VERSION 5.8 ;
BUSBITCHARS "[]" ;
DIVIDERCHAR "/" ;
UNITS
    DATABASE MICRONS 1000 ;
END UNITS

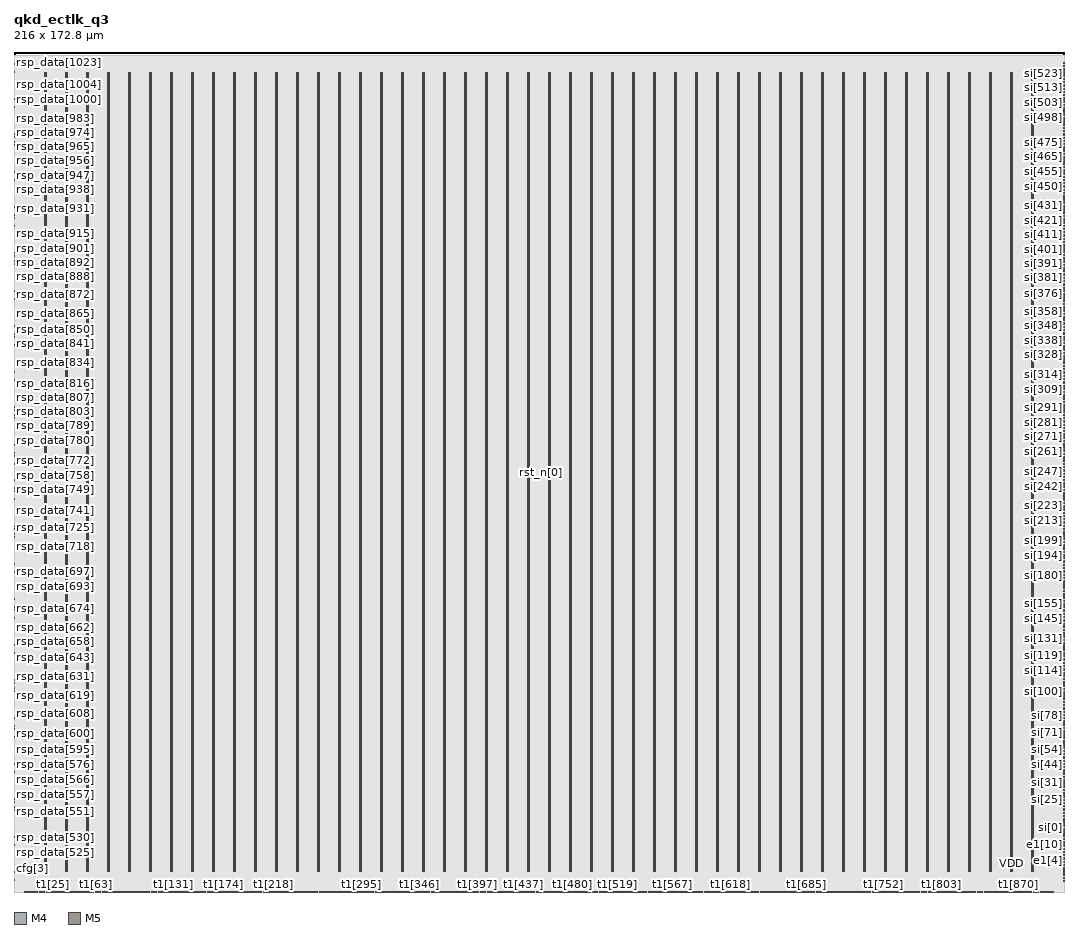
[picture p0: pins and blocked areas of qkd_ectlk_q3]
MACRO qkd_ectlk_q3
  FOREIGN qkd_ectlk_q3 0 0 ;
  CLASS BLOCK ;
  SIZE 216 BY 172.8 ;
  PIN cfg[0]
    DIRECTION INPUT ;
    USE SIGNAL ;
    PORT
      LAYER M4 ;
        RECT  0 2.172 0.192 2.196 ;
    END
  END cfg[0]
  PIN cfg[1]
    DIRECTION INPUT ;
    USE SIGNAL ;
    PORT
      LAYER M4 ;
        RECT  0 2.46 0.192 2.484 ;
    END
  END cfg[1]
  PIN cfg[2]
    DIRECTION INPUT ;
    USE SIGNAL ;
    PORT
      LAYER M4 ;
        RECT  0 2.796 0.192 2.82 ;
    END
  END cfg[2]
  PIN cfg[3]
    DIRECTION INPUT ;
    USE SIGNAL ;
    PORT
      LAYER M4 ;
        RECT  0 3.132 0.192 3.156 ;
    END
  END cfg[3]
  PIN cfg[4]
    DIRECTION INPUT ;
    USE SIGNAL ;
    PORT
      LAYER M4 ;
        RECT  0 3.468 0.192 3.492 ;
    END
  END cfg[4]
  PIN ck[0]
    DIRECTION INPUT ;
    USE SIGNAL ;
    PORT
      LAYER M5 ;
        RECT  108 86.16 108.048 86.64 ;
    END
  END ck[0]
  PIN e0[0]
    DIRECTION OUTPUT ;
    USE SIGNAL ;
    PORT
      LAYER M4 ;
        RECT  215.808 2.124 216 2.148 ;
    END
  END e0[0]
  PIN e0[10]
    DIRECTION OUTPUT ;
    USE SIGNAL ;
    PORT
      LAYER M4 ;
        RECT  215.808 5.1 216 5.124 ;
    END
  END e0[10]
  PIN e0[11]
    DIRECTION OUTPUT ;
    USE SIGNAL ;
    PORT
      LAYER M4 ;
        RECT  215.808 5.388 216 5.412 ;
    END
  END e0[11]
  PIN e0[12]
    DIRECTION OUTPUT ;
    USE SIGNAL ;
    PORT
      LAYER M4 ;
        RECT  215.808 5.676 216 5.7 ;
    END
  END e0[12]
  PIN e0[13]
    DIRECTION OUTPUT ;
    USE SIGNAL ;
    PORT
      LAYER M4 ;
        RECT  215.808 6.012 216 6.036 ;
    END
  END e0[13]
  PIN e0[14]
    DIRECTION OUTPUT ;
    USE SIGNAL ;
    PORT
      LAYER M4 ;
        RECT  215.808 6.3 216 6.324 ;
    END
  END e0[14]
  PIN e0[15]
    DIRECTION OUTPUT ;
    USE SIGNAL ;
    PORT
      LAYER M4 ;
        RECT  215.808 6.588 216 6.612 ;
    END
  END e0[15]
  PIN e0[1]
    DIRECTION OUTPUT ;
    USE SIGNAL ;
    PORT
      LAYER M4 ;
        RECT  215.808 2.412 216 2.436 ;
    END
  END e0[1]
  PIN e0[2]
    DIRECTION OUTPUT ;
    USE SIGNAL ;
    PORT
      LAYER M4 ;
        RECT  215.808 2.748 216 2.772 ;
    END
  END e0[2]
  PIN e0[3]
    DIRECTION OUTPUT ;
    USE SIGNAL ;
    PORT
      LAYER M4 ;
        RECT  215.808 3.036 216 3.06 ;
    END
  END e0[3]
  PIN e0[4]
    DIRECTION OUTPUT ;
    USE SIGNAL ;
    PORT
      LAYER M4 ;
        RECT  215.808 3.324 216 3.348 ;
    END
  END e0[4]
  PIN e0[5]
    DIRECTION OUTPUT ;
    USE SIGNAL ;
    PORT
      LAYER M4 ;
        RECT  215.808 3.612 216 3.636 ;
    END
  END e0[5]
  PIN e0[6]
    DIRECTION OUTPUT ;
    USE SIGNAL ;
    PORT
      LAYER M4 ;
        RECT  215.808 3.9 216 3.924 ;
    END
  END e0[6]
  PIN e0[7]
    DIRECTION OUTPUT ;
    USE SIGNAL ;
    PORT
      LAYER M4 ;
        RECT  215.808 4.236 216 4.26 ;
    END
  END e0[7]
  PIN e0[8]
    DIRECTION OUTPUT ;
    USE SIGNAL ;
    PORT
      LAYER M4 ;
        RECT  215.808 4.524 216 4.548 ;
    END
  END e0[8]
  PIN e0[9]
    DIRECTION OUTPUT ;
    USE SIGNAL ;
    PORT
      LAYER M4 ;
        RECT  215.808 4.812 216 4.836 ;
    END
  END e0[9]
  PIN e1[0]
    DIRECTION OUTPUT ;
    USE SIGNAL ;
    PORT
      LAYER M4 ;
        RECT  215.808 6.876 216 6.9 ;
    END
  END e1[0]
  PIN e1[10]
    DIRECTION OUTPUT ;
    USE SIGNAL ;
    PORT
      LAYER M4 ;
        RECT  215.808 9.852 216 9.876 ;
    END
  END e1[10]
  PIN e1[11]
    DIRECTION OUTPUT ;
    USE SIGNAL ;
    PORT
      LAYER M4 ;
        RECT  215.808 10.14 216 10.164 ;
    END
  END e1[11]
  PIN e1[12]
    DIRECTION OUTPUT ;
    USE SIGNAL ;
    PORT
      LAYER M4 ;
        RECT  215.808 10.428 216 10.452 ;
    END
  END e1[12]
  PIN e1[13]
    DIRECTION OUTPUT ;
    USE SIGNAL ;
    PORT
      LAYER M4 ;
        RECT  215.808 10.716 216 10.74 ;
    END
  END e1[13]
  PIN e1[14]
    DIRECTION OUTPUT ;
    USE SIGNAL ;
    PORT
      LAYER M4 ;
        RECT  215.808 11.052 216 11.076 ;
    END
  END e1[14]
  PIN e1[15]
    DIRECTION OUTPUT ;
    USE SIGNAL ;
    PORT
      LAYER M4 ;
        RECT  215.808 11.34 216 11.364 ;
    END
  END e1[15]
  PIN e1[1]
    DIRECTION OUTPUT ;
    USE SIGNAL ;
    PORT
      LAYER M4 ;
        RECT  215.808 7.164 216 7.188 ;
    END
  END e1[1]
  PIN e1[2]
    DIRECTION OUTPUT ;
    USE SIGNAL ;
    PORT
      LAYER M4 ;
        RECT  215.808 7.5 216 7.524 ;
    END
  END e1[2]
  PIN e1[3]
    DIRECTION OUTPUT ;
    USE SIGNAL ;
    PORT
      LAYER M4 ;
        RECT  215.808 7.788 216 7.812 ;
    END
  END e1[3]
  PIN e1[4]
    DIRECTION OUTPUT ;
    USE SIGNAL ;
    PORT
      LAYER M4 ;
        RECT  215.808 8.076 216 8.1 ;
    END
  END e1[4]
  PIN e1[5]
    DIRECTION OUTPUT ;
    USE SIGNAL ;
    PORT
      LAYER M4 ;
        RECT  215.808 8.364 216 8.388 ;
    END
  END e1[5]
  PIN e1[6]
    DIRECTION OUTPUT ;
    USE SIGNAL ;
    PORT
      LAYER M4 ;
        RECT  215.808 8.652 216 8.676 ;
    END
  END e1[6]
  PIN e1[7]
    DIRECTION OUTPUT ;
    USE SIGNAL ;
    PORT
      LAYER M4 ;
        RECT  215.808 8.94 216 8.964 ;
    END
  END e1[7]
  PIN e1[8]
    DIRECTION OUTPUT ;
    USE SIGNAL ;
    PORT
      LAYER M4 ;
        RECT  215.808 9.276 216 9.3 ;
    END
  END e1[8]
  PIN e1[9]
    DIRECTION OUTPUT ;
    USE SIGNAL ;
    PORT
      LAYER M4 ;
        RECT  215.808 9.564 216 9.588 ;
    END
  END e1[9]
  PIN rsp_data[1000]
    DIRECTION INPUT ;
    USE SIGNAL ;
    PORT
      LAYER M4 ;
        RECT  0 163.116 0.192 163.14 ;
    END
  END rsp_data[1000]
  PIN rsp_data[1001]
    DIRECTION INPUT ;
    USE SIGNAL ;
    PORT
      LAYER M4 ;
        RECT  0 163.452 0.192 163.476 ;
    END
  END rsp_data[1001]
  PIN rsp_data[1002]
    DIRECTION INPUT ;
    USE SIGNAL ;
    PORT
      LAYER M4 ;
        RECT  0 163.788 0.192 163.812 ;
    END
  END rsp_data[1002]
  PIN rsp_data[1003]
    DIRECTION INPUT ;
    USE SIGNAL ;
    PORT
      LAYER M4 ;
        RECT  0 164.076 0.192 164.1 ;
    END
  END rsp_data[1003]
  PIN rsp_data[1004]
    DIRECTION INPUT ;
    USE SIGNAL ;
    PORT
      LAYER M4 ;
        RECT  0 164.412 0.192 164.436 ;
    END
  END rsp_data[1004]
  PIN rsp_data[1005]
    DIRECTION INPUT ;
    USE SIGNAL ;
    PORT
      LAYER M4 ;
        RECT  0 164.748 0.192 164.772 ;
    END
  END rsp_data[1005]
  PIN rsp_data[1006]
    DIRECTION INPUT ;
    USE SIGNAL ;
    PORT
      LAYER M4 ;
        RECT  0 165.084 0.192 165.108 ;
    END
  END rsp_data[1006]
  PIN rsp_data[1007]
    DIRECTION INPUT ;
    USE SIGNAL ;
    PORT
      LAYER M4 ;
        RECT  0 165.42 0.192 165.444 ;
    END
  END rsp_data[1007]
  PIN rsp_data[1008]
    DIRECTION INPUT ;
    USE SIGNAL ;
    PORT
      LAYER M4 ;
        RECT  0 165.708 0.192 165.732 ;
    END
  END rsp_data[1008]
  PIN rsp_data[1009]
    DIRECTION INPUT ;
    USE SIGNAL ;
    PORT
      LAYER M4 ;
        RECT  0 166.044 0.192 166.068 ;
    END
  END rsp_data[1009]
  PIN rsp_data[1010]
    DIRECTION INPUT ;
    USE SIGNAL ;
    PORT
      LAYER M4 ;
        RECT  0 166.38 0.192 166.404 ;
    END
  END rsp_data[1010]
  PIN rsp_data[1011]
    DIRECTION INPUT ;
    USE SIGNAL ;
    PORT
      LAYER M4 ;
        RECT  0 166.716 0.192 166.74 ;
    END
  END rsp_data[1011]
  PIN rsp_data[1012]
    DIRECTION INPUT ;
    USE SIGNAL ;
    PORT
      LAYER M4 ;
        RECT  0 167.052 0.192 167.076 ;
    END
  END rsp_data[1012]
  PIN rsp_data[1013]
    DIRECTION INPUT ;
    USE SIGNAL ;
    PORT
      LAYER M4 ;
        RECT  0 167.34 0.192 167.364 ;
    END
  END rsp_data[1013]
  PIN rsp_data[1014]
    DIRECTION INPUT ;
    USE SIGNAL ;
    PORT
      LAYER M4 ;
        RECT  0 167.676 0.192 167.7 ;
    END
  END rsp_data[1014]
  PIN rsp_data[1015]
    DIRECTION INPUT ;
    USE SIGNAL ;
    PORT
      LAYER M4 ;
        RECT  0 168.012 0.192 168.036 ;
    END
  END rsp_data[1015]
  PIN rsp_data[1016]
    DIRECTION INPUT ;
    USE SIGNAL ;
    PORT
      LAYER M4 ;
        RECT  0 168.348 0.192 168.372 ;
    END
  END rsp_data[1016]
  PIN rsp_data[1017]
    DIRECTION INPUT ;
    USE SIGNAL ;
    PORT
      LAYER M4 ;
        RECT  0 168.684 0.192 168.708 ;
    END
  END rsp_data[1017]
  PIN rsp_data[1018]
    DIRECTION INPUT ;
    USE SIGNAL ;
    PORT
      LAYER M4 ;
        RECT  0 168.972 0.192 168.996 ;
    END
  END rsp_data[1018]
  PIN rsp_data[1019]
    DIRECTION INPUT ;
    USE SIGNAL ;
    PORT
      LAYER M4 ;
        RECT  0 169.308 0.192 169.332 ;
    END
  END rsp_data[1019]
  PIN rsp_data[1020]
    DIRECTION INPUT ;
    USE SIGNAL ;
    PORT
      LAYER M4 ;
        RECT  0 169.644 0.192 169.668 ;
    END
  END rsp_data[1020]
  PIN rsp_data[1021]
    DIRECTION INPUT ;
    USE SIGNAL ;
    PORT
      LAYER M4 ;
        RECT  0 169.98 0.192 170.004 ;
    END
  END rsp_data[1021]
  PIN rsp_data[1022]
    DIRECTION INPUT ;
    USE SIGNAL ;
    PORT
      LAYER M4 ;
        RECT  0 170.316 0.192 170.34 ;
    END
  END rsp_data[1022]
  PIN rsp_data[1023]
    DIRECTION INPUT ;
    USE SIGNAL ;
    PORT
      LAYER M4 ;
        RECT  0 170.604 0.192 170.628 ;
    END
  END rsp_data[1023]
  PIN rsp_data[512]
    DIRECTION INPUT ;
    USE SIGNAL ;
    PORT
      LAYER M4 ;
        RECT  0 3.804 0.192 3.828 ;
    END
  END rsp_data[512]
  PIN rsp_data[513]
    DIRECTION INPUT ;
    USE SIGNAL ;
    PORT
      LAYER M4 ;
        RECT  0 4.092 0.192 4.116 ;
    END
  END rsp_data[513]
  PIN rsp_data[514]
    DIRECTION INPUT ;
    USE SIGNAL ;
    PORT
      LAYER M4 ;
        RECT  0 4.428 0.192 4.452 ;
    END
  END rsp_data[514]
  PIN rsp_data[515]
    DIRECTION INPUT ;
    USE SIGNAL ;
    PORT
      LAYER M4 ;
        RECT  0 4.764 0.192 4.788 ;
    END
  END rsp_data[515]
  PIN rsp_data[516]
    DIRECTION INPUT ;
    USE SIGNAL ;
    PORT
      LAYER M4 ;
        RECT  0 5.1 0.192 5.124 ;
    END
  END rsp_data[516]
  PIN rsp_data[517]
    DIRECTION INPUT ;
    USE SIGNAL ;
    PORT
      LAYER M4 ;
        RECT  0 5.436 0.192 5.46 ;
    END
  END rsp_data[517]
  PIN rsp_data[518]
    DIRECTION INPUT ;
    USE SIGNAL ;
    PORT
      LAYER M4 ;
        RECT  0 5.724 0.192 5.748 ;
    END
  END rsp_data[518]
  PIN rsp_data[519]
    DIRECTION INPUT ;
    USE SIGNAL ;
    PORT
      LAYER M4 ;
        RECT  0 6.06 0.192 6.084 ;
    END
  END rsp_data[519]
  PIN rsp_data[520]
    DIRECTION INPUT ;
    USE SIGNAL ;
    PORT
      LAYER M4 ;
        RECT  0 6.396 0.192 6.42 ;
    END
  END rsp_data[520]
  PIN rsp_data[521]
    DIRECTION INPUT ;
    USE SIGNAL ;
    PORT
      LAYER M4 ;
        RECT  0 6.732 0.192 6.756 ;
    END
  END rsp_data[521]
  PIN rsp_data[522]
    DIRECTION INPUT ;
    USE SIGNAL ;
    PORT
      LAYER M4 ;
        RECT  0 7.068 0.192 7.092 ;
    END
  END rsp_data[522]
  PIN rsp_data[523]
    DIRECTION INPUT ;
    USE SIGNAL ;
    PORT
      LAYER M4 ;
        RECT  0 7.356 0.192 7.38 ;
    END
  END rsp_data[523]
  PIN rsp_data[524]
    DIRECTION INPUT ;
    USE SIGNAL ;
    PORT
      LAYER M4 ;
        RECT  0 7.692 0.192 7.716 ;
    END
  END rsp_data[524]
  PIN rsp_data[525]
    DIRECTION INPUT ;
    USE SIGNAL ;
    PORT
      LAYER M4 ;
        RECT  0 8.028 0.192 8.052 ;
    END
  END rsp_data[525]
  PIN rsp_data[526]
    DIRECTION INPUT ;
    USE SIGNAL ;
    PORT
      LAYER M4 ;
        RECT  0 8.364 0.192 8.388 ;
    END
  END rsp_data[526]
  PIN rsp_data[527]
    DIRECTION INPUT ;
    USE SIGNAL ;
    PORT
      LAYER M4 ;
        RECT  0 8.7 0.192 8.724 ;
    END
  END rsp_data[527]
  PIN rsp_data[528]
    DIRECTION INPUT ;
    USE SIGNAL ;
    PORT
      LAYER M4 ;
        RECT  0 8.988 0.192 9.012 ;
    END
  END rsp_data[528]
  PIN rsp_data[529]
    DIRECTION INPUT ;
    USE SIGNAL ;
    PORT
      LAYER M4 ;
        RECT  0 9.324 0.192 9.348 ;
    END
  END rsp_data[529]
  PIN rsp_data[530]
    DIRECTION INPUT ;
    USE SIGNAL ;
    PORT
      LAYER M4 ;
        RECT  0 9.66 0.192 9.684 ;
    END
  END rsp_data[530]
  PIN rsp_data[531]
    DIRECTION INPUT ;
    USE SIGNAL ;
    PORT
      LAYER M4 ;
        RECT  0 9.996 0.192 10.02 ;
    END
  END rsp_data[531]
  PIN rsp_data[532]
    DIRECTION INPUT ;
    USE SIGNAL ;
    PORT
      LAYER M4 ;
        RECT  0 10.332 0.192 10.356 ;
    END
  END rsp_data[532]
  PIN rsp_data[533]
    DIRECTION INPUT ;
    USE SIGNAL ;
    PORT
      LAYER M4 ;
        RECT  0 10.62 0.192 10.644 ;
    END
  END rsp_data[533]
  PIN rsp_data[534]
    DIRECTION INPUT ;
    USE SIGNAL ;
    PORT
      LAYER M4 ;
        RECT  0 10.956 0.192 10.98 ;
    END
  END rsp_data[534]
  PIN rsp_data[535]
    DIRECTION INPUT ;
    USE SIGNAL ;
    PORT
      LAYER M4 ;
        RECT  0 11.292 0.192 11.316 ;
    END
  END rsp_data[535]
  PIN rsp_data[536]
    DIRECTION INPUT ;
    USE SIGNAL ;
    PORT
      LAYER M4 ;
        RECT  0 11.628 0.192 11.652 ;
    END
  END rsp_data[536]
  PIN rsp_data[537]
    DIRECTION INPUT ;
    USE SIGNAL ;
    PORT
      LAYER M4 ;
        RECT  0 11.964 0.192 11.988 ;
    END
  END rsp_data[537]
  PIN rsp_data[538]
    DIRECTION INPUT ;
    USE SIGNAL ;
    PORT
      LAYER M4 ;
        RECT  0 12.252 0.192 12.276 ;
    END
  END rsp_data[538]
  PIN rsp_data[539]
    DIRECTION INPUT ;
    USE SIGNAL ;
    PORT
      LAYER M4 ;
        RECT  0 12.588 0.192 12.612 ;
    END
  END rsp_data[539]
  PIN rsp_data[540]
    DIRECTION INPUT ;
    USE SIGNAL ;
    PORT
      LAYER M4 ;
        RECT  0 12.924 0.192 12.948 ;
    END
  END rsp_data[540]
  PIN rsp_data[541]
    DIRECTION INPUT ;
    USE SIGNAL ;
    PORT
      LAYER M4 ;
        RECT  0 13.26 0.192 13.284 ;
    END
  END rsp_data[541]
  PIN rsp_data[542]
    DIRECTION INPUT ;
    USE SIGNAL ;
    PORT
      LAYER M4 ;
        RECT  0 13.596 0.192 13.62 ;
    END
  END rsp_data[542]
  PIN rsp_data[543]
    DIRECTION INPUT ;
    USE SIGNAL ;
    PORT
      LAYER M4 ;
        RECT  0 13.884 0.192 13.908 ;
    END
  END rsp_data[543]
  PIN rsp_data[544]
    DIRECTION INPUT ;
    USE SIGNAL ;
    PORT
      LAYER M4 ;
        RECT  0 14.22 0.192 14.244 ;
    END
  END rsp_data[544]
  PIN rsp_data[545]
    DIRECTION INPUT ;
    USE SIGNAL ;
    PORT
      LAYER M4 ;
        RECT  0 14.556 0.192 14.58 ;
    END
  END rsp_data[545]
  PIN rsp_data[546]
    DIRECTION INPUT ;
    USE SIGNAL ;
    PORT
      LAYER M4 ;
        RECT  0 14.892 0.192 14.916 ;
    END
  END rsp_data[546]
  PIN rsp_data[547]
    DIRECTION INPUT ;
    USE SIGNAL ;
    PORT
      LAYER M4 ;
        RECT  0 15.228 0.192 15.252 ;
    END
  END rsp_data[547]
  PIN rsp_data[548]
    DIRECTION INPUT ;
    USE SIGNAL ;
    PORT
      LAYER M4 ;
        RECT  0 15.516 0.192 15.54 ;
    END
  END rsp_data[548]
  PIN rsp_data[549]
    DIRECTION INPUT ;
    USE SIGNAL ;
    PORT
      LAYER M4 ;
        RECT  0 15.852 0.192 15.876 ;
    END
  END rsp_data[549]
  PIN rsp_data[550]
    DIRECTION INPUT ;
    USE SIGNAL ;
    PORT
      LAYER M4 ;
        RECT  0 16.188 0.192 16.212 ;
    END
  END rsp_data[550]
  PIN rsp_data[551]
    DIRECTION INPUT ;
    USE SIGNAL ;
    PORT
      LAYER M4 ;
        RECT  0 16.524 0.192 16.548 ;
    END
  END rsp_data[551]
  PIN rsp_data[552]
    DIRECTION INPUT ;
    USE SIGNAL ;
    PORT
      LAYER M4 ;
        RECT  0 16.86 0.192 16.884 ;
    END
  END rsp_data[552]
  PIN rsp_data[553]
    DIRECTION INPUT ;
    USE SIGNAL ;
    PORT
      LAYER M4 ;
        RECT  0 17.148 0.192 17.172 ;
    END
  END rsp_data[553]
  PIN rsp_data[554]
    DIRECTION INPUT ;
    USE SIGNAL ;
    PORT
      LAYER M4 ;
        RECT  0 17.484 0.192 17.508 ;
    END
  END rsp_data[554]
  PIN rsp_data[555]
    DIRECTION INPUT ;
    USE SIGNAL ;
    PORT
      LAYER M4 ;
        RECT  0 17.82 0.192 17.844 ;
    END
  END rsp_data[555]
  PIN rsp_data[556]
    DIRECTION INPUT ;
    USE SIGNAL ;
    PORT
      LAYER M4 ;
        RECT  0 18.156 0.192 18.18 ;
    END
  END rsp_data[556]
  PIN rsp_data[557]
    DIRECTION INPUT ;
    USE SIGNAL ;
    PORT
      LAYER M4 ;
        RECT  0 18.492 0.192 18.516 ;
    END
  END rsp_data[557]
  PIN rsp_data[558]
    DIRECTION INPUT ;
    USE SIGNAL ;
    PORT
      LAYER M4 ;
        RECT  0 18.78 0.192 18.804 ;
    END
  END rsp_data[558]
  PIN rsp_data[559]
    DIRECTION INPUT ;
    USE SIGNAL ;
    PORT
      LAYER M4 ;
        RECT  0 19.116 0.192 19.14 ;
    END
  END rsp_data[559]
  PIN rsp_data[560]
    DIRECTION INPUT ;
    USE SIGNAL ;
    PORT
      LAYER M4 ;
        RECT  0 19.452 0.192 19.476 ;
    END
  END rsp_data[560]
  PIN rsp_data[561]
    DIRECTION INPUT ;
    USE SIGNAL ;
    PORT
      LAYER M4 ;
        RECT  0 19.788 0.192 19.812 ;
    END
  END rsp_data[561]
  PIN rsp_data[562]
    DIRECTION INPUT ;
    USE SIGNAL ;
    PORT
      LAYER M4 ;
        RECT  0 20.124 0.192 20.148 ;
    END
  END rsp_data[562]
  PIN rsp_data[563]
    DIRECTION INPUT ;
    USE SIGNAL ;
    PORT
      LAYER M4 ;
        RECT  0 20.412 0.192 20.436 ;
    END
  END rsp_data[563]
  PIN rsp_data[564]
    DIRECTION INPUT ;
    USE SIGNAL ;
    PORT
      LAYER M4 ;
        RECT  0 20.748 0.192 20.772 ;
    END
  END rsp_data[564]
  PIN rsp_data[565]
    DIRECTION INPUT ;
    USE SIGNAL ;
    PORT
      LAYER M4 ;
        RECT  0 21.084 0.192 21.108 ;
    END
  END rsp_data[565]
  PIN rsp_data[566]
    DIRECTION INPUT ;
    USE SIGNAL ;
    PORT
      LAYER M4 ;
        RECT  0 21.42 0.192 21.444 ;
    END
  END rsp_data[566]
  PIN rsp_data[567]
    DIRECTION INPUT ;
    USE SIGNAL ;
    PORT
      LAYER M4 ;
        RECT  0 21.756 0.192 21.78 ;
    END
  END rsp_data[567]
  PIN rsp_data[568]
    DIRECTION INPUT ;
    USE SIGNAL ;
    PORT
      LAYER M4 ;
        RECT  0 22.044 0.192 22.068 ;
    END
  END rsp_data[568]
  PIN rsp_data[569]
    DIRECTION INPUT ;
    USE SIGNAL ;
    PORT
      LAYER M4 ;
        RECT  0 22.38 0.192 22.404 ;
    END
  END rsp_data[569]
  PIN rsp_data[570]
    DIRECTION INPUT ;
    USE SIGNAL ;
    PORT
      LAYER M4 ;
        RECT  0 22.716 0.192 22.74 ;
    END
  END rsp_data[570]
  PIN rsp_data[571]
    DIRECTION INPUT ;
    USE SIGNAL ;
    PORT
      LAYER M4 ;
        RECT  0 23.052 0.192 23.076 ;
    END
  END rsp_data[571]
  PIN rsp_data[572]
    DIRECTION INPUT ;
    USE SIGNAL ;
    PORT
      LAYER M4 ;
        RECT  0 23.388 0.192 23.412 ;
    END
  END rsp_data[572]
  PIN rsp_data[573]
    DIRECTION INPUT ;
    USE SIGNAL ;
    PORT
      LAYER M4 ;
        RECT  0 23.724 0.192 23.748 ;
    END
  END rsp_data[573]
  PIN rsp_data[574]
    DIRECTION INPUT ;
    USE SIGNAL ;
    PORT
      LAYER M4 ;
        RECT  0 24.012 0.192 24.036 ;
    END
  END rsp_data[574]
  PIN rsp_data[575]
    DIRECTION INPUT ;
    USE SIGNAL ;
    PORT
      LAYER M4 ;
        RECT  0 24.348 0.192 24.372 ;
    END
  END rsp_data[575]
  PIN rsp_data[576]
    DIRECTION INPUT ;
    USE SIGNAL ;
    PORT
      LAYER M4 ;
        RECT  0 24.684 0.192 24.708 ;
    END
  END rsp_data[576]
  PIN rsp_data[577]
    DIRECTION INPUT ;
    USE SIGNAL ;
    PORT
      LAYER M4 ;
        RECT  0 25.02 0.192 25.044 ;
    END
  END rsp_data[577]
  PIN rsp_data[578]
    DIRECTION INPUT ;
    USE SIGNAL ;
    PORT
      LAYER M4 ;
        RECT  0 25.356 0.192 25.38 ;
    END
  END rsp_data[578]
  PIN rsp_data[579]
    DIRECTION INPUT ;
    USE SIGNAL ;
    PORT
      LAYER M4 ;
        RECT  0 25.644 0.192 25.668 ;
    END
  END rsp_data[579]
  PIN rsp_data[580]
    DIRECTION INPUT ;
    USE SIGNAL ;
    PORT
      LAYER M4 ;
        RECT  0 25.98 0.192 26.004 ;
    END
  END rsp_data[580]
  PIN rsp_data[581]
    DIRECTION INPUT ;
    USE SIGNAL ;
    PORT
      LAYER M4 ;
        RECT  0 26.316 0.192 26.34 ;
    END
  END rsp_data[581]
  PIN rsp_data[582]
    DIRECTION INPUT ;
    USE SIGNAL ;
    PORT
      LAYER M4 ;
        RECT  0 26.652 0.192 26.676 ;
    END
  END rsp_data[582]
  PIN rsp_data[583]
    DIRECTION INPUT ;
    USE SIGNAL ;
    PORT
      LAYER M4 ;
        RECT  0 26.988 0.192 27.012 ;
    END
  END rsp_data[583]
  PIN rsp_data[584]
    DIRECTION INPUT ;
    USE SIGNAL ;
    PORT
      LAYER M4 ;
        RECT  0 27.276 0.192 27.3 ;
    END
  END rsp_data[584]
  PIN rsp_data[585]
    DIRECTION INPUT ;
    USE SIGNAL ;
    PORT
      LAYER M4 ;
        RECT  0 27.612 0.192 27.636 ;
    END
  END rsp_data[585]
  PIN rsp_data[586]
    DIRECTION INPUT ;
    USE SIGNAL ;
    PORT
      LAYER M4 ;
        RECT  0 27.948 0.192 27.972 ;
    END
  END rsp_data[586]
  PIN rsp_data[587]
    DIRECTION INPUT ;
    USE SIGNAL ;
    PORT
      LAYER M4 ;
        RECT  0 28.284 0.192 28.308 ;
    END
  END rsp_data[587]
  PIN rsp_data[588]
    DIRECTION INPUT ;
    USE SIGNAL ;
    PORT
      LAYER M4 ;
        RECT  0 28.62 0.192 28.644 ;
    END
  END rsp_data[588]
  PIN rsp_data[589]
    DIRECTION INPUT ;
    USE SIGNAL ;
    PORT
      LAYER M4 ;
        RECT  0 28.908 0.192 28.932 ;
    END
  END rsp_data[589]
  PIN rsp_data[590]
    DIRECTION INPUT ;
    USE SIGNAL ;
    PORT
      LAYER M4 ;
        RECT  0 29.244 0.192 29.268 ;
    END
  END rsp_data[590]
  PIN rsp_data[591]
    DIRECTION INPUT ;
    USE SIGNAL ;
    PORT
      LAYER M4 ;
        RECT  0 29.58 0.192 29.604 ;
    END
  END rsp_data[591]
  PIN rsp_data[592]
    DIRECTION INPUT ;
    USE SIGNAL ;
    PORT
      LAYER M4 ;
        RECT  0 29.916 0.192 29.94 ;
    END
  END rsp_data[592]
  PIN rsp_data[593]
    DIRECTION INPUT ;
    USE SIGNAL ;
    PORT
      LAYER M4 ;
        RECT  0 30.252 0.192 30.276 ;
    END
  END rsp_data[593]
  PIN rsp_data[594]
    DIRECTION INPUT ;
    USE SIGNAL ;
    PORT
      LAYER M4 ;
        RECT  0 30.54 0.192 30.564 ;
    END
  END rsp_data[594]
  PIN rsp_data[595]
    DIRECTION INPUT ;
    USE SIGNAL ;
    PORT
      LAYER M4 ;
        RECT  0 30.876 0.192 30.9 ;
    END
  END rsp_data[595]
  PIN rsp_data[596]
    DIRECTION INPUT ;
    USE SIGNAL ;
    PORT
      LAYER M4 ;
        RECT  0 31.212 0.192 31.236 ;
    END
  END rsp_data[596]
  PIN rsp_data[597]
    DIRECTION INPUT ;
    USE SIGNAL ;
    PORT
      LAYER M4 ;
        RECT  0 31.548 0.192 31.572 ;
    END
  END rsp_data[597]
  PIN rsp_data[598]
    DIRECTION INPUT ;
    USE SIGNAL ;
    PORT
      LAYER M4 ;
        RECT  0 31.884 0.192 31.908 ;
    END
  END rsp_data[598]
  PIN rsp_data[599]
    DIRECTION INPUT ;
    USE SIGNAL ;
    PORT
      LAYER M4 ;
        RECT  0 32.172 0.192 32.196 ;
    END
  END rsp_data[599]
  PIN rsp_data[600]
    DIRECTION INPUT ;
    USE SIGNAL ;
    PORT
      LAYER M4 ;
        RECT  0 32.508 0.192 32.532 ;
    END
  END rsp_data[600]
  PIN rsp_data[601]
    DIRECTION INPUT ;
    USE SIGNAL ;
    PORT
      LAYER M4 ;
        RECT  0 32.844 0.192 32.868 ;
    END
  END rsp_data[601]
  PIN rsp_data[602]
    DIRECTION INPUT ;
    USE SIGNAL ;
    PORT
      LAYER M4 ;
        RECT  0 33.18 0.192 33.204 ;
    END
  END rsp_data[602]
  PIN rsp_data[603]
    DIRECTION INPUT ;
    USE SIGNAL ;
    PORT
      LAYER M4 ;
        RECT  0 33.516 0.192 33.54 ;
    END
  END rsp_data[603]
  PIN rsp_data[604]
    DIRECTION INPUT ;
    USE SIGNAL ;
    PORT
      LAYER M4 ;
        RECT  0 33.804 0.192 33.828 ;
    END
  END rsp_data[604]
  PIN rsp_data[605]
    DIRECTION INPUT ;
    USE SIGNAL ;
    PORT
      LAYER M4 ;
        RECT  0 34.14 0.192 34.164 ;
    END
  END rsp_data[605]
  PIN rsp_data[606]
    DIRECTION INPUT ;
    USE SIGNAL ;
    PORT
      LAYER M4 ;
        RECT  0 34.476 0.192 34.5 ;
    END
  END rsp_data[606]
  PIN rsp_data[607]
    DIRECTION INPUT ;
    USE SIGNAL ;
    PORT
      LAYER M4 ;
        RECT  0 34.812 0.192 34.836 ;
    END
  END rsp_data[607]
  PIN rsp_data[608]
    DIRECTION INPUT ;
    USE SIGNAL ;
    PORT
      LAYER M4 ;
        RECT  0 35.148 0.192 35.172 ;
    END
  END rsp_data[608]
  PIN rsp_data[609]
    DIRECTION INPUT ;
    USE SIGNAL ;
    PORT
      LAYER M4 ;
        RECT  0 35.436 0.192 35.46 ;
    END
  END rsp_data[609]
  PIN rsp_data[610]
    DIRECTION INPUT ;
    USE SIGNAL ;
    PORT
      LAYER M4 ;
        RECT  0 35.772 0.192 35.796 ;
    END
  END rsp_data[610]
  PIN rsp_data[611]
    DIRECTION INPUT ;
    USE SIGNAL ;
    PORT
      LAYER M4 ;
        RECT  0 36.108 0.192 36.132 ;
    END
  END rsp_data[611]
  PIN rsp_data[612]
    DIRECTION INPUT ;
    USE SIGNAL ;
    PORT
      LAYER M4 ;
        RECT  0 36.444 0.192 36.468 ;
    END
  END rsp_data[612]
  PIN rsp_data[613]
    DIRECTION INPUT ;
    USE SIGNAL ;
    PORT
      LAYER M4 ;
        RECT  0 36.78 0.192 36.804 ;
    END
  END rsp_data[613]
  PIN rsp_data[614]
    DIRECTION INPUT ;
    USE SIGNAL ;
    PORT
      LAYER M4 ;
        RECT  0 37.068 0.192 37.092 ;
    END
  END rsp_data[614]
  PIN rsp_data[615]
    DIRECTION INPUT ;
    USE SIGNAL ;
    PORT
      LAYER M4 ;
        RECT  0 37.404 0.192 37.428 ;
    END
  END rsp_data[615]
  PIN rsp_data[616]
    DIRECTION INPUT ;
    USE SIGNAL ;
    PORT
      LAYER M4 ;
        RECT  0 37.74 0.192 37.764 ;
    END
  END rsp_data[616]
  PIN rsp_data[617]
    DIRECTION INPUT ;
    USE SIGNAL ;
    PORT
      LAYER M4 ;
        RECT  0 38.076 0.192 38.1 ;
    END
  END rsp_data[617]
  PIN rsp_data[618]
    DIRECTION INPUT ;
    USE SIGNAL ;
    PORT
      LAYER M4 ;
        RECT  0 38.412 0.192 38.436 ;
    END
  END rsp_data[618]
  PIN rsp_data[619]
    DIRECTION INPUT ;
    USE SIGNAL ;
    PORT
      LAYER M4 ;
        RECT  0 38.7 0.192 38.724 ;
    END
  END rsp_data[619]
  PIN rsp_data[620]
    DIRECTION INPUT ;
    USE SIGNAL ;
    PORT
      LAYER M4 ;
        RECT  0 39.036 0.192 39.06 ;
    END
  END rsp_data[620]
  PIN rsp_data[621]
    DIRECTION INPUT ;
    USE SIGNAL ;
    PORT
      LAYER M4 ;
        RECT  0 39.372 0.192 39.396 ;
    END
  END rsp_data[621]
  PIN rsp_data[622]
    DIRECTION INPUT ;
    USE SIGNAL ;
    PORT
      LAYER M4 ;
        RECT  0 39.708 0.192 39.732 ;
    END
  END rsp_data[622]
  PIN rsp_data[623]
    DIRECTION INPUT ;
    USE SIGNAL ;
    PORT
      LAYER M4 ;
        RECT  0 40.044 0.192 40.068 ;
    END
  END rsp_data[623]
  PIN rsp_data[624]
    DIRECTION INPUT ;
    USE SIGNAL ;
    PORT
      LAYER M4 ;
        RECT  0 40.332 0.192 40.356 ;
    END
  END rsp_data[624]
  PIN rsp_data[625]
    DIRECTION INPUT ;
    USE SIGNAL ;
    PORT
      LAYER M4 ;
        RECT  0 40.668 0.192 40.692 ;
    END
  END rsp_data[625]
  PIN rsp_data[626]
    DIRECTION INPUT ;
    USE SIGNAL ;
    PORT
      LAYER M4 ;
        RECT  0 41.004 0.192 41.028 ;
    END
  END rsp_data[626]
  PIN rsp_data[627]
    DIRECTION INPUT ;
    USE SIGNAL ;
    PORT
      LAYER M4 ;
        RECT  0 41.34 0.192 41.364 ;
    END
  END rsp_data[627]
  PIN rsp_data[628]
    DIRECTION INPUT ;
    USE SIGNAL ;
    PORT
      LAYER M4 ;
        RECT  0 41.676 0.192 41.7 ;
    END
  END rsp_data[628]
  PIN rsp_data[629]
    DIRECTION INPUT ;
    USE SIGNAL ;
    PORT
      LAYER M4 ;
        RECT  0 41.964 0.192 41.988 ;
    END
  END rsp_data[629]
  PIN rsp_data[630]
    DIRECTION INPUT ;
    USE SIGNAL ;
    PORT
      LAYER M4 ;
        RECT  0 42.3 0.192 42.324 ;
    END
  END rsp_data[630]
  PIN rsp_data[631]
    DIRECTION INPUT ;
    USE SIGNAL ;
    PORT
      LAYER M4 ;
        RECT  0 42.636 0.192 42.66 ;
    END
  END rsp_data[631]
  PIN rsp_data[632]
    DIRECTION INPUT ;
    USE SIGNAL ;
    PORT
      LAYER M4 ;
        RECT  0 42.972 0.192 42.996 ;
    END
  END rsp_data[632]
  PIN rsp_data[633]
    DIRECTION INPUT ;
    USE SIGNAL ;
    PORT
      LAYER M4 ;
        RECT  0 43.308 0.192 43.332 ;
    END
  END rsp_data[633]
  PIN rsp_data[634]
    DIRECTION INPUT ;
    USE SIGNAL ;
    PORT
      LAYER M4 ;
        RECT  0 43.596 0.192 43.62 ;
    END
  END rsp_data[634]
  PIN rsp_data[635]
    DIRECTION INPUT ;
    USE SIGNAL ;
    PORT
      LAYER M4 ;
        RECT  0 43.932 0.192 43.956 ;
    END
  END rsp_data[635]
  PIN rsp_data[636]
    DIRECTION INPUT ;
    USE SIGNAL ;
    PORT
      LAYER M4 ;
        RECT  0 44.268 0.192 44.292 ;
    END
  END rsp_data[636]
  PIN rsp_data[637]
    DIRECTION INPUT ;
    USE SIGNAL ;
    PORT
      LAYER M4 ;
        RECT  0 44.604 0.192 44.628 ;
    END
  END rsp_data[637]
  PIN rsp_data[638]
    DIRECTION INPUT ;
    USE SIGNAL ;
    PORT
      LAYER M4 ;
        RECT  0 44.94 0.192 44.964 ;
    END
  END rsp_data[638]
  PIN rsp_data[639]
    DIRECTION INPUT ;
    USE SIGNAL ;
    PORT
      LAYER M4 ;
        RECT  0 45.228 0.192 45.252 ;
    END
  END rsp_data[639]
  PIN rsp_data[640]
    DIRECTION INPUT ;
    USE SIGNAL ;
    PORT
      LAYER M4 ;
        RECT  0 45.564 0.192 45.588 ;
    END
  END rsp_data[640]
  PIN rsp_data[641]
    DIRECTION INPUT ;
    USE SIGNAL ;
    PORT
      LAYER M4 ;
        RECT  0 45.9 0.192 45.924 ;
    END
  END rsp_data[641]
  PIN rsp_data[642]
    DIRECTION INPUT ;
    USE SIGNAL ;
    PORT
      LAYER M4 ;
        RECT  0 46.236 0.192 46.26 ;
    END
  END rsp_data[642]
  PIN rsp_data[643]
    DIRECTION INPUT ;
    USE SIGNAL ;
    PORT
      LAYER M4 ;
        RECT  0 46.572 0.192 46.596 ;
    END
  END rsp_data[643]
  PIN rsp_data[644]
    DIRECTION INPUT ;
    USE SIGNAL ;
    PORT
      LAYER M4 ;
        RECT  0 46.86 0.192 46.884 ;
    END
  END rsp_data[644]
  PIN rsp_data[645]
    DIRECTION INPUT ;
    USE SIGNAL ;
    PORT
      LAYER M4 ;
        RECT  0 47.196 0.192 47.22 ;
    END
  END rsp_data[645]
  PIN rsp_data[646]
    DIRECTION INPUT ;
    USE SIGNAL ;
    PORT
      LAYER M4 ;
        RECT  0 47.532 0.192 47.556 ;
    END
  END rsp_data[646]
  PIN rsp_data[647]
    DIRECTION INPUT ;
    USE SIGNAL ;
    PORT
      LAYER M4 ;
        RECT  0 47.868 0.192 47.892 ;
    END
  END rsp_data[647]
  PIN rsp_data[648]
    DIRECTION INPUT ;
    USE SIGNAL ;
    PORT
      LAYER M4 ;
        RECT  0 48.204 0.192 48.228 ;
    END
  END rsp_data[648]
  PIN rsp_data[649]
    DIRECTION INPUT ;
    USE SIGNAL ;
    PORT
      LAYER M4 ;
        RECT  0 48.492 0.192 48.516 ;
    END
  END rsp_data[649]
  PIN rsp_data[650]
    DIRECTION INPUT ;
    USE SIGNAL ;
    PORT
      LAYER M4 ;
        RECT  0 48.828 0.192 48.852 ;
    END
  END rsp_data[650]
  PIN rsp_data[651]
    DIRECTION INPUT ;
    USE SIGNAL ;
    PORT
      LAYER M4 ;
        RECT  0 49.164 0.192 49.188 ;
    END
  END rsp_data[651]
  PIN rsp_data[652]
    DIRECTION INPUT ;
    USE SIGNAL ;
    PORT
      LAYER M4 ;
        RECT  0 49.5 0.192 49.524 ;
    END
  END rsp_data[652]
  PIN rsp_data[653]
    DIRECTION INPUT ;
    USE SIGNAL ;
    PORT
      LAYER M4 ;
        RECT  0 49.836 0.192 49.86 ;
    END
  END rsp_data[653]
  PIN rsp_data[654]
    DIRECTION INPUT ;
    USE SIGNAL ;
    PORT
      LAYER M4 ;
        RECT  0 50.124 0.192 50.148 ;
    END
  END rsp_data[654]
  PIN rsp_data[655]
    DIRECTION INPUT ;
    USE SIGNAL ;
    PORT
      LAYER M4 ;
        RECT  0 50.46 0.192 50.484 ;
    END
  END rsp_data[655]
  PIN rsp_data[656]
    DIRECTION INPUT ;
    USE SIGNAL ;
    PORT
      LAYER M4 ;
        RECT  0 50.796 0.192 50.82 ;
    END
  END rsp_data[656]
  PIN rsp_data[657]
    DIRECTION INPUT ;
    USE SIGNAL ;
    PORT
      LAYER M4 ;
        RECT  0 51.132 0.192 51.156 ;
    END
  END rsp_data[657]
  PIN rsp_data[658]
    DIRECTION INPUT ;
    USE SIGNAL ;
    PORT
      LAYER M4 ;
        RECT  0 51.468 0.192 51.492 ;
    END
  END rsp_data[658]
  PIN rsp_data[659]
    DIRECTION INPUT ;
    USE SIGNAL ;
    PORT
      LAYER M4 ;
        RECT  0 51.756 0.192 51.78 ;
    END
  END rsp_data[659]
  PIN rsp_data[660]
    DIRECTION INPUT ;
    USE SIGNAL ;
    PORT
      LAYER M4 ;
        RECT  0 52.092 0.192 52.116 ;
    END
  END rsp_data[660]
  PIN rsp_data[661]
    DIRECTION INPUT ;
    USE SIGNAL ;
    PORT
      LAYER M4 ;
        RECT  0 52.428 0.192 52.452 ;
    END
  END rsp_data[661]
  PIN rsp_data[662]
    DIRECTION INPUT ;
    USE SIGNAL ;
    PORT
      LAYER M4 ;
        RECT  0 52.764 0.192 52.788 ;
    END
  END rsp_data[662]
  PIN rsp_data[663]
    DIRECTION INPUT ;
    USE SIGNAL ;
    PORT
      LAYER M4 ;
        RECT  0 53.1 0.192 53.124 ;
    END
  END rsp_data[663]
  PIN rsp_data[664]
    DIRECTION INPUT ;
    USE SIGNAL ;
    PORT
      LAYER M4 ;
        RECT  0 53.388 0.192 53.412 ;
    END
  END rsp_data[664]
  PIN rsp_data[665]
    DIRECTION INPUT ;
    USE SIGNAL ;
    PORT
      LAYER M4 ;
        RECT  0 53.724 0.192 53.748 ;
    END
  END rsp_data[665]
  PIN rsp_data[666]
    DIRECTION INPUT ;
    USE SIGNAL ;
    PORT
      LAYER M4 ;
        RECT  0 54.06 0.192 54.084 ;
    END
  END rsp_data[666]
  PIN rsp_data[667]
    DIRECTION INPUT ;
    USE SIGNAL ;
    PORT
      LAYER M4 ;
        RECT  0 54.396 0.192 54.42 ;
    END
  END rsp_data[667]
  PIN rsp_data[668]
    DIRECTION INPUT ;
    USE SIGNAL ;
    PORT
      LAYER M4 ;
        RECT  0 54.732 0.192 54.756 ;
    END
  END rsp_data[668]
  PIN rsp_data[669]
    DIRECTION INPUT ;
    USE SIGNAL ;
    PORT
      LAYER M4 ;
        RECT  0 55.068 0.192 55.092 ;
    END
  END rsp_data[669]
  PIN rsp_data[670]
    DIRECTION INPUT ;
    USE SIGNAL ;
    PORT
      LAYER M4 ;
        RECT  0 55.356 0.192 55.38 ;
    END
  END rsp_data[670]
  PIN rsp_data[671]
    DIRECTION INPUT ;
    USE SIGNAL ;
    PORT
      LAYER M4 ;
        RECT  0 55.692 0.192 55.716 ;
    END
  END rsp_data[671]
  PIN rsp_data[672]
    DIRECTION INPUT ;
    USE SIGNAL ;
    PORT
      LAYER M4 ;
        RECT  0 56.028 0.192 56.052 ;
    END
  END rsp_data[672]
  PIN rsp_data[673]
    DIRECTION INPUT ;
    USE SIGNAL ;
    PORT
      LAYER M4 ;
        RECT  0 56.364 0.192 56.388 ;
    END
  END rsp_data[673]
  PIN rsp_data[674]
    DIRECTION INPUT ;
    USE SIGNAL ;
    PORT
      LAYER M4 ;
        RECT  0 56.7 0.192 56.724 ;
    END
  END rsp_data[674]
  PIN rsp_data[675]
    DIRECTION INPUT ;
    USE SIGNAL ;
    PORT
      LAYER M4 ;
        RECT  0 56.988 0.192 57.012 ;
    END
  END rsp_data[675]
  PIN rsp_data[676]
    DIRECTION INPUT ;
    USE SIGNAL ;
    PORT
      LAYER M4 ;
        RECT  0 57.324 0.192 57.348 ;
    END
  END rsp_data[676]
  PIN rsp_data[677]
    DIRECTION INPUT ;
    USE SIGNAL ;
    PORT
      LAYER M4 ;
        RECT  0 57.66 0.192 57.684 ;
    END
  END rsp_data[677]
  PIN rsp_data[678]
    DIRECTION INPUT ;
    USE SIGNAL ;
    PORT
      LAYER M4 ;
        RECT  0 57.996 0.192 58.02 ;
    END
  END rsp_data[678]
  PIN rsp_data[679]
    DIRECTION INPUT ;
    USE SIGNAL ;
    PORT
      LAYER M4 ;
        RECT  0 58.332 0.192 58.356 ;
    END
  END rsp_data[679]
  PIN rsp_data[680]
    DIRECTION INPUT ;
    USE SIGNAL ;
    PORT
      LAYER M4 ;
        RECT  0 58.62 0.192 58.644 ;
    END
  END rsp_data[680]
  PIN rsp_data[681]
    DIRECTION INPUT ;
    USE SIGNAL ;
    PORT
      LAYER M4 ;
        RECT  0 58.956 0.192 58.98 ;
    END
  END rsp_data[681]
  PIN rsp_data[682]
    DIRECTION INPUT ;
    USE SIGNAL ;
    PORT
      LAYER M4 ;
        RECT  0 59.292 0.192 59.316 ;
    END
  END rsp_data[682]
  PIN rsp_data[683]
    DIRECTION INPUT ;
    USE SIGNAL ;
    PORT
      LAYER M4 ;
        RECT  0 59.628 0.192 59.652 ;
    END
  END rsp_data[683]
  PIN rsp_data[684]
    DIRECTION INPUT ;
    USE SIGNAL ;
    PORT
      LAYER M4 ;
        RECT  0 59.964 0.192 59.988 ;
    END
  END rsp_data[684]
  PIN rsp_data[685]
    DIRECTION INPUT ;
    USE SIGNAL ;
    PORT
      LAYER M4 ;
        RECT  0 60.252 0.192 60.276 ;
    END
  END rsp_data[685]
  PIN rsp_data[686]
    DIRECTION INPUT ;
    USE SIGNAL ;
    PORT
      LAYER M4 ;
        RECT  0 60.588 0.192 60.612 ;
    END
  END rsp_data[686]
  PIN rsp_data[687]
    DIRECTION INPUT ;
    USE SIGNAL ;
    PORT
      LAYER M4 ;
        RECT  0 60.924 0.192 60.948 ;
    END
  END rsp_data[687]
  PIN rsp_data[688]
    DIRECTION INPUT ;
    USE SIGNAL ;
    PORT
      LAYER M4 ;
        RECT  0 61.26 0.192 61.284 ;
    END
  END rsp_data[688]
  PIN rsp_data[689]
    DIRECTION INPUT ;
    USE SIGNAL ;
    PORT
      LAYER M4 ;
        RECT  0 61.596 0.192 61.62 ;
    END
  END rsp_data[689]
  PIN rsp_data[690]
    DIRECTION INPUT ;
    USE SIGNAL ;
    PORT
      LAYER M4 ;
        RECT  0 61.884 0.192 61.908 ;
    END
  END rsp_data[690]
  PIN rsp_data[691]
    DIRECTION INPUT ;
    USE SIGNAL ;
    PORT
      LAYER M4 ;
        RECT  0 62.22 0.192 62.244 ;
    END
  END rsp_data[691]
  PIN rsp_data[692]
    DIRECTION INPUT ;
    USE SIGNAL ;
    PORT
      LAYER M4 ;
        RECT  0 62.556 0.192 62.58 ;
    END
  END rsp_data[692]
  PIN rsp_data[693]
    DIRECTION INPUT ;
    USE SIGNAL ;
    PORT
      LAYER M4 ;
        RECT  0 62.892 0.192 62.916 ;
    END
  END rsp_data[693]
  PIN rsp_data[694]
    DIRECTION INPUT ;
    USE SIGNAL ;
    PORT
      LAYER M4 ;
        RECT  0 63.228 0.192 63.252 ;
    END
  END rsp_data[694]
  PIN rsp_data[695]
    DIRECTION INPUT ;
    USE SIGNAL ;
    PORT
      LAYER M4 ;
        RECT  0 63.516 0.192 63.54 ;
    END
  END rsp_data[695]
  PIN rsp_data[696]
    DIRECTION INPUT ;
    USE SIGNAL ;
    PORT
      LAYER M4 ;
        RECT  0 63.852 0.192 63.876 ;
    END
  END rsp_data[696]
  PIN rsp_data[697]
    DIRECTION INPUT ;
    USE SIGNAL ;
    PORT
      LAYER M4 ;
        RECT  0 64.188 0.192 64.212 ;
    END
  END rsp_data[697]
  PIN rsp_data[698]
    DIRECTION INPUT ;
    USE SIGNAL ;
    PORT
      LAYER M4 ;
        RECT  0 64.524 0.192 64.548 ;
    END
  END rsp_data[698]
  PIN rsp_data[699]
    DIRECTION INPUT ;
    USE SIGNAL ;
    PORT
      LAYER M4 ;
        RECT  0 64.86 0.192 64.884 ;
    END
  END rsp_data[699]
  PIN rsp_data[700]
    DIRECTION INPUT ;
    USE SIGNAL ;
    PORT
      LAYER M4 ;
        RECT  0 65.148 0.192 65.172 ;
    END
  END rsp_data[700]
  PIN rsp_data[701]
    DIRECTION INPUT ;
    USE SIGNAL ;
    PORT
      LAYER M4 ;
        RECT  0 65.484 0.192 65.508 ;
    END
  END rsp_data[701]
  PIN rsp_data[702]
    DIRECTION INPUT ;
    USE SIGNAL ;
    PORT
      LAYER M4 ;
        RECT  0 65.82 0.192 65.844 ;
    END
  END rsp_data[702]
  PIN rsp_data[703]
    DIRECTION INPUT ;
    USE SIGNAL ;
    PORT
      LAYER M4 ;
        RECT  0 66.156 0.192 66.18 ;
    END
  END rsp_data[703]
  PIN rsp_data[704]
    DIRECTION INPUT ;
    USE SIGNAL ;
    PORT
      LAYER M4 ;
        RECT  0 66.492 0.192 66.516 ;
    END
  END rsp_data[704]
  PIN rsp_data[705]
    DIRECTION INPUT ;
    USE SIGNAL ;
    PORT
      LAYER M4 ;
        RECT  0 66.78 0.192 66.804 ;
    END
  END rsp_data[705]
  PIN rsp_data[706]
    DIRECTION INPUT ;
    USE SIGNAL ;
    PORT
      LAYER M4 ;
        RECT  0 67.116 0.192 67.14 ;
    END
  END rsp_data[706]
  PIN rsp_data[707]
    DIRECTION INPUT ;
    USE SIGNAL ;
    PORT
      LAYER M4 ;
        RECT  0 67.452 0.192 67.476 ;
    END
  END rsp_data[707]
  PIN rsp_data[708]
    DIRECTION INPUT ;
    USE SIGNAL ;
    PORT
      LAYER M4 ;
        RECT  0 67.788 0.192 67.812 ;
    END
  END rsp_data[708]
  PIN rsp_data[709]
    DIRECTION INPUT ;
    USE SIGNAL ;
    PORT
      LAYER M4 ;
        RECT  0 68.124 0.192 68.148 ;
    END
  END rsp_data[709]
  PIN rsp_data[710]
    DIRECTION INPUT ;
    USE SIGNAL ;
    PORT
      LAYER M4 ;
        RECT  0 68.412 0.192 68.436 ;
    END
  END rsp_data[710]
  PIN rsp_data[711]
    DIRECTION INPUT ;
    USE SIGNAL ;
    PORT
      LAYER M4 ;
        RECT  0 68.748 0.192 68.772 ;
    END
  END rsp_data[711]
  PIN rsp_data[712]
    DIRECTION INPUT ;
    USE SIGNAL ;
    PORT
      LAYER M4 ;
        RECT  0 69.084 0.192 69.108 ;
    END
  END rsp_data[712]
  PIN rsp_data[713]
    DIRECTION INPUT ;
    USE SIGNAL ;
    PORT
      LAYER M4 ;
        RECT  0 69.42 0.192 69.444 ;
    END
  END rsp_data[713]
  PIN rsp_data[714]
    DIRECTION INPUT ;
    USE SIGNAL ;
    PORT
      LAYER M4 ;
        RECT  0 69.756 0.192 69.78 ;
    END
  END rsp_data[714]
  PIN rsp_data[715]
    DIRECTION INPUT ;
    USE SIGNAL ;
    PORT
      LAYER M4 ;
        RECT  0 70.044 0.192 70.068 ;
    END
  END rsp_data[715]
  PIN rsp_data[716]
    DIRECTION INPUT ;
    USE SIGNAL ;
    PORT
      LAYER M4 ;
        RECT  0 70.38 0.192 70.404 ;
    END
  END rsp_data[716]
  PIN rsp_data[717]
    DIRECTION INPUT ;
    USE SIGNAL ;
    PORT
      LAYER M4 ;
        RECT  0 70.716 0.192 70.74 ;
    END
  END rsp_data[717]
  PIN rsp_data[718]
    DIRECTION INPUT ;
    USE SIGNAL ;
    PORT
      LAYER M4 ;
        RECT  0 71.052 0.192 71.076 ;
    END
  END rsp_data[718]
  PIN rsp_data[719]
    DIRECTION INPUT ;
    USE SIGNAL ;
    PORT
      LAYER M4 ;
        RECT  0 71.388 0.192 71.412 ;
    END
  END rsp_data[719]
  PIN rsp_data[720]
    DIRECTION INPUT ;
    USE SIGNAL ;
    PORT
      LAYER M4 ;
        RECT  0 71.676 0.192 71.7 ;
    END
  END rsp_data[720]
  PIN rsp_data[721]
    DIRECTION INPUT ;
    USE SIGNAL ;
    PORT
      LAYER M4 ;
        RECT  0 72.012 0.192 72.036 ;
    END
  END rsp_data[721]
  PIN rsp_data[722]
    DIRECTION INPUT ;
    USE SIGNAL ;
    PORT
      LAYER M4 ;
        RECT  0 72.348 0.192 72.372 ;
    END
  END rsp_data[722]
  PIN rsp_data[723]
    DIRECTION INPUT ;
    USE SIGNAL ;
    PORT
      LAYER M4 ;
        RECT  0 72.684 0.192 72.708 ;
    END
  END rsp_data[723]
  PIN rsp_data[724]
    DIRECTION INPUT ;
    USE SIGNAL ;
    PORT
      LAYER M4 ;
        RECT  0 73.02 0.192 73.044 ;
    END
  END rsp_data[724]
  PIN rsp_data[725]
    DIRECTION INPUT ;
    USE SIGNAL ;
    PORT
      LAYER M4 ;
        RECT  0 73.308 0.192 73.332 ;
    END
  END rsp_data[725]
  PIN rsp_data[726]
    DIRECTION INPUT ;
    USE SIGNAL ;
    PORT
      LAYER M4 ;
        RECT  0 73.644 0.192 73.668 ;
    END
  END rsp_data[726]
  PIN rsp_data[727]
    DIRECTION INPUT ;
    USE SIGNAL ;
    PORT
      LAYER M4 ;
        RECT  0 73.98 0.192 74.004 ;
    END
  END rsp_data[727]
  PIN rsp_data[728]
    DIRECTION INPUT ;
    USE SIGNAL ;
    PORT
      LAYER M4 ;
        RECT  0 74.316 0.192 74.34 ;
    END
  END rsp_data[728]
  PIN rsp_data[729]
    DIRECTION INPUT ;
    USE SIGNAL ;
    PORT
      LAYER M4 ;
        RECT  0 74.652 0.192 74.676 ;
    END
  END rsp_data[729]
  PIN rsp_data[730]
    DIRECTION INPUT ;
    USE SIGNAL ;
    PORT
      LAYER M4 ;
        RECT  0 74.94 0.192 74.964 ;
    END
  END rsp_data[730]
  PIN rsp_data[731]
    DIRECTION INPUT ;
    USE SIGNAL ;
    PORT
      LAYER M4 ;
        RECT  0 75.276 0.192 75.3 ;
    END
  END rsp_data[731]
  PIN rsp_data[732]
    DIRECTION INPUT ;
    USE SIGNAL ;
    PORT
      LAYER M4 ;
        RECT  0 75.612 0.192 75.636 ;
    END
  END rsp_data[732]
  PIN rsp_data[733]
    DIRECTION INPUT ;
    USE SIGNAL ;
    PORT
      LAYER M4 ;
        RECT  0 75.948 0.192 75.972 ;
    END
  END rsp_data[733]
  PIN rsp_data[734]
    DIRECTION INPUT ;
    USE SIGNAL ;
    PORT
      LAYER M4 ;
        RECT  0 76.284 0.192 76.308 ;
    END
  END rsp_data[734]
  PIN rsp_data[735]
    DIRECTION INPUT ;
    USE SIGNAL ;
    PORT
      LAYER M4 ;
        RECT  0 76.572 0.192 76.596 ;
    END
  END rsp_data[735]
  PIN rsp_data[736]
    DIRECTION INPUT ;
    USE SIGNAL ;
    PORT
      LAYER M4 ;
        RECT  0 76.908 0.192 76.932 ;
    END
  END rsp_data[736]
  PIN rsp_data[737]
    DIRECTION INPUT ;
    USE SIGNAL ;
    PORT
      LAYER M4 ;
        RECT  0 77.244 0.192 77.268 ;
    END
  END rsp_data[737]
  PIN rsp_data[738]
    DIRECTION INPUT ;
    USE SIGNAL ;
    PORT
      LAYER M4 ;
        RECT  0 77.58 0.192 77.604 ;
    END
  END rsp_data[738]
  PIN rsp_data[739]
    DIRECTION INPUT ;
    USE SIGNAL ;
    PORT
      LAYER M4 ;
        RECT  0 77.916 0.192 77.94 ;
    END
  END rsp_data[739]
  PIN rsp_data[740]
    DIRECTION INPUT ;
    USE SIGNAL ;
    PORT
      LAYER M4 ;
        RECT  0 78.204 0.192 78.228 ;
    END
  END rsp_data[740]
  PIN rsp_data[741]
    DIRECTION INPUT ;
    USE SIGNAL ;
    PORT
      LAYER M4 ;
        RECT  0 78.54 0.192 78.564 ;
    END
  END rsp_data[741]
  PIN rsp_data[742]
    DIRECTION INPUT ;
    USE SIGNAL ;
    PORT
      LAYER M4 ;
        RECT  0 78.876 0.192 78.9 ;
    END
  END rsp_data[742]
  PIN rsp_data[743]
    DIRECTION INPUT ;
    USE SIGNAL ;
    PORT
      LAYER M4 ;
        RECT  0 79.212 0.192 79.236 ;
    END
  END rsp_data[743]
  PIN rsp_data[744]
    DIRECTION INPUT ;
    USE SIGNAL ;
    PORT
      LAYER M4 ;
        RECT  0 79.548 0.192 79.572 ;
    END
  END rsp_data[744]
  PIN rsp_data[745]
    DIRECTION INPUT ;
    USE SIGNAL ;
    PORT
      LAYER M4 ;
        RECT  0 79.836 0.192 79.86 ;
    END
  END rsp_data[745]
  PIN rsp_data[746]
    DIRECTION INPUT ;
    USE SIGNAL ;
    PORT
      LAYER M4 ;
        RECT  0 80.172 0.192 80.196 ;
    END
  END rsp_data[746]
  PIN rsp_data[747]
    DIRECTION INPUT ;
    USE SIGNAL ;
    PORT
      LAYER M4 ;
        RECT  0 80.508 0.192 80.532 ;
    END
  END rsp_data[747]
  PIN rsp_data[748]
    DIRECTION INPUT ;
    USE SIGNAL ;
    PORT
      LAYER M4 ;
        RECT  0 80.844 0.192 80.868 ;
    END
  END rsp_data[748]
  PIN rsp_data[749]
    DIRECTION INPUT ;
    USE SIGNAL ;
    PORT
      LAYER M4 ;
        RECT  0 81.18 0.192 81.204 ;
    END
  END rsp_data[749]
  PIN rsp_data[750]
    DIRECTION INPUT ;
    USE SIGNAL ;
    PORT
      LAYER M4 ;
        RECT  0 81.468 0.192 81.492 ;
    END
  END rsp_data[750]
  PIN rsp_data[751]
    DIRECTION INPUT ;
    USE SIGNAL ;
    PORT
      LAYER M4 ;
        RECT  0 81.804 0.192 81.828 ;
    END
  END rsp_data[751]
  PIN rsp_data[752]
    DIRECTION INPUT ;
    USE SIGNAL ;
    PORT
      LAYER M4 ;
        RECT  0 82.14 0.192 82.164 ;
    END
  END rsp_data[752]
  PIN rsp_data[753]
    DIRECTION INPUT ;
    USE SIGNAL ;
    PORT
      LAYER M4 ;
        RECT  0 82.476 0.192 82.5 ;
    END
  END rsp_data[753]
  PIN rsp_data[754]
    DIRECTION INPUT ;
    USE SIGNAL ;
    PORT
      LAYER M4 ;
        RECT  0 82.812 0.192 82.836 ;
    END
  END rsp_data[754]
  PIN rsp_data[755]
    DIRECTION INPUT ;
    USE SIGNAL ;
    PORT
      LAYER M4 ;
        RECT  0 83.1 0.192 83.124 ;
    END
  END rsp_data[755]
  PIN rsp_data[756]
    DIRECTION INPUT ;
    USE SIGNAL ;
    PORT
      LAYER M4 ;
        RECT  0 83.436 0.192 83.46 ;
    END
  END rsp_data[756]
  PIN rsp_data[757]
    DIRECTION INPUT ;
    USE SIGNAL ;
    PORT
      LAYER M4 ;
        RECT  0 83.772 0.192 83.796 ;
    END
  END rsp_data[757]
  PIN rsp_data[758]
    DIRECTION INPUT ;
    USE SIGNAL ;
    PORT
      LAYER M4 ;
        RECT  0 84.108 0.192 84.132 ;
    END
  END rsp_data[758]
  PIN rsp_data[759]
    DIRECTION INPUT ;
    USE SIGNAL ;
    PORT
      LAYER M4 ;
        RECT  0 84.444 0.192 84.468 ;
    END
  END rsp_data[759]
  PIN rsp_data[760]
    DIRECTION INPUT ;
    USE SIGNAL ;
    PORT
      LAYER M4 ;
        RECT  0 84.732 0.192 84.756 ;
    END
  END rsp_data[760]
  PIN rsp_data[761]
    DIRECTION INPUT ;
    USE SIGNAL ;
    PORT
      LAYER M4 ;
        RECT  0 85.068 0.192 85.092 ;
    END
  END rsp_data[761]
  PIN rsp_data[762]
    DIRECTION INPUT ;
    USE SIGNAL ;
    PORT
      LAYER M4 ;
        RECT  0 85.404 0.192 85.428 ;
    END
  END rsp_data[762]
  PIN rsp_data[763]
    DIRECTION INPUT ;
    USE SIGNAL ;
    PORT
      LAYER M4 ;
        RECT  0 85.74 0.192 85.764 ;
    END
  END rsp_data[763]
  PIN rsp_data[764]
    DIRECTION INPUT ;
    USE SIGNAL ;
    PORT
      LAYER M4 ;
        RECT  0 86.076 0.192 86.1 ;
    END
  END rsp_data[764]
  PIN rsp_data[765]
    DIRECTION INPUT ;
    USE SIGNAL ;
    PORT
      LAYER M4 ;
        RECT  0 86.412 0.192 86.436 ;
    END
  END rsp_data[765]
  PIN rsp_data[766]
    DIRECTION INPUT ;
    USE SIGNAL ;
    PORT
      LAYER M4 ;
        RECT  0 86.7 0.192 86.724 ;
    END
  END rsp_data[766]
  PIN rsp_data[767]
    DIRECTION INPUT ;
    USE SIGNAL ;
    PORT
      LAYER M4 ;
        RECT  0 87.036 0.192 87.06 ;
    END
  END rsp_data[767]
  PIN rsp_data[768]
    DIRECTION INPUT ;
    USE SIGNAL ;
    PORT
      LAYER M4 ;
        RECT  0 87.372 0.192 87.396 ;
    END
  END rsp_data[768]
  PIN rsp_data[769]
    DIRECTION INPUT ;
    USE SIGNAL ;
    PORT
      LAYER M4 ;
        RECT  0 87.708 0.192 87.732 ;
    END
  END rsp_data[769]
  PIN rsp_data[770]
    DIRECTION INPUT ;
    USE SIGNAL ;
    PORT
      LAYER M4 ;
        RECT  0 88.044 0.192 88.068 ;
    END
  END rsp_data[770]
  PIN rsp_data[771]
    DIRECTION INPUT ;
    USE SIGNAL ;
    PORT
      LAYER M4 ;
        RECT  0 88.332 0.192 88.356 ;
    END
  END rsp_data[771]
  PIN rsp_data[772]
    DIRECTION INPUT ;
    USE SIGNAL ;
    PORT
      LAYER M4 ;
        RECT  0 88.668 0.192 88.692 ;
    END
  END rsp_data[772]
  PIN rsp_data[773]
    DIRECTION INPUT ;
    USE SIGNAL ;
    PORT
      LAYER M4 ;
        RECT  0 89.004 0.192 89.028 ;
    END
  END rsp_data[773]
  PIN rsp_data[774]
    DIRECTION INPUT ;
    USE SIGNAL ;
    PORT
      LAYER M4 ;
        RECT  0 89.34 0.192 89.364 ;
    END
  END rsp_data[774]
  PIN rsp_data[775]
    DIRECTION INPUT ;
    USE SIGNAL ;
    PORT
      LAYER M4 ;
        RECT  0 89.676 0.192 89.7 ;
    END
  END rsp_data[775]
  PIN rsp_data[776]
    DIRECTION INPUT ;
    USE SIGNAL ;
    PORT
      LAYER M4 ;
        RECT  0 89.964 0.192 89.988 ;
    END
  END rsp_data[776]
  PIN rsp_data[777]
    DIRECTION INPUT ;
    USE SIGNAL ;
    PORT
      LAYER M4 ;
        RECT  0 90.3 0.192 90.324 ;
    END
  END rsp_data[777]
  PIN rsp_data[778]
    DIRECTION INPUT ;
    USE SIGNAL ;
    PORT
      LAYER M4 ;
        RECT  0 90.636 0.192 90.66 ;
    END
  END rsp_data[778]
  PIN rsp_data[779]
    DIRECTION INPUT ;
    USE SIGNAL ;
    PORT
      LAYER M4 ;
        RECT  0 90.972 0.192 90.996 ;
    END
  END rsp_data[779]
  PIN rsp_data[780]
    DIRECTION INPUT ;
    USE SIGNAL ;
    PORT
      LAYER M4 ;
        RECT  0 91.308 0.192 91.332 ;
    END
  END rsp_data[780]
  PIN rsp_data[781]
    DIRECTION INPUT ;
    USE SIGNAL ;
    PORT
      LAYER M4 ;
        RECT  0 91.596 0.192 91.62 ;
    END
  END rsp_data[781]
  PIN rsp_data[782]
    DIRECTION INPUT ;
    USE SIGNAL ;
    PORT
      LAYER M4 ;
        RECT  0 91.932 0.192 91.956 ;
    END
  END rsp_data[782]
  PIN rsp_data[783]
    DIRECTION INPUT ;
    USE SIGNAL ;
    PORT
      LAYER M4 ;
        RECT  0 92.268 0.192 92.292 ;
    END
  END rsp_data[783]
  PIN rsp_data[784]
    DIRECTION INPUT ;
    USE SIGNAL ;
    PORT
      LAYER M4 ;
        RECT  0 92.604 0.192 92.628 ;
    END
  END rsp_data[784]
  PIN rsp_data[785]
    DIRECTION INPUT ;
    USE SIGNAL ;
    PORT
      LAYER M4 ;
        RECT  0 92.94 0.192 92.964 ;
    END
  END rsp_data[785]
  PIN rsp_data[786]
    DIRECTION INPUT ;
    USE SIGNAL ;
    PORT
      LAYER M4 ;
        RECT  0 93.228 0.192 93.252 ;
    END
  END rsp_data[786]
  PIN rsp_data[787]
    DIRECTION INPUT ;
    USE SIGNAL ;
    PORT
      LAYER M4 ;
        RECT  0 93.564 0.192 93.588 ;
    END
  END rsp_data[787]
  PIN rsp_data[788]
    DIRECTION INPUT ;
    USE SIGNAL ;
    PORT
      LAYER M4 ;
        RECT  0 93.9 0.192 93.924 ;
    END
  END rsp_data[788]
  PIN rsp_data[789]
    DIRECTION INPUT ;
    USE SIGNAL ;
    PORT
      LAYER M4 ;
        RECT  0 94.236 0.192 94.26 ;
    END
  END rsp_data[789]
  PIN rsp_data[790]
    DIRECTION INPUT ;
    USE SIGNAL ;
    PORT
      LAYER M4 ;
        RECT  0 94.572 0.192 94.596 ;
    END
  END rsp_data[790]
  PIN rsp_data[791]
    DIRECTION INPUT ;
    USE SIGNAL ;
    PORT
      LAYER M4 ;
        RECT  0 94.86 0.192 94.884 ;
    END
  END rsp_data[791]
  PIN rsp_data[792]
    DIRECTION INPUT ;
    USE SIGNAL ;
    PORT
      LAYER M4 ;
        RECT  0 95.196 0.192 95.22 ;
    END
  END rsp_data[792]
  PIN rsp_data[793]
    DIRECTION INPUT ;
    USE SIGNAL ;
    PORT
      LAYER M4 ;
        RECT  0 95.532 0.192 95.556 ;
    END
  END rsp_data[793]
  PIN rsp_data[794]
    DIRECTION INPUT ;
    USE SIGNAL ;
    PORT
      LAYER M4 ;
        RECT  0 95.868 0.192 95.892 ;
    END
  END rsp_data[794]
  PIN rsp_data[795]
    DIRECTION INPUT ;
    USE SIGNAL ;
    PORT
      LAYER M4 ;
        RECT  0 96.204 0.192 96.228 ;
    END
  END rsp_data[795]
  PIN rsp_data[796]
    DIRECTION INPUT ;
    USE SIGNAL ;
    PORT
      LAYER M4 ;
        RECT  0 96.492 0.192 96.516 ;
    END
  END rsp_data[796]
  PIN rsp_data[797]
    DIRECTION INPUT ;
    USE SIGNAL ;
    PORT
      LAYER M4 ;
        RECT  0 96.828 0.192 96.852 ;
    END
  END rsp_data[797]
  PIN rsp_data[798]
    DIRECTION INPUT ;
    USE SIGNAL ;
    PORT
      LAYER M4 ;
        RECT  0 97.164 0.192 97.188 ;
    END
  END rsp_data[798]
  PIN rsp_data[799]
    DIRECTION INPUT ;
    USE SIGNAL ;
    PORT
      LAYER M4 ;
        RECT  0 97.5 0.192 97.524 ;
    END
  END rsp_data[799]
  PIN rsp_data[800]
    DIRECTION INPUT ;
    USE SIGNAL ;
    PORT
      LAYER M4 ;
        RECT  0 97.836 0.192 97.86 ;
    END
  END rsp_data[800]
  PIN rsp_data[801]
    DIRECTION INPUT ;
    USE SIGNAL ;
    PORT
      LAYER M4 ;
        RECT  0 98.124 0.192 98.148 ;
    END
  END rsp_data[801]
  PIN rsp_data[802]
    DIRECTION INPUT ;
    USE SIGNAL ;
    PORT
      LAYER M4 ;
        RECT  0 98.46 0.192 98.484 ;
    END
  END rsp_data[802]
  PIN rsp_data[803]
    DIRECTION INPUT ;
    USE SIGNAL ;
    PORT
      LAYER M4 ;
        RECT  0 98.796 0.192 98.82 ;
    END
  END rsp_data[803]
  PIN rsp_data[804]
    DIRECTION INPUT ;
    USE SIGNAL ;
    PORT
      LAYER M4 ;
        RECT  0 99.132 0.192 99.156 ;
    END
  END rsp_data[804]
  PIN rsp_data[805]
    DIRECTION INPUT ;
    USE SIGNAL ;
    PORT
      LAYER M4 ;
        RECT  0 99.468 0.192 99.492 ;
    END
  END rsp_data[805]
  PIN rsp_data[806]
    DIRECTION INPUT ;
    USE SIGNAL ;
    PORT
      LAYER M4 ;
        RECT  0 99.756 0.192 99.78 ;
    END
  END rsp_data[806]
  PIN rsp_data[807]
    DIRECTION INPUT ;
    USE SIGNAL ;
    PORT
      LAYER M4 ;
        RECT  0 100.092 0.192 100.116 ;
    END
  END rsp_data[807]
  PIN rsp_data[808]
    DIRECTION INPUT ;
    USE SIGNAL ;
    PORT
      LAYER M4 ;
        RECT  0 100.428 0.192 100.452 ;
    END
  END rsp_data[808]
  PIN rsp_data[809]
    DIRECTION INPUT ;
    USE SIGNAL ;
    PORT
      LAYER M4 ;
        RECT  0 100.764 0.192 100.788 ;
    END
  END rsp_data[809]
  PIN rsp_data[810]
    DIRECTION INPUT ;
    USE SIGNAL ;
    PORT
      LAYER M4 ;
        RECT  0 101.1 0.192 101.124 ;
    END
  END rsp_data[810]
  PIN rsp_data[811]
    DIRECTION INPUT ;
    USE SIGNAL ;
    PORT
      LAYER M4 ;
        RECT  0 101.388 0.192 101.412 ;
    END
  END rsp_data[811]
  PIN rsp_data[812]
    DIRECTION INPUT ;
    USE SIGNAL ;
    PORT
      LAYER M4 ;
        RECT  0 101.724 0.192 101.748 ;
    END
  END rsp_data[812]
  PIN rsp_data[813]
    DIRECTION INPUT ;
    USE SIGNAL ;
    PORT
      LAYER M4 ;
        RECT  0 102.06 0.192 102.084 ;
    END
  END rsp_data[813]
  PIN rsp_data[814]
    DIRECTION INPUT ;
    USE SIGNAL ;
    PORT
      LAYER M4 ;
        RECT  0 102.396 0.192 102.42 ;
    END
  END rsp_data[814]
  PIN rsp_data[815]
    DIRECTION INPUT ;
    USE SIGNAL ;
    PORT
      LAYER M4 ;
        RECT  0 102.732 0.192 102.756 ;
    END
  END rsp_data[815]
  PIN rsp_data[816]
    DIRECTION INPUT ;
    USE SIGNAL ;
    PORT
      LAYER M4 ;
        RECT  0 103.02 0.192 103.044 ;
    END
  END rsp_data[816]
  PIN rsp_data[817]
    DIRECTION INPUT ;
    USE SIGNAL ;
    PORT
      LAYER M4 ;
        RECT  0 103.356 0.192 103.38 ;
    END
  END rsp_data[817]
  PIN rsp_data[818]
    DIRECTION INPUT ;
    USE SIGNAL ;
    PORT
      LAYER M4 ;
        RECT  0 103.692 0.192 103.716 ;
    END
  END rsp_data[818]
  PIN rsp_data[819]
    DIRECTION INPUT ;
    USE SIGNAL ;
    PORT
      LAYER M4 ;
        RECT  0 104.028 0.192 104.052 ;
    END
  END rsp_data[819]
  PIN rsp_data[820]
    DIRECTION INPUT ;
    USE SIGNAL ;
    PORT
      LAYER M4 ;
        RECT  0 104.364 0.192 104.388 ;
    END
  END rsp_data[820]
  PIN rsp_data[821]
    DIRECTION INPUT ;
    USE SIGNAL ;
    PORT
      LAYER M4 ;
        RECT  0 104.652 0.192 104.676 ;
    END
  END rsp_data[821]
  PIN rsp_data[822]
    DIRECTION INPUT ;
    USE SIGNAL ;
    PORT
      LAYER M4 ;
        RECT  0 104.988 0.192 105.012 ;
    END
  END rsp_data[822]
  PIN rsp_data[823]
    DIRECTION INPUT ;
    USE SIGNAL ;
    PORT
      LAYER M4 ;
        RECT  0 105.324 0.192 105.348 ;
    END
  END rsp_data[823]
  PIN rsp_data[824]
    DIRECTION INPUT ;
    USE SIGNAL ;
    PORT
      LAYER M4 ;
        RECT  0 105.66 0.192 105.684 ;
    END
  END rsp_data[824]
  PIN rsp_data[825]
    DIRECTION INPUT ;
    USE SIGNAL ;
    PORT
      LAYER M4 ;
        RECT  0 105.996 0.192 106.02 ;
    END
  END rsp_data[825]
  PIN rsp_data[826]
    DIRECTION INPUT ;
    USE SIGNAL ;
    PORT
      LAYER M4 ;
        RECT  0 106.284 0.192 106.308 ;
    END
  END rsp_data[826]
  PIN rsp_data[827]
    DIRECTION INPUT ;
    USE SIGNAL ;
    PORT
      LAYER M4 ;
        RECT  0 106.62 0.192 106.644 ;
    END
  END rsp_data[827]
  PIN rsp_data[828]
    DIRECTION INPUT ;
    USE SIGNAL ;
    PORT
      LAYER M4 ;
        RECT  0 106.956 0.192 106.98 ;
    END
  END rsp_data[828]
  PIN rsp_data[829]
    DIRECTION INPUT ;
    USE SIGNAL ;
    PORT
      LAYER M4 ;
        RECT  0 107.292 0.192 107.316 ;
    END
  END rsp_data[829]
  PIN rsp_data[830]
    DIRECTION INPUT ;
    USE SIGNAL ;
    PORT
      LAYER M4 ;
        RECT  0 107.628 0.192 107.652 ;
    END
  END rsp_data[830]
  PIN rsp_data[831]
    DIRECTION INPUT ;
    USE SIGNAL ;
    PORT
      LAYER M4 ;
        RECT  0 107.916 0.192 107.94 ;
    END
  END rsp_data[831]
  PIN rsp_data[832]
    DIRECTION INPUT ;
    USE SIGNAL ;
    PORT
      LAYER M4 ;
        RECT  0 108.252 0.192 108.276 ;
    END
  END rsp_data[832]
  PIN rsp_data[833]
    DIRECTION INPUT ;
    USE SIGNAL ;
    PORT
      LAYER M4 ;
        RECT  0 108.588 0.192 108.612 ;
    END
  END rsp_data[833]
  PIN rsp_data[834]
    DIRECTION INPUT ;
    USE SIGNAL ;
    PORT
      LAYER M4 ;
        RECT  0 108.924 0.192 108.948 ;
    END
  END rsp_data[834]
  PIN rsp_data[835]
    DIRECTION INPUT ;
    USE SIGNAL ;
    PORT
      LAYER M4 ;
        RECT  0 109.26 0.192 109.284 ;
    END
  END rsp_data[835]
  PIN rsp_data[836]
    DIRECTION INPUT ;
    USE SIGNAL ;
    PORT
      LAYER M4 ;
        RECT  0 109.548 0.192 109.572 ;
    END
  END rsp_data[836]
  PIN rsp_data[837]
    DIRECTION INPUT ;
    USE SIGNAL ;
    PORT
      LAYER M4 ;
        RECT  0 109.884 0.192 109.908 ;
    END
  END rsp_data[837]
  PIN rsp_data[838]
    DIRECTION INPUT ;
    USE SIGNAL ;
    PORT
      LAYER M4 ;
        RECT  0 110.22 0.192 110.244 ;
    END
  END rsp_data[838]
  PIN rsp_data[839]
    DIRECTION INPUT ;
    USE SIGNAL ;
    PORT
      LAYER M4 ;
        RECT  0 110.556 0.192 110.58 ;
    END
  END rsp_data[839]
  PIN rsp_data[840]
    DIRECTION INPUT ;
    USE SIGNAL ;
    PORT
      LAYER M4 ;
        RECT  0 110.892 0.192 110.916 ;
    END
  END rsp_data[840]
  PIN rsp_data[841]
    DIRECTION INPUT ;
    USE SIGNAL ;
    PORT
      LAYER M4 ;
        RECT  0 111.18 0.192 111.204 ;
    END
  END rsp_data[841]
  PIN rsp_data[842]
    DIRECTION INPUT ;
    USE SIGNAL ;
    PORT
      LAYER M4 ;
        RECT  0 111.516 0.192 111.54 ;
    END
  END rsp_data[842]
  PIN rsp_data[843]
    DIRECTION INPUT ;
    USE SIGNAL ;
    PORT
      LAYER M4 ;
        RECT  0 111.852 0.192 111.876 ;
    END
  END rsp_data[843]
  PIN rsp_data[844]
    DIRECTION INPUT ;
    USE SIGNAL ;
    PORT
      LAYER M4 ;
        RECT  0 112.188 0.192 112.212 ;
    END
  END rsp_data[844]
  PIN rsp_data[845]
    DIRECTION INPUT ;
    USE SIGNAL ;
    PORT
      LAYER M4 ;
        RECT  0 112.524 0.192 112.548 ;
    END
  END rsp_data[845]
  PIN rsp_data[846]
    DIRECTION INPUT ;
    USE SIGNAL ;
    PORT
      LAYER M4 ;
        RECT  0 112.812 0.192 112.836 ;
    END
  END rsp_data[846]
  PIN rsp_data[847]
    DIRECTION INPUT ;
    USE SIGNAL ;
    PORT
      LAYER M4 ;
        RECT  0 113.148 0.192 113.172 ;
    END
  END rsp_data[847]
  PIN rsp_data[848]
    DIRECTION INPUT ;
    USE SIGNAL ;
    PORT
      LAYER M4 ;
        RECT  0 113.484 0.192 113.508 ;
    END
  END rsp_data[848]
  PIN rsp_data[849]
    DIRECTION INPUT ;
    USE SIGNAL ;
    PORT
      LAYER M4 ;
        RECT  0 113.82 0.192 113.844 ;
    END
  END rsp_data[849]
  PIN rsp_data[850]
    DIRECTION INPUT ;
    USE SIGNAL ;
    PORT
      LAYER M4 ;
        RECT  0 114.156 0.192 114.18 ;
    END
  END rsp_data[850]
  PIN rsp_data[851]
    DIRECTION INPUT ;
    USE SIGNAL ;
    PORT
      LAYER M4 ;
        RECT  0 114.444 0.192 114.468 ;
    END
  END rsp_data[851]
  PIN rsp_data[852]
    DIRECTION INPUT ;
    USE SIGNAL ;
    PORT
      LAYER M4 ;
        RECT  0 114.78 0.192 114.804 ;
    END
  END rsp_data[852]
  PIN rsp_data[853]
    DIRECTION INPUT ;
    USE SIGNAL ;
    PORT
      LAYER M4 ;
        RECT  0 115.116 0.192 115.14 ;
    END
  END rsp_data[853]
  PIN rsp_data[854]
    DIRECTION INPUT ;
    USE SIGNAL ;
    PORT
      LAYER M4 ;
        RECT  0 115.452 0.192 115.476 ;
    END
  END rsp_data[854]
  PIN rsp_data[855]
    DIRECTION INPUT ;
    USE SIGNAL ;
    PORT
      LAYER M4 ;
        RECT  0 115.788 0.192 115.812 ;
    END
  END rsp_data[855]
  PIN rsp_data[856]
    DIRECTION INPUT ;
    USE SIGNAL ;
    PORT
      LAYER M4 ;
        RECT  0 116.076 0.192 116.1 ;
    END
  END rsp_data[856]
  PIN rsp_data[857]
    DIRECTION INPUT ;
    USE SIGNAL ;
    PORT
      LAYER M4 ;
        RECT  0 116.412 0.192 116.436 ;
    END
  END rsp_data[857]
  PIN rsp_data[858]
    DIRECTION INPUT ;
    USE SIGNAL ;
    PORT
      LAYER M4 ;
        RECT  0 116.748 0.192 116.772 ;
    END
  END rsp_data[858]
  PIN rsp_data[859]
    DIRECTION INPUT ;
    USE SIGNAL ;
    PORT
      LAYER M4 ;
        RECT  0 117.084 0.192 117.108 ;
    END
  END rsp_data[859]
  PIN rsp_data[860]
    DIRECTION INPUT ;
    USE SIGNAL ;
    PORT
      LAYER M4 ;
        RECT  0 117.42 0.192 117.444 ;
    END
  END rsp_data[860]
  PIN rsp_data[861]
    DIRECTION INPUT ;
    USE SIGNAL ;
    PORT
      LAYER M4 ;
        RECT  0 117.708 0.192 117.732 ;
    END
  END rsp_data[861]
  PIN rsp_data[862]
    DIRECTION INPUT ;
    USE SIGNAL ;
    PORT
      LAYER M4 ;
        RECT  0 118.044 0.192 118.068 ;
    END
  END rsp_data[862]
  PIN rsp_data[863]
    DIRECTION INPUT ;
    USE SIGNAL ;
    PORT
      LAYER M4 ;
        RECT  0 118.38 0.192 118.404 ;
    END
  END rsp_data[863]
  PIN rsp_data[864]
    DIRECTION INPUT ;
    USE SIGNAL ;
    PORT
      LAYER M4 ;
        RECT  0 118.716 0.192 118.74 ;
    END
  END rsp_data[864]
  PIN rsp_data[865]
    DIRECTION INPUT ;
    USE SIGNAL ;
    PORT
      LAYER M4 ;
        RECT  0 119.052 0.192 119.076 ;
    END
  END rsp_data[865]
  PIN rsp_data[866]
    DIRECTION INPUT ;
    USE SIGNAL ;
    PORT
      LAYER M4 ;
        RECT  0 119.388 0.192 119.412 ;
    END
  END rsp_data[866]
  PIN rsp_data[867]
    DIRECTION INPUT ;
    USE SIGNAL ;
    PORT
      LAYER M4 ;
        RECT  0 119.676 0.192 119.7 ;
    END
  END rsp_data[867]
  PIN rsp_data[868]
    DIRECTION INPUT ;
    USE SIGNAL ;
    PORT
      LAYER M4 ;
        RECT  0 120.012 0.192 120.036 ;
    END
  END rsp_data[868]
  PIN rsp_data[869]
    DIRECTION INPUT ;
    USE SIGNAL ;
    PORT
      LAYER M4 ;
        RECT  0 120.348 0.192 120.372 ;
    END
  END rsp_data[869]
  PIN rsp_data[870]
    DIRECTION INPUT ;
    USE SIGNAL ;
    PORT
      LAYER M4 ;
        RECT  0 120.684 0.192 120.708 ;
    END
  END rsp_data[870]
  PIN rsp_data[871]
    DIRECTION INPUT ;
    USE SIGNAL ;
    PORT
      LAYER M4 ;
        RECT  0 121.02 0.192 121.044 ;
    END
  END rsp_data[871]
  PIN rsp_data[872]
    DIRECTION INPUT ;
    USE SIGNAL ;
    PORT
      LAYER M4 ;
        RECT  0 121.308 0.192 121.332 ;
    END
  END rsp_data[872]
  PIN rsp_data[873]
    DIRECTION INPUT ;
    USE SIGNAL ;
    PORT
      LAYER M4 ;
        RECT  0 121.644 0.192 121.668 ;
    END
  END rsp_data[873]
  PIN rsp_data[874]
    DIRECTION INPUT ;
    USE SIGNAL ;
    PORT
      LAYER M4 ;
        RECT  0 121.98 0.192 122.004 ;
    END
  END rsp_data[874]
  PIN rsp_data[875]
    DIRECTION INPUT ;
    USE SIGNAL ;
    PORT
      LAYER M4 ;
        RECT  0 122.316 0.192 122.34 ;
    END
  END rsp_data[875]
  PIN rsp_data[876]
    DIRECTION INPUT ;
    USE SIGNAL ;
    PORT
      LAYER M4 ;
        RECT  0 122.652 0.192 122.676 ;
    END
  END rsp_data[876]
  PIN rsp_data[877]
    DIRECTION INPUT ;
    USE SIGNAL ;
    PORT
      LAYER M4 ;
        RECT  0 122.94 0.192 122.964 ;
    END
  END rsp_data[877]
  PIN rsp_data[878]
    DIRECTION INPUT ;
    USE SIGNAL ;
    PORT
      LAYER M4 ;
        RECT  0 123.276 0.192 123.3 ;
    END
  END rsp_data[878]
  PIN rsp_data[879]
    DIRECTION INPUT ;
    USE SIGNAL ;
    PORT
      LAYER M4 ;
        RECT  0 123.612 0.192 123.636 ;
    END
  END rsp_data[879]
  PIN rsp_data[880]
    DIRECTION INPUT ;
    USE SIGNAL ;
    PORT
      LAYER M4 ;
        RECT  0 123.948 0.192 123.972 ;
    END
  END rsp_data[880]
  PIN rsp_data[881]
    DIRECTION INPUT ;
    USE SIGNAL ;
    PORT
      LAYER M4 ;
        RECT  0 124.284 0.192 124.308 ;
    END
  END rsp_data[881]
  PIN rsp_data[882]
    DIRECTION INPUT ;
    USE SIGNAL ;
    PORT
      LAYER M4 ;
        RECT  0 124.572 0.192 124.596 ;
    END
  END rsp_data[882]
  PIN rsp_data[883]
    DIRECTION INPUT ;
    USE SIGNAL ;
    PORT
      LAYER M4 ;
        RECT  0 124.908 0.192 124.932 ;
    END
  END rsp_data[883]
  PIN rsp_data[884]
    DIRECTION INPUT ;
    USE SIGNAL ;
    PORT
      LAYER M4 ;
        RECT  0 125.244 0.192 125.268 ;
    END
  END rsp_data[884]
  PIN rsp_data[885]
    DIRECTION INPUT ;
    USE SIGNAL ;
    PORT
      LAYER M4 ;
        RECT  0 125.58 0.192 125.604 ;
    END
  END rsp_data[885]
  PIN rsp_data[886]
    DIRECTION INPUT ;
    USE SIGNAL ;
    PORT
      LAYER M4 ;
        RECT  0 125.916 0.192 125.94 ;
    END
  END rsp_data[886]
  PIN rsp_data[887]
    DIRECTION INPUT ;
    USE SIGNAL ;
    PORT
      LAYER M4 ;
        RECT  0 126.204 0.192 126.228 ;
    END
  END rsp_data[887]
  PIN rsp_data[888]
    DIRECTION INPUT ;
    USE SIGNAL ;
    PORT
      LAYER M4 ;
        RECT  0 126.54 0.192 126.564 ;
    END
  END rsp_data[888]
  PIN rsp_data[889]
    DIRECTION INPUT ;
    USE SIGNAL ;
    PORT
      LAYER M4 ;
        RECT  0 126.876 0.192 126.9 ;
    END
  END rsp_data[889]
  PIN rsp_data[890]
    DIRECTION INPUT ;
    USE SIGNAL ;
    PORT
      LAYER M4 ;
        RECT  0 127.212 0.192 127.236 ;
    END
  END rsp_data[890]
  PIN rsp_data[891]
    DIRECTION INPUT ;
    USE SIGNAL ;
    PORT
      LAYER M4 ;
        RECT  0 127.548 0.192 127.572 ;
    END
  END rsp_data[891]
  PIN rsp_data[892]
    DIRECTION INPUT ;
    USE SIGNAL ;
    PORT
      LAYER M4 ;
        RECT  0 127.836 0.192 127.86 ;
    END
  END rsp_data[892]
  PIN rsp_data[893]
    DIRECTION INPUT ;
    USE SIGNAL ;
    PORT
      LAYER M4 ;
        RECT  0 128.172 0.192 128.196 ;
    END
  END rsp_data[893]
  PIN rsp_data[894]
    DIRECTION INPUT ;
    USE SIGNAL ;
    PORT
      LAYER M4 ;
        RECT  0 128.508 0.192 128.532 ;
    END
  END rsp_data[894]
  PIN rsp_data[895]
    DIRECTION INPUT ;
    USE SIGNAL ;
    PORT
      LAYER M4 ;
        RECT  0 128.844 0.192 128.868 ;
    END
  END rsp_data[895]
  PIN rsp_data[896]
    DIRECTION INPUT ;
    USE SIGNAL ;
    PORT
      LAYER M4 ;
        RECT  0 129.18 0.192 129.204 ;
    END
  END rsp_data[896]
  PIN rsp_data[897]
    DIRECTION INPUT ;
    USE SIGNAL ;
    PORT
      LAYER M4 ;
        RECT  0 129.468 0.192 129.492 ;
    END
  END rsp_data[897]
  PIN rsp_data[898]
    DIRECTION INPUT ;
    USE SIGNAL ;
    PORT
      LAYER M4 ;
        RECT  0 129.804 0.192 129.828 ;
    END
  END rsp_data[898]
  PIN rsp_data[899]
    DIRECTION INPUT ;
    USE SIGNAL ;
    PORT
      LAYER M4 ;
        RECT  0 130.14 0.192 130.164 ;
    END
  END rsp_data[899]
  PIN rsp_data[900]
    DIRECTION INPUT ;
    USE SIGNAL ;
    PORT
      LAYER M4 ;
        RECT  0 130.476 0.192 130.5 ;
    END
  END rsp_data[900]
  PIN rsp_data[901]
    DIRECTION INPUT ;
    USE SIGNAL ;
    PORT
      LAYER M4 ;
        RECT  0 130.812 0.192 130.836 ;
    END
  END rsp_data[901]
  PIN rsp_data[902]
    DIRECTION INPUT ;
    USE SIGNAL ;
    PORT
      LAYER M4 ;
        RECT  0 131.1 0.192 131.124 ;
    END
  END rsp_data[902]
  PIN rsp_data[903]
    DIRECTION INPUT ;
    USE SIGNAL ;
    PORT
      LAYER M4 ;
        RECT  0 131.436 0.192 131.46 ;
    END
  END rsp_data[903]
  PIN rsp_data[904]
    DIRECTION INPUT ;
    USE SIGNAL ;
    PORT
      LAYER M4 ;
        RECT  0 131.772 0.192 131.796 ;
    END
  END rsp_data[904]
  PIN rsp_data[905]
    DIRECTION INPUT ;
    USE SIGNAL ;
    PORT
      LAYER M4 ;
        RECT  0 132.108 0.192 132.132 ;
    END
  END rsp_data[905]
  PIN rsp_data[906]
    DIRECTION INPUT ;
    USE SIGNAL ;
    PORT
      LAYER M4 ;
        RECT  0 132.444 0.192 132.468 ;
    END
  END rsp_data[906]
  PIN rsp_data[907]
    DIRECTION INPUT ;
    USE SIGNAL ;
    PORT
      LAYER M4 ;
        RECT  0 132.732 0.192 132.756 ;
    END
  END rsp_data[907]
  PIN rsp_data[908]
    DIRECTION INPUT ;
    USE SIGNAL ;
    PORT
      LAYER M4 ;
        RECT  0 133.068 0.192 133.092 ;
    END
  END rsp_data[908]
  PIN rsp_data[909]
    DIRECTION INPUT ;
    USE SIGNAL ;
    PORT
      LAYER M4 ;
        RECT  0 133.404 0.192 133.428 ;
    END
  END rsp_data[909]
  PIN rsp_data[910]
    DIRECTION INPUT ;
    USE SIGNAL ;
    PORT
      LAYER M4 ;
        RECT  0 133.74 0.192 133.764 ;
    END
  END rsp_data[910]
  PIN rsp_data[911]
    DIRECTION INPUT ;
    USE SIGNAL ;
    PORT
      LAYER M4 ;
        RECT  0 134.076 0.192 134.1 ;
    END
  END rsp_data[911]
  PIN rsp_data[912]
    DIRECTION INPUT ;
    USE SIGNAL ;
    PORT
      LAYER M4 ;
        RECT  0 134.364 0.192 134.388 ;
    END
  END rsp_data[912]
  PIN rsp_data[913]
    DIRECTION INPUT ;
    USE SIGNAL ;
    PORT
      LAYER M4 ;
        RECT  0 134.7 0.192 134.724 ;
    END
  END rsp_data[913]
  PIN rsp_data[914]
    DIRECTION INPUT ;
    USE SIGNAL ;
    PORT
      LAYER M4 ;
        RECT  0 135.036 0.192 135.06 ;
    END
  END rsp_data[914]
  PIN rsp_data[915]
    DIRECTION INPUT ;
    USE SIGNAL ;
    PORT
      LAYER M4 ;
        RECT  0 135.372 0.192 135.396 ;
    END
  END rsp_data[915]
  PIN rsp_data[916]
    DIRECTION INPUT ;
    USE SIGNAL ;
    PORT
      LAYER M4 ;
        RECT  0 135.708 0.192 135.732 ;
    END
  END rsp_data[916]
  PIN rsp_data[917]
    DIRECTION INPUT ;
    USE SIGNAL ;
    PORT
      LAYER M4 ;
        RECT  0 135.996 0.192 136.02 ;
    END
  END rsp_data[917]
  PIN rsp_data[918]
    DIRECTION INPUT ;
    USE SIGNAL ;
    PORT
      LAYER M4 ;
        RECT  0 136.332 0.192 136.356 ;
    END
  END rsp_data[918]
  PIN rsp_data[919]
    DIRECTION INPUT ;
    USE SIGNAL ;
    PORT
      LAYER M4 ;
        RECT  0 136.668 0.192 136.692 ;
    END
  END rsp_data[919]
  PIN rsp_data[920]
    DIRECTION INPUT ;
    USE SIGNAL ;
    PORT
      LAYER M4 ;
        RECT  0 137.004 0.192 137.028 ;
    END
  END rsp_data[920]
  PIN rsp_data[921]
    DIRECTION INPUT ;
    USE SIGNAL ;
    PORT
      LAYER M4 ;
        RECT  0 137.34 0.192 137.364 ;
    END
  END rsp_data[921]
  PIN rsp_data[922]
    DIRECTION INPUT ;
    USE SIGNAL ;
    PORT
      LAYER M4 ;
        RECT  0 137.628 0.192 137.652 ;
    END
  END rsp_data[922]
  PIN rsp_data[923]
    DIRECTION INPUT ;
    USE SIGNAL ;
    PORT
      LAYER M4 ;
        RECT  0 137.964 0.192 137.988 ;
    END
  END rsp_data[923]
  PIN rsp_data[924]
    DIRECTION INPUT ;
    USE SIGNAL ;
    PORT
      LAYER M4 ;
        RECT  0 138.3 0.192 138.324 ;
    END
  END rsp_data[924]
  PIN rsp_data[925]
    DIRECTION INPUT ;
    USE SIGNAL ;
    PORT
      LAYER M4 ;
        RECT  0 138.636 0.192 138.66 ;
    END
  END rsp_data[925]
  PIN rsp_data[926]
    DIRECTION INPUT ;
    USE SIGNAL ;
    PORT
      LAYER M4 ;
        RECT  0 138.972 0.192 138.996 ;
    END
  END rsp_data[926]
  PIN rsp_data[927]
    DIRECTION INPUT ;
    USE SIGNAL ;
    PORT
      LAYER M4 ;
        RECT  0 139.26 0.192 139.284 ;
    END
  END rsp_data[927]
  PIN rsp_data[928]
    DIRECTION INPUT ;
    USE SIGNAL ;
    PORT
      LAYER M4 ;
        RECT  0 139.596 0.192 139.62 ;
    END
  END rsp_data[928]
  PIN rsp_data[929]
    DIRECTION INPUT ;
    USE SIGNAL ;
    PORT
      LAYER M4 ;
        RECT  0 139.932 0.192 139.956 ;
    END
  END rsp_data[929]
  PIN rsp_data[930]
    DIRECTION INPUT ;
    USE SIGNAL ;
    PORT
      LAYER M4 ;
        RECT  0 140.268 0.192 140.292 ;
    END
  END rsp_data[930]
  PIN rsp_data[931]
    DIRECTION INPUT ;
    USE SIGNAL ;
    PORT
      LAYER M4 ;
        RECT  0 140.604 0.192 140.628 ;
    END
  END rsp_data[931]
  PIN rsp_data[932]
    DIRECTION INPUT ;
    USE SIGNAL ;
    PORT
      LAYER M4 ;
        RECT  0 140.892 0.192 140.916 ;
    END
  END rsp_data[932]
  PIN rsp_data[933]
    DIRECTION INPUT ;
    USE SIGNAL ;
    PORT
      LAYER M4 ;
        RECT  0 141.228 0.192 141.252 ;
    END
  END rsp_data[933]
  PIN rsp_data[934]
    DIRECTION INPUT ;
    USE SIGNAL ;
    PORT
      LAYER M4 ;
        RECT  0 141.564 0.192 141.588 ;
    END
  END rsp_data[934]
  PIN rsp_data[935]
    DIRECTION INPUT ;
    USE SIGNAL ;
    PORT
      LAYER M4 ;
        RECT  0 141.9 0.192 141.924 ;
    END
  END rsp_data[935]
  PIN rsp_data[936]
    DIRECTION INPUT ;
    USE SIGNAL ;
    PORT
      LAYER M4 ;
        RECT  0 142.236 0.192 142.26 ;
    END
  END rsp_data[936]
  PIN rsp_data[937]
    DIRECTION INPUT ;
    USE SIGNAL ;
    PORT
      LAYER M4 ;
        RECT  0 142.524 0.192 142.548 ;
    END
  END rsp_data[937]
  PIN rsp_data[938]
    DIRECTION INPUT ;
    USE SIGNAL ;
    PORT
      LAYER M4 ;
        RECT  0 142.86 0.192 142.884 ;
    END
  END rsp_data[938]
  PIN rsp_data[939]
    DIRECTION INPUT ;
    USE SIGNAL ;
    PORT
      LAYER M4 ;
        RECT  0 143.196 0.192 143.22 ;
    END
  END rsp_data[939]
  PIN rsp_data[940]
    DIRECTION INPUT ;
    USE SIGNAL ;
    PORT
      LAYER M4 ;
        RECT  0 143.532 0.192 143.556 ;
    END
  END rsp_data[940]
  PIN rsp_data[941]
    DIRECTION INPUT ;
    USE SIGNAL ;
    PORT
      LAYER M4 ;
        RECT  0 143.868 0.192 143.892 ;
    END
  END rsp_data[941]
  PIN rsp_data[942]
    DIRECTION INPUT ;
    USE SIGNAL ;
    PORT
      LAYER M4 ;
        RECT  0 144.156 0.192 144.18 ;
    END
  END rsp_data[942]
  PIN rsp_data[943]
    DIRECTION INPUT ;
    USE SIGNAL ;
    PORT
      LAYER M4 ;
        RECT  0 144.492 0.192 144.516 ;
    END
  END rsp_data[943]
  PIN rsp_data[944]
    DIRECTION INPUT ;
    USE SIGNAL ;
    PORT
      LAYER M4 ;
        RECT  0 144.828 0.192 144.852 ;
    END
  END rsp_data[944]
  PIN rsp_data[945]
    DIRECTION INPUT ;
    USE SIGNAL ;
    PORT
      LAYER M4 ;
        RECT  0 145.164 0.192 145.188 ;
    END
  END rsp_data[945]
  PIN rsp_data[946]
    DIRECTION INPUT ;
    USE SIGNAL ;
    PORT
      LAYER M4 ;
        RECT  0 145.5 0.192 145.524 ;
    END
  END rsp_data[946]
  PIN rsp_data[947]
    DIRECTION INPUT ;
    USE SIGNAL ;
    PORT
      LAYER M4 ;
        RECT  0 145.788 0.192 145.812 ;
    END
  END rsp_data[947]
  PIN rsp_data[948]
    DIRECTION INPUT ;
    USE SIGNAL ;
    PORT
      LAYER M4 ;
        RECT  0 146.124 0.192 146.148 ;
    END
  END rsp_data[948]
  PIN rsp_data[949]
    DIRECTION INPUT ;
    USE SIGNAL ;
    PORT
      LAYER M4 ;
        RECT  0 146.46 0.192 146.484 ;
    END
  END rsp_data[949]
  PIN rsp_data[950]
    DIRECTION INPUT ;
    USE SIGNAL ;
    PORT
      LAYER M4 ;
        RECT  0 146.796 0.192 146.82 ;
    END
  END rsp_data[950]
  PIN rsp_data[951]
    DIRECTION INPUT ;
    USE SIGNAL ;
    PORT
      LAYER M4 ;
        RECT  0 147.132 0.192 147.156 ;
    END
  END rsp_data[951]
  PIN rsp_data[952]
    DIRECTION INPUT ;
    USE SIGNAL ;
    PORT
      LAYER M4 ;
        RECT  0 147.42 0.192 147.444 ;
    END
  END rsp_data[952]
  PIN rsp_data[953]
    DIRECTION INPUT ;
    USE SIGNAL ;
    PORT
      LAYER M4 ;
        RECT  0 147.756 0.192 147.78 ;
    END
  END rsp_data[953]
  PIN rsp_data[954]
    DIRECTION INPUT ;
    USE SIGNAL ;
    PORT
      LAYER M4 ;
        RECT  0 148.092 0.192 148.116 ;
    END
  END rsp_data[954]
  PIN rsp_data[955]
    DIRECTION INPUT ;
    USE SIGNAL ;
    PORT
      LAYER M4 ;
        RECT  0 148.428 0.192 148.452 ;
    END
  END rsp_data[955]
  PIN rsp_data[956]
    DIRECTION INPUT ;
    USE SIGNAL ;
    PORT
      LAYER M4 ;
        RECT  0 148.764 0.192 148.788 ;
    END
  END rsp_data[956]
  PIN rsp_data[957]
    DIRECTION INPUT ;
    USE SIGNAL ;
    PORT
      LAYER M4 ;
        RECT  0 149.052 0.192 149.076 ;
    END
  END rsp_data[957]
  PIN rsp_data[958]
    DIRECTION INPUT ;
    USE SIGNAL ;
    PORT
      LAYER M4 ;
        RECT  0 149.388 0.192 149.412 ;
    END
  END rsp_data[958]
  PIN rsp_data[959]
    DIRECTION INPUT ;
    USE SIGNAL ;
    PORT
      LAYER M4 ;
        RECT  0 149.724 0.192 149.748 ;
    END
  END rsp_data[959]
  PIN rsp_data[960]
    DIRECTION INPUT ;
    USE SIGNAL ;
    PORT
      LAYER M4 ;
        RECT  0 150.06 0.192 150.084 ;
    END
  END rsp_data[960]
  PIN rsp_data[961]
    DIRECTION INPUT ;
    USE SIGNAL ;
    PORT
      LAYER M4 ;
        RECT  0 150.396 0.192 150.42 ;
    END
  END rsp_data[961]
  PIN rsp_data[962]
    DIRECTION INPUT ;
    USE SIGNAL ;
    PORT
      LAYER M4 ;
        RECT  0 150.732 0.192 150.756 ;
    END
  END rsp_data[962]
  PIN rsp_data[963]
    DIRECTION INPUT ;
    USE SIGNAL ;
    PORT
      LAYER M4 ;
        RECT  0 151.02 0.192 151.044 ;
    END
  END rsp_data[963]
  PIN rsp_data[964]
    DIRECTION INPUT ;
    USE SIGNAL ;
    PORT
      LAYER M4 ;
        RECT  0 151.356 0.192 151.38 ;
    END
  END rsp_data[964]
  PIN rsp_data[965]
    DIRECTION INPUT ;
    USE SIGNAL ;
    PORT
      LAYER M4 ;
        RECT  0 151.692 0.192 151.716 ;
    END
  END rsp_data[965]
  PIN rsp_data[966]
    DIRECTION INPUT ;
    USE SIGNAL ;
    PORT
      LAYER M4 ;
        RECT  0 152.028 0.192 152.052 ;
    END
  END rsp_data[966]
  PIN rsp_data[967]
    DIRECTION INPUT ;
    USE SIGNAL ;
    PORT
      LAYER M4 ;
        RECT  0 152.364 0.192 152.388 ;
    END
  END rsp_data[967]
  PIN rsp_data[968]
    DIRECTION INPUT ;
    USE SIGNAL ;
    PORT
      LAYER M4 ;
        RECT  0 152.652 0.192 152.676 ;
    END
  END rsp_data[968]
  PIN rsp_data[969]
    DIRECTION INPUT ;
    USE SIGNAL ;
    PORT
      LAYER M4 ;
        RECT  0 152.988 0.192 153.012 ;
    END
  END rsp_data[969]
  PIN rsp_data[970]
    DIRECTION INPUT ;
    USE SIGNAL ;
    PORT
      LAYER M4 ;
        RECT  0 153.324 0.192 153.348 ;
    END
  END rsp_data[970]
  PIN rsp_data[971]
    DIRECTION INPUT ;
    USE SIGNAL ;
    PORT
      LAYER M4 ;
        RECT  0 153.66 0.192 153.684 ;
    END
  END rsp_data[971]
  PIN rsp_data[972]
    DIRECTION INPUT ;
    USE SIGNAL ;
    PORT
      LAYER M4 ;
        RECT  0 153.996 0.192 154.02 ;
    END
  END rsp_data[972]
  PIN rsp_data[973]
    DIRECTION INPUT ;
    USE SIGNAL ;
    PORT
      LAYER M4 ;
        RECT  0 154.284 0.192 154.308 ;
    END
  END rsp_data[973]
  PIN rsp_data[974]
    DIRECTION INPUT ;
    USE SIGNAL ;
    PORT
      LAYER M4 ;
        RECT  0 154.62 0.192 154.644 ;
    END
  END rsp_data[974]
  PIN rsp_data[975]
    DIRECTION INPUT ;
    USE SIGNAL ;
    PORT
      LAYER M4 ;
        RECT  0 154.956 0.192 154.98 ;
    END
  END rsp_data[975]
  PIN rsp_data[976]
    DIRECTION INPUT ;
    USE SIGNAL ;
    PORT
      LAYER M4 ;
        RECT  0 155.292 0.192 155.316 ;
    END
  END rsp_data[976]
  PIN rsp_data[977]
    DIRECTION INPUT ;
    USE SIGNAL ;
    PORT
      LAYER M4 ;
        RECT  0 155.628 0.192 155.652 ;
    END
  END rsp_data[977]
  PIN rsp_data[978]
    DIRECTION INPUT ;
    USE SIGNAL ;
    PORT
      LAYER M4 ;
        RECT  0 155.916 0.192 155.94 ;
    END
  END rsp_data[978]
  PIN rsp_data[979]
    DIRECTION INPUT ;
    USE SIGNAL ;
    PORT
      LAYER M4 ;
        RECT  0 156.252 0.192 156.276 ;
    END
  END rsp_data[979]
  PIN rsp_data[980]
    DIRECTION INPUT ;
    USE SIGNAL ;
    PORT
      LAYER M4 ;
        RECT  0 156.588 0.192 156.612 ;
    END
  END rsp_data[980]
  PIN rsp_data[981]
    DIRECTION INPUT ;
    USE SIGNAL ;
    PORT
      LAYER M4 ;
        RECT  0 156.924 0.192 156.948 ;
    END
  END rsp_data[981]
  PIN rsp_data[982]
    DIRECTION INPUT ;
    USE SIGNAL ;
    PORT
      LAYER M4 ;
        RECT  0 157.26 0.192 157.284 ;
    END
  END rsp_data[982]
  PIN rsp_data[983]
    DIRECTION INPUT ;
    USE SIGNAL ;
    PORT
      LAYER M4 ;
        RECT  0 157.548 0.192 157.572 ;
    END
  END rsp_data[983]
  PIN rsp_data[984]
    DIRECTION INPUT ;
    USE SIGNAL ;
    PORT
      LAYER M4 ;
        RECT  0 157.884 0.192 157.908 ;
    END
  END rsp_data[984]
  PIN rsp_data[985]
    DIRECTION INPUT ;
    USE SIGNAL ;
    PORT
      LAYER M4 ;
        RECT  0 158.22 0.192 158.244 ;
    END
  END rsp_data[985]
  PIN rsp_data[986]
    DIRECTION INPUT ;
    USE SIGNAL ;
    PORT
      LAYER M4 ;
        RECT  0 158.556 0.192 158.58 ;
    END
  END rsp_data[986]
  PIN rsp_data[987]
    DIRECTION INPUT ;
    USE SIGNAL ;
    PORT
      LAYER M4 ;
        RECT  0 158.892 0.192 158.916 ;
    END
  END rsp_data[987]
  PIN rsp_data[988]
    DIRECTION INPUT ;
    USE SIGNAL ;
    PORT
      LAYER M4 ;
        RECT  0 159.18 0.192 159.204 ;
    END
  END rsp_data[988]
  PIN rsp_data[989]
    DIRECTION INPUT ;
    USE SIGNAL ;
    PORT
      LAYER M4 ;
        RECT  0 159.516 0.192 159.54 ;
    END
  END rsp_data[989]
  PIN rsp_data[990]
    DIRECTION INPUT ;
    USE SIGNAL ;
    PORT
      LAYER M4 ;
        RECT  0 159.852 0.192 159.876 ;
    END
  END rsp_data[990]
  PIN rsp_data[991]
    DIRECTION INPUT ;
    USE SIGNAL ;
    PORT
      LAYER M4 ;
        RECT  0 160.188 0.192 160.212 ;
    END
  END rsp_data[991]
  PIN rsp_data[992]
    DIRECTION INPUT ;
    USE SIGNAL ;
    PORT
      LAYER M4 ;
        RECT  0 160.524 0.192 160.548 ;
    END
  END rsp_data[992]
  PIN rsp_data[993]
    DIRECTION INPUT ;
    USE SIGNAL ;
    PORT
      LAYER M4 ;
        RECT  0 160.812 0.192 160.836 ;
    END
  END rsp_data[993]
  PIN rsp_data[994]
    DIRECTION INPUT ;
    USE SIGNAL ;
    PORT
      LAYER M4 ;
        RECT  0 161.148 0.192 161.172 ;
    END
  END rsp_data[994]
  PIN rsp_data[995]
    DIRECTION INPUT ;
    USE SIGNAL ;
    PORT
      LAYER M4 ;
        RECT  0 161.484 0.192 161.508 ;
    END
  END rsp_data[995]
  PIN rsp_data[996]
    DIRECTION INPUT ;
    USE SIGNAL ;
    PORT
      LAYER M4 ;
        RECT  0 161.82 0.192 161.844 ;
    END
  END rsp_data[996]
  PIN rsp_data[997]
    DIRECTION INPUT ;
    USE SIGNAL ;
    PORT
      LAYER M4 ;
        RECT  0 162.156 0.192 162.18 ;
    END
  END rsp_data[997]
  PIN rsp_data[998]
    DIRECTION INPUT ;
    USE SIGNAL ;
    PORT
      LAYER M4 ;
        RECT  0 162.444 0.192 162.468 ;
    END
  END rsp_data[998]
  PIN rsp_data[999]
    DIRECTION INPUT ;
    USE SIGNAL ;
    PORT
      LAYER M4 ;
        RECT  0 162.78 0.192 162.804 ;
    END
  END rsp_data[999]
  PIN rst_n[0]
    DIRECTION INPUT ;
    USE SIGNAL ;
    PORT
      LAYER M5 ;
        RECT  108.396 86.304 108.42 86.496 ;
    END
  END rst_n[0]
  PIN si[0]
    DIRECTION INPUT ;
    USE SIGNAL ;
    PORT
      LAYER M4 ;
        RECT  215.808 11.628 216 11.652 ;
    END
  END si[0]
  PIN si[100]
    DIRECTION INPUT ;
    USE SIGNAL ;
    PORT
      LAYER M4 ;
        RECT  215.808 41.292 216 41.316 ;
    END
  END si[100]
  PIN si[101]
    DIRECTION INPUT ;
    USE SIGNAL ;
    PORT
      LAYER M4 ;
        RECT  215.808 41.58 216 41.604 ;
    END
  END si[101]
  PIN si[102]
    DIRECTION INPUT ;
    USE SIGNAL ;
    PORT
      LAYER M4 ;
        RECT  215.808 41.868 216 41.892 ;
    END
  END si[102]
  PIN si[103]
    DIRECTION INPUT ;
    USE SIGNAL ;
    PORT
      LAYER M4 ;
        RECT  215.808 42.204 216 42.228 ;
    END
  END si[103]
  PIN si[104]
    DIRECTION INPUT ;
    USE SIGNAL ;
    PORT
      LAYER M4 ;
        RECT  215.808 42.492 216 42.516 ;
    END
  END si[104]
  PIN si[105]
    DIRECTION INPUT ;
    USE SIGNAL ;
    PORT
      LAYER M4 ;
        RECT  215.808 42.78 216 42.804 ;
    END
  END si[105]
  PIN si[106]
    DIRECTION INPUT ;
    USE SIGNAL ;
    PORT
      LAYER M4 ;
        RECT  215.808 43.068 216 43.092 ;
    END
  END si[106]
  PIN si[107]
    DIRECTION INPUT ;
    USE SIGNAL ;
    PORT
      LAYER M4 ;
        RECT  215.808 43.356 216 43.38 ;
    END
  END si[107]
  PIN si[108]
    DIRECTION INPUT ;
    USE SIGNAL ;
    PORT
      LAYER M4 ;
        RECT  215.808 43.692 216 43.716 ;
    END
  END si[108]
  PIN si[109]
    DIRECTION INPUT ;
    USE SIGNAL ;
    PORT
      LAYER M4 ;
        RECT  215.808 43.98 216 44.004 ;
    END
  END si[109]
  PIN si[10]
    DIRECTION INPUT ;
    USE SIGNAL ;
    PORT
      LAYER M4 ;
        RECT  215.808 14.604 216 14.628 ;
    END
  END si[10]
  PIN si[110]
    DIRECTION INPUT ;
    USE SIGNAL ;
    PORT
      LAYER M4 ;
        RECT  215.808 44.268 216 44.292 ;
    END
  END si[110]
  PIN si[111]
    DIRECTION INPUT ;
    USE SIGNAL ;
    PORT
      LAYER M4 ;
        RECT  215.808 44.556 216 44.58 ;
    END
  END si[111]
  PIN si[112]
    DIRECTION INPUT ;
    USE SIGNAL ;
    PORT
      LAYER M4 ;
        RECT  215.808 44.844 216 44.868 ;
    END
  END si[112]
  PIN si[113]
    DIRECTION INPUT ;
    USE SIGNAL ;
    PORT
      LAYER M4 ;
        RECT  215.808 45.132 216 45.156 ;
    END
  END si[113]
  PIN si[114]
    DIRECTION INPUT ;
    USE SIGNAL ;
    PORT
      LAYER M4 ;
        RECT  215.808 45.468 216 45.492 ;
    END
  END si[114]
  PIN si[115]
    DIRECTION INPUT ;
    USE SIGNAL ;
    PORT
      LAYER M4 ;
        RECT  215.808 45.756 216 45.78 ;
    END
  END si[115]
  PIN si[116]
    DIRECTION INPUT ;
    USE SIGNAL ;
    PORT
      LAYER M4 ;
        RECT  215.808 46.044 216 46.068 ;
    END
  END si[116]
  PIN si[117]
    DIRECTION INPUT ;
    USE SIGNAL ;
    PORT
      LAYER M4 ;
        RECT  215.808 46.332 216 46.356 ;
    END
  END si[117]
  PIN si[118]
    DIRECTION INPUT ;
    USE SIGNAL ;
    PORT
      LAYER M4 ;
        RECT  215.808 46.62 216 46.644 ;
    END
  END si[118]
  PIN si[119]
    DIRECTION INPUT ;
    USE SIGNAL ;
    PORT
      LAYER M4 ;
        RECT  215.808 46.956 216 46.98 ;
    END
  END si[119]
  PIN si[11]
    DIRECTION INPUT ;
    USE SIGNAL ;
    PORT
      LAYER M4 ;
        RECT  215.808 14.892 216 14.916 ;
    END
  END si[11]
  PIN si[120]
    DIRECTION INPUT ;
    USE SIGNAL ;
    PORT
      LAYER M4 ;
        RECT  215.808 47.244 216 47.268 ;
    END
  END si[120]
  PIN si[121]
    DIRECTION INPUT ;
    USE SIGNAL ;
    PORT
      LAYER M4 ;
        RECT  215.808 47.532 216 47.556 ;
    END
  END si[121]
  PIN si[122]
    DIRECTION INPUT ;
    USE SIGNAL ;
    PORT
      LAYER M4 ;
        RECT  215.808 47.82 216 47.844 ;
    END
  END si[122]
  PIN si[123]
    DIRECTION INPUT ;
    USE SIGNAL ;
    PORT
      LAYER M4 ;
        RECT  215.808 48.108 216 48.132 ;
    END
  END si[123]
  PIN si[124]
    DIRECTION INPUT ;
    USE SIGNAL ;
    PORT
      LAYER M4 ;
        RECT  215.808 48.396 216 48.42 ;
    END
  END si[124]
  PIN si[125]
    DIRECTION INPUT ;
    USE SIGNAL ;
    PORT
      LAYER M4 ;
        RECT  215.808 48.732 216 48.756 ;
    END
  END si[125]
  PIN si[126]
    DIRECTION INPUT ;
    USE SIGNAL ;
    PORT
      LAYER M4 ;
        RECT  215.808 49.02 216 49.044 ;
    END
  END si[126]
  PIN si[127]
    DIRECTION INPUT ;
    USE SIGNAL ;
    PORT
      LAYER M4 ;
        RECT  215.808 49.308 216 49.332 ;
    END
  END si[127]
  PIN si[128]
    DIRECTION INPUT ;
    USE SIGNAL ;
    PORT
      LAYER M4 ;
        RECT  215.808 49.596 216 49.62 ;
    END
  END si[128]
  PIN si[129]
    DIRECTION INPUT ;
    USE SIGNAL ;
    PORT
      LAYER M4 ;
        RECT  215.808 49.884 216 49.908 ;
    END
  END si[129]
  PIN si[12]
    DIRECTION INPUT ;
    USE SIGNAL ;
    PORT
      LAYER M4 ;
        RECT  215.808 15.18 216 15.204 ;
    END
  END si[12]
  PIN si[130]
    DIRECTION INPUT ;
    USE SIGNAL ;
    PORT
      LAYER M4 ;
        RECT  215.808 50.172 216 50.196 ;
    END
  END si[130]
  PIN si[131]
    DIRECTION INPUT ;
    USE SIGNAL ;
    PORT
      LAYER M4 ;
        RECT  215.808 50.508 216 50.532 ;
    END
  END si[131]
  PIN si[132]
    DIRECTION INPUT ;
    USE SIGNAL ;
    PORT
      LAYER M4 ;
        RECT  215.808 50.796 216 50.82 ;
    END
  END si[132]
  PIN si[133]
    DIRECTION INPUT ;
    USE SIGNAL ;
    PORT
      LAYER M4 ;
        RECT  215.808 51.084 216 51.108 ;
    END
  END si[133]
  PIN si[134]
    DIRECTION INPUT ;
    USE SIGNAL ;
    PORT
      LAYER M4 ;
        RECT  215.808 51.372 216 51.396 ;
    END
  END si[134]
  PIN si[135]
    DIRECTION INPUT ;
    USE SIGNAL ;
    PORT
      LAYER M4 ;
        RECT  215.808 51.66 216 51.684 ;
    END
  END si[135]
  PIN si[136]
    DIRECTION INPUT ;
    USE SIGNAL ;
    PORT
      LAYER M4 ;
        RECT  215.808 51.996 216 52.02 ;
    END
  END si[136]
  PIN si[137]
    DIRECTION INPUT ;
    USE SIGNAL ;
    PORT
      LAYER M4 ;
        RECT  215.808 52.284 216 52.308 ;
    END
  END si[137]
  PIN si[138]
    DIRECTION INPUT ;
    USE SIGNAL ;
    PORT
      LAYER M4 ;
        RECT  215.808 52.572 216 52.596 ;
    END
  END si[138]
  PIN si[139]
    DIRECTION INPUT ;
    USE SIGNAL ;
    PORT
      LAYER M4 ;
        RECT  215.808 52.86 216 52.884 ;
    END
  END si[139]
  PIN si[13]
    DIRECTION INPUT ;
    USE SIGNAL ;
    PORT
      LAYER M4 ;
        RECT  215.808 15.468 216 15.492 ;
    END
  END si[13]
  PIN si[140]
    DIRECTION INPUT ;
    USE SIGNAL ;
    PORT
      LAYER M4 ;
        RECT  215.808 53.148 216 53.172 ;
    END
  END si[140]
  PIN si[141]
    DIRECTION INPUT ;
    USE SIGNAL ;
    PORT
      LAYER M4 ;
        RECT  215.808 53.436 216 53.46 ;
    END
  END si[141]
  PIN si[142]
    DIRECTION INPUT ;
    USE SIGNAL ;
    PORT
      LAYER M4 ;
        RECT  215.808 53.772 216 53.796 ;
    END
  END si[142]
  PIN si[143]
    DIRECTION INPUT ;
    USE SIGNAL ;
    PORT
      LAYER M4 ;
        RECT  215.808 54.06 216 54.084 ;
    END
  END si[143]
  PIN si[144]
    DIRECTION INPUT ;
    USE SIGNAL ;
    PORT
      LAYER M4 ;
        RECT  215.808 54.348 216 54.372 ;
    END
  END si[144]
  PIN si[145]
    DIRECTION INPUT ;
    USE SIGNAL ;
    PORT
      LAYER M4 ;
        RECT  215.808 54.636 216 54.66 ;
    END
  END si[145]
  PIN si[146]
    DIRECTION INPUT ;
    USE SIGNAL ;
    PORT
      LAYER M4 ;
        RECT  215.808 54.924 216 54.948 ;
    END
  END si[146]
  PIN si[147]
    DIRECTION INPUT ;
    USE SIGNAL ;
    PORT
      LAYER M4 ;
        RECT  215.808 55.26 216 55.284 ;
    END
  END si[147]
  PIN si[148]
    DIRECTION INPUT ;
    USE SIGNAL ;
    PORT
      LAYER M4 ;
        RECT  215.808 55.548 216 55.572 ;
    END
  END si[148]
  PIN si[149]
    DIRECTION INPUT ;
    USE SIGNAL ;
    PORT
      LAYER M4 ;
        RECT  215.808 55.836 216 55.86 ;
    END
  END si[149]
  PIN si[14]
    DIRECTION INPUT ;
    USE SIGNAL ;
    PORT
      LAYER M4 ;
        RECT  215.808 15.804 216 15.828 ;
    END
  END si[14]
  PIN si[150]
    DIRECTION INPUT ;
    USE SIGNAL ;
    PORT
      LAYER M4 ;
        RECT  215.808 56.124 216 56.148 ;
    END
  END si[150]
  PIN si[151]
    DIRECTION INPUT ;
    USE SIGNAL ;
    PORT
      LAYER M4 ;
        RECT  215.808 56.412 216 56.436 ;
    END
  END si[151]
  PIN si[152]
    DIRECTION INPUT ;
    USE SIGNAL ;
    PORT
      LAYER M4 ;
        RECT  215.808 56.7 216 56.724 ;
    END
  END si[152]
  PIN si[153]
    DIRECTION INPUT ;
    USE SIGNAL ;
    PORT
      LAYER M4 ;
        RECT  215.808 57.036 216 57.06 ;
    END
  END si[153]
  PIN si[154]
    DIRECTION INPUT ;
    USE SIGNAL ;
    PORT
      LAYER M4 ;
        RECT  215.808 57.324 216 57.348 ;
    END
  END si[154]
  PIN si[155]
    DIRECTION INPUT ;
    USE SIGNAL ;
    PORT
      LAYER M4 ;
        RECT  215.808 57.612 216 57.636 ;
    END
  END si[155]
  PIN si[156]
    DIRECTION INPUT ;
    USE SIGNAL ;
    PORT
      LAYER M4 ;
        RECT  215.808 57.9 216 57.924 ;
    END
  END si[156]
  PIN si[157]
    DIRECTION INPUT ;
    USE SIGNAL ;
    PORT
      LAYER M4 ;
        RECT  215.808 58.188 216 58.212 ;
    END
  END si[157]
  PIN si[158]
    DIRECTION INPUT ;
    USE SIGNAL ;
    PORT
      LAYER M4 ;
        RECT  215.808 58.524 216 58.548 ;
    END
  END si[158]
  PIN si[159]
    DIRECTION INPUT ;
    USE SIGNAL ;
    PORT
      LAYER M4 ;
        RECT  215.808 58.812 216 58.836 ;
    END
  END si[159]
  PIN si[15]
    DIRECTION INPUT ;
    USE SIGNAL ;
    PORT
      LAYER M4 ;
        RECT  215.808 16.092 216 16.116 ;
    END
  END si[15]
  PIN si[160]
    DIRECTION INPUT ;
    USE SIGNAL ;
    PORT
      LAYER M4 ;
        RECT  215.808 59.1 216 59.124 ;
    END
  END si[160]
  PIN si[161]
    DIRECTION INPUT ;
    USE SIGNAL ;
    PORT
      LAYER M4 ;
        RECT  215.808 59.388 216 59.412 ;
    END
  END si[161]
  PIN si[162]
    DIRECTION INPUT ;
    USE SIGNAL ;
    PORT
      LAYER M4 ;
        RECT  215.808 59.676 216 59.7 ;
    END
  END si[162]
  PIN si[163]
    DIRECTION INPUT ;
    USE SIGNAL ;
    PORT
      LAYER M4 ;
        RECT  215.808 59.964 216 59.988 ;
    END
  END si[163]
  PIN si[164]
    DIRECTION INPUT ;
    USE SIGNAL ;
    PORT
      LAYER M4 ;
        RECT  215.808 60.3 216 60.324 ;
    END
  END si[164]
  PIN si[165]
    DIRECTION INPUT ;
    USE SIGNAL ;
    PORT
      LAYER M4 ;
        RECT  215.808 60.588 216 60.612 ;
    END
  END si[165]
  PIN si[166]
    DIRECTION INPUT ;
    USE SIGNAL ;
    PORT
      LAYER M4 ;
        RECT  215.808 60.876 216 60.9 ;
    END
  END si[166]
  PIN si[167]
    DIRECTION INPUT ;
    USE SIGNAL ;
    PORT
      LAYER M4 ;
        RECT  215.808 61.164 216 61.188 ;
    END
  END si[167]
  PIN si[168]
    DIRECTION INPUT ;
    USE SIGNAL ;
    PORT
      LAYER M4 ;
        RECT  215.808 61.452 216 61.476 ;
    END
  END si[168]
  PIN si[169]
    DIRECTION INPUT ;
    USE SIGNAL ;
    PORT
      LAYER M4 ;
        RECT  215.808 61.788 216 61.812 ;
    END
  END si[169]
  PIN si[16]
    DIRECTION INPUT ;
    USE SIGNAL ;
    PORT
      LAYER M4 ;
        RECT  215.808 16.38 216 16.404 ;
    END
  END si[16]
  PIN si[170]
    DIRECTION INPUT ;
    USE SIGNAL ;
    PORT
      LAYER M4 ;
        RECT  215.808 62.076 216 62.1 ;
    END
  END si[170]
  PIN si[171]
    DIRECTION INPUT ;
    USE SIGNAL ;
    PORT
      LAYER M4 ;
        RECT  215.808 62.364 216 62.388 ;
    END
  END si[171]
  PIN si[172]
    DIRECTION INPUT ;
    USE SIGNAL ;
    PORT
      LAYER M4 ;
        RECT  215.808 62.652 216 62.676 ;
    END
  END si[172]
  PIN si[173]
    DIRECTION INPUT ;
    USE SIGNAL ;
    PORT
      LAYER M4 ;
        RECT  215.808 62.94 216 62.964 ;
    END
  END si[173]
  PIN si[174]
    DIRECTION INPUT ;
    USE SIGNAL ;
    PORT
      LAYER M4 ;
        RECT  215.808 63.228 216 63.252 ;
    END
  END si[174]
  PIN si[175]
    DIRECTION INPUT ;
    USE SIGNAL ;
    PORT
      LAYER M4 ;
        RECT  215.808 63.564 216 63.588 ;
    END
  END si[175]
  PIN si[176]
    DIRECTION INPUT ;
    USE SIGNAL ;
    PORT
      LAYER M4 ;
        RECT  215.808 63.852 216 63.876 ;
    END
  END si[176]
  PIN si[177]
    DIRECTION INPUT ;
    USE SIGNAL ;
    PORT
      LAYER M4 ;
        RECT  215.808 64.14 216 64.164 ;
    END
  END si[177]
  PIN si[178]
    DIRECTION INPUT ;
    USE SIGNAL ;
    PORT
      LAYER M4 ;
        RECT  215.808 64.428 216 64.452 ;
    END
  END si[178]
  PIN si[179]
    DIRECTION INPUT ;
    USE SIGNAL ;
    PORT
      LAYER M4 ;
        RECT  215.808 64.716 216 64.74 ;
    END
  END si[179]
  PIN si[17]
    DIRECTION INPUT ;
    USE SIGNAL ;
    PORT
      LAYER M4 ;
        RECT  215.808 16.668 216 16.692 ;
    END
  END si[17]
  PIN si[180]
    DIRECTION INPUT ;
    USE SIGNAL ;
    PORT
      LAYER M4 ;
        RECT  215.808 65.052 216 65.076 ;
    END
  END si[180]
  PIN si[181]
    DIRECTION INPUT ;
    USE SIGNAL ;
    PORT
      LAYER M4 ;
        RECT  215.808 65.34 216 65.364 ;
    END
  END si[181]
  PIN si[182]
    DIRECTION INPUT ;
    USE SIGNAL ;
    PORT
      LAYER M4 ;
        RECT  215.808 65.628 216 65.652 ;
    END
  END si[182]
  PIN si[183]
    DIRECTION INPUT ;
    USE SIGNAL ;
    PORT
      LAYER M4 ;
        RECT  215.808 65.916 216 65.94 ;
    END
  END si[183]
  PIN si[184]
    DIRECTION INPUT ;
    USE SIGNAL ;
    PORT
      LAYER M4 ;
        RECT  215.808 66.204 216 66.228 ;
    END
  END si[184]
  PIN si[185]
    DIRECTION INPUT ;
    USE SIGNAL ;
    PORT
      LAYER M4 ;
        RECT  215.808 66.492 216 66.516 ;
    END
  END si[185]
  PIN si[186]
    DIRECTION INPUT ;
    USE SIGNAL ;
    PORT
      LAYER M4 ;
        RECT  215.808 66.828 216 66.852 ;
    END
  END si[186]
  PIN si[187]
    DIRECTION INPUT ;
    USE SIGNAL ;
    PORT
      LAYER M4 ;
        RECT  215.808 67.116 216 67.14 ;
    END
  END si[187]
  PIN si[188]
    DIRECTION INPUT ;
    USE SIGNAL ;
    PORT
      LAYER M4 ;
        RECT  215.808 67.404 216 67.428 ;
    END
  END si[188]
  PIN si[189]
    DIRECTION INPUT ;
    USE SIGNAL ;
    PORT
      LAYER M4 ;
        RECT  215.808 67.692 216 67.716 ;
    END
  END si[189]
  PIN si[18]
    DIRECTION INPUT ;
    USE SIGNAL ;
    PORT
      LAYER M4 ;
        RECT  215.808 16.956 216 16.98 ;
    END
  END si[18]
  PIN si[190]
    DIRECTION INPUT ;
    USE SIGNAL ;
    PORT
      LAYER M4 ;
        RECT  215.808 67.98 216 68.004 ;
    END
  END si[190]
  PIN si[191]
    DIRECTION INPUT ;
    USE SIGNAL ;
    PORT
      LAYER M4 ;
        RECT  215.808 68.268 216 68.292 ;
    END
  END si[191]
  PIN si[192]
    DIRECTION INPUT ;
    USE SIGNAL ;
    PORT
      LAYER M4 ;
        RECT  215.808 68.604 216 68.628 ;
    END
  END si[192]
  PIN si[193]
    DIRECTION INPUT ;
    USE SIGNAL ;
    PORT
      LAYER M4 ;
        RECT  215.808 68.892 216 68.916 ;
    END
  END si[193]
  PIN si[194]
    DIRECTION INPUT ;
    USE SIGNAL ;
    PORT
      LAYER M4 ;
        RECT  215.808 69.18 216 69.204 ;
    END
  END si[194]
  PIN si[195]
    DIRECTION INPUT ;
    USE SIGNAL ;
    PORT
      LAYER M4 ;
        RECT  215.808 69.468 216 69.492 ;
    END
  END si[195]
  PIN si[196]
    DIRECTION INPUT ;
    USE SIGNAL ;
    PORT
      LAYER M4 ;
        RECT  215.808 69.756 216 69.78 ;
    END
  END si[196]
  PIN si[197]
    DIRECTION INPUT ;
    USE SIGNAL ;
    PORT
      LAYER M4 ;
        RECT  215.808 70.092 216 70.116 ;
    END
  END si[197]
  PIN si[198]
    DIRECTION INPUT ;
    USE SIGNAL ;
    PORT
      LAYER M4 ;
        RECT  215.808 70.38 216 70.404 ;
    END
  END si[198]
  PIN si[199]
    DIRECTION INPUT ;
    USE SIGNAL ;
    PORT
      LAYER M4 ;
        RECT  215.808 70.668 216 70.692 ;
    END
  END si[199]
  PIN si[19]
    DIRECTION INPUT ;
    USE SIGNAL ;
    PORT
      LAYER M4 ;
        RECT  215.808 17.244 216 17.268 ;
    END
  END si[19]
  PIN si[1]
    DIRECTION INPUT ;
    USE SIGNAL ;
    PORT
      LAYER M4 ;
        RECT  215.808 11.916 216 11.94 ;
    END
  END si[1]
  PIN si[200]
    DIRECTION INPUT ;
    USE SIGNAL ;
    PORT
      LAYER M4 ;
        RECT  215.808 70.956 216 70.98 ;
    END
  END si[200]
  PIN si[201]
    DIRECTION INPUT ;
    USE SIGNAL ;
    PORT
      LAYER M4 ;
        RECT  215.808 71.244 216 71.268 ;
    END
  END si[201]
  PIN si[202]
    DIRECTION INPUT ;
    USE SIGNAL ;
    PORT
      LAYER M4 ;
        RECT  215.808 71.532 216 71.556 ;
    END
  END si[202]
  PIN si[203]
    DIRECTION INPUT ;
    USE SIGNAL ;
    PORT
      LAYER M4 ;
        RECT  215.808 71.868 216 71.892 ;
    END
  END si[203]
  PIN si[204]
    DIRECTION INPUT ;
    USE SIGNAL ;
    PORT
      LAYER M4 ;
        RECT  215.808 72.156 216 72.18 ;
    END
  END si[204]
  PIN si[205]
    DIRECTION INPUT ;
    USE SIGNAL ;
    PORT
      LAYER M4 ;
        RECT  215.808 72.444 216 72.468 ;
    END
  END si[205]
  PIN si[206]
    DIRECTION INPUT ;
    USE SIGNAL ;
    PORT
      LAYER M4 ;
        RECT  215.808 72.732 216 72.756 ;
    END
  END si[206]
  PIN si[207]
    DIRECTION INPUT ;
    USE SIGNAL ;
    PORT
      LAYER M4 ;
        RECT  215.808 73.02 216 73.044 ;
    END
  END si[207]
  PIN si[208]
    DIRECTION INPUT ;
    USE SIGNAL ;
    PORT
      LAYER M4 ;
        RECT  215.808 73.356 216 73.38 ;
    END
  END si[208]
  PIN si[209]
    DIRECTION INPUT ;
    USE SIGNAL ;
    PORT
      LAYER M4 ;
        RECT  215.808 73.644 216 73.668 ;
    END
  END si[209]
  PIN si[20]
    DIRECTION INPUT ;
    USE SIGNAL ;
    PORT
      LAYER M4 ;
        RECT  215.808 17.58 216 17.604 ;
    END
  END si[20]
  PIN si[210]
    DIRECTION INPUT ;
    USE SIGNAL ;
    PORT
      LAYER M4 ;
        RECT  215.808 73.932 216 73.956 ;
    END
  END si[210]
  PIN si[211]
    DIRECTION INPUT ;
    USE SIGNAL ;
    PORT
      LAYER M4 ;
        RECT  215.808 74.22 216 74.244 ;
    END
  END si[211]
  PIN si[212]
    DIRECTION INPUT ;
    USE SIGNAL ;
    PORT
      LAYER M4 ;
        RECT  215.808 74.508 216 74.532 ;
    END
  END si[212]
  PIN si[213]
    DIRECTION INPUT ;
    USE SIGNAL ;
    PORT
      LAYER M4 ;
        RECT  215.808 74.796 216 74.82 ;
    END
  END si[213]
  PIN si[214]
    DIRECTION INPUT ;
    USE SIGNAL ;
    PORT
      LAYER M4 ;
        RECT  215.808 75.132 216 75.156 ;
    END
  END si[214]
  PIN si[215]
    DIRECTION INPUT ;
    USE SIGNAL ;
    PORT
      LAYER M4 ;
        RECT  215.808 75.42 216 75.444 ;
    END
  END si[215]
  PIN si[216]
    DIRECTION INPUT ;
    USE SIGNAL ;
    PORT
      LAYER M4 ;
        RECT  215.808 75.708 216 75.732 ;
    END
  END si[216]
  PIN si[217]
    DIRECTION INPUT ;
    USE SIGNAL ;
    PORT
      LAYER M4 ;
        RECT  215.808 75.996 216 76.02 ;
    END
  END si[217]
  PIN si[218]
    DIRECTION INPUT ;
    USE SIGNAL ;
    PORT
      LAYER M4 ;
        RECT  215.808 76.284 216 76.308 ;
    END
  END si[218]
  PIN si[219]
    DIRECTION INPUT ;
    USE SIGNAL ;
    PORT
      LAYER M4 ;
        RECT  215.808 76.62 216 76.644 ;
    END
  END si[219]
  PIN si[21]
    DIRECTION INPUT ;
    USE SIGNAL ;
    PORT
      LAYER M4 ;
        RECT  215.808 17.868 216 17.892 ;
    END
  END si[21]
  PIN si[220]
    DIRECTION INPUT ;
    USE SIGNAL ;
    PORT
      LAYER M4 ;
        RECT  215.808 76.908 216 76.932 ;
    END
  END si[220]
  PIN si[221]
    DIRECTION INPUT ;
    USE SIGNAL ;
    PORT
      LAYER M4 ;
        RECT  215.808 77.196 216 77.22 ;
    END
  END si[221]
  PIN si[222]
    DIRECTION INPUT ;
    USE SIGNAL ;
    PORT
      LAYER M4 ;
        RECT  215.808 77.484 216 77.508 ;
    END
  END si[222]
  PIN si[223]
    DIRECTION INPUT ;
    USE SIGNAL ;
    PORT
      LAYER M4 ;
        RECT  215.808 77.772 216 77.796 ;
    END
  END si[223]
  PIN si[224]
    DIRECTION INPUT ;
    USE SIGNAL ;
    PORT
      LAYER M4 ;
        RECT  215.808 78.06 216 78.084 ;
    END
  END si[224]
  PIN si[225]
    DIRECTION INPUT ;
    USE SIGNAL ;
    PORT
      LAYER M4 ;
        RECT  215.808 78.396 216 78.42 ;
    END
  END si[225]
  PIN si[226]
    DIRECTION INPUT ;
    USE SIGNAL ;
    PORT
      LAYER M4 ;
        RECT  215.808 78.684 216 78.708 ;
    END
  END si[226]
  PIN si[227]
    DIRECTION INPUT ;
    USE SIGNAL ;
    PORT
      LAYER M4 ;
        RECT  215.808 78.972 216 78.996 ;
    END
  END si[227]
  PIN si[228]
    DIRECTION INPUT ;
    USE SIGNAL ;
    PORT
      LAYER M4 ;
        RECT  215.808 79.26 216 79.284 ;
    END
  END si[228]
  PIN si[229]
    DIRECTION INPUT ;
    USE SIGNAL ;
    PORT
      LAYER M4 ;
        RECT  215.808 79.548 216 79.572 ;
    END
  END si[229]
  PIN si[22]
    DIRECTION INPUT ;
    USE SIGNAL ;
    PORT
      LAYER M4 ;
        RECT  215.808 18.156 216 18.18 ;
    END
  END si[22]
  PIN si[230]
    DIRECTION INPUT ;
    USE SIGNAL ;
    PORT
      LAYER M4 ;
        RECT  215.808 79.884 216 79.908 ;
    END
  END si[230]
  PIN si[231]
    DIRECTION INPUT ;
    USE SIGNAL ;
    PORT
      LAYER M4 ;
        RECT  215.808 80.172 216 80.196 ;
    END
  END si[231]
  PIN si[232]
    DIRECTION INPUT ;
    USE SIGNAL ;
    PORT
      LAYER M4 ;
        RECT  215.808 80.46 216 80.484 ;
    END
  END si[232]
  PIN si[233]
    DIRECTION INPUT ;
    USE SIGNAL ;
    PORT
      LAYER M4 ;
        RECT  215.808 80.748 216 80.772 ;
    END
  END si[233]
  PIN si[234]
    DIRECTION INPUT ;
    USE SIGNAL ;
    PORT
      LAYER M4 ;
        RECT  215.808 81.036 216 81.06 ;
    END
  END si[234]
  PIN si[235]
    DIRECTION INPUT ;
    USE SIGNAL ;
    PORT
      LAYER M4 ;
        RECT  215.808 81.324 216 81.348 ;
    END
  END si[235]
  PIN si[236]
    DIRECTION INPUT ;
    USE SIGNAL ;
    PORT
      LAYER M4 ;
        RECT  215.808 81.66 216 81.684 ;
    END
  END si[236]
  PIN si[237]
    DIRECTION INPUT ;
    USE SIGNAL ;
    PORT
      LAYER M4 ;
        RECT  215.808 81.948 216 81.972 ;
    END
  END si[237]
  PIN si[238]
    DIRECTION INPUT ;
    USE SIGNAL ;
    PORT
      LAYER M4 ;
        RECT  215.808 82.236 216 82.26 ;
    END
  END si[238]
  PIN si[239]
    DIRECTION INPUT ;
    USE SIGNAL ;
    PORT
      LAYER M4 ;
        RECT  215.808 82.524 216 82.548 ;
    END
  END si[239]
  PIN si[23]
    DIRECTION INPUT ;
    USE SIGNAL ;
    PORT
      LAYER M4 ;
        RECT  215.808 18.444 216 18.468 ;
    END
  END si[23]
  PIN si[240]
    DIRECTION INPUT ;
    USE SIGNAL ;
    PORT
      LAYER M4 ;
        RECT  215.808 82.812 216 82.836 ;
    END
  END si[240]
  PIN si[241]
    DIRECTION INPUT ;
    USE SIGNAL ;
    PORT
      LAYER M4 ;
        RECT  215.808 83.148 216 83.172 ;
    END
  END si[241]
  PIN si[242]
    DIRECTION INPUT ;
    USE SIGNAL ;
    PORT
      LAYER M4 ;
        RECT  215.808 83.436 216 83.46 ;
    END
  END si[242]
  PIN si[243]
    DIRECTION INPUT ;
    USE SIGNAL ;
    PORT
      LAYER M4 ;
        RECT  215.808 83.724 216 83.748 ;
    END
  END si[243]
  PIN si[244]
    DIRECTION INPUT ;
    USE SIGNAL ;
    PORT
      LAYER M4 ;
        RECT  215.808 84.012 216 84.036 ;
    END
  END si[244]
  PIN si[245]
    DIRECTION INPUT ;
    USE SIGNAL ;
    PORT
      LAYER M4 ;
        RECT  215.808 84.3 216 84.324 ;
    END
  END si[245]
  PIN si[246]
    DIRECTION INPUT ;
    USE SIGNAL ;
    PORT
      LAYER M4 ;
        RECT  215.808 84.588 216 84.612 ;
    END
  END si[246]
  PIN si[247]
    DIRECTION INPUT ;
    USE SIGNAL ;
    PORT
      LAYER M4 ;
        RECT  215.808 84.924 216 84.948 ;
    END
  END si[247]
  PIN si[248]
    DIRECTION INPUT ;
    USE SIGNAL ;
    PORT
      LAYER M4 ;
        RECT  215.808 85.212 216 85.236 ;
    END
  END si[248]
  PIN si[249]
    DIRECTION INPUT ;
    USE SIGNAL ;
    PORT
      LAYER M4 ;
        RECT  215.808 85.5 216 85.524 ;
    END
  END si[249]
  PIN si[24]
    DIRECTION INPUT ;
    USE SIGNAL ;
    PORT
      LAYER M4 ;
        RECT  215.808 18.732 216 18.756 ;
    END
  END si[24]
  PIN si[250]
    DIRECTION INPUT ;
    USE SIGNAL ;
    PORT
      LAYER M4 ;
        RECT  215.808 85.788 216 85.812 ;
    END
  END si[250]
  PIN si[251]
    DIRECTION INPUT ;
    USE SIGNAL ;
    PORT
      LAYER M4 ;
        RECT  215.808 86.076 216 86.1 ;
    END
  END si[251]
  PIN si[252]
    DIRECTION INPUT ;
    USE SIGNAL ;
    PORT
      LAYER M4 ;
        RECT  215.808 86.412 216 86.436 ;
    END
  END si[252]
  PIN si[253]
    DIRECTION INPUT ;
    USE SIGNAL ;
    PORT
      LAYER M4 ;
        RECT  215.808 86.7 216 86.724 ;
    END
  END si[253]
  PIN si[254]
    DIRECTION INPUT ;
    USE SIGNAL ;
    PORT
      LAYER M4 ;
        RECT  215.808 86.988 216 87.012 ;
    END
  END si[254]
  PIN si[255]
    DIRECTION INPUT ;
    USE SIGNAL ;
    PORT
      LAYER M4 ;
        RECT  215.808 87.276 216 87.3 ;
    END
  END si[255]
  PIN si[256]
    DIRECTION INPUT ;
    USE SIGNAL ;
    PORT
      LAYER M4 ;
        RECT  215.808 87.564 216 87.588 ;
    END
  END si[256]
  PIN si[257]
    DIRECTION INPUT ;
    USE SIGNAL ;
    PORT
      LAYER M4 ;
        RECT  215.808 87.852 216 87.876 ;
    END
  END si[257]
  PIN si[258]
    DIRECTION INPUT ;
    USE SIGNAL ;
    PORT
      LAYER M4 ;
        RECT  215.808 88.188 216 88.212 ;
    END
  END si[258]
  PIN si[259]
    DIRECTION INPUT ;
    USE SIGNAL ;
    PORT
      LAYER M4 ;
        RECT  215.808 88.476 216 88.5 ;
    END
  END si[259]
  PIN si[25]
    DIRECTION INPUT ;
    USE SIGNAL ;
    PORT
      LAYER M4 ;
        RECT  215.808 19.068 216 19.092 ;
    END
  END si[25]
  PIN si[260]
    DIRECTION INPUT ;
    USE SIGNAL ;
    PORT
      LAYER M4 ;
        RECT  215.808 88.764 216 88.788 ;
    END
  END si[260]
  PIN si[261]
    DIRECTION INPUT ;
    USE SIGNAL ;
    PORT
      LAYER M4 ;
        RECT  215.808 89.052 216 89.076 ;
    END
  END si[261]
  PIN si[262]
    DIRECTION INPUT ;
    USE SIGNAL ;
    PORT
      LAYER M4 ;
        RECT  215.808 89.34 216 89.364 ;
    END
  END si[262]
  PIN si[263]
    DIRECTION INPUT ;
    USE SIGNAL ;
    PORT
      LAYER M4 ;
        RECT  215.808 89.628 216 89.652 ;
    END
  END si[263]
  PIN si[264]
    DIRECTION INPUT ;
    USE SIGNAL ;
    PORT
      LAYER M4 ;
        RECT  215.808 89.964 216 89.988 ;
    END
  END si[264]
  PIN si[265]
    DIRECTION INPUT ;
    USE SIGNAL ;
    PORT
      LAYER M4 ;
        RECT  215.808 90.252 216 90.276 ;
    END
  END si[265]
  PIN si[266]
    DIRECTION INPUT ;
    USE SIGNAL ;
    PORT
      LAYER M4 ;
        RECT  215.808 90.54 216 90.564 ;
    END
  END si[266]
  PIN si[267]
    DIRECTION INPUT ;
    USE SIGNAL ;
    PORT
      LAYER M4 ;
        RECT  215.808 90.828 216 90.852 ;
    END
  END si[267]
  PIN si[268]
    DIRECTION INPUT ;
    USE SIGNAL ;
    PORT
      LAYER M4 ;
        RECT  215.808 91.116 216 91.14 ;
    END
  END si[268]
  PIN si[269]
    DIRECTION INPUT ;
    USE SIGNAL ;
    PORT
      LAYER M4 ;
        RECT  215.808 91.452 216 91.476 ;
    END
  END si[269]
  PIN si[26]
    DIRECTION INPUT ;
    USE SIGNAL ;
    PORT
      LAYER M4 ;
        RECT  215.808 19.356 216 19.38 ;
    END
  END si[26]
  PIN si[270]
    DIRECTION INPUT ;
    USE SIGNAL ;
    PORT
      LAYER M4 ;
        RECT  215.808 91.74 216 91.764 ;
    END
  END si[270]
  PIN si[271]
    DIRECTION INPUT ;
    USE SIGNAL ;
    PORT
      LAYER M4 ;
        RECT  215.808 92.028 216 92.052 ;
    END
  END si[271]
  PIN si[272]
    DIRECTION INPUT ;
    USE SIGNAL ;
    PORT
      LAYER M4 ;
        RECT  215.808 92.316 216 92.34 ;
    END
  END si[272]
  PIN si[273]
    DIRECTION INPUT ;
    USE SIGNAL ;
    PORT
      LAYER M4 ;
        RECT  215.808 92.604 216 92.628 ;
    END
  END si[273]
  PIN si[274]
    DIRECTION INPUT ;
    USE SIGNAL ;
    PORT
      LAYER M4 ;
        RECT  215.808 92.892 216 92.916 ;
    END
  END si[274]
  PIN si[275]
    DIRECTION INPUT ;
    USE SIGNAL ;
    PORT
      LAYER M4 ;
        RECT  215.808 93.228 216 93.252 ;
    END
  END si[275]
  PIN si[276]
    DIRECTION INPUT ;
    USE SIGNAL ;
    PORT
      LAYER M4 ;
        RECT  215.808 93.516 216 93.54 ;
    END
  END si[276]
  PIN si[277]
    DIRECTION INPUT ;
    USE SIGNAL ;
    PORT
      LAYER M4 ;
        RECT  215.808 93.804 216 93.828 ;
    END
  END si[277]
  PIN si[278]
    DIRECTION INPUT ;
    USE SIGNAL ;
    PORT
      LAYER M4 ;
        RECT  215.808 94.092 216 94.116 ;
    END
  END si[278]
  PIN si[279]
    DIRECTION INPUT ;
    USE SIGNAL ;
    PORT
      LAYER M4 ;
        RECT  215.808 94.38 216 94.404 ;
    END
  END si[279]
  PIN si[27]
    DIRECTION INPUT ;
    USE SIGNAL ;
    PORT
      LAYER M4 ;
        RECT  215.808 19.644 216 19.668 ;
    END
  END si[27]
  PIN si[280]
    DIRECTION INPUT ;
    USE SIGNAL ;
    PORT
      LAYER M4 ;
        RECT  215.808 94.716 216 94.74 ;
    END
  END si[280]
  PIN si[281]
    DIRECTION INPUT ;
    USE SIGNAL ;
    PORT
      LAYER M4 ;
        RECT  215.808 95.004 216 95.028 ;
    END
  END si[281]
  PIN si[282]
    DIRECTION INPUT ;
    USE SIGNAL ;
    PORT
      LAYER M4 ;
        RECT  215.808 95.292 216 95.316 ;
    END
  END si[282]
  PIN si[283]
    DIRECTION INPUT ;
    USE SIGNAL ;
    PORT
      LAYER M4 ;
        RECT  215.808 95.58 216 95.604 ;
    END
  END si[283]
  PIN si[284]
    DIRECTION INPUT ;
    USE SIGNAL ;
    PORT
      LAYER M4 ;
        RECT  215.808 95.868 216 95.892 ;
    END
  END si[284]
  PIN si[285]
    DIRECTION INPUT ;
    USE SIGNAL ;
    PORT
      LAYER M4 ;
        RECT  215.808 96.156 216 96.18 ;
    END
  END si[285]
  PIN si[286]
    DIRECTION INPUT ;
    USE SIGNAL ;
    PORT
      LAYER M4 ;
        RECT  215.808 96.492 216 96.516 ;
    END
  END si[286]
  PIN si[287]
    DIRECTION INPUT ;
    USE SIGNAL ;
    PORT
      LAYER M4 ;
        RECT  215.808 96.78 216 96.804 ;
    END
  END si[287]
  PIN si[288]
    DIRECTION INPUT ;
    USE SIGNAL ;
    PORT
      LAYER M4 ;
        RECT  215.808 97.068 216 97.092 ;
    END
  END si[288]
  PIN si[289]
    DIRECTION INPUT ;
    USE SIGNAL ;
    PORT
      LAYER M4 ;
        RECT  215.808 97.356 216 97.38 ;
    END
  END si[289]
  PIN si[28]
    DIRECTION INPUT ;
    USE SIGNAL ;
    PORT
      LAYER M4 ;
        RECT  215.808 19.932 216 19.956 ;
    END
  END si[28]
  PIN si[290]
    DIRECTION INPUT ;
    USE SIGNAL ;
    PORT
      LAYER M4 ;
        RECT  215.808 97.644 216 97.668 ;
    END
  END si[290]
  PIN si[291]
    DIRECTION INPUT ;
    USE SIGNAL ;
    PORT
      LAYER M4 ;
        RECT  215.808 97.98 216 98.004 ;
    END
  END si[291]
  PIN si[292]
    DIRECTION INPUT ;
    USE SIGNAL ;
    PORT
      LAYER M4 ;
        RECT  215.808 98.268 216 98.292 ;
    END
  END si[292]
  PIN si[293]
    DIRECTION INPUT ;
    USE SIGNAL ;
    PORT
      LAYER M4 ;
        RECT  215.808 98.556 216 98.58 ;
    END
  END si[293]
  PIN si[294]
    DIRECTION INPUT ;
    USE SIGNAL ;
    PORT
      LAYER M4 ;
        RECT  215.808 98.844 216 98.868 ;
    END
  END si[294]
  PIN si[295]
    DIRECTION INPUT ;
    USE SIGNAL ;
    PORT
      LAYER M4 ;
        RECT  215.808 99.132 216 99.156 ;
    END
  END si[295]
  PIN si[296]
    DIRECTION INPUT ;
    USE SIGNAL ;
    PORT
      LAYER M4 ;
        RECT  215.808 99.42 216 99.444 ;
    END
  END si[296]
  PIN si[297]
    DIRECTION INPUT ;
    USE SIGNAL ;
    PORT
      LAYER M4 ;
        RECT  215.808 99.756 216 99.78 ;
    END
  END si[297]
  PIN si[298]
    DIRECTION INPUT ;
    USE SIGNAL ;
    PORT
      LAYER M4 ;
        RECT  215.808 100.044 216 100.068 ;
    END
  END si[298]
  PIN si[299]
    DIRECTION INPUT ;
    USE SIGNAL ;
    PORT
      LAYER M4 ;
        RECT  215.808 100.332 216 100.356 ;
    END
  END si[299]
  PIN si[29]
    DIRECTION INPUT ;
    USE SIGNAL ;
    PORT
      LAYER M4 ;
        RECT  215.808 20.22 216 20.244 ;
    END
  END si[29]
  PIN si[2]
    DIRECTION INPUT ;
    USE SIGNAL ;
    PORT
      LAYER M4 ;
        RECT  215.808 12.204 216 12.228 ;
    END
  END si[2]
  PIN si[300]
    DIRECTION INPUT ;
    USE SIGNAL ;
    PORT
      LAYER M4 ;
        RECT  215.808 100.62 216 100.644 ;
    END
  END si[300]
  PIN si[301]
    DIRECTION INPUT ;
    USE SIGNAL ;
    PORT
      LAYER M4 ;
        RECT  215.808 100.908 216 100.932 ;
    END
  END si[301]
  PIN si[302]
    DIRECTION INPUT ;
    USE SIGNAL ;
    PORT
      LAYER M4 ;
        RECT  215.808 101.244 216 101.268 ;
    END
  END si[302]
  PIN si[303]
    DIRECTION INPUT ;
    USE SIGNAL ;
    PORT
      LAYER M4 ;
        RECT  215.808 101.532 216 101.556 ;
    END
  END si[303]
  PIN si[304]
    DIRECTION INPUT ;
    USE SIGNAL ;
    PORT
      LAYER M4 ;
        RECT  215.808 101.82 216 101.844 ;
    END
  END si[304]
  PIN si[305]
    DIRECTION INPUT ;
    USE SIGNAL ;
    PORT
      LAYER M4 ;
        RECT  215.808 102.108 216 102.132 ;
    END
  END si[305]
  PIN si[306]
    DIRECTION INPUT ;
    USE SIGNAL ;
    PORT
      LAYER M4 ;
        RECT  215.808 102.396 216 102.42 ;
    END
  END si[306]
  PIN si[307]
    DIRECTION INPUT ;
    USE SIGNAL ;
    PORT
      LAYER M4 ;
        RECT  215.808 102.684 216 102.708 ;
    END
  END si[307]
  PIN si[308]
    DIRECTION INPUT ;
    USE SIGNAL ;
    PORT
      LAYER M4 ;
        RECT  215.808 103.02 216 103.044 ;
    END
  END si[308]
  PIN si[309]
    DIRECTION INPUT ;
    USE SIGNAL ;
    PORT
      LAYER M4 ;
        RECT  215.808 103.308 216 103.332 ;
    END
  END si[309]
  PIN si[30]
    DIRECTION INPUT ;
    USE SIGNAL ;
    PORT
      LAYER M4 ;
        RECT  215.808 20.508 216 20.532 ;
    END
  END si[30]
  PIN si[310]
    DIRECTION INPUT ;
    USE SIGNAL ;
    PORT
      LAYER M4 ;
        RECT  215.808 103.596 216 103.62 ;
    END
  END si[310]
  PIN si[311]
    DIRECTION INPUT ;
    USE SIGNAL ;
    PORT
      LAYER M4 ;
        RECT  215.808 103.884 216 103.908 ;
    END
  END si[311]
  PIN si[312]
    DIRECTION INPUT ;
    USE SIGNAL ;
    PORT
      LAYER M4 ;
        RECT  215.808 104.172 216 104.196 ;
    END
  END si[312]
  PIN si[313]
    DIRECTION INPUT ;
    USE SIGNAL ;
    PORT
      LAYER M4 ;
        RECT  215.808 104.508 216 104.532 ;
    END
  END si[313]
  PIN si[314]
    DIRECTION INPUT ;
    USE SIGNAL ;
    PORT
      LAYER M4 ;
        RECT  215.808 104.796 216 104.82 ;
    END
  END si[314]
  PIN si[315]
    DIRECTION INPUT ;
    USE SIGNAL ;
    PORT
      LAYER M4 ;
        RECT  215.808 105.084 216 105.108 ;
    END
  END si[315]
  PIN si[316]
    DIRECTION INPUT ;
    USE SIGNAL ;
    PORT
      LAYER M4 ;
        RECT  215.808 105.372 216 105.396 ;
    END
  END si[316]
  PIN si[317]
    DIRECTION INPUT ;
    USE SIGNAL ;
    PORT
      LAYER M4 ;
        RECT  215.808 105.66 216 105.684 ;
    END
  END si[317]
  PIN si[318]
    DIRECTION INPUT ;
    USE SIGNAL ;
    PORT
      LAYER M4 ;
        RECT  215.808 105.948 216 105.972 ;
    END
  END si[318]
  PIN si[319]
    DIRECTION INPUT ;
    USE SIGNAL ;
    PORT
      LAYER M4 ;
        RECT  215.808 106.284 216 106.308 ;
    END
  END si[319]
  PIN si[31]
    DIRECTION INPUT ;
    USE SIGNAL ;
    PORT
      LAYER M4 ;
        RECT  215.808 20.844 216 20.868 ;
    END
  END si[31]
  PIN si[320]
    DIRECTION INPUT ;
    USE SIGNAL ;
    PORT
      LAYER M4 ;
        RECT  215.808 106.572 216 106.596 ;
    END
  END si[320]
  PIN si[321]
    DIRECTION INPUT ;
    USE SIGNAL ;
    PORT
      LAYER M4 ;
        RECT  215.808 106.86 216 106.884 ;
    END
  END si[321]
  PIN si[322]
    DIRECTION INPUT ;
    USE SIGNAL ;
    PORT
      LAYER M4 ;
        RECT  215.808 107.148 216 107.172 ;
    END
  END si[322]
  PIN si[323]
    DIRECTION INPUT ;
    USE SIGNAL ;
    PORT
      LAYER M4 ;
        RECT  215.808 107.436 216 107.46 ;
    END
  END si[323]
  PIN si[324]
    DIRECTION INPUT ;
    USE SIGNAL ;
    PORT
      LAYER M4 ;
        RECT  215.808 107.724 216 107.748 ;
    END
  END si[324]
  PIN si[325]
    DIRECTION INPUT ;
    USE SIGNAL ;
    PORT
      LAYER M4 ;
        RECT  215.808 108.06 216 108.084 ;
    END
  END si[325]
  PIN si[326]
    DIRECTION INPUT ;
    USE SIGNAL ;
    PORT
      LAYER M4 ;
        RECT  215.808 108.348 216 108.372 ;
    END
  END si[326]
  PIN si[327]
    DIRECTION INPUT ;
    USE SIGNAL ;
    PORT
      LAYER M4 ;
        RECT  215.808 108.636 216 108.66 ;
    END
  END si[327]
  PIN si[328]
    DIRECTION INPUT ;
    USE SIGNAL ;
    PORT
      LAYER M4 ;
        RECT  215.808 108.924 216 108.948 ;
    END
  END si[328]
  PIN si[329]
    DIRECTION INPUT ;
    USE SIGNAL ;
    PORT
      LAYER M4 ;
        RECT  215.808 109.212 216 109.236 ;
    END
  END si[329]
  PIN si[32]
    DIRECTION INPUT ;
    USE SIGNAL ;
    PORT
      LAYER M4 ;
        RECT  215.808 21.132 216 21.156 ;
    END
  END si[32]
  PIN si[330]
    DIRECTION INPUT ;
    USE SIGNAL ;
    PORT
      LAYER M4 ;
        RECT  215.808 109.548 216 109.572 ;
    END
  END si[330]
  PIN si[331]
    DIRECTION INPUT ;
    USE SIGNAL ;
    PORT
      LAYER M4 ;
        RECT  215.808 109.836 216 109.86 ;
    END
  END si[331]
  PIN si[332]
    DIRECTION INPUT ;
    USE SIGNAL ;
    PORT
      LAYER M4 ;
        RECT  215.808 110.124 216 110.148 ;
    END
  END si[332]
  PIN si[333]
    DIRECTION INPUT ;
    USE SIGNAL ;
    PORT
      LAYER M4 ;
        RECT  215.808 110.412 216 110.436 ;
    END
  END si[333]
  PIN si[334]
    DIRECTION INPUT ;
    USE SIGNAL ;
    PORT
      LAYER M4 ;
        RECT  215.808 110.7 216 110.724 ;
    END
  END si[334]
  PIN si[335]
    DIRECTION INPUT ;
    USE SIGNAL ;
    PORT
      LAYER M4 ;
        RECT  215.808 110.988 216 111.012 ;
    END
  END si[335]
  PIN si[336]
    DIRECTION INPUT ;
    USE SIGNAL ;
    PORT
      LAYER M4 ;
        RECT  215.808 111.324 216 111.348 ;
    END
  END si[336]
  PIN si[337]
    DIRECTION INPUT ;
    USE SIGNAL ;
    PORT
      LAYER M4 ;
        RECT  215.808 111.612 216 111.636 ;
    END
  END si[337]
  PIN si[338]
    DIRECTION INPUT ;
    USE SIGNAL ;
    PORT
      LAYER M4 ;
        RECT  215.808 111.9 216 111.924 ;
    END
  END si[338]
  PIN si[339]
    DIRECTION INPUT ;
    USE SIGNAL ;
    PORT
      LAYER M4 ;
        RECT  215.808 112.188 216 112.212 ;
    END
  END si[339]
  PIN si[33]
    DIRECTION INPUT ;
    USE SIGNAL ;
    PORT
      LAYER M4 ;
        RECT  215.808 21.42 216 21.444 ;
    END
  END si[33]
  PIN si[340]
    DIRECTION INPUT ;
    USE SIGNAL ;
    PORT
      LAYER M4 ;
        RECT  215.808 112.476 216 112.5 ;
    END
  END si[340]
  PIN si[341]
    DIRECTION INPUT ;
    USE SIGNAL ;
    PORT
      LAYER M4 ;
        RECT  215.808 112.812 216 112.836 ;
    END
  END si[341]
  PIN si[342]
    DIRECTION INPUT ;
    USE SIGNAL ;
    PORT
      LAYER M4 ;
        RECT  215.808 113.1 216 113.124 ;
    END
  END si[342]
  PIN si[343]
    DIRECTION INPUT ;
    USE SIGNAL ;
    PORT
      LAYER M4 ;
        RECT  215.808 113.388 216 113.412 ;
    END
  END si[343]
  PIN si[344]
    DIRECTION INPUT ;
    USE SIGNAL ;
    PORT
      LAYER M4 ;
        RECT  215.808 113.676 216 113.7 ;
    END
  END si[344]
  PIN si[345]
    DIRECTION INPUT ;
    USE SIGNAL ;
    PORT
      LAYER M4 ;
        RECT  215.808 113.964 216 113.988 ;
    END
  END si[345]
  PIN si[346]
    DIRECTION INPUT ;
    USE SIGNAL ;
    PORT
      LAYER M4 ;
        RECT  215.808 114.252 216 114.276 ;
    END
  END si[346]
  PIN si[347]
    DIRECTION INPUT ;
    USE SIGNAL ;
    PORT
      LAYER M4 ;
        RECT  215.808 114.588 216 114.612 ;
    END
  END si[347]
  PIN si[348]
    DIRECTION INPUT ;
    USE SIGNAL ;
    PORT
      LAYER M4 ;
        RECT  215.808 114.876 216 114.9 ;
    END
  END si[348]
  PIN si[349]
    DIRECTION INPUT ;
    USE SIGNAL ;
    PORT
      LAYER M4 ;
        RECT  215.808 115.164 216 115.188 ;
    END
  END si[349]
  PIN si[34]
    DIRECTION INPUT ;
    USE SIGNAL ;
    PORT
      LAYER M4 ;
        RECT  215.808 21.708 216 21.732 ;
    END
  END si[34]
  PIN si[350]
    DIRECTION INPUT ;
    USE SIGNAL ;
    PORT
      LAYER M4 ;
        RECT  215.808 115.452 216 115.476 ;
    END
  END si[350]
  PIN si[351]
    DIRECTION INPUT ;
    USE SIGNAL ;
    PORT
      LAYER M4 ;
        RECT  215.808 115.74 216 115.764 ;
    END
  END si[351]
  PIN si[352]
    DIRECTION INPUT ;
    USE SIGNAL ;
    PORT
      LAYER M4 ;
        RECT  215.808 116.076 216 116.1 ;
    END
  END si[352]
  PIN si[353]
    DIRECTION INPUT ;
    USE SIGNAL ;
    PORT
      LAYER M4 ;
        RECT  215.808 116.364 216 116.388 ;
    END
  END si[353]
  PIN si[354]
    DIRECTION INPUT ;
    USE SIGNAL ;
    PORT
      LAYER M4 ;
        RECT  215.808 116.652 216 116.676 ;
    END
  END si[354]
  PIN si[355]
    DIRECTION INPUT ;
    USE SIGNAL ;
    PORT
      LAYER M4 ;
        RECT  215.808 116.94 216 116.964 ;
    END
  END si[355]
  PIN si[356]
    DIRECTION INPUT ;
    USE SIGNAL ;
    PORT
      LAYER M4 ;
        RECT  215.808 117.228 216 117.252 ;
    END
  END si[356]
  PIN si[357]
    DIRECTION INPUT ;
    USE SIGNAL ;
    PORT
      LAYER M4 ;
        RECT  215.808 117.516 216 117.54 ;
    END
  END si[357]
  PIN si[358]
    DIRECTION INPUT ;
    USE SIGNAL ;
    PORT
      LAYER M4 ;
        RECT  215.808 117.852 216 117.876 ;
    END
  END si[358]
  PIN si[359]
    DIRECTION INPUT ;
    USE SIGNAL ;
    PORT
      LAYER M4 ;
        RECT  215.808 118.14 216 118.164 ;
    END
  END si[359]
  PIN si[35]
    DIRECTION INPUT ;
    USE SIGNAL ;
    PORT
      LAYER M4 ;
        RECT  215.808 21.996 216 22.02 ;
    END
  END si[35]
  PIN si[360]
    DIRECTION INPUT ;
    USE SIGNAL ;
    PORT
      LAYER M4 ;
        RECT  215.808 118.428 216 118.452 ;
    END
  END si[360]
  PIN si[361]
    DIRECTION INPUT ;
    USE SIGNAL ;
    PORT
      LAYER M4 ;
        RECT  215.808 118.716 216 118.74 ;
    END
  END si[361]
  PIN si[362]
    DIRECTION INPUT ;
    USE SIGNAL ;
    PORT
      LAYER M4 ;
        RECT  215.808 119.004 216 119.028 ;
    END
  END si[362]
  PIN si[363]
    DIRECTION INPUT ;
    USE SIGNAL ;
    PORT
      LAYER M4 ;
        RECT  215.808 119.34 216 119.364 ;
    END
  END si[363]
  PIN si[364]
    DIRECTION INPUT ;
    USE SIGNAL ;
    PORT
      LAYER M4 ;
        RECT  215.808 119.628 216 119.652 ;
    END
  END si[364]
  PIN si[365]
    DIRECTION INPUT ;
    USE SIGNAL ;
    PORT
      LAYER M4 ;
        RECT  215.808 119.916 216 119.94 ;
    END
  END si[365]
  PIN si[366]
    DIRECTION INPUT ;
    USE SIGNAL ;
    PORT
      LAYER M4 ;
        RECT  215.808 120.204 216 120.228 ;
    END
  END si[366]
  PIN si[367]
    DIRECTION INPUT ;
    USE SIGNAL ;
    PORT
      LAYER M4 ;
        RECT  215.808 120.492 216 120.516 ;
    END
  END si[367]
  PIN si[368]
    DIRECTION INPUT ;
    USE SIGNAL ;
    PORT
      LAYER M4 ;
        RECT  215.808 120.78 216 120.804 ;
    END
  END si[368]
  PIN si[369]
    DIRECTION INPUT ;
    USE SIGNAL ;
    PORT
      LAYER M4 ;
        RECT  215.808 121.116 216 121.14 ;
    END
  END si[369]
  PIN si[36]
    DIRECTION INPUT ;
    USE SIGNAL ;
    PORT
      LAYER M4 ;
        RECT  215.808 22.332 216 22.356 ;
    END
  END si[36]
  PIN si[370]
    DIRECTION INPUT ;
    USE SIGNAL ;
    PORT
      LAYER M4 ;
        RECT  215.808 121.404 216 121.428 ;
    END
  END si[370]
  PIN si[371]
    DIRECTION INPUT ;
    USE SIGNAL ;
    PORT
      LAYER M4 ;
        RECT  215.808 121.692 216 121.716 ;
    END
  END si[371]
  PIN si[372]
    DIRECTION INPUT ;
    USE SIGNAL ;
    PORT
      LAYER M4 ;
        RECT  215.808 121.98 216 122.004 ;
    END
  END si[372]
  PIN si[373]
    DIRECTION INPUT ;
    USE SIGNAL ;
    PORT
      LAYER M4 ;
        RECT  215.808 122.268 216 122.292 ;
    END
  END si[373]
  PIN si[374]
    DIRECTION INPUT ;
    USE SIGNAL ;
    PORT
      LAYER M4 ;
        RECT  215.808 122.604 216 122.628 ;
    END
  END si[374]
  PIN si[375]
    DIRECTION INPUT ;
    USE SIGNAL ;
    PORT
      LAYER M4 ;
        RECT  215.808 122.892 216 122.916 ;
    END
  END si[375]
  PIN si[376]
    DIRECTION INPUT ;
    USE SIGNAL ;
    PORT
      LAYER M4 ;
        RECT  215.808 123.18 216 123.204 ;
    END
  END si[376]
  PIN si[377]
    DIRECTION INPUT ;
    USE SIGNAL ;
    PORT
      LAYER M4 ;
        RECT  215.808 123.468 216 123.492 ;
    END
  END si[377]
  PIN si[378]
    DIRECTION INPUT ;
    USE SIGNAL ;
    PORT
      LAYER M4 ;
        RECT  215.808 123.756 216 123.78 ;
    END
  END si[378]
  PIN si[379]
    DIRECTION INPUT ;
    USE SIGNAL ;
    PORT
      LAYER M4 ;
        RECT  215.808 124.044 216 124.068 ;
    END
  END si[379]
  PIN si[37]
    DIRECTION INPUT ;
    USE SIGNAL ;
    PORT
      LAYER M4 ;
        RECT  215.808 22.62 216 22.644 ;
    END
  END si[37]
  PIN si[380]
    DIRECTION INPUT ;
    USE SIGNAL ;
    PORT
      LAYER M4 ;
        RECT  215.808 124.38 216 124.404 ;
    END
  END si[380]
  PIN si[381]
    DIRECTION INPUT ;
    USE SIGNAL ;
    PORT
      LAYER M4 ;
        RECT  215.808 124.668 216 124.692 ;
    END
  END si[381]
  PIN si[382]
    DIRECTION INPUT ;
    USE SIGNAL ;
    PORT
      LAYER M4 ;
        RECT  215.808 124.956 216 124.98 ;
    END
  END si[382]
  PIN si[383]
    DIRECTION INPUT ;
    USE SIGNAL ;
    PORT
      LAYER M4 ;
        RECT  215.808 125.244 216 125.268 ;
    END
  END si[383]
  PIN si[384]
    DIRECTION INPUT ;
    USE SIGNAL ;
    PORT
      LAYER M4 ;
        RECT  215.808 125.532 216 125.556 ;
    END
  END si[384]
  PIN si[385]
    DIRECTION INPUT ;
    USE SIGNAL ;
    PORT
      LAYER M4 ;
        RECT  215.808 125.82 216 125.844 ;
    END
  END si[385]
  PIN si[386]
    DIRECTION INPUT ;
    USE SIGNAL ;
    PORT
      LAYER M4 ;
        RECT  215.808 126.156 216 126.18 ;
    END
  END si[386]
  PIN si[387]
    DIRECTION INPUT ;
    USE SIGNAL ;
    PORT
      LAYER M4 ;
        RECT  215.808 126.444 216 126.468 ;
    END
  END si[387]
  PIN si[388]
    DIRECTION INPUT ;
    USE SIGNAL ;
    PORT
      LAYER M4 ;
        RECT  215.808 126.732 216 126.756 ;
    END
  END si[388]
  PIN si[389]
    DIRECTION INPUT ;
    USE SIGNAL ;
    PORT
      LAYER M4 ;
        RECT  215.808 127.02 216 127.044 ;
    END
  END si[389]
  PIN si[38]
    DIRECTION INPUT ;
    USE SIGNAL ;
    PORT
      LAYER M4 ;
        RECT  215.808 22.908 216 22.932 ;
    END
  END si[38]
  PIN si[390]
    DIRECTION INPUT ;
    USE SIGNAL ;
    PORT
      LAYER M4 ;
        RECT  215.808 127.308 216 127.332 ;
    END
  END si[390]
  PIN si[391]
    DIRECTION INPUT ;
    USE SIGNAL ;
    PORT
      LAYER M4 ;
        RECT  215.808 127.644 216 127.668 ;
    END
  END si[391]
  PIN si[392]
    DIRECTION INPUT ;
    USE SIGNAL ;
    PORT
      LAYER M4 ;
        RECT  215.808 127.932 216 127.956 ;
    END
  END si[392]
  PIN si[393]
    DIRECTION INPUT ;
    USE SIGNAL ;
    PORT
      LAYER M4 ;
        RECT  215.808 128.22 216 128.244 ;
    END
  END si[393]
  PIN si[394]
    DIRECTION INPUT ;
    USE SIGNAL ;
    PORT
      LAYER M4 ;
        RECT  215.808 128.508 216 128.532 ;
    END
  END si[394]
  PIN si[395]
    DIRECTION INPUT ;
    USE SIGNAL ;
    PORT
      LAYER M4 ;
        RECT  215.808 128.796 216 128.82 ;
    END
  END si[395]
  PIN si[396]
    DIRECTION INPUT ;
    USE SIGNAL ;
    PORT
      LAYER M4 ;
        RECT  215.808 129.084 216 129.108 ;
    END
  END si[396]
  PIN si[397]
    DIRECTION INPUT ;
    USE SIGNAL ;
    PORT
      LAYER M4 ;
        RECT  215.808 129.42 216 129.444 ;
    END
  END si[397]
  PIN si[398]
    DIRECTION INPUT ;
    USE SIGNAL ;
    PORT
      LAYER M4 ;
        RECT  215.808 129.708 216 129.732 ;
    END
  END si[398]
  PIN si[399]
    DIRECTION INPUT ;
    USE SIGNAL ;
    PORT
      LAYER M4 ;
        RECT  215.808 129.996 216 130.02 ;
    END
  END si[399]
  PIN si[39]
    DIRECTION INPUT ;
    USE SIGNAL ;
    PORT
      LAYER M4 ;
        RECT  215.808 23.196 216 23.22 ;
    END
  END si[39]
  PIN si[3]
    DIRECTION INPUT ;
    USE SIGNAL ;
    PORT
      LAYER M4 ;
        RECT  215.808 12.54 216 12.564 ;
    END
  END si[3]
  PIN si[400]
    DIRECTION INPUT ;
    USE SIGNAL ;
    PORT
      LAYER M4 ;
        RECT  215.808 130.284 216 130.308 ;
    END
  END si[400]
  PIN si[401]
    DIRECTION INPUT ;
    USE SIGNAL ;
    PORT
      LAYER M4 ;
        RECT  215.808 130.572 216 130.596 ;
    END
  END si[401]
  PIN si[402]
    DIRECTION INPUT ;
    USE SIGNAL ;
    PORT
      LAYER M4 ;
        RECT  215.808 130.908 216 130.932 ;
    END
  END si[402]
  PIN si[403]
    DIRECTION INPUT ;
    USE SIGNAL ;
    PORT
      LAYER M4 ;
        RECT  215.808 131.196 216 131.22 ;
    END
  END si[403]
  PIN si[404]
    DIRECTION INPUT ;
    USE SIGNAL ;
    PORT
      LAYER M4 ;
        RECT  215.808 131.484 216 131.508 ;
    END
  END si[404]
  PIN si[405]
    DIRECTION INPUT ;
    USE SIGNAL ;
    PORT
      LAYER M4 ;
        RECT  215.808 131.772 216 131.796 ;
    END
  END si[405]
  PIN si[406]
    DIRECTION INPUT ;
    USE SIGNAL ;
    PORT
      LAYER M4 ;
        RECT  215.808 132.06 216 132.084 ;
    END
  END si[406]
  PIN si[407]
    DIRECTION INPUT ;
    USE SIGNAL ;
    PORT
      LAYER M4 ;
        RECT  215.808 132.348 216 132.372 ;
    END
  END si[407]
  PIN si[408]
    DIRECTION INPUT ;
    USE SIGNAL ;
    PORT
      LAYER M4 ;
        RECT  215.808 132.684 216 132.708 ;
    END
  END si[408]
  PIN si[409]
    DIRECTION INPUT ;
    USE SIGNAL ;
    PORT
      LAYER M4 ;
        RECT  215.808 132.972 216 132.996 ;
    END
  END si[409]
  PIN si[40]
    DIRECTION INPUT ;
    USE SIGNAL ;
    PORT
      LAYER M4 ;
        RECT  215.808 23.484 216 23.508 ;
    END
  END si[40]
  PIN si[410]
    DIRECTION INPUT ;
    USE SIGNAL ;
    PORT
      LAYER M4 ;
        RECT  215.808 133.26 216 133.284 ;
    END
  END si[410]
  PIN si[411]
    DIRECTION INPUT ;
    USE SIGNAL ;
    PORT
      LAYER M4 ;
        RECT  215.808 133.548 216 133.572 ;
    END
  END si[411]
  PIN si[412]
    DIRECTION INPUT ;
    USE SIGNAL ;
    PORT
      LAYER M4 ;
        RECT  215.808 133.836 216 133.86 ;
    END
  END si[412]
  PIN si[413]
    DIRECTION INPUT ;
    USE SIGNAL ;
    PORT
      LAYER M4 ;
        RECT  215.808 134.172 216 134.196 ;
    END
  END si[413]
  PIN si[414]
    DIRECTION INPUT ;
    USE SIGNAL ;
    PORT
      LAYER M4 ;
        RECT  215.808 134.46 216 134.484 ;
    END
  END si[414]
  PIN si[415]
    DIRECTION INPUT ;
    USE SIGNAL ;
    PORT
      LAYER M4 ;
        RECT  215.808 134.748 216 134.772 ;
    END
  END si[415]
  PIN si[416]
    DIRECTION INPUT ;
    USE SIGNAL ;
    PORT
      LAYER M4 ;
        RECT  215.808 135.036 216 135.06 ;
    END
  END si[416]
  PIN si[417]
    DIRECTION INPUT ;
    USE SIGNAL ;
    PORT
      LAYER M4 ;
        RECT  215.808 135.324 216 135.348 ;
    END
  END si[417]
  PIN si[418]
    DIRECTION INPUT ;
    USE SIGNAL ;
    PORT
      LAYER M4 ;
        RECT  215.808 135.612 216 135.636 ;
    END
  END si[418]
  PIN si[419]
    DIRECTION INPUT ;
    USE SIGNAL ;
    PORT
      LAYER M4 ;
        RECT  215.808 135.948 216 135.972 ;
    END
  END si[419]
  PIN si[41]
    DIRECTION INPUT ;
    USE SIGNAL ;
    PORT
      LAYER M4 ;
        RECT  215.808 23.772 216 23.796 ;
    END
  END si[41]
  PIN si[420]
    DIRECTION INPUT ;
    USE SIGNAL ;
    PORT
      LAYER M4 ;
        RECT  215.808 136.236 216 136.26 ;
    END
  END si[420]
  PIN si[421]
    DIRECTION INPUT ;
    USE SIGNAL ;
    PORT
      LAYER M4 ;
        RECT  215.808 136.524 216 136.548 ;
    END
  END si[421]
  PIN si[422]
    DIRECTION INPUT ;
    USE SIGNAL ;
    PORT
      LAYER M4 ;
        RECT  215.808 136.812 216 136.836 ;
    END
  END si[422]
  PIN si[423]
    DIRECTION INPUT ;
    USE SIGNAL ;
    PORT
      LAYER M4 ;
        RECT  215.808 137.1 216 137.124 ;
    END
  END si[423]
  PIN si[424]
    DIRECTION INPUT ;
    USE SIGNAL ;
    PORT
      LAYER M4 ;
        RECT  215.808 137.436 216 137.46 ;
    END
  END si[424]
  PIN si[425]
    DIRECTION INPUT ;
    USE SIGNAL ;
    PORT
      LAYER M4 ;
        RECT  215.808 137.724 216 137.748 ;
    END
  END si[425]
  PIN si[426]
    DIRECTION INPUT ;
    USE SIGNAL ;
    PORT
      LAYER M4 ;
        RECT  215.808 138.012 216 138.036 ;
    END
  END si[426]
  PIN si[427]
    DIRECTION INPUT ;
    USE SIGNAL ;
    PORT
      LAYER M4 ;
        RECT  215.808 138.3 216 138.324 ;
    END
  END si[427]
  PIN si[428]
    DIRECTION INPUT ;
    USE SIGNAL ;
    PORT
      LAYER M4 ;
        RECT  215.808 138.588 216 138.612 ;
    END
  END si[428]
  PIN si[429]
    DIRECTION INPUT ;
    USE SIGNAL ;
    PORT
      LAYER M4 ;
        RECT  215.808 138.876 216 138.9 ;
    END
  END si[429]
  PIN si[42]
    DIRECTION INPUT ;
    USE SIGNAL ;
    PORT
      LAYER M4 ;
        RECT  215.808 24.108 216 24.132 ;
    END
  END si[42]
  PIN si[430]
    DIRECTION INPUT ;
    USE SIGNAL ;
    PORT
      LAYER M4 ;
        RECT  215.808 139.212 216 139.236 ;
    END
  END si[430]
  PIN si[431]
    DIRECTION INPUT ;
    USE SIGNAL ;
    PORT
      LAYER M4 ;
        RECT  215.808 139.5 216 139.524 ;
    END
  END si[431]
  PIN si[432]
    DIRECTION INPUT ;
    USE SIGNAL ;
    PORT
      LAYER M4 ;
        RECT  215.808 139.788 216 139.812 ;
    END
  END si[432]
  PIN si[433]
    DIRECTION INPUT ;
    USE SIGNAL ;
    PORT
      LAYER M4 ;
        RECT  215.808 140.076 216 140.1 ;
    END
  END si[433]
  PIN si[434]
    DIRECTION INPUT ;
    USE SIGNAL ;
    PORT
      LAYER M4 ;
        RECT  215.808 140.364 216 140.388 ;
    END
  END si[434]
  PIN si[435]
    DIRECTION INPUT ;
    USE SIGNAL ;
    PORT
      LAYER M4 ;
        RECT  215.808 140.7 216 140.724 ;
    END
  END si[435]
  PIN si[436]
    DIRECTION INPUT ;
    USE SIGNAL ;
    PORT
      LAYER M4 ;
        RECT  215.808 140.988 216 141.012 ;
    END
  END si[436]
  PIN si[437]
    DIRECTION INPUT ;
    USE SIGNAL ;
    PORT
      LAYER M4 ;
        RECT  215.808 141.276 216 141.3 ;
    END
  END si[437]
  PIN si[438]
    DIRECTION INPUT ;
    USE SIGNAL ;
    PORT
      LAYER M4 ;
        RECT  215.808 141.564 216 141.588 ;
    END
  END si[438]
  PIN si[439]
    DIRECTION INPUT ;
    USE SIGNAL ;
    PORT
      LAYER M4 ;
        RECT  215.808 141.852 216 141.876 ;
    END
  END si[439]
  PIN si[43]
    DIRECTION INPUT ;
    USE SIGNAL ;
    PORT
      LAYER M4 ;
        RECT  215.808 24.396 216 24.42 ;
    END
  END si[43]
  PIN si[440]
    DIRECTION INPUT ;
    USE SIGNAL ;
    PORT
      LAYER M4 ;
        RECT  215.808 142.14 216 142.164 ;
    END
  END si[440]
  PIN si[441]
    DIRECTION INPUT ;
    USE SIGNAL ;
    PORT
      LAYER M4 ;
        RECT  215.808 142.476 216 142.5 ;
    END
  END si[441]
  PIN si[442]
    DIRECTION INPUT ;
    USE SIGNAL ;
    PORT
      LAYER M4 ;
        RECT  215.808 142.764 216 142.788 ;
    END
  END si[442]
  PIN si[443]
    DIRECTION INPUT ;
    USE SIGNAL ;
    PORT
      LAYER M4 ;
        RECT  215.808 143.052 216 143.076 ;
    END
  END si[443]
  PIN si[444]
    DIRECTION INPUT ;
    USE SIGNAL ;
    PORT
      LAYER M4 ;
        RECT  215.808 143.34 216 143.364 ;
    END
  END si[444]
  PIN si[445]
    DIRECTION INPUT ;
    USE SIGNAL ;
    PORT
      LAYER M4 ;
        RECT  215.808 143.628 216 143.652 ;
    END
  END si[445]
  PIN si[446]
    DIRECTION INPUT ;
    USE SIGNAL ;
    PORT
      LAYER M4 ;
        RECT  215.808 143.964 216 143.988 ;
    END
  END si[446]
  PIN si[447]
    DIRECTION INPUT ;
    USE SIGNAL ;
    PORT
      LAYER M4 ;
        RECT  215.808 144.252 216 144.276 ;
    END
  END si[447]
  PIN si[448]
    DIRECTION INPUT ;
    USE SIGNAL ;
    PORT
      LAYER M4 ;
        RECT  215.808 144.54 216 144.564 ;
    END
  END si[448]
  PIN si[449]
    DIRECTION INPUT ;
    USE SIGNAL ;
    PORT
      LAYER M4 ;
        RECT  215.808 144.828 216 144.852 ;
    END
  END si[449]
  PIN si[44]
    DIRECTION INPUT ;
    USE SIGNAL ;
    PORT
      LAYER M4 ;
        RECT  215.808 24.684 216 24.708 ;
    END
  END si[44]
  PIN si[450]
    DIRECTION INPUT ;
    USE SIGNAL ;
    PORT
      LAYER M4 ;
        RECT  215.808 145.116 216 145.14 ;
    END
  END si[450]
  PIN si[451]
    DIRECTION INPUT ;
    USE SIGNAL ;
    PORT
      LAYER M4 ;
        RECT  215.808 145.404 216 145.428 ;
    END
  END si[451]
  PIN si[452]
    DIRECTION INPUT ;
    USE SIGNAL ;
    PORT
      LAYER M4 ;
        RECT  215.808 145.74 216 145.764 ;
    END
  END si[452]
  PIN si[453]
    DIRECTION INPUT ;
    USE SIGNAL ;
    PORT
      LAYER M4 ;
        RECT  215.808 146.028 216 146.052 ;
    END
  END si[453]
  PIN si[454]
    DIRECTION INPUT ;
    USE SIGNAL ;
    PORT
      LAYER M4 ;
        RECT  215.808 146.316 216 146.34 ;
    END
  END si[454]
  PIN si[455]
    DIRECTION INPUT ;
    USE SIGNAL ;
    PORT
      LAYER M4 ;
        RECT  215.808 146.604 216 146.628 ;
    END
  END si[455]
  PIN si[456]
    DIRECTION INPUT ;
    USE SIGNAL ;
    PORT
      LAYER M4 ;
        RECT  215.808 146.892 216 146.916 ;
    END
  END si[456]
  PIN si[457]
    DIRECTION INPUT ;
    USE SIGNAL ;
    PORT
      LAYER M4 ;
        RECT  215.808 147.18 216 147.204 ;
    END
  END si[457]
  PIN si[458]
    DIRECTION INPUT ;
    USE SIGNAL ;
    PORT
      LAYER M4 ;
        RECT  215.808 147.516 216 147.54 ;
    END
  END si[458]
  PIN si[459]
    DIRECTION INPUT ;
    USE SIGNAL ;
    PORT
      LAYER M4 ;
        RECT  215.808 147.804 216 147.828 ;
    END
  END si[459]
  PIN si[45]
    DIRECTION INPUT ;
    USE SIGNAL ;
    PORT
      LAYER M4 ;
        RECT  215.808 24.972 216 24.996 ;
    END
  END si[45]
  PIN si[460]
    DIRECTION INPUT ;
    USE SIGNAL ;
    PORT
      LAYER M4 ;
        RECT  215.808 148.092 216 148.116 ;
    END
  END si[460]
  PIN si[461]
    DIRECTION INPUT ;
    USE SIGNAL ;
    PORT
      LAYER M4 ;
        RECT  215.808 148.38 216 148.404 ;
    END
  END si[461]
  PIN si[462]
    DIRECTION INPUT ;
    USE SIGNAL ;
    PORT
      LAYER M4 ;
        RECT  215.808 148.668 216 148.692 ;
    END
  END si[462]
  PIN si[463]
    DIRECTION INPUT ;
    USE SIGNAL ;
    PORT
      LAYER M4 ;
        RECT  215.808 149.004 216 149.028 ;
    END
  END si[463]
  PIN si[464]
    DIRECTION INPUT ;
    USE SIGNAL ;
    PORT
      LAYER M4 ;
        RECT  215.808 149.292 216 149.316 ;
    END
  END si[464]
  PIN si[465]
    DIRECTION INPUT ;
    USE SIGNAL ;
    PORT
      LAYER M4 ;
        RECT  215.808 149.58 216 149.604 ;
    END
  END si[465]
  PIN si[466]
    DIRECTION INPUT ;
    USE SIGNAL ;
    PORT
      LAYER M4 ;
        RECT  215.808 149.868 216 149.892 ;
    END
  END si[466]
  PIN si[467]
    DIRECTION INPUT ;
    USE SIGNAL ;
    PORT
      LAYER M4 ;
        RECT  215.808 150.156 216 150.18 ;
    END
  END si[467]
  PIN si[468]
    DIRECTION INPUT ;
    USE SIGNAL ;
    PORT
      LAYER M4 ;
        RECT  215.808 150.444 216 150.468 ;
    END
  END si[468]
  PIN si[469]
    DIRECTION INPUT ;
    USE SIGNAL ;
    PORT
      LAYER M4 ;
        RECT  215.808 150.78 216 150.804 ;
    END
  END si[469]
  PIN si[46]
    DIRECTION INPUT ;
    USE SIGNAL ;
    PORT
      LAYER M4 ;
        RECT  215.808 25.26 216 25.284 ;
    END
  END si[46]
  PIN si[470]
    DIRECTION INPUT ;
    USE SIGNAL ;
    PORT
      LAYER M4 ;
        RECT  215.808 151.068 216 151.092 ;
    END
  END si[470]
  PIN si[471]
    DIRECTION INPUT ;
    USE SIGNAL ;
    PORT
      LAYER M4 ;
        RECT  215.808 151.356 216 151.38 ;
    END
  END si[471]
  PIN si[472]
    DIRECTION INPUT ;
    USE SIGNAL ;
    PORT
      LAYER M4 ;
        RECT  215.808 151.644 216 151.668 ;
    END
  END si[472]
  PIN si[473]
    DIRECTION INPUT ;
    USE SIGNAL ;
    PORT
      LAYER M4 ;
        RECT  215.808 151.932 216 151.956 ;
    END
  END si[473]
  PIN si[474]
    DIRECTION INPUT ;
    USE SIGNAL ;
    PORT
      LAYER M4 ;
        RECT  215.808 152.268 216 152.292 ;
    END
  END si[474]
  PIN si[475]
    DIRECTION INPUT ;
    USE SIGNAL ;
    PORT
      LAYER M4 ;
        RECT  215.808 152.556 216 152.58 ;
    END
  END si[475]
  PIN si[476]
    DIRECTION INPUT ;
    USE SIGNAL ;
    PORT
      LAYER M4 ;
        RECT  215.808 152.844 216 152.868 ;
    END
  END si[476]
  PIN si[477]
    DIRECTION INPUT ;
    USE SIGNAL ;
    PORT
      LAYER M4 ;
        RECT  215.808 153.132 216 153.156 ;
    END
  END si[477]
  PIN si[478]
    DIRECTION INPUT ;
    USE SIGNAL ;
    PORT
      LAYER M4 ;
        RECT  215.808 153.42 216 153.444 ;
    END
  END si[478]
  PIN si[479]
    DIRECTION INPUT ;
    USE SIGNAL ;
    PORT
      LAYER M4 ;
        RECT  215.808 153.708 216 153.732 ;
    END
  END si[479]
  PIN si[47]
    DIRECTION INPUT ;
    USE SIGNAL ;
    PORT
      LAYER M4 ;
        RECT  215.808 25.596 216 25.62 ;
    END
  END si[47]
  PIN si[480]
    DIRECTION INPUT ;
    USE SIGNAL ;
    PORT
      LAYER M4 ;
        RECT  215.808 154.044 216 154.068 ;
    END
  END si[480]
  PIN si[481]
    DIRECTION INPUT ;
    USE SIGNAL ;
    PORT
      LAYER M4 ;
        RECT  215.808 154.332 216 154.356 ;
    END
  END si[481]
  PIN si[482]
    DIRECTION INPUT ;
    USE SIGNAL ;
    PORT
      LAYER M4 ;
        RECT  215.808 154.62 216 154.644 ;
    END
  END si[482]
  PIN si[483]
    DIRECTION INPUT ;
    USE SIGNAL ;
    PORT
      LAYER M4 ;
        RECT  215.808 154.908 216 154.932 ;
    END
  END si[483]
  PIN si[484]
    DIRECTION INPUT ;
    USE SIGNAL ;
    PORT
      LAYER M4 ;
        RECT  215.808 155.196 216 155.22 ;
    END
  END si[484]
  PIN si[485]
    DIRECTION INPUT ;
    USE SIGNAL ;
    PORT
      LAYER M4 ;
        RECT  215.808 155.532 216 155.556 ;
    END
  END si[485]
  PIN si[486]
    DIRECTION INPUT ;
    USE SIGNAL ;
    PORT
      LAYER M4 ;
        RECT  215.808 155.82 216 155.844 ;
    END
  END si[486]
  PIN si[487]
    DIRECTION INPUT ;
    USE SIGNAL ;
    PORT
      LAYER M4 ;
        RECT  215.808 156.108 216 156.132 ;
    END
  END si[487]
  PIN si[488]
    DIRECTION INPUT ;
    USE SIGNAL ;
    PORT
      LAYER M4 ;
        RECT  215.808 156.396 216 156.42 ;
    END
  END si[488]
  PIN si[489]
    DIRECTION INPUT ;
    USE SIGNAL ;
    PORT
      LAYER M4 ;
        RECT  215.808 156.684 216 156.708 ;
    END
  END si[489]
  PIN si[48]
    DIRECTION INPUT ;
    USE SIGNAL ;
    PORT
      LAYER M4 ;
        RECT  215.808 25.884 216 25.908 ;
    END
  END si[48]
  PIN si[490]
    DIRECTION INPUT ;
    USE SIGNAL ;
    PORT
      LAYER M4 ;
        RECT  215.808 156.972 216 156.996 ;
    END
  END si[490]
  PIN si[491]
    DIRECTION INPUT ;
    USE SIGNAL ;
    PORT
      LAYER M4 ;
        RECT  215.808 157.308 216 157.332 ;
    END
  END si[491]
  PIN si[492]
    DIRECTION INPUT ;
    USE SIGNAL ;
    PORT
      LAYER M4 ;
        RECT  215.808 157.596 216 157.62 ;
    END
  END si[492]
  PIN si[493]
    DIRECTION INPUT ;
    USE SIGNAL ;
    PORT
      LAYER M4 ;
        RECT  215.808 157.884 216 157.908 ;
    END
  END si[493]
  PIN si[494]
    DIRECTION INPUT ;
    USE SIGNAL ;
    PORT
      LAYER M4 ;
        RECT  215.808 158.172 216 158.196 ;
    END
  END si[494]
  PIN si[495]
    DIRECTION INPUT ;
    USE SIGNAL ;
    PORT
      LAYER M4 ;
        RECT  215.808 158.46 216 158.484 ;
    END
  END si[495]
  PIN si[496]
    DIRECTION INPUT ;
    USE SIGNAL ;
    PORT
      LAYER M4 ;
        RECT  215.808 158.796 216 158.82 ;
    END
  END si[496]
  PIN si[497]
    DIRECTION INPUT ;
    USE SIGNAL ;
    PORT
      LAYER M4 ;
        RECT  215.808 159.084 216 159.108 ;
    END
  END si[497]
  PIN si[498]
    DIRECTION INPUT ;
    USE SIGNAL ;
    PORT
      LAYER M4 ;
        RECT  215.808 159.372 216 159.396 ;
    END
  END si[498]
  PIN si[499]
    DIRECTION INPUT ;
    USE SIGNAL ;
    PORT
      LAYER M4 ;
        RECT  215.808 159.66 216 159.684 ;
    END
  END si[499]
  PIN si[49]
    DIRECTION INPUT ;
    USE SIGNAL ;
    PORT
      LAYER M4 ;
        RECT  215.808 26.172 216 26.196 ;
    END
  END si[49]
  PIN si[4]
    DIRECTION INPUT ;
    USE SIGNAL ;
    PORT
      LAYER M4 ;
        RECT  215.808 12.828 216 12.852 ;
    END
  END si[4]
  PIN si[500]
    DIRECTION INPUT ;
    USE SIGNAL ;
    PORT
      LAYER M4 ;
        RECT  215.808 159.948 216 159.972 ;
    END
  END si[500]
  PIN si[501]
    DIRECTION INPUT ;
    USE SIGNAL ;
    PORT
      LAYER M4 ;
        RECT  215.808 160.236 216 160.26 ;
    END
  END si[501]
  PIN si[502]
    DIRECTION INPUT ;
    USE SIGNAL ;
    PORT
      LAYER M4 ;
        RECT  215.808 160.572 216 160.596 ;
    END
  END si[502]
  PIN si[503]
    DIRECTION INPUT ;
    USE SIGNAL ;
    PORT
      LAYER M4 ;
        RECT  215.808 160.86 216 160.884 ;
    END
  END si[503]
  PIN si[504]
    DIRECTION INPUT ;
    USE SIGNAL ;
    PORT
      LAYER M4 ;
        RECT  215.808 161.148 216 161.172 ;
    END
  END si[504]
  PIN si[505]
    DIRECTION INPUT ;
    USE SIGNAL ;
    PORT
      LAYER M4 ;
        RECT  215.808 161.436 216 161.46 ;
    END
  END si[505]
  PIN si[506]
    DIRECTION INPUT ;
    USE SIGNAL ;
    PORT
      LAYER M4 ;
        RECT  215.808 161.724 216 161.748 ;
    END
  END si[506]
  PIN si[507]
    DIRECTION INPUT ;
    USE SIGNAL ;
    PORT
      LAYER M4 ;
        RECT  215.808 162.06 216 162.084 ;
    END
  END si[507]
  PIN si[508]
    DIRECTION INPUT ;
    USE SIGNAL ;
    PORT
      LAYER M4 ;
        RECT  215.808 162.348 216 162.372 ;
    END
  END si[508]
  PIN si[509]
    DIRECTION INPUT ;
    USE SIGNAL ;
    PORT
      LAYER M4 ;
        RECT  215.808 162.636 216 162.66 ;
    END
  END si[509]
  PIN si[50]
    DIRECTION INPUT ;
    USE SIGNAL ;
    PORT
      LAYER M4 ;
        RECT  215.808 26.46 216 26.484 ;
    END
  END si[50]
  PIN si[510]
    DIRECTION INPUT ;
    USE SIGNAL ;
    PORT
      LAYER M4 ;
        RECT  215.808 162.924 216 162.948 ;
    END
  END si[510]
  PIN si[511]
    DIRECTION INPUT ;
    USE SIGNAL ;
    PORT
      LAYER M4 ;
        RECT  215.808 163.212 216 163.236 ;
    END
  END si[511]
  PIN si[512]
    DIRECTION INPUT ;
    USE SIGNAL ;
    PORT
      LAYER M4 ;
        RECT  215.808 163.5 216 163.524 ;
    END
  END si[512]
  PIN si[513]
    DIRECTION INPUT ;
    USE SIGNAL ;
    PORT
      LAYER M4 ;
        RECT  215.808 163.836 216 163.86 ;
    END
  END si[513]
  PIN si[514]
    DIRECTION INPUT ;
    USE SIGNAL ;
    PORT
      LAYER M4 ;
        RECT  215.808 164.124 216 164.148 ;
    END
  END si[514]
  PIN si[515]
    DIRECTION INPUT ;
    USE SIGNAL ;
    PORT
      LAYER M4 ;
        RECT  215.808 164.412 216 164.436 ;
    END
  END si[515]
  PIN si[516]
    DIRECTION INPUT ;
    USE SIGNAL ;
    PORT
      LAYER M4 ;
        RECT  215.808 164.7 216 164.724 ;
    END
  END si[516]
  PIN si[517]
    DIRECTION INPUT ;
    USE SIGNAL ;
    PORT
      LAYER M4 ;
        RECT  215.808 164.988 216 165.012 ;
    END
  END si[517]
  PIN si[518]
    DIRECTION INPUT ;
    USE SIGNAL ;
    PORT
      LAYER M4 ;
        RECT  215.808 165.276 216 165.3 ;
    END
  END si[518]
  PIN si[519]
    DIRECTION INPUT ;
    USE SIGNAL ;
    PORT
      LAYER M4 ;
        RECT  215.808 165.612 216 165.636 ;
    END
  END si[519]
  PIN si[51]
    DIRECTION INPUT ;
    USE SIGNAL ;
    PORT
      LAYER M4 ;
        RECT  215.808 26.748 216 26.772 ;
    END
  END si[51]
  PIN si[520]
    DIRECTION INPUT ;
    USE SIGNAL ;
    PORT
      LAYER M4 ;
        RECT  215.808 165.9 216 165.924 ;
    END
  END si[520]
  PIN si[521]
    DIRECTION INPUT ;
    USE SIGNAL ;
    PORT
      LAYER M4 ;
        RECT  215.808 166.188 216 166.212 ;
    END
  END si[521]
  PIN si[522]
    DIRECTION INPUT ;
    USE SIGNAL ;
    PORT
      LAYER M4 ;
        RECT  215.808 166.476 216 166.5 ;
    END
  END si[522]
  PIN si[523]
    DIRECTION INPUT ;
    USE SIGNAL ;
    PORT
      LAYER M4 ;
        RECT  215.808 166.764 216 166.788 ;
    END
  END si[523]
  PIN si[524]
    DIRECTION INPUT ;
    USE SIGNAL ;
    PORT
      LAYER M4 ;
        RECT  215.808 167.1 216 167.124 ;
    END
  END si[524]
  PIN si[525]
    DIRECTION INPUT ;
    USE SIGNAL ;
    PORT
      LAYER M4 ;
        RECT  215.808 167.388 216 167.412 ;
    END
  END si[525]
  PIN si[526]
    DIRECTION INPUT ;
    USE SIGNAL ;
    PORT
      LAYER M4 ;
        RECT  215.808 167.676 216 167.7 ;
    END
  END si[526]
  PIN si[527]
    DIRECTION INPUT ;
    USE SIGNAL ;
    PORT
      LAYER M4 ;
        RECT  215.808 167.964 216 167.988 ;
    END
  END si[527]
  PIN si[528]
    DIRECTION INPUT ;
    USE SIGNAL ;
    PORT
      LAYER M4 ;
        RECT  215.808 168.252 216 168.276 ;
    END
  END si[528]
  PIN si[529]
    DIRECTION INPUT ;
    USE SIGNAL ;
    PORT
      LAYER M4 ;
        RECT  215.808 168.54 216 168.564 ;
    END
  END si[529]
  PIN si[52]
    DIRECTION INPUT ;
    USE SIGNAL ;
    PORT
      LAYER M4 ;
        RECT  215.808 27.036 216 27.06 ;
    END
  END si[52]
  PIN si[530]
    DIRECTION INPUT ;
    USE SIGNAL ;
    PORT
      LAYER M4 ;
        RECT  215.808 168.876 216 168.9 ;
    END
  END si[530]
  PIN si[531]
    DIRECTION INPUT ;
    USE SIGNAL ;
    PORT
      LAYER M4 ;
        RECT  215.808 169.164 216 169.188 ;
    END
  END si[531]
  PIN si[532]
    DIRECTION INPUT ;
    USE SIGNAL ;
    PORT
      LAYER M4 ;
        RECT  215.808 169.452 216 169.476 ;
    END
  END si[532]
  PIN si[533]
    DIRECTION INPUT ;
    USE SIGNAL ;
    PORT
      LAYER M4 ;
        RECT  215.808 169.74 216 169.764 ;
    END
  END si[533]
  PIN si[534]
    DIRECTION INPUT ;
    USE SIGNAL ;
    PORT
      LAYER M4 ;
        RECT  215.808 170.028 216 170.052 ;
    END
  END si[534]
  PIN si[535]
    DIRECTION INPUT ;
    USE SIGNAL ;
    PORT
      LAYER M4 ;
        RECT  215.808 170.364 216 170.388 ;
    END
  END si[535]
  PIN si[536]
    DIRECTION INPUT ;
    USE SIGNAL ;
    PORT
      LAYER M4 ;
        RECT  215.808 170.652 216 170.676 ;
    END
  END si[536]
  PIN si[53]
    DIRECTION INPUT ;
    USE SIGNAL ;
    PORT
      LAYER M4 ;
        RECT  215.808 27.372 216 27.396 ;
    END
  END si[53]
  PIN si[54]
    DIRECTION INPUT ;
    USE SIGNAL ;
    PORT
      LAYER M4 ;
        RECT  215.808 27.66 216 27.684 ;
    END
  END si[54]
  PIN si[55]
    DIRECTION INPUT ;
    USE SIGNAL ;
    PORT
      LAYER M4 ;
        RECT  215.808 27.948 216 27.972 ;
    END
  END si[55]
  PIN si[56]
    DIRECTION INPUT ;
    USE SIGNAL ;
    PORT
      LAYER M4 ;
        RECT  215.808 28.236 216 28.26 ;
    END
  END si[56]
  PIN si[57]
    DIRECTION INPUT ;
    USE SIGNAL ;
    PORT
      LAYER M4 ;
        RECT  215.808 28.524 216 28.548 ;
    END
  END si[57]
  PIN si[58]
    DIRECTION INPUT ;
    USE SIGNAL ;
    PORT
      LAYER M4 ;
        RECT  215.808 28.812 216 28.836 ;
    END
  END si[58]
  PIN si[59]
    DIRECTION INPUT ;
    USE SIGNAL ;
    PORT
      LAYER M4 ;
        RECT  215.808 29.148 216 29.172 ;
    END
  END si[59]
  PIN si[5]
    DIRECTION INPUT ;
    USE SIGNAL ;
    PORT
      LAYER M4 ;
        RECT  215.808 13.116 216 13.14 ;
    END
  END si[5]
  PIN si[60]
    DIRECTION INPUT ;
    USE SIGNAL ;
    PORT
      LAYER M4 ;
        RECT  215.808 29.436 216 29.46 ;
    END
  END si[60]
  PIN si[61]
    DIRECTION INPUT ;
    USE SIGNAL ;
    PORT
      LAYER M4 ;
        RECT  215.808 29.724 216 29.748 ;
    END
  END si[61]
  PIN si[62]
    DIRECTION INPUT ;
    USE SIGNAL ;
    PORT
      LAYER M4 ;
        RECT  215.808 30.012 216 30.036 ;
    END
  END si[62]
  PIN si[63]
    DIRECTION INPUT ;
    USE SIGNAL ;
    PORT
      LAYER M4 ;
        RECT  215.808 30.3 216 30.324 ;
    END
  END si[63]
  PIN si[64]
    DIRECTION INPUT ;
    USE SIGNAL ;
    PORT
      LAYER M4 ;
        RECT  215.808 30.636 216 30.66 ;
    END
  END si[64]
  PIN si[65]
    DIRECTION INPUT ;
    USE SIGNAL ;
    PORT
      LAYER M4 ;
        RECT  215.808 30.924 216 30.948 ;
    END
  END si[65]
  PIN si[66]
    DIRECTION INPUT ;
    USE SIGNAL ;
    PORT
      LAYER M4 ;
        RECT  215.808 31.212 216 31.236 ;
    END
  END si[66]
  PIN si[67]
    DIRECTION INPUT ;
    USE SIGNAL ;
    PORT
      LAYER M4 ;
        RECT  215.808 31.5 216 31.524 ;
    END
  END si[67]
  PIN si[68]
    DIRECTION INPUT ;
    USE SIGNAL ;
    PORT
      LAYER M4 ;
        RECT  215.808 31.788 216 31.812 ;
    END
  END si[68]
  PIN si[69]
    DIRECTION INPUT ;
    USE SIGNAL ;
    PORT
      LAYER M4 ;
        RECT  215.808 32.076 216 32.1 ;
    END
  END si[69]
  PIN si[6]
    DIRECTION INPUT ;
    USE SIGNAL ;
    PORT
      LAYER M4 ;
        RECT  215.808 13.404 216 13.428 ;
    END
  END si[6]
  PIN si[70]
    DIRECTION INPUT ;
    USE SIGNAL ;
    PORT
      LAYER M4 ;
        RECT  215.808 32.412 216 32.436 ;
    END
  END si[70]
  PIN si[71]
    DIRECTION INPUT ;
    USE SIGNAL ;
    PORT
      LAYER M4 ;
        RECT  215.808 32.7 216 32.724 ;
    END
  END si[71]
  PIN si[72]
    DIRECTION INPUT ;
    USE SIGNAL ;
    PORT
      LAYER M4 ;
        RECT  215.808 32.988 216 33.012 ;
    END
  END si[72]
  PIN si[73]
    DIRECTION INPUT ;
    USE SIGNAL ;
    PORT
      LAYER M4 ;
        RECT  215.808 33.276 216 33.3 ;
    END
  END si[73]
  PIN si[74]
    DIRECTION INPUT ;
    USE SIGNAL ;
    PORT
      LAYER M4 ;
        RECT  215.808 33.564 216 33.588 ;
    END
  END si[74]
  PIN si[75]
    DIRECTION INPUT ;
    USE SIGNAL ;
    PORT
      LAYER M4 ;
        RECT  215.808 33.9 216 33.924 ;
    END
  END si[75]
  PIN si[76]
    DIRECTION INPUT ;
    USE SIGNAL ;
    PORT
      LAYER M4 ;
        RECT  215.808 34.188 216 34.212 ;
    END
  END si[76]
  PIN si[77]
    DIRECTION INPUT ;
    USE SIGNAL ;
    PORT
      LAYER M4 ;
        RECT  215.808 34.476 216 34.5 ;
    END
  END si[77]
  PIN si[78]
    DIRECTION INPUT ;
    USE SIGNAL ;
    PORT
      LAYER M4 ;
        RECT  215.808 34.764 216 34.788 ;
    END
  END si[78]
  PIN si[79]
    DIRECTION INPUT ;
    USE SIGNAL ;
    PORT
      LAYER M4 ;
        RECT  215.808 35.052 216 35.076 ;
    END
  END si[79]
  PIN si[7]
    DIRECTION INPUT ;
    USE SIGNAL ;
    PORT
      LAYER M4 ;
        RECT  215.808 13.692 216 13.716 ;
    END
  END si[7]
  PIN si[80]
    DIRECTION INPUT ;
    USE SIGNAL ;
    PORT
      LAYER M4 ;
        RECT  215.808 35.34 216 35.364 ;
    END
  END si[80]
  PIN si[81]
    DIRECTION INPUT ;
    USE SIGNAL ;
    PORT
      LAYER M4 ;
        RECT  215.808 35.676 216 35.7 ;
    END
  END si[81]
  PIN si[82]
    DIRECTION INPUT ;
    USE SIGNAL ;
    PORT
      LAYER M4 ;
        RECT  215.808 35.964 216 35.988 ;
    END
  END si[82]
  PIN si[83]
    DIRECTION INPUT ;
    USE SIGNAL ;
    PORT
      LAYER M4 ;
        RECT  215.808 36.252 216 36.276 ;
    END
  END si[83]
  PIN si[84]
    DIRECTION INPUT ;
    USE SIGNAL ;
    PORT
      LAYER M4 ;
        RECT  215.808 36.54 216 36.564 ;
    END
  END si[84]
  PIN si[85]
    DIRECTION INPUT ;
    USE SIGNAL ;
    PORT
      LAYER M4 ;
        RECT  215.808 36.828 216 36.852 ;
    END
  END si[85]
  PIN si[86]
    DIRECTION INPUT ;
    USE SIGNAL ;
    PORT
      LAYER M4 ;
        RECT  215.808 37.164 216 37.188 ;
    END
  END si[86]
  PIN si[87]
    DIRECTION INPUT ;
    USE SIGNAL ;
    PORT
      LAYER M4 ;
        RECT  215.808 37.452 216 37.476 ;
    END
  END si[87]
  PIN si[88]
    DIRECTION INPUT ;
    USE SIGNAL ;
    PORT
      LAYER M4 ;
        RECT  215.808 37.74 216 37.764 ;
    END
  END si[88]
  PIN si[89]
    DIRECTION INPUT ;
    USE SIGNAL ;
    PORT
      LAYER M4 ;
        RECT  215.808 38.028 216 38.052 ;
    END
  END si[89]
  PIN si[8]
    DIRECTION INPUT ;
    USE SIGNAL ;
    PORT
      LAYER M4 ;
        RECT  215.808 13.98 216 14.004 ;
    END
  END si[8]
  PIN si[90]
    DIRECTION INPUT ;
    USE SIGNAL ;
    PORT
      LAYER M4 ;
        RECT  215.808 38.316 216 38.34 ;
    END
  END si[90]
  PIN si[91]
    DIRECTION INPUT ;
    USE SIGNAL ;
    PORT
      LAYER M4 ;
        RECT  215.808 38.604 216 38.628 ;
    END
  END si[91]
  PIN si[92]
    DIRECTION INPUT ;
    USE SIGNAL ;
    PORT
      LAYER M4 ;
        RECT  215.808 38.94 216 38.964 ;
    END
  END si[92]
  PIN si[93]
    DIRECTION INPUT ;
    USE SIGNAL ;
    PORT
      LAYER M4 ;
        RECT  215.808 39.228 216 39.252 ;
    END
  END si[93]
  PIN si[94]
    DIRECTION INPUT ;
    USE SIGNAL ;
    PORT
      LAYER M4 ;
        RECT  215.808 39.516 216 39.54 ;
    END
  END si[94]
  PIN si[95]
    DIRECTION INPUT ;
    USE SIGNAL ;
    PORT
      LAYER M4 ;
        RECT  215.808 39.804 216 39.828 ;
    END
  END si[95]
  PIN si[96]
    DIRECTION INPUT ;
    USE SIGNAL ;
    PORT
      LAYER M4 ;
        RECT  215.808 40.092 216 40.116 ;
    END
  END si[96]
  PIN si[97]
    DIRECTION INPUT ;
    USE SIGNAL ;
    PORT
      LAYER M4 ;
        RECT  215.808 40.428 216 40.452 ;
    END
  END si[97]
  PIN si[98]
    DIRECTION INPUT ;
    USE SIGNAL ;
    PORT
      LAYER M4 ;
        RECT  215.808 40.716 216 40.74 ;
    END
  END si[98]
  PIN si[99]
    DIRECTION INPUT ;
    USE SIGNAL ;
    PORT
      LAYER M4 ;
        RECT  215.808 41.004 216 41.028 ;
    END
  END si[99]
  PIN si[9]
    DIRECTION INPUT ;
    USE SIGNAL ;
    PORT
      LAYER M4 ;
        RECT  215.808 14.316 216 14.34 ;
    END
  END si[9]
  PIN t1[0]
    DIRECTION OUTPUT ;
    USE SIGNAL ;
    PORT
      LAYER M5 ;
        RECT  2.124 0 2.148 0.192 ;
    END
  END t1[0]
  PIN t1[100]
    DIRECTION OUTPUT ;
    USE SIGNAL ;
    PORT
      LAYER M5 ;
        RECT  25.596 0 25.62 0.192 ;
    END
  END t1[100]
  PIN t1[101]
    DIRECTION OUTPUT ;
    USE SIGNAL ;
    PORT
      LAYER M5 ;
        RECT  25.836 0 25.86 0.192 ;
    END
  END t1[101]
  PIN t1[102]
    DIRECTION OUTPUT ;
    USE SIGNAL ;
    PORT
      LAYER M5 ;
        RECT  26.076 0 26.1 0.192 ;
    END
  END t1[102]
  PIN t1[103]
    DIRECTION OUTPUT ;
    USE SIGNAL ;
    PORT
      LAYER M5 ;
        RECT  26.316 0 26.34 0.192 ;
    END
  END t1[103]
  PIN t1[104]
    DIRECTION OUTPUT ;
    USE SIGNAL ;
    PORT
      LAYER M5 ;
        RECT  26.556 0 26.58 0.192 ;
    END
  END t1[104]
  PIN t1[105]
    DIRECTION OUTPUT ;
    USE SIGNAL ;
    PORT
      LAYER M5 ;
        RECT  26.796 0 26.82 0.192 ;
    END
  END t1[105]
  PIN t1[106]
    DIRECTION OUTPUT ;
    USE SIGNAL ;
    PORT
      LAYER M5 ;
        RECT  27.036 0 27.06 0.192 ;
    END
  END t1[106]
  PIN t1[107]
    DIRECTION OUTPUT ;
    USE SIGNAL ;
    PORT
      LAYER M5 ;
        RECT  27.276 0 27.3 0.192 ;
    END
  END t1[107]
  PIN t1[108]
    DIRECTION OUTPUT ;
    USE SIGNAL ;
    PORT
      LAYER M5 ;
        RECT  27.468 0 27.492 0.192 ;
    END
  END t1[108]
  PIN t1[109]
    DIRECTION OUTPUT ;
    USE SIGNAL ;
    PORT
      LAYER M5 ;
        RECT  27.708 0 27.732 0.192 ;
    END
  END t1[109]
  PIN t1[10]
    DIRECTION OUTPUT ;
    USE SIGNAL ;
    PORT
      LAYER M5 ;
        RECT  4.476 0 4.5 0.192 ;
    END
  END t1[10]
  PIN t1[110]
    DIRECTION OUTPUT ;
    USE SIGNAL ;
    PORT
      LAYER M5 ;
        RECT  27.948 0 27.972 0.192 ;
    END
  END t1[110]
  PIN t1[111]
    DIRECTION OUTPUT ;
    USE SIGNAL ;
    PORT
      LAYER M5 ;
        RECT  28.188 0 28.212 0.192 ;
    END
  END t1[111]
  PIN t1[112]
    DIRECTION OUTPUT ;
    USE SIGNAL ;
    PORT
      LAYER M5 ;
        RECT  28.428 0 28.452 0.192 ;
    END
  END t1[112]
  PIN t1[113]
    DIRECTION OUTPUT ;
    USE SIGNAL ;
    PORT
      LAYER M5 ;
        RECT  28.668 0 28.692 0.192 ;
    END
  END t1[113]
  PIN t1[114]
    DIRECTION OUTPUT ;
    USE SIGNAL ;
    PORT
      LAYER M5 ;
        RECT  28.908 0 28.932 0.192 ;
    END
  END t1[114]
  PIN t1[115]
    DIRECTION OUTPUT ;
    USE SIGNAL ;
    PORT
      LAYER M5 ;
        RECT  29.148 0 29.172 0.192 ;
    END
  END t1[115]
  PIN t1[116]
    DIRECTION OUTPUT ;
    USE SIGNAL ;
    PORT
      LAYER M5 ;
        RECT  29.388 0 29.412 0.192 ;
    END
  END t1[116]
  PIN t1[117]
    DIRECTION OUTPUT ;
    USE SIGNAL ;
    PORT
      LAYER M5 ;
        RECT  29.628 0 29.652 0.192 ;
    END
  END t1[117]
  PIN t1[118]
    DIRECTION OUTPUT ;
    USE SIGNAL ;
    PORT
      LAYER M5 ;
        RECT  29.82 0 29.844 0.192 ;
    END
  END t1[118]
  PIN t1[119]
    DIRECTION OUTPUT ;
    USE SIGNAL ;
    PORT
      LAYER M5 ;
        RECT  30.06 0 30.084 0.192 ;
    END
  END t1[119]
  PIN t1[11]
    DIRECTION OUTPUT ;
    USE SIGNAL ;
    PORT
      LAYER M5 ;
        RECT  4.668 0 4.692 0.192 ;
    END
  END t1[11]
  PIN t1[120]
    DIRECTION OUTPUT ;
    USE SIGNAL ;
    PORT
      LAYER M5 ;
        RECT  30.3 0 30.324 0.192 ;
    END
  END t1[120]
  PIN t1[121]
    DIRECTION OUTPUT ;
    USE SIGNAL ;
    PORT
      LAYER M5 ;
        RECT  30.54 0 30.564 0.192 ;
    END
  END t1[121]
  PIN t1[122]
    DIRECTION OUTPUT ;
    USE SIGNAL ;
    PORT
      LAYER M5 ;
        RECT  30.78 0 30.804 0.192 ;
    END
  END t1[122]
  PIN t1[123]
    DIRECTION OUTPUT ;
    USE SIGNAL ;
    PORT
      LAYER M5 ;
        RECT  31.02 0 31.044 0.192 ;
    END
  END t1[123]
  PIN t1[124]
    DIRECTION OUTPUT ;
    USE SIGNAL ;
    PORT
      LAYER M5 ;
        RECT  31.26 0 31.284 0.192 ;
    END
  END t1[124]
  PIN t1[125]
    DIRECTION OUTPUT ;
    USE SIGNAL ;
    PORT
      LAYER M5 ;
        RECT  31.5 0 31.524 0.192 ;
    END
  END t1[125]
  PIN t1[126]
    DIRECTION OUTPUT ;
    USE SIGNAL ;
    PORT
      LAYER M5 ;
        RECT  31.74 0 31.764 0.192 ;
    END
  END t1[126]
  PIN t1[127]
    DIRECTION OUTPUT ;
    USE SIGNAL ;
    PORT
      LAYER M5 ;
        RECT  31.932 0 31.956 0.192 ;
    END
  END t1[127]
  PIN t1[128]
    DIRECTION OUTPUT ;
    USE SIGNAL ;
    PORT
      LAYER M5 ;
        RECT  32.172 0 32.196 0.192 ;
    END
  END t1[128]
  PIN t1[129]
    DIRECTION OUTPUT ;
    USE SIGNAL ;
    PORT
      LAYER M5 ;
        RECT  32.412 0 32.436 0.192 ;
    END
  END t1[129]
  PIN t1[12]
    DIRECTION OUTPUT ;
    USE SIGNAL ;
    PORT
      LAYER M5 ;
        RECT  4.908 0 4.932 0.192 ;
    END
  END t1[12]
  PIN t1[130]
    DIRECTION OUTPUT ;
    USE SIGNAL ;
    PORT
      LAYER M5 ;
        RECT  32.652 0 32.676 0.192 ;
    END
  END t1[130]
  PIN t1[131]
    DIRECTION OUTPUT ;
    USE SIGNAL ;
    PORT
      LAYER M5 ;
        RECT  32.892 0 32.916 0.192 ;
    END
  END t1[131]
  PIN t1[132]
    DIRECTION OUTPUT ;
    USE SIGNAL ;
    PORT
      LAYER M5 ;
        RECT  33.132 0 33.156 0.192 ;
    END
  END t1[132]
  PIN t1[133]
    DIRECTION OUTPUT ;
    USE SIGNAL ;
    PORT
      LAYER M5 ;
        RECT  33.372 0 33.396 0.192 ;
    END
  END t1[133]
  PIN t1[134]
    DIRECTION OUTPUT ;
    USE SIGNAL ;
    PORT
      LAYER M5 ;
        RECT  33.612 0 33.636 0.192 ;
    END
  END t1[134]
  PIN t1[135]
    DIRECTION OUTPUT ;
    USE SIGNAL ;
    PORT
      LAYER M5 ;
        RECT  33.852 0 33.876 0.192 ;
    END
  END t1[135]
  PIN t1[136]
    DIRECTION OUTPUT ;
    USE SIGNAL ;
    PORT
      LAYER M5 ;
        RECT  34.092 0 34.116 0.192 ;
    END
  END t1[136]
  PIN t1[137]
    DIRECTION OUTPUT ;
    USE SIGNAL ;
    PORT
      LAYER M5 ;
        RECT  34.284 0 34.308 0.192 ;
    END
  END t1[137]
  PIN t1[138]
    DIRECTION OUTPUT ;
    USE SIGNAL ;
    PORT
      LAYER M5 ;
        RECT  34.524 0 34.548 0.192 ;
    END
  END t1[138]
  PIN t1[139]
    DIRECTION OUTPUT ;
    USE SIGNAL ;
    PORT
      LAYER M5 ;
        RECT  34.764 0 34.788 0.192 ;
    END
  END t1[139]
  PIN t1[13]
    DIRECTION OUTPUT ;
    USE SIGNAL ;
    PORT
      LAYER M5 ;
        RECT  5.148 0 5.172 0.192 ;
    END
  END t1[13]
  PIN t1[140]
    DIRECTION OUTPUT ;
    USE SIGNAL ;
    PORT
      LAYER M5 ;
        RECT  35.004 0 35.028 0.192 ;
    END
  END t1[140]
  PIN t1[141]
    DIRECTION OUTPUT ;
    USE SIGNAL ;
    PORT
      LAYER M5 ;
        RECT  35.244 0 35.268 0.192 ;
    END
  END t1[141]
  PIN t1[142]
    DIRECTION OUTPUT ;
    USE SIGNAL ;
    PORT
      LAYER M5 ;
        RECT  35.484 0 35.508 0.192 ;
    END
  END t1[142]
  PIN t1[143]
    DIRECTION OUTPUT ;
    USE SIGNAL ;
    PORT
      LAYER M5 ;
        RECT  35.724 0 35.748 0.192 ;
    END
  END t1[143]
  PIN t1[144]
    DIRECTION OUTPUT ;
    USE SIGNAL ;
    PORT
      LAYER M5 ;
        RECT  35.964 0 35.988 0.192 ;
    END
  END t1[144]
  PIN t1[145]
    DIRECTION OUTPUT ;
    USE SIGNAL ;
    PORT
      LAYER M5 ;
        RECT  36.204 0 36.228 0.192 ;
    END
  END t1[145]
  PIN t1[146]
    DIRECTION OUTPUT ;
    USE SIGNAL ;
    PORT
      LAYER M5 ;
        RECT  36.444 0 36.468 0.192 ;
    END
  END t1[146]
  PIN t1[147]
    DIRECTION OUTPUT ;
    USE SIGNAL ;
    PORT
      LAYER M5 ;
        RECT  36.636 0 36.66 0.192 ;
    END
  END t1[147]
  PIN t1[148]
    DIRECTION OUTPUT ;
    USE SIGNAL ;
    PORT
      LAYER M5 ;
        RECT  36.876 0 36.9 0.192 ;
    END
  END t1[148]
  PIN t1[149]
    DIRECTION OUTPUT ;
    USE SIGNAL ;
    PORT
      LAYER M5 ;
        RECT  37.116 0 37.14 0.192 ;
    END
  END t1[149]
  PIN t1[14]
    DIRECTION OUTPUT ;
    USE SIGNAL ;
    PORT
      LAYER M5 ;
        RECT  5.388 0 5.412 0.192 ;
    END
  END t1[14]
  PIN t1[150]
    DIRECTION OUTPUT ;
    USE SIGNAL ;
    PORT
      LAYER M5 ;
        RECT  37.356 0 37.38 0.192 ;
    END
  END t1[150]
  PIN t1[151]
    DIRECTION OUTPUT ;
    USE SIGNAL ;
    PORT
      LAYER M5 ;
        RECT  37.596 0 37.62 0.192 ;
    END
  END t1[151]
  PIN t1[152]
    DIRECTION OUTPUT ;
    USE SIGNAL ;
    PORT
      LAYER M5 ;
        RECT  37.836 0 37.86 0.192 ;
    END
  END t1[152]
  PIN t1[153]
    DIRECTION OUTPUT ;
    USE SIGNAL ;
    PORT
      LAYER M5 ;
        RECT  38.076 0 38.1 0.192 ;
    END
  END t1[153]
  PIN t1[154]
    DIRECTION OUTPUT ;
    USE SIGNAL ;
    PORT
      LAYER M5 ;
        RECT  38.316 0 38.34 0.192 ;
    END
  END t1[154]
  PIN t1[155]
    DIRECTION OUTPUT ;
    USE SIGNAL ;
    PORT
      LAYER M5 ;
        RECT  38.556 0 38.58 0.192 ;
    END
  END t1[155]
  PIN t1[156]
    DIRECTION OUTPUT ;
    USE SIGNAL ;
    PORT
      LAYER M5 ;
        RECT  38.748 0 38.772 0.192 ;
    END
  END t1[156]
  PIN t1[157]
    DIRECTION OUTPUT ;
    USE SIGNAL ;
    PORT
      LAYER M5 ;
        RECT  38.988 0 39.012 0.192 ;
    END
  END t1[157]
  PIN t1[158]
    DIRECTION OUTPUT ;
    USE SIGNAL ;
    PORT
      LAYER M5 ;
        RECT  39.228 0 39.252 0.192 ;
    END
  END t1[158]
  PIN t1[159]
    DIRECTION OUTPUT ;
    USE SIGNAL ;
    PORT
      LAYER M5 ;
        RECT  39.468 0 39.492 0.192 ;
    END
  END t1[159]
  PIN t1[15]
    DIRECTION OUTPUT ;
    USE SIGNAL ;
    PORT
      LAYER M5 ;
        RECT  5.628 0 5.652 0.192 ;
    END
  END t1[15]
  PIN t1[160]
    DIRECTION OUTPUT ;
    USE SIGNAL ;
    PORT
      LAYER M5 ;
        RECT  39.708 0 39.732 0.192 ;
    END
  END t1[160]
  PIN t1[161]
    DIRECTION OUTPUT ;
    USE SIGNAL ;
    PORT
      LAYER M5 ;
        RECT  39.948 0 39.972 0.192 ;
    END
  END t1[161]
  PIN t1[162]
    DIRECTION OUTPUT ;
    USE SIGNAL ;
    PORT
      LAYER M5 ;
        RECT  40.188 0 40.212 0.192 ;
    END
  END t1[162]
  PIN t1[163]
    DIRECTION OUTPUT ;
    USE SIGNAL ;
    PORT
      LAYER M5 ;
        RECT  40.428 0 40.452 0.192 ;
    END
  END t1[163]
  PIN t1[164]
    DIRECTION OUTPUT ;
    USE SIGNAL ;
    PORT
      LAYER M5 ;
        RECT  40.668 0 40.692 0.192 ;
    END
  END t1[164]
  PIN t1[165]
    DIRECTION OUTPUT ;
    USE SIGNAL ;
    PORT
      LAYER M5 ;
        RECT  40.908 0 40.932 0.192 ;
    END
  END t1[165]
  PIN t1[166]
    DIRECTION OUTPUT ;
    USE SIGNAL ;
    PORT
      LAYER M5 ;
        RECT  41.1 0 41.124 0.192 ;
    END
  END t1[166]
  PIN t1[167]
    DIRECTION OUTPUT ;
    USE SIGNAL ;
    PORT
      LAYER M5 ;
        RECT  41.34 0 41.364 0.192 ;
    END
  END t1[167]
  PIN t1[168]
    DIRECTION OUTPUT ;
    USE SIGNAL ;
    PORT
      LAYER M5 ;
        RECT  41.58 0 41.604 0.192 ;
    END
  END t1[168]
  PIN t1[169]
    DIRECTION OUTPUT ;
    USE SIGNAL ;
    PORT
      LAYER M5 ;
        RECT  41.82 0 41.844 0.192 ;
    END
  END t1[169]
  PIN t1[16]
    DIRECTION OUTPUT ;
    USE SIGNAL ;
    PORT
      LAYER M5 ;
        RECT  5.868 0 5.892 0.192 ;
    END
  END t1[16]
  PIN t1[170]
    DIRECTION OUTPUT ;
    USE SIGNAL ;
    PORT
      LAYER M5 ;
        RECT  42.06 0 42.084 0.192 ;
    END
  END t1[170]
  PIN t1[171]
    DIRECTION OUTPUT ;
    USE SIGNAL ;
    PORT
      LAYER M5 ;
        RECT  42.3 0 42.324 0.192 ;
    END
  END t1[171]
  PIN t1[172]
    DIRECTION OUTPUT ;
    USE SIGNAL ;
    PORT
      LAYER M5 ;
        RECT  42.54 0 42.564 0.192 ;
    END
  END t1[172]
  PIN t1[173]
    DIRECTION OUTPUT ;
    USE SIGNAL ;
    PORT
      LAYER M5 ;
        RECT  42.78 0 42.804 0.192 ;
    END
  END t1[173]
  PIN t1[174]
    DIRECTION OUTPUT ;
    USE SIGNAL ;
    PORT
      LAYER M5 ;
        RECT  43.02 0 43.044 0.192 ;
    END
  END t1[174]
  PIN t1[175]
    DIRECTION OUTPUT ;
    USE SIGNAL ;
    PORT
      LAYER M5 ;
        RECT  43.26 0 43.284 0.192 ;
    END
  END t1[175]
  PIN t1[176]
    DIRECTION OUTPUT ;
    USE SIGNAL ;
    PORT
      LAYER M5 ;
        RECT  43.452 0 43.476 0.192 ;
    END
  END t1[176]
  PIN t1[177]
    DIRECTION OUTPUT ;
    USE SIGNAL ;
    PORT
      LAYER M5 ;
        RECT  43.692 0 43.716 0.192 ;
    END
  END t1[177]
  PIN t1[178]
    DIRECTION OUTPUT ;
    USE SIGNAL ;
    PORT
      LAYER M5 ;
        RECT  43.932 0 43.956 0.192 ;
    END
  END t1[178]
  PIN t1[179]
    DIRECTION OUTPUT ;
    USE SIGNAL ;
    PORT
      LAYER M5 ;
        RECT  44.172 0 44.196 0.192 ;
    END
  END t1[179]
  PIN t1[17]
    DIRECTION OUTPUT ;
    USE SIGNAL ;
    PORT
      LAYER M5 ;
        RECT  6.108 0 6.132 0.192 ;
    END
  END t1[17]
  PIN t1[180]
    DIRECTION OUTPUT ;
    USE SIGNAL ;
    PORT
      LAYER M5 ;
        RECT  44.412 0 44.436 0.192 ;
    END
  END t1[180]
  PIN t1[181]
    DIRECTION OUTPUT ;
    USE SIGNAL ;
    PORT
      LAYER M5 ;
        RECT  44.652 0 44.676 0.192 ;
    END
  END t1[181]
  PIN t1[182]
    DIRECTION OUTPUT ;
    USE SIGNAL ;
    PORT
      LAYER M5 ;
        RECT  44.892 0 44.916 0.192 ;
    END
  END t1[182]
  PIN t1[183]
    DIRECTION OUTPUT ;
    USE SIGNAL ;
    PORT
      LAYER M5 ;
        RECT  45.132 0 45.156 0.192 ;
    END
  END t1[183]
  PIN t1[184]
    DIRECTION OUTPUT ;
    USE SIGNAL ;
    PORT
      LAYER M5 ;
        RECT  45.372 0 45.396 0.192 ;
    END
  END t1[184]
  PIN t1[185]
    DIRECTION OUTPUT ;
    USE SIGNAL ;
    PORT
      LAYER M5 ;
        RECT  45.564 0 45.588 0.192 ;
    END
  END t1[185]
  PIN t1[186]
    DIRECTION OUTPUT ;
    USE SIGNAL ;
    PORT
      LAYER M5 ;
        RECT  45.804 0 45.828 0.192 ;
    END
  END t1[186]
  PIN t1[187]
    DIRECTION OUTPUT ;
    USE SIGNAL ;
    PORT
      LAYER M5 ;
        RECT  46.044 0 46.068 0.192 ;
    END
  END t1[187]
  PIN t1[188]
    DIRECTION OUTPUT ;
    USE SIGNAL ;
    PORT
      LAYER M5 ;
        RECT  46.284 0 46.308 0.192 ;
    END
  END t1[188]
  PIN t1[189]
    DIRECTION OUTPUT ;
    USE SIGNAL ;
    PORT
      LAYER M5 ;
        RECT  46.524 0 46.548 0.192 ;
    END
  END t1[189]
  PIN t1[18]
    DIRECTION OUTPUT ;
    USE SIGNAL ;
    PORT
      LAYER M5 ;
        RECT  6.348 0 6.372 0.192 ;
    END
  END t1[18]
  PIN t1[190]
    DIRECTION OUTPUT ;
    USE SIGNAL ;
    PORT
      LAYER M5 ;
        RECT  46.764 0 46.788 0.192 ;
    END
  END t1[190]
  PIN t1[191]
    DIRECTION OUTPUT ;
    USE SIGNAL ;
    PORT
      LAYER M5 ;
        RECT  47.004 0 47.028 0.192 ;
    END
  END t1[191]
  PIN t1[192]
    DIRECTION OUTPUT ;
    USE SIGNAL ;
    PORT
      LAYER M5 ;
        RECT  47.244 0 47.268 0.192 ;
    END
  END t1[192]
  PIN t1[193]
    DIRECTION OUTPUT ;
    USE SIGNAL ;
    PORT
      LAYER M5 ;
        RECT  47.484 0 47.508 0.192 ;
    END
  END t1[193]
  PIN t1[194]
    DIRECTION OUTPUT ;
    USE SIGNAL ;
    PORT
      LAYER M5 ;
        RECT  47.724 0 47.748 0.192 ;
    END
  END t1[194]
  PIN t1[195]
    DIRECTION OUTPUT ;
    USE SIGNAL ;
    PORT
      LAYER M5 ;
        RECT  47.916 0 47.94 0.192 ;
    END
  END t1[195]
  PIN t1[196]
    DIRECTION OUTPUT ;
    USE SIGNAL ;
    PORT
      LAYER M5 ;
        RECT  48.156 0 48.18 0.192 ;
    END
  END t1[196]
  PIN t1[197]
    DIRECTION OUTPUT ;
    USE SIGNAL ;
    PORT
      LAYER M5 ;
        RECT  48.396 0 48.42 0.192 ;
    END
  END t1[197]
  PIN t1[198]
    DIRECTION OUTPUT ;
    USE SIGNAL ;
    PORT
      LAYER M5 ;
        RECT  48.636 0 48.66 0.192 ;
    END
  END t1[198]
  PIN t1[199]
    DIRECTION OUTPUT ;
    USE SIGNAL ;
    PORT
      LAYER M5 ;
        RECT  48.876 0 48.9 0.192 ;
    END
  END t1[199]
  PIN t1[19]
    DIRECTION OUTPUT ;
    USE SIGNAL ;
    PORT
      LAYER M5 ;
        RECT  6.588 0 6.612 0.192 ;
    END
  END t1[19]
  PIN t1[1]
    DIRECTION OUTPUT ;
    USE SIGNAL ;
    PORT
      LAYER M5 ;
        RECT  2.364 0 2.388 0.192 ;
    END
  END t1[1]
  PIN t1[200]
    DIRECTION OUTPUT ;
    USE SIGNAL ;
    PORT
      LAYER M5 ;
        RECT  49.116 0 49.14 0.192 ;
    END
  END t1[200]
  PIN t1[201]
    DIRECTION OUTPUT ;
    USE SIGNAL ;
    PORT
      LAYER M5 ;
        RECT  49.356 0 49.38 0.192 ;
    END
  END t1[201]
  PIN t1[202]
    DIRECTION OUTPUT ;
    USE SIGNAL ;
    PORT
      LAYER M5 ;
        RECT  49.596 0 49.62 0.192 ;
    END
  END t1[202]
  PIN t1[203]
    DIRECTION OUTPUT ;
    USE SIGNAL ;
    PORT
      LAYER M5 ;
        RECT  49.836 0 49.86 0.192 ;
    END
  END t1[203]
  PIN t1[204]
    DIRECTION OUTPUT ;
    USE SIGNAL ;
    PORT
      LAYER M5 ;
        RECT  50.076 0 50.1 0.192 ;
    END
  END t1[204]
  PIN t1[205]
    DIRECTION OUTPUT ;
    USE SIGNAL ;
    PORT
      LAYER M5 ;
        RECT  50.268 0 50.292 0.192 ;
    END
  END t1[205]
  PIN t1[206]
    DIRECTION OUTPUT ;
    USE SIGNAL ;
    PORT
      LAYER M5 ;
        RECT  50.508 0 50.532 0.192 ;
    END
  END t1[206]
  PIN t1[207]
    DIRECTION OUTPUT ;
    USE SIGNAL ;
    PORT
      LAYER M5 ;
        RECT  50.748 0 50.772 0.192 ;
    END
  END t1[207]
  PIN t1[208]
    DIRECTION OUTPUT ;
    USE SIGNAL ;
    PORT
      LAYER M5 ;
        RECT  50.988 0 51.012 0.192 ;
    END
  END t1[208]
  PIN t1[209]
    DIRECTION OUTPUT ;
    USE SIGNAL ;
    PORT
      LAYER M5 ;
        RECT  51.228 0 51.252 0.192 ;
    END
  END t1[209]
  PIN t1[20]
    DIRECTION OUTPUT ;
    USE SIGNAL ;
    PORT
      LAYER M5 ;
        RECT  6.828 0 6.852 0.192 ;
    END
  END t1[20]
  PIN t1[210]
    DIRECTION OUTPUT ;
    USE SIGNAL ;
    PORT
      LAYER M5 ;
        RECT  51.468 0 51.492 0.192 ;
    END
  END t1[210]
  PIN t1[211]
    DIRECTION OUTPUT ;
    USE SIGNAL ;
    PORT
      LAYER M5 ;
        RECT  51.708 0 51.732 0.192 ;
    END
  END t1[211]
  PIN t1[212]
    DIRECTION OUTPUT ;
    USE SIGNAL ;
    PORT
      LAYER M5 ;
        RECT  51.948 0 51.972 0.192 ;
    END
  END t1[212]
  PIN t1[213]
    DIRECTION OUTPUT ;
    USE SIGNAL ;
    PORT
      LAYER M5 ;
        RECT  52.188 0 52.212 0.192 ;
    END
  END t1[213]
  PIN t1[214]
    DIRECTION OUTPUT ;
    USE SIGNAL ;
    PORT
      LAYER M5 ;
        RECT  52.38 0 52.404 0.192 ;
    END
  END t1[214]
  PIN t1[215]
    DIRECTION OUTPUT ;
    USE SIGNAL ;
    PORT
      LAYER M5 ;
        RECT  52.62 0 52.644 0.192 ;
    END
  END t1[215]
  PIN t1[216]
    DIRECTION OUTPUT ;
    USE SIGNAL ;
    PORT
      LAYER M5 ;
        RECT  52.86 0 52.884 0.192 ;
    END
  END t1[216]
  PIN t1[217]
    DIRECTION OUTPUT ;
    USE SIGNAL ;
    PORT
      LAYER M5 ;
        RECT  53.1 0 53.124 0.192 ;
    END
  END t1[217]
  PIN t1[218]
    DIRECTION OUTPUT ;
    USE SIGNAL ;
    PORT
      LAYER M5 ;
        RECT  53.34 0 53.364 0.192 ;
    END
  END t1[218]
  PIN t1[219]
    DIRECTION OUTPUT ;
    USE SIGNAL ;
    PORT
      LAYER M5 ;
        RECT  53.58 0 53.604 0.192 ;
    END
  END t1[219]
  PIN t1[21]
    DIRECTION OUTPUT ;
    USE SIGNAL ;
    PORT
      LAYER M5 ;
        RECT  7.02 0 7.044 0.192 ;
    END
  END t1[21]
  PIN t1[220]
    DIRECTION OUTPUT ;
    USE SIGNAL ;
    PORT
      LAYER M5 ;
        RECT  53.82 0 53.844 0.192 ;
    END
  END t1[220]
  PIN t1[221]
    DIRECTION OUTPUT ;
    USE SIGNAL ;
    PORT
      LAYER M5 ;
        RECT  54.06 0 54.084 0.192 ;
    END
  END t1[221]
  PIN t1[222]
    DIRECTION OUTPUT ;
    USE SIGNAL ;
    PORT
      LAYER M5 ;
        RECT  54.3 0 54.324 0.192 ;
    END
  END t1[222]
  PIN t1[223]
    DIRECTION OUTPUT ;
    USE SIGNAL ;
    PORT
      LAYER M5 ;
        RECT  54.54 0 54.564 0.192 ;
    END
  END t1[223]
  PIN t1[224]
    DIRECTION OUTPUT ;
    USE SIGNAL ;
    PORT
      LAYER M5 ;
        RECT  54.732 0 54.756 0.192 ;
    END
  END t1[224]
  PIN t1[225]
    DIRECTION OUTPUT ;
    USE SIGNAL ;
    PORT
      LAYER M5 ;
        RECT  54.972 0 54.996 0.192 ;
    END
  END t1[225]
  PIN t1[226]
    DIRECTION OUTPUT ;
    USE SIGNAL ;
    PORT
      LAYER M5 ;
        RECT  55.212 0 55.236 0.192 ;
    END
  END t1[226]
  PIN t1[227]
    DIRECTION OUTPUT ;
    USE SIGNAL ;
    PORT
      LAYER M5 ;
        RECT  55.452 0 55.476 0.192 ;
    END
  END t1[227]
  PIN t1[228]
    DIRECTION OUTPUT ;
    USE SIGNAL ;
    PORT
      LAYER M5 ;
        RECT  55.692 0 55.716 0.192 ;
    END
  END t1[228]
  PIN t1[229]
    DIRECTION OUTPUT ;
    USE SIGNAL ;
    PORT
      LAYER M5 ;
        RECT  55.932 0 55.956 0.192 ;
    END
  END t1[229]
  PIN t1[22]
    DIRECTION OUTPUT ;
    USE SIGNAL ;
    PORT
      LAYER M5 ;
        RECT  7.26 0 7.284 0.192 ;
    END
  END t1[22]
  PIN t1[230]
    DIRECTION OUTPUT ;
    USE SIGNAL ;
    PORT
      LAYER M5 ;
        RECT  56.172 0 56.196 0.192 ;
    END
  END t1[230]
  PIN t1[231]
    DIRECTION OUTPUT ;
    USE SIGNAL ;
    PORT
      LAYER M5 ;
        RECT  56.412 0 56.436 0.192 ;
    END
  END t1[231]
  PIN t1[232]
    DIRECTION OUTPUT ;
    USE SIGNAL ;
    PORT
      LAYER M5 ;
        RECT  56.652 0 56.676 0.192 ;
    END
  END t1[232]
  PIN t1[233]
    DIRECTION OUTPUT ;
    USE SIGNAL ;
    PORT
      LAYER M5 ;
        RECT  56.892 0 56.916 0.192 ;
    END
  END t1[233]
  PIN t1[234]
    DIRECTION OUTPUT ;
    USE SIGNAL ;
    PORT
      LAYER M5 ;
        RECT  57.084 0 57.108 0.192 ;
    END
  END t1[234]
  PIN t1[235]
    DIRECTION OUTPUT ;
    USE SIGNAL ;
    PORT
      LAYER M5 ;
        RECT  57.324 0 57.348 0.192 ;
    END
  END t1[235]
  PIN t1[236]
    DIRECTION OUTPUT ;
    USE SIGNAL ;
    PORT
      LAYER M5 ;
        RECT  57.564 0 57.588 0.192 ;
    END
  END t1[236]
  PIN t1[237]
    DIRECTION OUTPUT ;
    USE SIGNAL ;
    PORT
      LAYER M5 ;
        RECT  57.804 0 57.828 0.192 ;
    END
  END t1[237]
  PIN t1[238]
    DIRECTION OUTPUT ;
    USE SIGNAL ;
    PORT
      LAYER M5 ;
        RECT  58.044 0 58.068 0.192 ;
    END
  END t1[238]
  PIN t1[239]
    DIRECTION OUTPUT ;
    USE SIGNAL ;
    PORT
      LAYER M5 ;
        RECT  58.284 0 58.308 0.192 ;
    END
  END t1[239]
  PIN t1[23]
    DIRECTION OUTPUT ;
    USE SIGNAL ;
    PORT
      LAYER M5 ;
        RECT  7.5 0 7.524 0.192 ;
    END
  END t1[23]
  PIN t1[240]
    DIRECTION OUTPUT ;
    USE SIGNAL ;
    PORT
      LAYER M5 ;
        RECT  58.524 0 58.548 0.192 ;
    END
  END t1[240]
  PIN t1[241]
    DIRECTION OUTPUT ;
    USE SIGNAL ;
    PORT
      LAYER M5 ;
        RECT  58.764 0 58.788 0.192 ;
    END
  END t1[241]
  PIN t1[242]
    DIRECTION OUTPUT ;
    USE SIGNAL ;
    PORT
      LAYER M5 ;
        RECT  59.004 0 59.028 0.192 ;
    END
  END t1[242]
  PIN t1[243]
    DIRECTION OUTPUT ;
    USE SIGNAL ;
    PORT
      LAYER M5 ;
        RECT  59.196 0 59.22 0.192 ;
    END
  END t1[243]
  PIN t1[244]
    DIRECTION OUTPUT ;
    USE SIGNAL ;
    PORT
      LAYER M5 ;
        RECT  59.436 0 59.46 0.192 ;
    END
  END t1[244]
  PIN t1[245]
    DIRECTION OUTPUT ;
    USE SIGNAL ;
    PORT
      LAYER M5 ;
        RECT  59.676 0 59.7 0.192 ;
    END
  END t1[245]
  PIN t1[246]
    DIRECTION OUTPUT ;
    USE SIGNAL ;
    PORT
      LAYER M5 ;
        RECT  59.916 0 59.94 0.192 ;
    END
  END t1[246]
  PIN t1[247]
    DIRECTION OUTPUT ;
    USE SIGNAL ;
    PORT
      LAYER M5 ;
        RECT  60.156 0 60.18 0.192 ;
    END
  END t1[247]
  PIN t1[248]
    DIRECTION OUTPUT ;
    USE SIGNAL ;
    PORT
      LAYER M5 ;
        RECT  60.396 0 60.42 0.192 ;
    END
  END t1[248]
  PIN t1[249]
    DIRECTION OUTPUT ;
    USE SIGNAL ;
    PORT
      LAYER M5 ;
        RECT  60.636 0 60.66 0.192 ;
    END
  END t1[249]
  PIN t1[24]
    DIRECTION OUTPUT ;
    USE SIGNAL ;
    PORT
      LAYER M5 ;
        RECT  7.74 0 7.764 0.192 ;
    END
  END t1[24]
  PIN t1[250]
    DIRECTION OUTPUT ;
    USE SIGNAL ;
    PORT
      LAYER M5 ;
        RECT  60.876 0 60.9 0.192 ;
    END
  END t1[250]
  PIN t1[251]
    DIRECTION OUTPUT ;
    USE SIGNAL ;
    PORT
      LAYER M5 ;
        RECT  61.116 0 61.14 0.192 ;
    END
  END t1[251]
  PIN t1[252]
    DIRECTION OUTPUT ;
    USE SIGNAL ;
    PORT
      LAYER M5 ;
        RECT  61.356 0 61.38 0.192 ;
    END
  END t1[252]
  PIN t1[253]
    DIRECTION OUTPUT ;
    USE SIGNAL ;
    PORT
      LAYER M5 ;
        RECT  61.548 0 61.572 0.192 ;
    END
  END t1[253]
  PIN t1[254]
    DIRECTION OUTPUT ;
    USE SIGNAL ;
    PORT
      LAYER M5 ;
        RECT  61.788 0 61.812 0.192 ;
    END
  END t1[254]
  PIN t1[255]
    DIRECTION OUTPUT ;
    USE SIGNAL ;
    PORT
      LAYER M5 ;
        RECT  62.028 0 62.052 0.192 ;
    END
  END t1[255]
  PIN t1[256]
    DIRECTION OUTPUT ;
    USE SIGNAL ;
    PORT
      LAYER M5 ;
        RECT  62.268 0 62.292 0.192 ;
    END
  END t1[256]
  PIN t1[257]
    DIRECTION OUTPUT ;
    USE SIGNAL ;
    PORT
      LAYER M5 ;
        RECT  62.508 0 62.532 0.192 ;
    END
  END t1[257]
  PIN t1[258]
    DIRECTION OUTPUT ;
    USE SIGNAL ;
    PORT
      LAYER M5 ;
        RECT  62.748 0 62.772 0.192 ;
    END
  END t1[258]
  PIN t1[259]
    DIRECTION OUTPUT ;
    USE SIGNAL ;
    PORT
      LAYER M5 ;
        RECT  62.988 0 63.012 0.192 ;
    END
  END t1[259]
  PIN t1[25]
    DIRECTION OUTPUT ;
    USE SIGNAL ;
    PORT
      LAYER M5 ;
        RECT  7.98 0 8.004 0.192 ;
    END
  END t1[25]
  PIN t1[260]
    DIRECTION OUTPUT ;
    USE SIGNAL ;
    PORT
      LAYER M5 ;
        RECT  63.228 0 63.252 0.192 ;
    END
  END t1[260]
  PIN t1[261]
    DIRECTION OUTPUT ;
    USE SIGNAL ;
    PORT
      LAYER M5 ;
        RECT  63.468 0 63.492 0.192 ;
    END
  END t1[261]
  PIN t1[262]
    DIRECTION OUTPUT ;
    USE SIGNAL ;
    PORT
      LAYER M5 ;
        RECT  63.708 0 63.732 0.192 ;
    END
  END t1[262]
  PIN t1[263]
    DIRECTION OUTPUT ;
    USE SIGNAL ;
    PORT
      LAYER M5 ;
        RECT  63.9 0 63.924 0.192 ;
    END
  END t1[263]
  PIN t1[264]
    DIRECTION OUTPUT ;
    USE SIGNAL ;
    PORT
      LAYER M5 ;
        RECT  64.14 0 64.164 0.192 ;
    END
  END t1[264]
  PIN t1[265]
    DIRECTION OUTPUT ;
    USE SIGNAL ;
    PORT
      LAYER M5 ;
        RECT  64.38 0 64.404 0.192 ;
    END
  END t1[265]
  PIN t1[266]
    DIRECTION OUTPUT ;
    USE SIGNAL ;
    PORT
      LAYER M5 ;
        RECT  64.62 0 64.644 0.192 ;
    END
  END t1[266]
  PIN t1[267]
    DIRECTION OUTPUT ;
    USE SIGNAL ;
    PORT
      LAYER M5 ;
        RECT  64.86 0 64.884 0.192 ;
    END
  END t1[267]
  PIN t1[268]
    DIRECTION OUTPUT ;
    USE SIGNAL ;
    PORT
      LAYER M5 ;
        RECT  65.1 0 65.124 0.192 ;
    END
  END t1[268]
  PIN t1[269]
    DIRECTION OUTPUT ;
    USE SIGNAL ;
    PORT
      LAYER M5 ;
        RECT  65.34 0 65.364 0.192 ;
    END
  END t1[269]
  PIN t1[26]
    DIRECTION OUTPUT ;
    USE SIGNAL ;
    PORT
      LAYER M5 ;
        RECT  8.22 0 8.244 0.192 ;
    END
  END t1[26]
  PIN t1[270]
    DIRECTION OUTPUT ;
    USE SIGNAL ;
    PORT
      LAYER M5 ;
        RECT  65.58 0 65.604 0.192 ;
    END
  END t1[270]
  PIN t1[271]
    DIRECTION OUTPUT ;
    USE SIGNAL ;
    PORT
      LAYER M5 ;
        RECT  65.82 0 65.844 0.192 ;
    END
  END t1[271]
  PIN t1[272]
    DIRECTION OUTPUT ;
    USE SIGNAL ;
    PORT
      LAYER M5 ;
        RECT  66.012 0 66.036 0.192 ;
    END
  END t1[272]
  PIN t1[273]
    DIRECTION OUTPUT ;
    USE SIGNAL ;
    PORT
      LAYER M5 ;
        RECT  66.252 0 66.276 0.192 ;
    END
  END t1[273]
  PIN t1[274]
    DIRECTION OUTPUT ;
    USE SIGNAL ;
    PORT
      LAYER M5 ;
        RECT  66.492 0 66.516 0.192 ;
    END
  END t1[274]
  PIN t1[275]
    DIRECTION OUTPUT ;
    USE SIGNAL ;
    PORT
      LAYER M5 ;
        RECT  66.732 0 66.756 0.192 ;
    END
  END t1[275]
  PIN t1[276]
    DIRECTION OUTPUT ;
    USE SIGNAL ;
    PORT
      LAYER M5 ;
        RECT  66.972 0 66.996 0.192 ;
    END
  END t1[276]
  PIN t1[277]
    DIRECTION OUTPUT ;
    USE SIGNAL ;
    PORT
      LAYER M5 ;
        RECT  67.212 0 67.236 0.192 ;
    END
  END t1[277]
  PIN t1[278]
    DIRECTION OUTPUT ;
    USE SIGNAL ;
    PORT
      LAYER M5 ;
        RECT  67.452 0 67.476 0.192 ;
    END
  END t1[278]
  PIN t1[279]
    DIRECTION OUTPUT ;
    USE SIGNAL ;
    PORT
      LAYER M5 ;
        RECT  67.692 0 67.716 0.192 ;
    END
  END t1[279]
  PIN t1[27]
    DIRECTION OUTPUT ;
    USE SIGNAL ;
    PORT
      LAYER M5 ;
        RECT  8.46 0 8.484 0.192 ;
    END
  END t1[27]
  PIN t1[280]
    DIRECTION OUTPUT ;
    USE SIGNAL ;
    PORT
      LAYER M5 ;
        RECT  67.932 0 67.956 0.192 ;
    END
  END t1[280]
  PIN t1[281]
    DIRECTION OUTPUT ;
    USE SIGNAL ;
    PORT
      LAYER M5 ;
        RECT  68.172 0 68.196 0.192 ;
    END
  END t1[281]
  PIN t1[282]
    DIRECTION OUTPUT ;
    USE SIGNAL ;
    PORT
      LAYER M5 ;
        RECT  68.364 0 68.388 0.192 ;
    END
  END t1[282]
  PIN t1[283]
    DIRECTION OUTPUT ;
    USE SIGNAL ;
    PORT
      LAYER M5 ;
        RECT  68.604 0 68.628 0.192 ;
    END
  END t1[283]
  PIN t1[284]
    DIRECTION OUTPUT ;
    USE SIGNAL ;
    PORT
      LAYER M5 ;
        RECT  68.844 0 68.868 0.192 ;
    END
  END t1[284]
  PIN t1[285]
    DIRECTION OUTPUT ;
    USE SIGNAL ;
    PORT
      LAYER M5 ;
        RECT  69.084 0 69.108 0.192 ;
    END
  END t1[285]
  PIN t1[286]
    DIRECTION OUTPUT ;
    USE SIGNAL ;
    PORT
      LAYER M5 ;
        RECT  69.324 0 69.348 0.192 ;
    END
  END t1[286]
  PIN t1[287]
    DIRECTION OUTPUT ;
    USE SIGNAL ;
    PORT
      LAYER M5 ;
        RECT  69.564 0 69.588 0.192 ;
    END
  END t1[287]
  PIN t1[288]
    DIRECTION OUTPUT ;
    USE SIGNAL ;
    PORT
      LAYER M5 ;
        RECT  69.804 0 69.828 0.192 ;
    END
  END t1[288]
  PIN t1[289]
    DIRECTION OUTPUT ;
    USE SIGNAL ;
    PORT
      LAYER M5 ;
        RECT  70.044 0 70.068 0.192 ;
    END
  END t1[289]
  PIN t1[28]
    DIRECTION OUTPUT ;
    USE SIGNAL ;
    PORT
      LAYER M5 ;
        RECT  8.7 0 8.724 0.192 ;
    END
  END t1[28]
  PIN t1[290]
    DIRECTION OUTPUT ;
    USE SIGNAL ;
    PORT
      LAYER M5 ;
        RECT  70.284 0 70.308 0.192 ;
    END
  END t1[290]
  PIN t1[291]
    DIRECTION OUTPUT ;
    USE SIGNAL ;
    PORT
      LAYER M5 ;
        RECT  70.524 0 70.548 0.192 ;
    END
  END t1[291]
  PIN t1[292]
    DIRECTION OUTPUT ;
    USE SIGNAL ;
    PORT
      LAYER M5 ;
        RECT  70.716 0 70.74 0.192 ;
    END
  END t1[292]
  PIN t1[293]
    DIRECTION OUTPUT ;
    USE SIGNAL ;
    PORT
      LAYER M5 ;
        RECT  70.956 0 70.98 0.192 ;
    END
  END t1[293]
  PIN t1[294]
    DIRECTION OUTPUT ;
    USE SIGNAL ;
    PORT
      LAYER M5 ;
        RECT  71.196 0 71.22 0.192 ;
    END
  END t1[294]
  PIN t1[295]
    DIRECTION OUTPUT ;
    USE SIGNAL ;
    PORT
      LAYER M5 ;
        RECT  71.436 0 71.46 0.192 ;
    END
  END t1[295]
  PIN t1[296]
    DIRECTION OUTPUT ;
    USE SIGNAL ;
    PORT
      LAYER M5 ;
        RECT  71.676 0 71.7 0.192 ;
    END
  END t1[296]
  PIN t1[297]
    DIRECTION OUTPUT ;
    USE SIGNAL ;
    PORT
      LAYER M5 ;
        RECT  71.916 0 71.94 0.192 ;
    END
  END t1[297]
  PIN t1[298]
    DIRECTION OUTPUT ;
    USE SIGNAL ;
    PORT
      LAYER M5 ;
        RECT  72.156 0 72.18 0.192 ;
    END
  END t1[298]
  PIN t1[299]
    DIRECTION OUTPUT ;
    USE SIGNAL ;
    PORT
      LAYER M5 ;
        RECT  72.396 0 72.42 0.192 ;
    END
  END t1[299]
  PIN t1[29]
    DIRECTION OUTPUT ;
    USE SIGNAL ;
    PORT
      LAYER M5 ;
        RECT  8.94 0 8.964 0.192 ;
    END
  END t1[29]
  PIN t1[2]
    DIRECTION OUTPUT ;
    USE SIGNAL ;
    PORT
      LAYER M5 ;
        RECT  2.556 0 2.58 0.192 ;
    END
  END t1[2]
  PIN t1[300]
    DIRECTION OUTPUT ;
    USE SIGNAL ;
    PORT
      LAYER M5 ;
        RECT  72.636 0 72.66 0.192 ;
    END
  END t1[300]
  PIN t1[301]
    DIRECTION OUTPUT ;
    USE SIGNAL ;
    PORT
      LAYER M5 ;
        RECT  72.828 0 72.852 0.192 ;
    END
  END t1[301]
  PIN t1[302]
    DIRECTION OUTPUT ;
    USE SIGNAL ;
    PORT
      LAYER M5 ;
        RECT  73.068 0 73.092 0.192 ;
    END
  END t1[302]
  PIN t1[303]
    DIRECTION OUTPUT ;
    USE SIGNAL ;
    PORT
      LAYER M5 ;
        RECT  73.308 0 73.332 0.192 ;
    END
  END t1[303]
  PIN t1[304]
    DIRECTION OUTPUT ;
    USE SIGNAL ;
    PORT
      LAYER M5 ;
        RECT  73.548 0 73.572 0.192 ;
    END
  END t1[304]
  PIN t1[305]
    DIRECTION OUTPUT ;
    USE SIGNAL ;
    PORT
      LAYER M5 ;
        RECT  73.788 0 73.812 0.192 ;
    END
  END t1[305]
  PIN t1[306]
    DIRECTION OUTPUT ;
    USE SIGNAL ;
    PORT
      LAYER M5 ;
        RECT  74.028 0 74.052 0.192 ;
    END
  END t1[306]
  PIN t1[307]
    DIRECTION OUTPUT ;
    USE SIGNAL ;
    PORT
      LAYER M5 ;
        RECT  74.268 0 74.292 0.192 ;
    END
  END t1[307]
  PIN t1[308]
    DIRECTION OUTPUT ;
    USE SIGNAL ;
    PORT
      LAYER M5 ;
        RECT  74.508 0 74.532 0.192 ;
    END
  END t1[308]
  PIN t1[309]
    DIRECTION OUTPUT ;
    USE SIGNAL ;
    PORT
      LAYER M5 ;
        RECT  74.748 0 74.772 0.192 ;
    END
  END t1[309]
  PIN t1[30]
    DIRECTION OUTPUT ;
    USE SIGNAL ;
    PORT
      LAYER M5 ;
        RECT  9.18 0 9.204 0.192 ;
    END
  END t1[30]
  PIN t1[310]
    DIRECTION OUTPUT ;
    USE SIGNAL ;
    PORT
      LAYER M5 ;
        RECT  74.988 0 75.012 0.192 ;
    END
  END t1[310]
  PIN t1[311]
    DIRECTION OUTPUT ;
    USE SIGNAL ;
    PORT
      LAYER M5 ;
        RECT  75.18 0 75.204 0.192 ;
    END
  END t1[311]
  PIN t1[312]
    DIRECTION OUTPUT ;
    USE SIGNAL ;
    PORT
      LAYER M5 ;
        RECT  75.42 0 75.444 0.192 ;
    END
  END t1[312]
  PIN t1[313]
    DIRECTION OUTPUT ;
    USE SIGNAL ;
    PORT
      LAYER M5 ;
        RECT  75.66 0 75.684 0.192 ;
    END
  END t1[313]
  PIN t1[314]
    DIRECTION OUTPUT ;
    USE SIGNAL ;
    PORT
      LAYER M5 ;
        RECT  75.9 0 75.924 0.192 ;
    END
  END t1[314]
  PIN t1[315]
    DIRECTION OUTPUT ;
    USE SIGNAL ;
    PORT
      LAYER M5 ;
        RECT  76.14 0 76.164 0.192 ;
    END
  END t1[315]
  PIN t1[316]
    DIRECTION OUTPUT ;
    USE SIGNAL ;
    PORT
      LAYER M5 ;
        RECT  76.38 0 76.404 0.192 ;
    END
  END t1[316]
  PIN t1[317]
    DIRECTION OUTPUT ;
    USE SIGNAL ;
    PORT
      LAYER M5 ;
        RECT  76.62 0 76.644 0.192 ;
    END
  END t1[317]
  PIN t1[318]
    DIRECTION OUTPUT ;
    USE SIGNAL ;
    PORT
      LAYER M5 ;
        RECT  76.86 0 76.884 0.192 ;
    END
  END t1[318]
  PIN t1[319]
    DIRECTION OUTPUT ;
    USE SIGNAL ;
    PORT
      LAYER M5 ;
        RECT  77.1 0 77.124 0.192 ;
    END
  END t1[319]
  PIN t1[31]
    DIRECTION OUTPUT ;
    USE SIGNAL ;
    PORT
      LAYER M5 ;
        RECT  9.372 0 9.396 0.192 ;
    END
  END t1[31]
  PIN t1[320]
    DIRECTION OUTPUT ;
    USE SIGNAL ;
    PORT
      LAYER M5 ;
        RECT  77.34 0 77.364 0.192 ;
    END
  END t1[320]
  PIN t1[321]
    DIRECTION OUTPUT ;
    USE SIGNAL ;
    PORT
      LAYER M5 ;
        RECT  77.532 0 77.556 0.192 ;
    END
  END t1[321]
  PIN t1[322]
    DIRECTION OUTPUT ;
    USE SIGNAL ;
    PORT
      LAYER M5 ;
        RECT  77.772 0 77.796 0.192 ;
    END
  END t1[322]
  PIN t1[323]
    DIRECTION OUTPUT ;
    USE SIGNAL ;
    PORT
      LAYER M5 ;
        RECT  78.012 0 78.036 0.192 ;
    END
  END t1[323]
  PIN t1[324]
    DIRECTION OUTPUT ;
    USE SIGNAL ;
    PORT
      LAYER M5 ;
        RECT  78.252 0 78.276 0.192 ;
    END
  END t1[324]
  PIN t1[325]
    DIRECTION OUTPUT ;
    USE SIGNAL ;
    PORT
      LAYER M5 ;
        RECT  78.492 0 78.516 0.192 ;
    END
  END t1[325]
  PIN t1[326]
    DIRECTION OUTPUT ;
    USE SIGNAL ;
    PORT
      LAYER M5 ;
        RECT  78.732 0 78.756 0.192 ;
    END
  END t1[326]
  PIN t1[327]
    DIRECTION OUTPUT ;
    USE SIGNAL ;
    PORT
      LAYER M5 ;
        RECT  78.972 0 78.996 0.192 ;
    END
  END t1[327]
  PIN t1[328]
    DIRECTION OUTPUT ;
    USE SIGNAL ;
    PORT
      LAYER M5 ;
        RECT  79.212 0 79.236 0.192 ;
    END
  END t1[328]
  PIN t1[329]
    DIRECTION OUTPUT ;
    USE SIGNAL ;
    PORT
      LAYER M5 ;
        RECT  79.452 0 79.476 0.192 ;
    END
  END t1[329]
  PIN t1[32]
    DIRECTION OUTPUT ;
    USE SIGNAL ;
    PORT
      LAYER M5 ;
        RECT  9.612 0 9.636 0.192 ;
    END
  END t1[32]
  PIN t1[330]
    DIRECTION OUTPUT ;
    USE SIGNAL ;
    PORT
      LAYER M5 ;
        RECT  79.644 0 79.668 0.192 ;
    END
  END t1[330]
  PIN t1[331]
    DIRECTION OUTPUT ;
    USE SIGNAL ;
    PORT
      LAYER M5 ;
        RECT  79.884 0 79.908 0.192 ;
    END
  END t1[331]
  PIN t1[332]
    DIRECTION OUTPUT ;
    USE SIGNAL ;
    PORT
      LAYER M5 ;
        RECT  80.124 0 80.148 0.192 ;
    END
  END t1[332]
  PIN t1[333]
    DIRECTION OUTPUT ;
    USE SIGNAL ;
    PORT
      LAYER M5 ;
        RECT  80.364 0 80.388 0.192 ;
    END
  END t1[333]
  PIN t1[334]
    DIRECTION OUTPUT ;
    USE SIGNAL ;
    PORT
      LAYER M5 ;
        RECT  80.604 0 80.628 0.192 ;
    END
  END t1[334]
  PIN t1[335]
    DIRECTION OUTPUT ;
    USE SIGNAL ;
    PORT
      LAYER M5 ;
        RECT  80.844 0 80.868 0.192 ;
    END
  END t1[335]
  PIN t1[336]
    DIRECTION OUTPUT ;
    USE SIGNAL ;
    PORT
      LAYER M5 ;
        RECT  81.084 0 81.108 0.192 ;
    END
  END t1[336]
  PIN t1[337]
    DIRECTION OUTPUT ;
    USE SIGNAL ;
    PORT
      LAYER M5 ;
        RECT  81.324 0 81.348 0.192 ;
    END
  END t1[337]
  PIN t1[338]
    DIRECTION OUTPUT ;
    USE SIGNAL ;
    PORT
      LAYER M5 ;
        RECT  81.564 0 81.588 0.192 ;
    END
  END t1[338]
  PIN t1[339]
    DIRECTION OUTPUT ;
    USE SIGNAL ;
    PORT
      LAYER M5 ;
        RECT  81.804 0 81.828 0.192 ;
    END
  END t1[339]
  PIN t1[33]
    DIRECTION OUTPUT ;
    USE SIGNAL ;
    PORT
      LAYER M5 ;
        RECT  9.852 0 9.876 0.192 ;
    END
  END t1[33]
  PIN t1[340]
    DIRECTION OUTPUT ;
    USE SIGNAL ;
    PORT
      LAYER M5 ;
        RECT  81.996 0 82.02 0.192 ;
    END
  END t1[340]
  PIN t1[341]
    DIRECTION OUTPUT ;
    USE SIGNAL ;
    PORT
      LAYER M5 ;
        RECT  82.236 0 82.26 0.192 ;
    END
  END t1[341]
  PIN t1[342]
    DIRECTION OUTPUT ;
    USE SIGNAL ;
    PORT
      LAYER M5 ;
        RECT  82.476 0 82.5 0.192 ;
    END
  END t1[342]
  PIN t1[343]
    DIRECTION OUTPUT ;
    USE SIGNAL ;
    PORT
      LAYER M5 ;
        RECT  82.716 0 82.74 0.192 ;
    END
  END t1[343]
  PIN t1[344]
    DIRECTION OUTPUT ;
    USE SIGNAL ;
    PORT
      LAYER M5 ;
        RECT  82.956 0 82.98 0.192 ;
    END
  END t1[344]
  PIN t1[345]
    DIRECTION OUTPUT ;
    USE SIGNAL ;
    PORT
      LAYER M5 ;
        RECT  83.196 0 83.22 0.192 ;
    END
  END t1[345]
  PIN t1[346]
    DIRECTION OUTPUT ;
    USE SIGNAL ;
    PORT
      LAYER M5 ;
        RECT  83.436 0 83.46 0.192 ;
    END
  END t1[346]
  PIN t1[347]
    DIRECTION OUTPUT ;
    USE SIGNAL ;
    PORT
      LAYER M5 ;
        RECT  83.676 0 83.7 0.192 ;
    END
  END t1[347]
  PIN t1[348]
    DIRECTION OUTPUT ;
    USE SIGNAL ;
    PORT
      LAYER M5 ;
        RECT  83.916 0 83.94 0.192 ;
    END
  END t1[348]
  PIN t1[349]
    DIRECTION OUTPUT ;
    USE SIGNAL ;
    PORT
      LAYER M5 ;
        RECT  84.156 0 84.18 0.192 ;
    END
  END t1[349]
  PIN t1[34]
    DIRECTION OUTPUT ;
    USE SIGNAL ;
    PORT
      LAYER M5 ;
        RECT  10.092 0 10.116 0.192 ;
    END
  END t1[34]
  PIN t1[350]
    DIRECTION OUTPUT ;
    USE SIGNAL ;
    PORT
      LAYER M5 ;
        RECT  84.348 0 84.372 0.192 ;
    END
  END t1[350]
  PIN t1[351]
    DIRECTION OUTPUT ;
    USE SIGNAL ;
    PORT
      LAYER M5 ;
        RECT  84.588 0 84.612 0.192 ;
    END
  END t1[351]
  PIN t1[352]
    DIRECTION OUTPUT ;
    USE SIGNAL ;
    PORT
      LAYER M5 ;
        RECT  84.828 0 84.852 0.192 ;
    END
  END t1[352]
  PIN t1[353]
    DIRECTION OUTPUT ;
    USE SIGNAL ;
    PORT
      LAYER M5 ;
        RECT  85.068 0 85.092 0.192 ;
    END
  END t1[353]
  PIN t1[354]
    DIRECTION OUTPUT ;
    USE SIGNAL ;
    PORT
      LAYER M5 ;
        RECT  85.308 0 85.332 0.192 ;
    END
  END t1[354]
  PIN t1[355]
    DIRECTION OUTPUT ;
    USE SIGNAL ;
    PORT
      LAYER M5 ;
        RECT  85.548 0 85.572 0.192 ;
    END
  END t1[355]
  PIN t1[356]
    DIRECTION OUTPUT ;
    USE SIGNAL ;
    PORT
      LAYER M5 ;
        RECT  85.788 0 85.812 0.192 ;
    END
  END t1[356]
  PIN t1[357]
    DIRECTION OUTPUT ;
    USE SIGNAL ;
    PORT
      LAYER M5 ;
        RECT  86.028 0 86.052 0.192 ;
    END
  END t1[357]
  PIN t1[358]
    DIRECTION OUTPUT ;
    USE SIGNAL ;
    PORT
      LAYER M5 ;
        RECT  86.268 0 86.292 0.192 ;
    END
  END t1[358]
  PIN t1[359]
    DIRECTION OUTPUT ;
    USE SIGNAL ;
    PORT
      LAYER M5 ;
        RECT  86.46 0 86.484 0.192 ;
    END
  END t1[359]
  PIN t1[35]
    DIRECTION OUTPUT ;
    USE SIGNAL ;
    PORT
      LAYER M5 ;
        RECT  10.332 0 10.356 0.192 ;
    END
  END t1[35]
  PIN t1[360]
    DIRECTION OUTPUT ;
    USE SIGNAL ;
    PORT
      LAYER M5 ;
        RECT  86.7 0 86.724 0.192 ;
    END
  END t1[360]
  PIN t1[361]
    DIRECTION OUTPUT ;
    USE SIGNAL ;
    PORT
      LAYER M5 ;
        RECT  86.94 0 86.964 0.192 ;
    END
  END t1[361]
  PIN t1[362]
    DIRECTION OUTPUT ;
    USE SIGNAL ;
    PORT
      LAYER M5 ;
        RECT  87.18 0 87.204 0.192 ;
    END
  END t1[362]
  PIN t1[363]
    DIRECTION OUTPUT ;
    USE SIGNAL ;
    PORT
      LAYER M5 ;
        RECT  87.42 0 87.444 0.192 ;
    END
  END t1[363]
  PIN t1[364]
    DIRECTION OUTPUT ;
    USE SIGNAL ;
    PORT
      LAYER M5 ;
        RECT  87.66 0 87.684 0.192 ;
    END
  END t1[364]
  PIN t1[365]
    DIRECTION OUTPUT ;
    USE SIGNAL ;
    PORT
      LAYER M5 ;
        RECT  87.9 0 87.924 0.192 ;
    END
  END t1[365]
  PIN t1[366]
    DIRECTION OUTPUT ;
    USE SIGNAL ;
    PORT
      LAYER M5 ;
        RECT  88.14 0 88.164 0.192 ;
    END
  END t1[366]
  PIN t1[367]
    DIRECTION OUTPUT ;
    USE SIGNAL ;
    PORT
      LAYER M5 ;
        RECT  88.38 0 88.404 0.192 ;
    END
  END t1[367]
  PIN t1[368]
    DIRECTION OUTPUT ;
    USE SIGNAL ;
    PORT
      LAYER M5 ;
        RECT  88.62 0 88.644 0.192 ;
    END
  END t1[368]
  PIN t1[369]
    DIRECTION OUTPUT ;
    USE SIGNAL ;
    PORT
      LAYER M5 ;
        RECT  88.812 0 88.836 0.192 ;
    END
  END t1[369]
  PIN t1[36]
    DIRECTION OUTPUT ;
    USE SIGNAL ;
    PORT
      LAYER M5 ;
        RECT  10.572 0 10.596 0.192 ;
    END
  END t1[36]
  PIN t1[370]
    DIRECTION OUTPUT ;
    USE SIGNAL ;
    PORT
      LAYER M5 ;
        RECT  89.052 0 89.076 0.192 ;
    END
  END t1[370]
  PIN t1[371]
    DIRECTION OUTPUT ;
    USE SIGNAL ;
    PORT
      LAYER M5 ;
        RECT  89.292 0 89.316 0.192 ;
    END
  END t1[371]
  PIN t1[372]
    DIRECTION OUTPUT ;
    USE SIGNAL ;
    PORT
      LAYER M5 ;
        RECT  89.532 0 89.556 0.192 ;
    END
  END t1[372]
  PIN t1[373]
    DIRECTION OUTPUT ;
    USE SIGNAL ;
    PORT
      LAYER M5 ;
        RECT  89.772 0 89.796 0.192 ;
    END
  END t1[373]
  PIN t1[374]
    DIRECTION OUTPUT ;
    USE SIGNAL ;
    PORT
      LAYER M5 ;
        RECT  90.012 0 90.036 0.192 ;
    END
  END t1[374]
  PIN t1[375]
    DIRECTION OUTPUT ;
    USE SIGNAL ;
    PORT
      LAYER M5 ;
        RECT  90.252 0 90.276 0.192 ;
    END
  END t1[375]
  PIN t1[376]
    DIRECTION OUTPUT ;
    USE SIGNAL ;
    PORT
      LAYER M5 ;
        RECT  90.492 0 90.516 0.192 ;
    END
  END t1[376]
  PIN t1[377]
    DIRECTION OUTPUT ;
    USE SIGNAL ;
    PORT
      LAYER M5 ;
        RECT  90.732 0 90.756 0.192 ;
    END
  END t1[377]
  PIN t1[378]
    DIRECTION OUTPUT ;
    USE SIGNAL ;
    PORT
      LAYER M5 ;
        RECT  90.972 0 90.996 0.192 ;
    END
  END t1[378]
  PIN t1[379]
    DIRECTION OUTPUT ;
    USE SIGNAL ;
    PORT
      LAYER M5 ;
        RECT  91.164 0 91.188 0.192 ;
    END
  END t1[379]
  PIN t1[37]
    DIRECTION OUTPUT ;
    USE SIGNAL ;
    PORT
      LAYER M5 ;
        RECT  10.812 0 10.836 0.192 ;
    END
  END t1[37]
  PIN t1[380]
    DIRECTION OUTPUT ;
    USE SIGNAL ;
    PORT
      LAYER M5 ;
        RECT  91.404 0 91.428 0.192 ;
    END
  END t1[380]
  PIN t1[381]
    DIRECTION OUTPUT ;
    USE SIGNAL ;
    PORT
      LAYER M5 ;
        RECT  91.644 0 91.668 0.192 ;
    END
  END t1[381]
  PIN t1[382]
    DIRECTION OUTPUT ;
    USE SIGNAL ;
    PORT
      LAYER M5 ;
        RECT  91.884 0 91.908 0.192 ;
    END
  END t1[382]
  PIN t1[383]
    DIRECTION OUTPUT ;
    USE SIGNAL ;
    PORT
      LAYER M5 ;
        RECT  92.124 0 92.148 0.192 ;
    END
  END t1[383]
  PIN t1[384]
    DIRECTION OUTPUT ;
    USE SIGNAL ;
    PORT
      LAYER M5 ;
        RECT  92.364 0 92.388 0.192 ;
    END
  END t1[384]
  PIN t1[385]
    DIRECTION OUTPUT ;
    USE SIGNAL ;
    PORT
      LAYER M5 ;
        RECT  92.604 0 92.628 0.192 ;
    END
  END t1[385]
  PIN t1[386]
    DIRECTION OUTPUT ;
    USE SIGNAL ;
    PORT
      LAYER M5 ;
        RECT  92.844 0 92.868 0.192 ;
    END
  END t1[386]
  PIN t1[387]
    DIRECTION OUTPUT ;
    USE SIGNAL ;
    PORT
      LAYER M5 ;
        RECT  93.084 0 93.108 0.192 ;
    END
  END t1[387]
  PIN t1[388]
    DIRECTION OUTPUT ;
    USE SIGNAL ;
    PORT
      LAYER M5 ;
        RECT  93.276 0 93.3 0.192 ;
    END
  END t1[388]
  PIN t1[389]
    DIRECTION OUTPUT ;
    USE SIGNAL ;
    PORT
      LAYER M5 ;
        RECT  93.516 0 93.54 0.192 ;
    END
  END t1[389]
  PIN t1[38]
    DIRECTION OUTPUT ;
    USE SIGNAL ;
    PORT
      LAYER M5 ;
        RECT  11.052 0 11.076 0.192 ;
    END
  END t1[38]
  PIN t1[390]
    DIRECTION OUTPUT ;
    USE SIGNAL ;
    PORT
      LAYER M5 ;
        RECT  93.756 0 93.78 0.192 ;
    END
  END t1[390]
  PIN t1[391]
    DIRECTION OUTPUT ;
    USE SIGNAL ;
    PORT
      LAYER M5 ;
        RECT  93.996 0 94.02 0.192 ;
    END
  END t1[391]
  PIN t1[392]
    DIRECTION OUTPUT ;
    USE SIGNAL ;
    PORT
      LAYER M5 ;
        RECT  94.236 0 94.26 0.192 ;
    END
  END t1[392]
  PIN t1[393]
    DIRECTION OUTPUT ;
    USE SIGNAL ;
    PORT
      LAYER M5 ;
        RECT  94.476 0 94.5 0.192 ;
    END
  END t1[393]
  PIN t1[394]
    DIRECTION OUTPUT ;
    USE SIGNAL ;
    PORT
      LAYER M5 ;
        RECT  94.716 0 94.74 0.192 ;
    END
  END t1[394]
  PIN t1[395]
    DIRECTION OUTPUT ;
    USE SIGNAL ;
    PORT
      LAYER M5 ;
        RECT  94.956 0 94.98 0.192 ;
    END
  END t1[395]
  PIN t1[396]
    DIRECTION OUTPUT ;
    USE SIGNAL ;
    PORT
      LAYER M5 ;
        RECT  95.196 0 95.22 0.192 ;
    END
  END t1[396]
  PIN t1[397]
    DIRECTION OUTPUT ;
    USE SIGNAL ;
    PORT
      LAYER M5 ;
        RECT  95.436 0 95.46 0.192 ;
    END
  END t1[397]
  PIN t1[398]
    DIRECTION OUTPUT ;
    USE SIGNAL ;
    PORT
      LAYER M5 ;
        RECT  95.628 0 95.652 0.192 ;
    END
  END t1[398]
  PIN t1[399]
    DIRECTION OUTPUT ;
    USE SIGNAL ;
    PORT
      LAYER M5 ;
        RECT  95.868 0 95.892 0.192 ;
    END
  END t1[399]
  PIN t1[39]
    DIRECTION OUTPUT ;
    USE SIGNAL ;
    PORT
      LAYER M5 ;
        RECT  11.292 0 11.316 0.192 ;
    END
  END t1[39]
  PIN t1[3]
    DIRECTION OUTPUT ;
    USE SIGNAL ;
    PORT
      LAYER M5 ;
        RECT  2.796 0 2.82 0.192 ;
    END
  END t1[3]
  PIN t1[400]
    DIRECTION OUTPUT ;
    USE SIGNAL ;
    PORT
      LAYER M5 ;
        RECT  96.108 0 96.132 0.192 ;
    END
  END t1[400]
  PIN t1[401]
    DIRECTION OUTPUT ;
    USE SIGNAL ;
    PORT
      LAYER M5 ;
        RECT  96.348 0 96.372 0.192 ;
    END
  END t1[401]
  PIN t1[402]
    DIRECTION OUTPUT ;
    USE SIGNAL ;
    PORT
      LAYER M5 ;
        RECT  96.588 0 96.612 0.192 ;
    END
  END t1[402]
  PIN t1[403]
    DIRECTION OUTPUT ;
    USE SIGNAL ;
    PORT
      LAYER M5 ;
        RECT  96.828 0 96.852 0.192 ;
    END
  END t1[403]
  PIN t1[404]
    DIRECTION OUTPUT ;
    USE SIGNAL ;
    PORT
      LAYER M5 ;
        RECT  97.068 0 97.092 0.192 ;
    END
  END t1[404]
  PIN t1[405]
    DIRECTION OUTPUT ;
    USE SIGNAL ;
    PORT
      LAYER M5 ;
        RECT  97.308 0 97.332 0.192 ;
    END
  END t1[405]
  PIN t1[406]
    DIRECTION OUTPUT ;
    USE SIGNAL ;
    PORT
      LAYER M5 ;
        RECT  97.548 0 97.572 0.192 ;
    END
  END t1[406]
  PIN t1[407]
    DIRECTION OUTPUT ;
    USE SIGNAL ;
    PORT
      LAYER M5 ;
        RECT  97.788 0 97.812 0.192 ;
    END
  END t1[407]
  PIN t1[408]
    DIRECTION OUTPUT ;
    USE SIGNAL ;
    PORT
      LAYER M5 ;
        RECT  97.98 0 98.004 0.192 ;
    END
  END t1[408]
  PIN t1[409]
    DIRECTION OUTPUT ;
    USE SIGNAL ;
    PORT
      LAYER M5 ;
        RECT  98.22 0 98.244 0.192 ;
    END
  END t1[409]
  PIN t1[40]
    DIRECTION OUTPUT ;
    USE SIGNAL ;
    PORT
      LAYER M5 ;
        RECT  11.484 0 11.508 0.192 ;
    END
  END t1[40]
  PIN t1[410]
    DIRECTION OUTPUT ;
    USE SIGNAL ;
    PORT
      LAYER M5 ;
        RECT  98.46 0 98.484 0.192 ;
    END
  END t1[410]
  PIN t1[411]
    DIRECTION OUTPUT ;
    USE SIGNAL ;
    PORT
      LAYER M5 ;
        RECT  98.7 0 98.724 0.192 ;
    END
  END t1[411]
  PIN t1[412]
    DIRECTION OUTPUT ;
    USE SIGNAL ;
    PORT
      LAYER M5 ;
        RECT  98.94 0 98.964 0.192 ;
    END
  END t1[412]
  PIN t1[413]
    DIRECTION OUTPUT ;
    USE SIGNAL ;
    PORT
      LAYER M5 ;
        RECT  99.18 0 99.204 0.192 ;
    END
  END t1[413]
  PIN t1[414]
    DIRECTION OUTPUT ;
    USE SIGNAL ;
    PORT
      LAYER M5 ;
        RECT  99.42 0 99.444 0.192 ;
    END
  END t1[414]
  PIN t1[415]
    DIRECTION OUTPUT ;
    USE SIGNAL ;
    PORT
      LAYER M5 ;
        RECT  99.66 0 99.684 0.192 ;
    END
  END t1[415]
  PIN t1[416]
    DIRECTION OUTPUT ;
    USE SIGNAL ;
    PORT
      LAYER M5 ;
        RECT  99.9 0 99.924 0.192 ;
    END
  END t1[416]
  PIN t1[417]
    DIRECTION OUTPUT ;
    USE SIGNAL ;
    PORT
      LAYER M5 ;
        RECT  100.092 0 100.116 0.192 ;
    END
  END t1[417]
  PIN t1[418]
    DIRECTION OUTPUT ;
    USE SIGNAL ;
    PORT
      LAYER M5 ;
        RECT  100.332 0 100.356 0.192 ;
    END
  END t1[418]
  PIN t1[419]
    DIRECTION OUTPUT ;
    USE SIGNAL ;
    PORT
      LAYER M5 ;
        RECT  100.572 0 100.596 0.192 ;
    END
  END t1[419]
  PIN t1[41]
    DIRECTION OUTPUT ;
    USE SIGNAL ;
    PORT
      LAYER M5 ;
        RECT  11.724 0 11.748 0.192 ;
    END
  END t1[41]
  PIN t1[420]
    DIRECTION OUTPUT ;
    USE SIGNAL ;
    PORT
      LAYER M5 ;
        RECT  100.812 0 100.836 0.192 ;
    END
  END t1[420]
  PIN t1[421]
    DIRECTION OUTPUT ;
    USE SIGNAL ;
    PORT
      LAYER M5 ;
        RECT  101.052 0 101.076 0.192 ;
    END
  END t1[421]
  PIN t1[422]
    DIRECTION OUTPUT ;
    USE SIGNAL ;
    PORT
      LAYER M5 ;
        RECT  101.292 0 101.316 0.192 ;
    END
  END t1[422]
  PIN t1[423]
    DIRECTION OUTPUT ;
    USE SIGNAL ;
    PORT
      LAYER M5 ;
        RECT  101.532 0 101.556 0.192 ;
    END
  END t1[423]
  PIN t1[424]
    DIRECTION OUTPUT ;
    USE SIGNAL ;
    PORT
      LAYER M5 ;
        RECT  101.772 0 101.796 0.192 ;
    END
  END t1[424]
  PIN t1[425]
    DIRECTION OUTPUT ;
    USE SIGNAL ;
    PORT
      LAYER M5 ;
        RECT  102.012 0 102.036 0.192 ;
    END
  END t1[425]
  PIN t1[426]
    DIRECTION OUTPUT ;
    USE SIGNAL ;
    PORT
      LAYER M5 ;
        RECT  102.252 0 102.276 0.192 ;
    END
  END t1[426]
  PIN t1[427]
    DIRECTION OUTPUT ;
    USE SIGNAL ;
    PORT
      LAYER M5 ;
        RECT  102.444 0 102.468 0.192 ;
    END
  END t1[427]
  PIN t1[428]
    DIRECTION OUTPUT ;
    USE SIGNAL ;
    PORT
      LAYER M5 ;
        RECT  102.684 0 102.708 0.192 ;
    END
  END t1[428]
  PIN t1[429]
    DIRECTION OUTPUT ;
    USE SIGNAL ;
    PORT
      LAYER M5 ;
        RECT  102.924 0 102.948 0.192 ;
    END
  END t1[429]
  PIN t1[42]
    DIRECTION OUTPUT ;
    USE SIGNAL ;
    PORT
      LAYER M5 ;
        RECT  11.964 0 11.988 0.192 ;
    END
  END t1[42]
  PIN t1[430]
    DIRECTION OUTPUT ;
    USE SIGNAL ;
    PORT
      LAYER M5 ;
        RECT  103.164 0 103.188 0.192 ;
    END
  END t1[430]
  PIN t1[431]
    DIRECTION OUTPUT ;
    USE SIGNAL ;
    PORT
      LAYER M5 ;
        RECT  103.404 0 103.428 0.192 ;
    END
  END t1[431]
  PIN t1[432]
    DIRECTION OUTPUT ;
    USE SIGNAL ;
    PORT
      LAYER M5 ;
        RECT  103.644 0 103.668 0.192 ;
    END
  END t1[432]
  PIN t1[433]
    DIRECTION OUTPUT ;
    USE SIGNAL ;
    PORT
      LAYER M5 ;
        RECT  103.884 0 103.908 0.192 ;
    END
  END t1[433]
  PIN t1[434]
    DIRECTION OUTPUT ;
    USE SIGNAL ;
    PORT
      LAYER M5 ;
        RECT  104.124 0 104.148 0.192 ;
    END
  END t1[434]
  PIN t1[435]
    DIRECTION OUTPUT ;
    USE SIGNAL ;
    PORT
      LAYER M5 ;
        RECT  104.364 0 104.388 0.192 ;
    END
  END t1[435]
  PIN t1[436]
    DIRECTION OUTPUT ;
    USE SIGNAL ;
    PORT
      LAYER M5 ;
        RECT  104.604 0 104.628 0.192 ;
    END
  END t1[436]
  PIN t1[437]
    DIRECTION OUTPUT ;
    USE SIGNAL ;
    PORT
      LAYER M5 ;
        RECT  104.796 0 104.82 0.192 ;
    END
  END t1[437]
  PIN t1[438]
    DIRECTION OUTPUT ;
    USE SIGNAL ;
    PORT
      LAYER M5 ;
        RECT  105.036 0 105.06 0.192 ;
    END
  END t1[438]
  PIN t1[439]
    DIRECTION OUTPUT ;
    USE SIGNAL ;
    PORT
      LAYER M5 ;
        RECT  105.276 0 105.3 0.192 ;
    END
  END t1[439]
  PIN t1[43]
    DIRECTION OUTPUT ;
    USE SIGNAL ;
    PORT
      LAYER M5 ;
        RECT  12.204 0 12.228 0.192 ;
    END
  END t1[43]
  PIN t1[440]
    DIRECTION OUTPUT ;
    USE SIGNAL ;
    PORT
      LAYER M5 ;
        RECT  105.516 0 105.54 0.192 ;
    END
  END t1[440]
  PIN t1[441]
    DIRECTION OUTPUT ;
    USE SIGNAL ;
    PORT
      LAYER M5 ;
        RECT  105.756 0 105.78 0.192 ;
    END
  END t1[441]
  PIN t1[442]
    DIRECTION OUTPUT ;
    USE SIGNAL ;
    PORT
      LAYER M5 ;
        RECT  105.996 0 106.02 0.192 ;
    END
  END t1[442]
  PIN t1[443]
    DIRECTION OUTPUT ;
    USE SIGNAL ;
    PORT
      LAYER M5 ;
        RECT  106.236 0 106.26 0.192 ;
    END
  END t1[443]
  PIN t1[444]
    DIRECTION OUTPUT ;
    USE SIGNAL ;
    PORT
      LAYER M5 ;
        RECT  106.476 0 106.5 0.192 ;
    END
  END t1[444]
  PIN t1[445]
    DIRECTION OUTPUT ;
    USE SIGNAL ;
    PORT
      LAYER M5 ;
        RECT  106.716 0 106.74 0.192 ;
    END
  END t1[445]
  PIN t1[446]
    DIRECTION OUTPUT ;
    USE SIGNAL ;
    PORT
      LAYER M5 ;
        RECT  106.908 0 106.932 0.192 ;
    END
  END t1[446]
  PIN t1[447]
    DIRECTION OUTPUT ;
    USE SIGNAL ;
    PORT
      LAYER M5 ;
        RECT  107.148 0 107.172 0.192 ;
    END
  END t1[447]
  PIN t1[448]
    DIRECTION OUTPUT ;
    USE SIGNAL ;
    PORT
      LAYER M5 ;
        RECT  107.388 0 107.412 0.192 ;
    END
  END t1[448]
  PIN t1[449]
    DIRECTION OUTPUT ;
    USE SIGNAL ;
    PORT
      LAYER M5 ;
        RECT  107.628 0 107.652 0.192 ;
    END
  END t1[449]
  PIN t1[44]
    DIRECTION OUTPUT ;
    USE SIGNAL ;
    PORT
      LAYER M5 ;
        RECT  12.444 0 12.468 0.192 ;
    END
  END t1[44]
  PIN t1[450]
    DIRECTION OUTPUT ;
    USE SIGNAL ;
    PORT
      LAYER M5 ;
        RECT  107.868 0 107.892 0.192 ;
    END
  END t1[450]
  PIN t1[451]
    DIRECTION OUTPUT ;
    USE SIGNAL ;
    PORT
      LAYER M5 ;
        RECT  108.108 0 108.132 0.192 ;
    END
  END t1[451]
  PIN t1[452]
    DIRECTION OUTPUT ;
    USE SIGNAL ;
    PORT
      LAYER M5 ;
        RECT  108.348 0 108.372 0.192 ;
    END
  END t1[452]
  PIN t1[453]
    DIRECTION OUTPUT ;
    USE SIGNAL ;
    PORT
      LAYER M5 ;
        RECT  108.588 0 108.612 0.192 ;
    END
  END t1[453]
  PIN t1[454]
    DIRECTION OUTPUT ;
    USE SIGNAL ;
    PORT
      LAYER M5 ;
        RECT  108.828 0 108.852 0.192 ;
    END
  END t1[454]
  PIN t1[455]
    DIRECTION OUTPUT ;
    USE SIGNAL ;
    PORT
      LAYER M5 ;
        RECT  109.068 0 109.092 0.192 ;
    END
  END t1[455]
  PIN t1[456]
    DIRECTION OUTPUT ;
    USE SIGNAL ;
    PORT
      LAYER M5 ;
        RECT  109.26 0 109.284 0.192 ;
    END
  END t1[456]
  PIN t1[457]
    DIRECTION OUTPUT ;
    USE SIGNAL ;
    PORT
      LAYER M5 ;
        RECT  109.5 0 109.524 0.192 ;
    END
  END t1[457]
  PIN t1[458]
    DIRECTION OUTPUT ;
    USE SIGNAL ;
    PORT
      LAYER M5 ;
        RECT  109.74 0 109.764 0.192 ;
    END
  END t1[458]
  PIN t1[459]
    DIRECTION OUTPUT ;
    USE SIGNAL ;
    PORT
      LAYER M5 ;
        RECT  109.98 0 110.004 0.192 ;
    END
  END t1[459]
  PIN t1[45]
    DIRECTION OUTPUT ;
    USE SIGNAL ;
    PORT
      LAYER M5 ;
        RECT  12.684 0 12.708 0.192 ;
    END
  END t1[45]
  PIN t1[460]
    DIRECTION OUTPUT ;
    USE SIGNAL ;
    PORT
      LAYER M5 ;
        RECT  110.22 0 110.244 0.192 ;
    END
  END t1[460]
  PIN t1[461]
    DIRECTION OUTPUT ;
    USE SIGNAL ;
    PORT
      LAYER M5 ;
        RECT  110.46 0 110.484 0.192 ;
    END
  END t1[461]
  PIN t1[462]
    DIRECTION OUTPUT ;
    USE SIGNAL ;
    PORT
      LAYER M5 ;
        RECT  110.7 0 110.724 0.192 ;
    END
  END t1[462]
  PIN t1[463]
    DIRECTION OUTPUT ;
    USE SIGNAL ;
    PORT
      LAYER M5 ;
        RECT  110.94 0 110.964 0.192 ;
    END
  END t1[463]
  PIN t1[464]
    DIRECTION OUTPUT ;
    USE SIGNAL ;
    PORT
      LAYER M5 ;
        RECT  111.18 0 111.204 0.192 ;
    END
  END t1[464]
  PIN t1[465]
    DIRECTION OUTPUT ;
    USE SIGNAL ;
    PORT
      LAYER M5 ;
        RECT  111.372 0 111.396 0.192 ;
    END
  END t1[465]
  PIN t1[466]
    DIRECTION OUTPUT ;
    USE SIGNAL ;
    PORT
      LAYER M5 ;
        RECT  111.612 0 111.636 0.192 ;
    END
  END t1[466]
  PIN t1[467]
    DIRECTION OUTPUT ;
    USE SIGNAL ;
    PORT
      LAYER M5 ;
        RECT  111.852 0 111.876 0.192 ;
    END
  END t1[467]
  PIN t1[468]
    DIRECTION OUTPUT ;
    USE SIGNAL ;
    PORT
      LAYER M5 ;
        RECT  112.092 0 112.116 0.192 ;
    END
  END t1[468]
  PIN t1[469]
    DIRECTION OUTPUT ;
    USE SIGNAL ;
    PORT
      LAYER M5 ;
        RECT  112.332 0 112.356 0.192 ;
    END
  END t1[469]
  PIN t1[46]
    DIRECTION OUTPUT ;
    USE SIGNAL ;
    PORT
      LAYER M5 ;
        RECT  12.924 0 12.948 0.192 ;
    END
  END t1[46]
  PIN t1[470]
    DIRECTION OUTPUT ;
    USE SIGNAL ;
    PORT
      LAYER M5 ;
        RECT  112.572 0 112.596 0.192 ;
    END
  END t1[470]
  PIN t1[471]
    DIRECTION OUTPUT ;
    USE SIGNAL ;
    PORT
      LAYER M5 ;
        RECT  112.812 0 112.836 0.192 ;
    END
  END t1[471]
  PIN t1[472]
    DIRECTION OUTPUT ;
    USE SIGNAL ;
    PORT
      LAYER M5 ;
        RECT  113.052 0 113.076 0.192 ;
    END
  END t1[472]
  PIN t1[473]
    DIRECTION OUTPUT ;
    USE SIGNAL ;
    PORT
      LAYER M5 ;
        RECT  113.292 0 113.316 0.192 ;
    END
  END t1[473]
  PIN t1[474]
    DIRECTION OUTPUT ;
    USE SIGNAL ;
    PORT
      LAYER M5 ;
        RECT  113.532 0 113.556 0.192 ;
    END
  END t1[474]
  PIN t1[475]
    DIRECTION OUTPUT ;
    USE SIGNAL ;
    PORT
      LAYER M5 ;
        RECT  113.724 0 113.748 0.192 ;
    END
  END t1[475]
  PIN t1[476]
    DIRECTION OUTPUT ;
    USE SIGNAL ;
    PORT
      LAYER M5 ;
        RECT  113.964 0 113.988 0.192 ;
    END
  END t1[476]
  PIN t1[477]
    DIRECTION OUTPUT ;
    USE SIGNAL ;
    PORT
      LAYER M5 ;
        RECT  114.204 0 114.228 0.192 ;
    END
  END t1[477]
  PIN t1[478]
    DIRECTION OUTPUT ;
    USE SIGNAL ;
    PORT
      LAYER M5 ;
        RECT  114.444 0 114.468 0.192 ;
    END
  END t1[478]
  PIN t1[479]
    DIRECTION OUTPUT ;
    USE SIGNAL ;
    PORT
      LAYER M5 ;
        RECT  114.684 0 114.708 0.192 ;
    END
  END t1[479]
  PIN t1[47]
    DIRECTION OUTPUT ;
    USE SIGNAL ;
    PORT
      LAYER M5 ;
        RECT  13.164 0 13.188 0.192 ;
    END
  END t1[47]
  PIN t1[480]
    DIRECTION OUTPUT ;
    USE SIGNAL ;
    PORT
      LAYER M5 ;
        RECT  114.924 0 114.948 0.192 ;
    END
  END t1[480]
  PIN t1[481]
    DIRECTION OUTPUT ;
    USE SIGNAL ;
    PORT
      LAYER M5 ;
        RECT  115.164 0 115.188 0.192 ;
    END
  END t1[481]
  PIN t1[482]
    DIRECTION OUTPUT ;
    USE SIGNAL ;
    PORT
      LAYER M5 ;
        RECT  115.404 0 115.428 0.192 ;
    END
  END t1[482]
  PIN t1[483]
    DIRECTION OUTPUT ;
    USE SIGNAL ;
    PORT
      LAYER M5 ;
        RECT  115.644 0 115.668 0.192 ;
    END
  END t1[483]
  PIN t1[484]
    DIRECTION OUTPUT ;
    USE SIGNAL ;
    PORT
      LAYER M5 ;
        RECT  115.884 0 115.908 0.192 ;
    END
  END t1[484]
  PIN t1[485]
    DIRECTION OUTPUT ;
    USE SIGNAL ;
    PORT
      LAYER M5 ;
        RECT  116.076 0 116.1 0.192 ;
    END
  END t1[485]
  PIN t1[486]
    DIRECTION OUTPUT ;
    USE SIGNAL ;
    PORT
      LAYER M5 ;
        RECT  116.316 0 116.34 0.192 ;
    END
  END t1[486]
  PIN t1[487]
    DIRECTION OUTPUT ;
    USE SIGNAL ;
    PORT
      LAYER M5 ;
        RECT  116.556 0 116.58 0.192 ;
    END
  END t1[487]
  PIN t1[488]
    DIRECTION OUTPUT ;
    USE SIGNAL ;
    PORT
      LAYER M5 ;
        RECT  116.796 0 116.82 0.192 ;
    END
  END t1[488]
  PIN t1[489]
    DIRECTION OUTPUT ;
    USE SIGNAL ;
    PORT
      LAYER M5 ;
        RECT  117.036 0 117.06 0.192 ;
    END
  END t1[489]
  PIN t1[48]
    DIRECTION OUTPUT ;
    USE SIGNAL ;
    PORT
      LAYER M5 ;
        RECT  13.404 0 13.428 0.192 ;
    END
  END t1[48]
  PIN t1[490]
    DIRECTION OUTPUT ;
    USE SIGNAL ;
    PORT
      LAYER M5 ;
        RECT  117.276 0 117.3 0.192 ;
    END
  END t1[490]
  PIN t1[491]
    DIRECTION OUTPUT ;
    USE SIGNAL ;
    PORT
      LAYER M5 ;
        RECT  117.516 0 117.54 0.192 ;
    END
  END t1[491]
  PIN t1[492]
    DIRECTION OUTPUT ;
    USE SIGNAL ;
    PORT
      LAYER M5 ;
        RECT  117.756 0 117.78 0.192 ;
    END
  END t1[492]
  PIN t1[493]
    DIRECTION OUTPUT ;
    USE SIGNAL ;
    PORT
      LAYER M5 ;
        RECT  117.996 0 118.02 0.192 ;
    END
  END t1[493]
  PIN t1[494]
    DIRECTION OUTPUT ;
    USE SIGNAL ;
    PORT
      LAYER M5 ;
        RECT  118.188 0 118.212 0.192 ;
    END
  END t1[494]
  PIN t1[495]
    DIRECTION OUTPUT ;
    USE SIGNAL ;
    PORT
      LAYER M5 ;
        RECT  118.428 0 118.452 0.192 ;
    END
  END t1[495]
  PIN t1[496]
    DIRECTION OUTPUT ;
    USE SIGNAL ;
    PORT
      LAYER M5 ;
        RECT  118.668 0 118.692 0.192 ;
    END
  END t1[496]
  PIN t1[497]
    DIRECTION OUTPUT ;
    USE SIGNAL ;
    PORT
      LAYER M5 ;
        RECT  118.908 0 118.932 0.192 ;
    END
  END t1[497]
  PIN t1[498]
    DIRECTION OUTPUT ;
    USE SIGNAL ;
    PORT
      LAYER M5 ;
        RECT  119.148 0 119.172 0.192 ;
    END
  END t1[498]
  PIN t1[499]
    DIRECTION OUTPUT ;
    USE SIGNAL ;
    PORT
      LAYER M5 ;
        RECT  119.388 0 119.412 0.192 ;
    END
  END t1[499]
  PIN t1[49]
    DIRECTION OUTPUT ;
    USE SIGNAL ;
    PORT
      LAYER M5 ;
        RECT  13.644 0 13.668 0.192 ;
    END
  END t1[49]
  PIN t1[4]
    DIRECTION OUTPUT ;
    USE SIGNAL ;
    PORT
      LAYER M5 ;
        RECT  3.036 0 3.06 0.192 ;
    END
  END t1[4]
  PIN t1[500]
    DIRECTION OUTPUT ;
    USE SIGNAL ;
    PORT
      LAYER M5 ;
        RECT  119.628 0 119.652 0.192 ;
    END
  END t1[500]
  PIN t1[501]
    DIRECTION OUTPUT ;
    USE SIGNAL ;
    PORT
      LAYER M5 ;
        RECT  119.868 0 119.892 0.192 ;
    END
  END t1[501]
  PIN t1[502]
    DIRECTION OUTPUT ;
    USE SIGNAL ;
    PORT
      LAYER M5 ;
        RECT  120.108 0 120.132 0.192 ;
    END
  END t1[502]
  PIN t1[503]
    DIRECTION OUTPUT ;
    USE SIGNAL ;
    PORT
      LAYER M5 ;
        RECT  120.348 0 120.372 0.192 ;
    END
  END t1[503]
  PIN t1[504]
    DIRECTION OUTPUT ;
    USE SIGNAL ;
    PORT
      LAYER M5 ;
        RECT  120.54 0 120.564 0.192 ;
    END
  END t1[504]
  PIN t1[505]
    DIRECTION OUTPUT ;
    USE SIGNAL ;
    PORT
      LAYER M5 ;
        RECT  120.78 0 120.804 0.192 ;
    END
  END t1[505]
  PIN t1[506]
    DIRECTION OUTPUT ;
    USE SIGNAL ;
    PORT
      LAYER M5 ;
        RECT  121.02 0 121.044 0.192 ;
    END
  END t1[506]
  PIN t1[507]
    DIRECTION OUTPUT ;
    USE SIGNAL ;
    PORT
      LAYER M5 ;
        RECT  121.26 0 121.284 0.192 ;
    END
  END t1[507]
  PIN t1[508]
    DIRECTION OUTPUT ;
    USE SIGNAL ;
    PORT
      LAYER M5 ;
        RECT  121.5 0 121.524 0.192 ;
    END
  END t1[508]
  PIN t1[509]
    DIRECTION OUTPUT ;
    USE SIGNAL ;
    PORT
      LAYER M5 ;
        RECT  121.74 0 121.764 0.192 ;
    END
  END t1[509]
  PIN t1[50]
    DIRECTION OUTPUT ;
    USE SIGNAL ;
    PORT
      LAYER M5 ;
        RECT  13.836 0 13.86 0.192 ;
    END
  END t1[50]
  PIN t1[510]
    DIRECTION OUTPUT ;
    USE SIGNAL ;
    PORT
      LAYER M5 ;
        RECT  121.98 0 122.004 0.192 ;
    END
  END t1[510]
  PIN t1[511]
    DIRECTION OUTPUT ;
    USE SIGNAL ;
    PORT
      LAYER M5 ;
        RECT  122.22 0 122.244 0.192 ;
    END
  END t1[511]
  PIN t1[512]
    DIRECTION OUTPUT ;
    USE SIGNAL ;
    PORT
      LAYER M5 ;
        RECT  122.46 0 122.484 0.192 ;
    END
  END t1[512]
  PIN t1[513]
    DIRECTION OUTPUT ;
    USE SIGNAL ;
    PORT
      LAYER M5 ;
        RECT  122.7 0 122.724 0.192 ;
    END
  END t1[513]
  PIN t1[514]
    DIRECTION OUTPUT ;
    USE SIGNAL ;
    PORT
      LAYER M5 ;
        RECT  122.892 0 122.916 0.192 ;
    END
  END t1[514]
  PIN t1[515]
    DIRECTION OUTPUT ;
    USE SIGNAL ;
    PORT
      LAYER M5 ;
        RECT  123.132 0 123.156 0.192 ;
    END
  END t1[515]
  PIN t1[516]
    DIRECTION OUTPUT ;
    USE SIGNAL ;
    PORT
      LAYER M5 ;
        RECT  123.372 0 123.396 0.192 ;
    END
  END t1[516]
  PIN t1[517]
    DIRECTION OUTPUT ;
    USE SIGNAL ;
    PORT
      LAYER M5 ;
        RECT  123.612 0 123.636 0.192 ;
    END
  END t1[517]
  PIN t1[518]
    DIRECTION OUTPUT ;
    USE SIGNAL ;
    PORT
      LAYER M5 ;
        RECT  123.852 0 123.876 0.192 ;
    END
  END t1[518]
  PIN t1[519]
    DIRECTION OUTPUT ;
    USE SIGNAL ;
    PORT
      LAYER M5 ;
        RECT  124.092 0 124.116 0.192 ;
    END
  END t1[519]
  PIN t1[51]
    DIRECTION OUTPUT ;
    USE SIGNAL ;
    PORT
      LAYER M5 ;
        RECT  14.076 0 14.1 0.192 ;
    END
  END t1[51]
  PIN t1[520]
    DIRECTION OUTPUT ;
    USE SIGNAL ;
    PORT
      LAYER M5 ;
        RECT  124.332 0 124.356 0.192 ;
    END
  END t1[520]
  PIN t1[521]
    DIRECTION OUTPUT ;
    USE SIGNAL ;
    PORT
      LAYER M5 ;
        RECT  124.572 0 124.596 0.192 ;
    END
  END t1[521]
  PIN t1[522]
    DIRECTION OUTPUT ;
    USE SIGNAL ;
    PORT
      LAYER M5 ;
        RECT  124.812 0 124.836 0.192 ;
    END
  END t1[522]
  PIN t1[523]
    DIRECTION OUTPUT ;
    USE SIGNAL ;
    PORT
      LAYER M5 ;
        RECT  125.004 0 125.028 0.192 ;
    END
  END t1[523]
  PIN t1[524]
    DIRECTION OUTPUT ;
    USE SIGNAL ;
    PORT
      LAYER M5 ;
        RECT  125.244 0 125.268 0.192 ;
    END
  END t1[524]
  PIN t1[525]
    DIRECTION OUTPUT ;
    USE SIGNAL ;
    PORT
      LAYER M5 ;
        RECT  125.484 0 125.508 0.192 ;
    END
  END t1[525]
  PIN t1[526]
    DIRECTION OUTPUT ;
    USE SIGNAL ;
    PORT
      LAYER M5 ;
        RECT  125.724 0 125.748 0.192 ;
    END
  END t1[526]
  PIN t1[527]
    DIRECTION OUTPUT ;
    USE SIGNAL ;
    PORT
      LAYER M5 ;
        RECT  125.964 0 125.988 0.192 ;
    END
  END t1[527]
  PIN t1[528]
    DIRECTION OUTPUT ;
    USE SIGNAL ;
    PORT
      LAYER M5 ;
        RECT  126.204 0 126.228 0.192 ;
    END
  END t1[528]
  PIN t1[529]
    DIRECTION OUTPUT ;
    USE SIGNAL ;
    PORT
      LAYER M5 ;
        RECT  126.444 0 126.468 0.192 ;
    END
  END t1[529]
  PIN t1[52]
    DIRECTION OUTPUT ;
    USE SIGNAL ;
    PORT
      LAYER M5 ;
        RECT  14.316 0 14.34 0.192 ;
    END
  END t1[52]
  PIN t1[530]
    DIRECTION OUTPUT ;
    USE SIGNAL ;
    PORT
      LAYER M5 ;
        RECT  126.684 0 126.708 0.192 ;
    END
  END t1[530]
  PIN t1[531]
    DIRECTION OUTPUT ;
    USE SIGNAL ;
    PORT
      LAYER M5 ;
        RECT  126.924 0 126.948 0.192 ;
    END
  END t1[531]
  PIN t1[532]
    DIRECTION OUTPUT ;
    USE SIGNAL ;
    PORT
      LAYER M5 ;
        RECT  127.164 0 127.188 0.192 ;
    END
  END t1[532]
  PIN t1[533]
    DIRECTION OUTPUT ;
    USE SIGNAL ;
    PORT
      LAYER M5 ;
        RECT  127.356 0 127.38 0.192 ;
    END
  END t1[533]
  PIN t1[534]
    DIRECTION OUTPUT ;
    USE SIGNAL ;
    PORT
      LAYER M5 ;
        RECT  127.596 0 127.62 0.192 ;
    END
  END t1[534]
  PIN t1[535]
    DIRECTION OUTPUT ;
    USE SIGNAL ;
    PORT
      LAYER M5 ;
        RECT  127.836 0 127.86 0.192 ;
    END
  END t1[535]
  PIN t1[536]
    DIRECTION OUTPUT ;
    USE SIGNAL ;
    PORT
      LAYER M5 ;
        RECT  128.076 0 128.1 0.192 ;
    END
  END t1[536]
  PIN t1[537]
    DIRECTION OUTPUT ;
    USE SIGNAL ;
    PORT
      LAYER M5 ;
        RECT  128.316 0 128.34 0.192 ;
    END
  END t1[537]
  PIN t1[538]
    DIRECTION OUTPUT ;
    USE SIGNAL ;
    PORT
      LAYER M5 ;
        RECT  128.556 0 128.58 0.192 ;
    END
  END t1[538]
  PIN t1[539]
    DIRECTION OUTPUT ;
    USE SIGNAL ;
    PORT
      LAYER M5 ;
        RECT  128.796 0 128.82 0.192 ;
    END
  END t1[539]
  PIN t1[53]
    DIRECTION OUTPUT ;
    USE SIGNAL ;
    PORT
      LAYER M5 ;
        RECT  14.556 0 14.58 0.192 ;
    END
  END t1[53]
  PIN t1[540]
    DIRECTION OUTPUT ;
    USE SIGNAL ;
    PORT
      LAYER M5 ;
        RECT  129.036 0 129.06 0.192 ;
    END
  END t1[540]
  PIN t1[541]
    DIRECTION OUTPUT ;
    USE SIGNAL ;
    PORT
      LAYER M5 ;
        RECT  129.276 0 129.3 0.192 ;
    END
  END t1[541]
  PIN t1[542]
    DIRECTION OUTPUT ;
    USE SIGNAL ;
    PORT
      LAYER M5 ;
        RECT  129.516 0 129.54 0.192 ;
    END
  END t1[542]
  PIN t1[543]
    DIRECTION OUTPUT ;
    USE SIGNAL ;
    PORT
      LAYER M5 ;
        RECT  129.708 0 129.732 0.192 ;
    END
  END t1[543]
  PIN t1[544]
    DIRECTION OUTPUT ;
    USE SIGNAL ;
    PORT
      LAYER M5 ;
        RECT  129.948 0 129.972 0.192 ;
    END
  END t1[544]
  PIN t1[545]
    DIRECTION OUTPUT ;
    USE SIGNAL ;
    PORT
      LAYER M5 ;
        RECT  130.188 0 130.212 0.192 ;
    END
  END t1[545]
  PIN t1[546]
    DIRECTION OUTPUT ;
    USE SIGNAL ;
    PORT
      LAYER M5 ;
        RECT  130.428 0 130.452 0.192 ;
    END
  END t1[546]
  PIN t1[547]
    DIRECTION OUTPUT ;
    USE SIGNAL ;
    PORT
      LAYER M5 ;
        RECT  130.668 0 130.692 0.192 ;
    END
  END t1[547]
  PIN t1[548]
    DIRECTION OUTPUT ;
    USE SIGNAL ;
    PORT
      LAYER M5 ;
        RECT  130.908 0 130.932 0.192 ;
    END
  END t1[548]
  PIN t1[549]
    DIRECTION OUTPUT ;
    USE SIGNAL ;
    PORT
      LAYER M5 ;
        RECT  131.148 0 131.172 0.192 ;
    END
  END t1[549]
  PIN t1[54]
    DIRECTION OUTPUT ;
    USE SIGNAL ;
    PORT
      LAYER M5 ;
        RECT  14.796 0 14.82 0.192 ;
    END
  END t1[54]
  PIN t1[550]
    DIRECTION OUTPUT ;
    USE SIGNAL ;
    PORT
      LAYER M5 ;
        RECT  131.388 0 131.412 0.192 ;
    END
  END t1[550]
  PIN t1[551]
    DIRECTION OUTPUT ;
    USE SIGNAL ;
    PORT
      LAYER M5 ;
        RECT  131.628 0 131.652 0.192 ;
    END
  END t1[551]
  PIN t1[552]
    DIRECTION OUTPUT ;
    USE SIGNAL ;
    PORT
      LAYER M5 ;
        RECT  131.82 0 131.844 0.192 ;
    END
  END t1[552]
  PIN t1[553]
    DIRECTION OUTPUT ;
    USE SIGNAL ;
    PORT
      LAYER M5 ;
        RECT  132.06 0 132.084 0.192 ;
    END
  END t1[553]
  PIN t1[554]
    DIRECTION OUTPUT ;
    USE SIGNAL ;
    PORT
      LAYER M5 ;
        RECT  132.3 0 132.324 0.192 ;
    END
  END t1[554]
  PIN t1[555]
    DIRECTION OUTPUT ;
    USE SIGNAL ;
    PORT
      LAYER M5 ;
        RECT  132.54 0 132.564 0.192 ;
    END
  END t1[555]
  PIN t1[556]
    DIRECTION OUTPUT ;
    USE SIGNAL ;
    PORT
      LAYER M5 ;
        RECT  132.78 0 132.804 0.192 ;
    END
  END t1[556]
  PIN t1[557]
    DIRECTION OUTPUT ;
    USE SIGNAL ;
    PORT
      LAYER M5 ;
        RECT  133.02 0 133.044 0.192 ;
    END
  END t1[557]
  PIN t1[558]
    DIRECTION OUTPUT ;
    USE SIGNAL ;
    PORT
      LAYER M5 ;
        RECT  133.26 0 133.284 0.192 ;
    END
  END t1[558]
  PIN t1[559]
    DIRECTION OUTPUT ;
    USE SIGNAL ;
    PORT
      LAYER M5 ;
        RECT  133.5 0 133.524 0.192 ;
    END
  END t1[559]
  PIN t1[55]
    DIRECTION OUTPUT ;
    USE SIGNAL ;
    PORT
      LAYER M5 ;
        RECT  15.036 0 15.06 0.192 ;
    END
  END t1[55]
  PIN t1[560]
    DIRECTION OUTPUT ;
    USE SIGNAL ;
    PORT
      LAYER M5 ;
        RECT  133.74 0 133.764 0.192 ;
    END
  END t1[560]
  PIN t1[561]
    DIRECTION OUTPUT ;
    USE SIGNAL ;
    PORT
      LAYER M5 ;
        RECT  133.98 0 134.004 0.192 ;
    END
  END t1[561]
  PIN t1[562]
    DIRECTION OUTPUT ;
    USE SIGNAL ;
    PORT
      LAYER M5 ;
        RECT  134.172 0 134.196 0.192 ;
    END
  END t1[562]
  PIN t1[563]
    DIRECTION OUTPUT ;
    USE SIGNAL ;
    PORT
      LAYER M5 ;
        RECT  134.412 0 134.436 0.192 ;
    END
  END t1[563]
  PIN t1[564]
    DIRECTION OUTPUT ;
    USE SIGNAL ;
    PORT
      LAYER M5 ;
        RECT  134.652 0 134.676 0.192 ;
    END
  END t1[564]
  PIN t1[565]
    DIRECTION OUTPUT ;
    USE SIGNAL ;
    PORT
      LAYER M5 ;
        RECT  134.892 0 134.916 0.192 ;
    END
  END t1[565]
  PIN t1[566]
    DIRECTION OUTPUT ;
    USE SIGNAL ;
    PORT
      LAYER M5 ;
        RECT  135.132 0 135.156 0.192 ;
    END
  END t1[566]
  PIN t1[567]
    DIRECTION OUTPUT ;
    USE SIGNAL ;
    PORT
      LAYER M5 ;
        RECT  135.372 0 135.396 0.192 ;
    END
  END t1[567]
  PIN t1[568]
    DIRECTION OUTPUT ;
    USE SIGNAL ;
    PORT
      LAYER M5 ;
        RECT  135.612 0 135.636 0.192 ;
    END
  END t1[568]
  PIN t1[569]
    DIRECTION OUTPUT ;
    USE SIGNAL ;
    PORT
      LAYER M5 ;
        RECT  135.852 0 135.876 0.192 ;
    END
  END t1[569]
  PIN t1[56]
    DIRECTION OUTPUT ;
    USE SIGNAL ;
    PORT
      LAYER M5 ;
        RECT  15.276 0 15.3 0.192 ;
    END
  END t1[56]
  PIN t1[570]
    DIRECTION OUTPUT ;
    USE SIGNAL ;
    PORT
      LAYER M5 ;
        RECT  136.092 0 136.116 0.192 ;
    END
  END t1[570]
  PIN t1[571]
    DIRECTION OUTPUT ;
    USE SIGNAL ;
    PORT
      LAYER M5 ;
        RECT  136.332 0 136.356 0.192 ;
    END
  END t1[571]
  PIN t1[572]
    DIRECTION OUTPUT ;
    USE SIGNAL ;
    PORT
      LAYER M5 ;
        RECT  136.524 0 136.548 0.192 ;
    END
  END t1[572]
  PIN t1[573]
    DIRECTION OUTPUT ;
    USE SIGNAL ;
    PORT
      LAYER M5 ;
        RECT  136.764 0 136.788 0.192 ;
    END
  END t1[573]
  PIN t1[574]
    DIRECTION OUTPUT ;
    USE SIGNAL ;
    PORT
      LAYER M5 ;
        RECT  137.004 0 137.028 0.192 ;
    END
  END t1[574]
  PIN t1[575]
    DIRECTION OUTPUT ;
    USE SIGNAL ;
    PORT
      LAYER M5 ;
        RECT  137.244 0 137.268 0.192 ;
    END
  END t1[575]
  PIN t1[576]
    DIRECTION OUTPUT ;
    USE SIGNAL ;
    PORT
      LAYER M5 ;
        RECT  137.484 0 137.508 0.192 ;
    END
  END t1[576]
  PIN t1[577]
    DIRECTION OUTPUT ;
    USE SIGNAL ;
    PORT
      LAYER M5 ;
        RECT  137.724 0 137.748 0.192 ;
    END
  END t1[577]
  PIN t1[578]
    DIRECTION OUTPUT ;
    USE SIGNAL ;
    PORT
      LAYER M5 ;
        RECT  137.964 0 137.988 0.192 ;
    END
  END t1[578]
  PIN t1[579]
    DIRECTION OUTPUT ;
    USE SIGNAL ;
    PORT
      LAYER M5 ;
        RECT  138.204 0 138.228 0.192 ;
    END
  END t1[579]
  PIN t1[57]
    DIRECTION OUTPUT ;
    USE SIGNAL ;
    PORT
      LAYER M5 ;
        RECT  15.516 0 15.54 0.192 ;
    END
  END t1[57]
  PIN t1[580]
    DIRECTION OUTPUT ;
    USE SIGNAL ;
    PORT
      LAYER M5 ;
        RECT  138.444 0 138.468 0.192 ;
    END
  END t1[580]
  PIN t1[581]
    DIRECTION OUTPUT ;
    USE SIGNAL ;
    PORT
      LAYER M5 ;
        RECT  138.636 0 138.66 0.192 ;
    END
  END t1[581]
  PIN t1[582]
    DIRECTION OUTPUT ;
    USE SIGNAL ;
    PORT
      LAYER M5 ;
        RECT  138.876 0 138.9 0.192 ;
    END
  END t1[582]
  PIN t1[583]
    DIRECTION OUTPUT ;
    USE SIGNAL ;
    PORT
      LAYER M5 ;
        RECT  139.116 0 139.14 0.192 ;
    END
  END t1[583]
  PIN t1[584]
    DIRECTION OUTPUT ;
    USE SIGNAL ;
    PORT
      LAYER M5 ;
        RECT  139.356 0 139.38 0.192 ;
    END
  END t1[584]
  PIN t1[585]
    DIRECTION OUTPUT ;
    USE SIGNAL ;
    PORT
      LAYER M5 ;
        RECT  139.596 0 139.62 0.192 ;
    END
  END t1[585]
  PIN t1[586]
    DIRECTION OUTPUT ;
    USE SIGNAL ;
    PORT
      LAYER M5 ;
        RECT  139.836 0 139.86 0.192 ;
    END
  END t1[586]
  PIN t1[587]
    DIRECTION OUTPUT ;
    USE SIGNAL ;
    PORT
      LAYER M5 ;
        RECT  140.076 0 140.1 0.192 ;
    END
  END t1[587]
  PIN t1[588]
    DIRECTION OUTPUT ;
    USE SIGNAL ;
    PORT
      LAYER M5 ;
        RECT  140.316 0 140.34 0.192 ;
    END
  END t1[588]
  PIN t1[589]
    DIRECTION OUTPUT ;
    USE SIGNAL ;
    PORT
      LAYER M5 ;
        RECT  140.556 0 140.58 0.192 ;
    END
  END t1[589]
  PIN t1[58]
    DIRECTION OUTPUT ;
    USE SIGNAL ;
    PORT
      LAYER M5 ;
        RECT  15.756 0 15.78 0.192 ;
    END
  END t1[58]
  PIN t1[590]
    DIRECTION OUTPUT ;
    USE SIGNAL ;
    PORT
      LAYER M5 ;
        RECT  140.796 0 140.82 0.192 ;
    END
  END t1[590]
  PIN t1[591]
    DIRECTION OUTPUT ;
    USE SIGNAL ;
    PORT
      LAYER M5 ;
        RECT  140.988 0 141.012 0.192 ;
    END
  END t1[591]
  PIN t1[592]
    DIRECTION OUTPUT ;
    USE SIGNAL ;
    PORT
      LAYER M5 ;
        RECT  141.228 0 141.252 0.192 ;
    END
  END t1[592]
  PIN t1[593]
    DIRECTION OUTPUT ;
    USE SIGNAL ;
    PORT
      LAYER M5 ;
        RECT  141.468 0 141.492 0.192 ;
    END
  END t1[593]
  PIN t1[594]
    DIRECTION OUTPUT ;
    USE SIGNAL ;
    PORT
      LAYER M5 ;
        RECT  141.708 0 141.732 0.192 ;
    END
  END t1[594]
  PIN t1[595]
    DIRECTION OUTPUT ;
    USE SIGNAL ;
    PORT
      LAYER M5 ;
        RECT  141.948 0 141.972 0.192 ;
    END
  END t1[595]
  PIN t1[596]
    DIRECTION OUTPUT ;
    USE SIGNAL ;
    PORT
      LAYER M5 ;
        RECT  142.188 0 142.212 0.192 ;
    END
  END t1[596]
  PIN t1[597]
    DIRECTION OUTPUT ;
    USE SIGNAL ;
    PORT
      LAYER M5 ;
        RECT  142.428 0 142.452 0.192 ;
    END
  END t1[597]
  PIN t1[598]
    DIRECTION OUTPUT ;
    USE SIGNAL ;
    PORT
      LAYER M5 ;
        RECT  142.668 0 142.692 0.192 ;
    END
  END t1[598]
  PIN t1[599]
    DIRECTION OUTPUT ;
    USE SIGNAL ;
    PORT
      LAYER M5 ;
        RECT  142.908 0 142.932 0.192 ;
    END
  END t1[599]
  PIN t1[59]
    DIRECTION OUTPUT ;
    USE SIGNAL ;
    PORT
      LAYER M5 ;
        RECT  15.996 0 16.02 0.192 ;
    END
  END t1[59]
  PIN t1[5]
    DIRECTION OUTPUT ;
    USE SIGNAL ;
    PORT
      LAYER M5 ;
        RECT  3.276 0 3.3 0.192 ;
    END
  END t1[5]
  PIN t1[600]
    DIRECTION OUTPUT ;
    USE SIGNAL ;
    PORT
      LAYER M5 ;
        RECT  143.148 0 143.172 0.192 ;
    END
  END t1[600]
  PIN t1[601]
    DIRECTION OUTPUT ;
    USE SIGNAL ;
    PORT
      LAYER M5 ;
        RECT  143.34 0 143.364 0.192 ;
    END
  END t1[601]
  PIN t1[602]
    DIRECTION OUTPUT ;
    USE SIGNAL ;
    PORT
      LAYER M5 ;
        RECT  143.58 0 143.604 0.192 ;
    END
  END t1[602]
  PIN t1[603]
    DIRECTION OUTPUT ;
    USE SIGNAL ;
    PORT
      LAYER M5 ;
        RECT  143.82 0 143.844 0.192 ;
    END
  END t1[603]
  PIN t1[604]
    DIRECTION OUTPUT ;
    USE SIGNAL ;
    PORT
      LAYER M5 ;
        RECT  144.06 0 144.084 0.192 ;
    END
  END t1[604]
  PIN t1[605]
    DIRECTION OUTPUT ;
    USE SIGNAL ;
    PORT
      LAYER M5 ;
        RECT  144.3 0 144.324 0.192 ;
    END
  END t1[605]
  PIN t1[606]
    DIRECTION OUTPUT ;
    USE SIGNAL ;
    PORT
      LAYER M5 ;
        RECT  144.54 0 144.564 0.192 ;
    END
  END t1[606]
  PIN t1[607]
    DIRECTION OUTPUT ;
    USE SIGNAL ;
    PORT
      LAYER M5 ;
        RECT  144.78 0 144.804 0.192 ;
    END
  END t1[607]
  PIN t1[608]
    DIRECTION OUTPUT ;
    USE SIGNAL ;
    PORT
      LAYER M5 ;
        RECT  145.02 0 145.044 0.192 ;
    END
  END t1[608]
  PIN t1[609]
    DIRECTION OUTPUT ;
    USE SIGNAL ;
    PORT
      LAYER M5 ;
        RECT  145.26 0 145.284 0.192 ;
    END
  END t1[609]
  PIN t1[60]
    DIRECTION OUTPUT ;
    USE SIGNAL ;
    PORT
      LAYER M5 ;
        RECT  16.188 0 16.212 0.192 ;
    END
  END t1[60]
  PIN t1[610]
    DIRECTION OUTPUT ;
    USE SIGNAL ;
    PORT
      LAYER M5 ;
        RECT  145.452 0 145.476 0.192 ;
    END
  END t1[610]
  PIN t1[611]
    DIRECTION OUTPUT ;
    USE SIGNAL ;
    PORT
      LAYER M5 ;
        RECT  145.692 0 145.716 0.192 ;
    END
  END t1[611]
  PIN t1[612]
    DIRECTION OUTPUT ;
    USE SIGNAL ;
    PORT
      LAYER M5 ;
        RECT  145.932 0 145.956 0.192 ;
    END
  END t1[612]
  PIN t1[613]
    DIRECTION OUTPUT ;
    USE SIGNAL ;
    PORT
      LAYER M5 ;
        RECT  146.172 0 146.196 0.192 ;
    END
  END t1[613]
  PIN t1[614]
    DIRECTION OUTPUT ;
    USE SIGNAL ;
    PORT
      LAYER M5 ;
        RECT  146.412 0 146.436 0.192 ;
    END
  END t1[614]
  PIN t1[615]
    DIRECTION OUTPUT ;
    USE SIGNAL ;
    PORT
      LAYER M5 ;
        RECT  146.652 0 146.676 0.192 ;
    END
  END t1[615]
  PIN t1[616]
    DIRECTION OUTPUT ;
    USE SIGNAL ;
    PORT
      LAYER M5 ;
        RECT  146.892 0 146.916 0.192 ;
    END
  END t1[616]
  PIN t1[617]
    DIRECTION OUTPUT ;
    USE SIGNAL ;
    PORT
      LAYER M5 ;
        RECT  147.132 0 147.156 0.192 ;
    END
  END t1[617]
  PIN t1[618]
    DIRECTION OUTPUT ;
    USE SIGNAL ;
    PORT
      LAYER M5 ;
        RECT  147.372 0 147.396 0.192 ;
    END
  END t1[618]
  PIN t1[619]
    DIRECTION OUTPUT ;
    USE SIGNAL ;
    PORT
      LAYER M5 ;
        RECT  147.612 0 147.636 0.192 ;
    END
  END t1[619]
  PIN t1[61]
    DIRECTION OUTPUT ;
    USE SIGNAL ;
    PORT
      LAYER M5 ;
        RECT  16.428 0 16.452 0.192 ;
    END
  END t1[61]
  PIN t1[620]
    DIRECTION OUTPUT ;
    USE SIGNAL ;
    PORT
      LAYER M5 ;
        RECT  147.804 0 147.828 0.192 ;
    END
  END t1[620]
  PIN t1[621]
    DIRECTION OUTPUT ;
    USE SIGNAL ;
    PORT
      LAYER M5 ;
        RECT  148.044 0 148.068 0.192 ;
    END
  END t1[621]
  PIN t1[622]
    DIRECTION OUTPUT ;
    USE SIGNAL ;
    PORT
      LAYER M5 ;
        RECT  148.284 0 148.308 0.192 ;
    END
  END t1[622]
  PIN t1[623]
    DIRECTION OUTPUT ;
    USE SIGNAL ;
    PORT
      LAYER M5 ;
        RECT  148.524 0 148.548 0.192 ;
    END
  END t1[623]
  PIN t1[624]
    DIRECTION OUTPUT ;
    USE SIGNAL ;
    PORT
      LAYER M5 ;
        RECT  148.764 0 148.788 0.192 ;
    END
  END t1[624]
  PIN t1[625]
    DIRECTION OUTPUT ;
    USE SIGNAL ;
    PORT
      LAYER M5 ;
        RECT  149.004 0 149.028 0.192 ;
    END
  END t1[625]
  PIN t1[626]
    DIRECTION OUTPUT ;
    USE SIGNAL ;
    PORT
      LAYER M5 ;
        RECT  149.244 0 149.268 0.192 ;
    END
  END t1[626]
  PIN t1[627]
    DIRECTION OUTPUT ;
    USE SIGNAL ;
    PORT
      LAYER M5 ;
        RECT  149.484 0 149.508 0.192 ;
    END
  END t1[627]
  PIN t1[628]
    DIRECTION OUTPUT ;
    USE SIGNAL ;
    PORT
      LAYER M5 ;
        RECT  149.724 0 149.748 0.192 ;
    END
  END t1[628]
  PIN t1[629]
    DIRECTION OUTPUT ;
    USE SIGNAL ;
    PORT
      LAYER M5 ;
        RECT  149.964 0 149.988 0.192 ;
    END
  END t1[629]
  PIN t1[62]
    DIRECTION OUTPUT ;
    USE SIGNAL ;
    PORT
      LAYER M5 ;
        RECT  16.668 0 16.692 0.192 ;
    END
  END t1[62]
  PIN t1[630]
    DIRECTION OUTPUT ;
    USE SIGNAL ;
    PORT
      LAYER M5 ;
        RECT  150.156 0 150.18 0.192 ;
    END
  END t1[630]
  PIN t1[631]
    DIRECTION OUTPUT ;
    USE SIGNAL ;
    PORT
      LAYER M5 ;
        RECT  150.396 0 150.42 0.192 ;
    END
  END t1[631]
  PIN t1[632]
    DIRECTION OUTPUT ;
    USE SIGNAL ;
    PORT
      LAYER M5 ;
        RECT  150.636 0 150.66 0.192 ;
    END
  END t1[632]
  PIN t1[633]
    DIRECTION OUTPUT ;
    USE SIGNAL ;
    PORT
      LAYER M5 ;
        RECT  150.876 0 150.9 0.192 ;
    END
  END t1[633]
  PIN t1[634]
    DIRECTION OUTPUT ;
    USE SIGNAL ;
    PORT
      LAYER M5 ;
        RECT  151.116 0 151.14 0.192 ;
    END
  END t1[634]
  PIN t1[635]
    DIRECTION OUTPUT ;
    USE SIGNAL ;
    PORT
      LAYER M5 ;
        RECT  151.356 0 151.38 0.192 ;
    END
  END t1[635]
  PIN t1[636]
    DIRECTION OUTPUT ;
    USE SIGNAL ;
    PORT
      LAYER M5 ;
        RECT  151.596 0 151.62 0.192 ;
    END
  END t1[636]
  PIN t1[637]
    DIRECTION OUTPUT ;
    USE SIGNAL ;
    PORT
      LAYER M5 ;
        RECT  151.836 0 151.86 0.192 ;
    END
  END t1[637]
  PIN t1[638]
    DIRECTION OUTPUT ;
    USE SIGNAL ;
    PORT
      LAYER M5 ;
        RECT  152.076 0 152.1 0.192 ;
    END
  END t1[638]
  PIN t1[639]
    DIRECTION OUTPUT ;
    USE SIGNAL ;
    PORT
      LAYER M5 ;
        RECT  152.268 0 152.292 0.192 ;
    END
  END t1[639]
  PIN t1[63]
    DIRECTION OUTPUT ;
    USE SIGNAL ;
    PORT
      LAYER M5 ;
        RECT  16.908 0 16.932 0.192 ;
    END
  END t1[63]
  PIN t1[640]
    DIRECTION OUTPUT ;
    USE SIGNAL ;
    PORT
      LAYER M5 ;
        RECT  152.508 0 152.532 0.192 ;
    END
  END t1[640]
  PIN t1[641]
    DIRECTION OUTPUT ;
    USE SIGNAL ;
    PORT
      LAYER M5 ;
        RECT  152.748 0 152.772 0.192 ;
    END
  END t1[641]
  PIN t1[642]
    DIRECTION OUTPUT ;
    USE SIGNAL ;
    PORT
      LAYER M5 ;
        RECT  152.988 0 153.012 0.192 ;
    END
  END t1[642]
  PIN t1[643]
    DIRECTION OUTPUT ;
    USE SIGNAL ;
    PORT
      LAYER M5 ;
        RECT  153.228 0 153.252 0.192 ;
    END
  END t1[643]
  PIN t1[644]
    DIRECTION OUTPUT ;
    USE SIGNAL ;
    PORT
      LAYER M5 ;
        RECT  153.468 0 153.492 0.192 ;
    END
  END t1[644]
  PIN t1[645]
    DIRECTION OUTPUT ;
    USE SIGNAL ;
    PORT
      LAYER M5 ;
        RECT  153.708 0 153.732 0.192 ;
    END
  END t1[645]
  PIN t1[646]
    DIRECTION OUTPUT ;
    USE SIGNAL ;
    PORT
      LAYER M5 ;
        RECT  153.948 0 153.972 0.192 ;
    END
  END t1[646]
  PIN t1[647]
    DIRECTION OUTPUT ;
    USE SIGNAL ;
    PORT
      LAYER M5 ;
        RECT  154.188 0 154.212 0.192 ;
    END
  END t1[647]
  PIN t1[648]
    DIRECTION OUTPUT ;
    USE SIGNAL ;
    PORT
      LAYER M5 ;
        RECT  154.428 0 154.452 0.192 ;
    END
  END t1[648]
  PIN t1[649]
    DIRECTION OUTPUT ;
    USE SIGNAL ;
    PORT
      LAYER M5 ;
        RECT  154.62 0 154.644 0.192 ;
    END
  END t1[649]
  PIN t1[64]
    DIRECTION OUTPUT ;
    USE SIGNAL ;
    PORT
      LAYER M5 ;
        RECT  17.148 0 17.172 0.192 ;
    END
  END t1[64]
  PIN t1[650]
    DIRECTION OUTPUT ;
    USE SIGNAL ;
    PORT
      LAYER M5 ;
        RECT  154.86 0 154.884 0.192 ;
    END
  END t1[650]
  PIN t1[651]
    DIRECTION OUTPUT ;
    USE SIGNAL ;
    PORT
      LAYER M5 ;
        RECT  155.1 0 155.124 0.192 ;
    END
  END t1[651]
  PIN t1[652]
    DIRECTION OUTPUT ;
    USE SIGNAL ;
    PORT
      LAYER M5 ;
        RECT  155.34 0 155.364 0.192 ;
    END
  END t1[652]
  PIN t1[653]
    DIRECTION OUTPUT ;
    USE SIGNAL ;
    PORT
      LAYER M5 ;
        RECT  155.58 0 155.604 0.192 ;
    END
  END t1[653]
  PIN t1[654]
    DIRECTION OUTPUT ;
    USE SIGNAL ;
    PORT
      LAYER M5 ;
        RECT  155.82 0 155.844 0.192 ;
    END
  END t1[654]
  PIN t1[655]
    DIRECTION OUTPUT ;
    USE SIGNAL ;
    PORT
      LAYER M5 ;
        RECT  156.06 0 156.084 0.192 ;
    END
  END t1[655]
  PIN t1[656]
    DIRECTION OUTPUT ;
    USE SIGNAL ;
    PORT
      LAYER M5 ;
        RECT  156.3 0 156.324 0.192 ;
    END
  END t1[656]
  PIN t1[657]
    DIRECTION OUTPUT ;
    USE SIGNAL ;
    PORT
      LAYER M5 ;
        RECT  156.54 0 156.564 0.192 ;
    END
  END t1[657]
  PIN t1[658]
    DIRECTION OUTPUT ;
    USE SIGNAL ;
    PORT
      LAYER M5 ;
        RECT  156.78 0 156.804 0.192 ;
    END
  END t1[658]
  PIN t1[659]
    DIRECTION OUTPUT ;
    USE SIGNAL ;
    PORT
      LAYER M5 ;
        RECT  156.972 0 156.996 0.192 ;
    END
  END t1[659]
  PIN t1[65]
    DIRECTION OUTPUT ;
    USE SIGNAL ;
    PORT
      LAYER M5 ;
        RECT  17.388 0 17.412 0.192 ;
    END
  END t1[65]
  PIN t1[660]
    DIRECTION OUTPUT ;
    USE SIGNAL ;
    PORT
      LAYER M5 ;
        RECT  157.212 0 157.236 0.192 ;
    END
  END t1[660]
  PIN t1[661]
    DIRECTION OUTPUT ;
    USE SIGNAL ;
    PORT
      LAYER M5 ;
        RECT  157.452 0 157.476 0.192 ;
    END
  END t1[661]
  PIN t1[662]
    DIRECTION OUTPUT ;
    USE SIGNAL ;
    PORT
      LAYER M5 ;
        RECT  157.692 0 157.716 0.192 ;
    END
  END t1[662]
  PIN t1[663]
    DIRECTION OUTPUT ;
    USE SIGNAL ;
    PORT
      LAYER M5 ;
        RECT  157.932 0 157.956 0.192 ;
    END
  END t1[663]
  PIN t1[664]
    DIRECTION OUTPUT ;
    USE SIGNAL ;
    PORT
      LAYER M5 ;
        RECT  158.172 0 158.196 0.192 ;
    END
  END t1[664]
  PIN t1[665]
    DIRECTION OUTPUT ;
    USE SIGNAL ;
    PORT
      LAYER M5 ;
        RECT  158.412 0 158.436 0.192 ;
    END
  END t1[665]
  PIN t1[666]
    DIRECTION OUTPUT ;
    USE SIGNAL ;
    PORT
      LAYER M5 ;
        RECT  158.652 0 158.676 0.192 ;
    END
  END t1[666]
  PIN t1[667]
    DIRECTION OUTPUT ;
    USE SIGNAL ;
    PORT
      LAYER M5 ;
        RECT  158.892 0 158.916 0.192 ;
    END
  END t1[667]
  PIN t1[668]
    DIRECTION OUTPUT ;
    USE SIGNAL ;
    PORT
      LAYER M5 ;
        RECT  159.084 0 159.108 0.192 ;
    END
  END t1[668]
  PIN t1[669]
    DIRECTION OUTPUT ;
    USE SIGNAL ;
    PORT
      LAYER M5 ;
        RECT  159.324 0 159.348 0.192 ;
    END
  END t1[669]
  PIN t1[66]
    DIRECTION OUTPUT ;
    USE SIGNAL ;
    PORT
      LAYER M5 ;
        RECT  17.628 0 17.652 0.192 ;
    END
  END t1[66]
  PIN t1[670]
    DIRECTION OUTPUT ;
    USE SIGNAL ;
    PORT
      LAYER M5 ;
        RECT  159.564 0 159.588 0.192 ;
    END
  END t1[670]
  PIN t1[671]
    DIRECTION OUTPUT ;
    USE SIGNAL ;
    PORT
      LAYER M5 ;
        RECT  159.804 0 159.828 0.192 ;
    END
  END t1[671]
  PIN t1[672]
    DIRECTION OUTPUT ;
    USE SIGNAL ;
    PORT
      LAYER M5 ;
        RECT  160.044 0 160.068 0.192 ;
    END
  END t1[672]
  PIN t1[673]
    DIRECTION OUTPUT ;
    USE SIGNAL ;
    PORT
      LAYER M5 ;
        RECT  160.284 0 160.308 0.192 ;
    END
  END t1[673]
  PIN t1[674]
    DIRECTION OUTPUT ;
    USE SIGNAL ;
    PORT
      LAYER M5 ;
        RECT  160.524 0 160.548 0.192 ;
    END
  END t1[674]
  PIN t1[675]
    DIRECTION OUTPUT ;
    USE SIGNAL ;
    PORT
      LAYER M5 ;
        RECT  160.764 0 160.788 0.192 ;
    END
  END t1[675]
  PIN t1[676]
    DIRECTION OUTPUT ;
    USE SIGNAL ;
    PORT
      LAYER M5 ;
        RECT  161.004 0 161.028 0.192 ;
    END
  END t1[676]
  PIN t1[677]
    DIRECTION OUTPUT ;
    USE SIGNAL ;
    PORT
      LAYER M5 ;
        RECT  161.244 0 161.268 0.192 ;
    END
  END t1[677]
  PIN t1[678]
    DIRECTION OUTPUT ;
    USE SIGNAL ;
    PORT
      LAYER M5 ;
        RECT  161.436 0 161.46 0.192 ;
    END
  END t1[678]
  PIN t1[679]
    DIRECTION OUTPUT ;
    USE SIGNAL ;
    PORT
      LAYER M5 ;
        RECT  161.676 0 161.7 0.192 ;
    END
  END t1[679]
  PIN t1[67]
    DIRECTION OUTPUT ;
    USE SIGNAL ;
    PORT
      LAYER M5 ;
        RECT  17.868 0 17.892 0.192 ;
    END
  END t1[67]
  PIN t1[680]
    DIRECTION OUTPUT ;
    USE SIGNAL ;
    PORT
      LAYER M5 ;
        RECT  161.916 0 161.94 0.192 ;
    END
  END t1[680]
  PIN t1[681]
    DIRECTION OUTPUT ;
    USE SIGNAL ;
    PORT
      LAYER M5 ;
        RECT  162.156 0 162.18 0.192 ;
    END
  END t1[681]
  PIN t1[682]
    DIRECTION OUTPUT ;
    USE SIGNAL ;
    PORT
      LAYER M5 ;
        RECT  162.396 0 162.42 0.192 ;
    END
  END t1[682]
  PIN t1[683]
    DIRECTION OUTPUT ;
    USE SIGNAL ;
    PORT
      LAYER M5 ;
        RECT  162.636 0 162.66 0.192 ;
    END
  END t1[683]
  PIN t1[684]
    DIRECTION OUTPUT ;
    USE SIGNAL ;
    PORT
      LAYER M5 ;
        RECT  162.876 0 162.9 0.192 ;
    END
  END t1[684]
  PIN t1[685]
    DIRECTION OUTPUT ;
    USE SIGNAL ;
    PORT
      LAYER M5 ;
        RECT  163.116 0 163.14 0.192 ;
    END
  END t1[685]
  PIN t1[686]
    DIRECTION OUTPUT ;
    USE SIGNAL ;
    PORT
      LAYER M5 ;
        RECT  163.356 0 163.38 0.192 ;
    END
  END t1[686]
  PIN t1[687]
    DIRECTION OUTPUT ;
    USE SIGNAL ;
    PORT
      LAYER M5 ;
        RECT  163.596 0 163.62 0.192 ;
    END
  END t1[687]
  PIN t1[688]
    DIRECTION OUTPUT ;
    USE SIGNAL ;
    PORT
      LAYER M5 ;
        RECT  163.788 0 163.812 0.192 ;
    END
  END t1[688]
  PIN t1[689]
    DIRECTION OUTPUT ;
    USE SIGNAL ;
    PORT
      LAYER M5 ;
        RECT  164.028 0 164.052 0.192 ;
    END
  END t1[689]
  PIN t1[68]
    DIRECTION OUTPUT ;
    USE SIGNAL ;
    PORT
      LAYER M5 ;
        RECT  18.108 0 18.132 0.192 ;
    END
  END t1[68]
  PIN t1[690]
    DIRECTION OUTPUT ;
    USE SIGNAL ;
    PORT
      LAYER M5 ;
        RECT  164.268 0 164.292 0.192 ;
    END
  END t1[690]
  PIN t1[691]
    DIRECTION OUTPUT ;
    USE SIGNAL ;
    PORT
      LAYER M5 ;
        RECT  164.508 0 164.532 0.192 ;
    END
  END t1[691]
  PIN t1[692]
    DIRECTION OUTPUT ;
    USE SIGNAL ;
    PORT
      LAYER M5 ;
        RECT  164.748 0 164.772 0.192 ;
    END
  END t1[692]
  PIN t1[693]
    DIRECTION OUTPUT ;
    USE SIGNAL ;
    PORT
      LAYER M5 ;
        RECT  164.988 0 165.012 0.192 ;
    END
  END t1[693]
  PIN t1[694]
    DIRECTION OUTPUT ;
    USE SIGNAL ;
    PORT
      LAYER M5 ;
        RECT  165.228 0 165.252 0.192 ;
    END
  END t1[694]
  PIN t1[695]
    DIRECTION OUTPUT ;
    USE SIGNAL ;
    PORT
      LAYER M5 ;
        RECT  165.468 0 165.492 0.192 ;
    END
  END t1[695]
  PIN t1[696]
    DIRECTION OUTPUT ;
    USE SIGNAL ;
    PORT
      LAYER M5 ;
        RECT  165.708 0 165.732 0.192 ;
    END
  END t1[696]
  PIN t1[697]
    DIRECTION OUTPUT ;
    USE SIGNAL ;
    PORT
      LAYER M5 ;
        RECT  165.9 0 165.924 0.192 ;
    END
  END t1[697]
  PIN t1[698]
    DIRECTION OUTPUT ;
    USE SIGNAL ;
    PORT
      LAYER M5 ;
        RECT  166.14 0 166.164 0.192 ;
    END
  END t1[698]
  PIN t1[699]
    DIRECTION OUTPUT ;
    USE SIGNAL ;
    PORT
      LAYER M5 ;
        RECT  166.38 0 166.404 0.192 ;
    END
  END t1[699]
  PIN t1[69]
    DIRECTION OUTPUT ;
    USE SIGNAL ;
    PORT
      LAYER M5 ;
        RECT  18.3 0 18.324 0.192 ;
    END
  END t1[69]
  PIN t1[6]
    DIRECTION OUTPUT ;
    USE SIGNAL ;
    PORT
      LAYER M5 ;
        RECT  3.516 0 3.54 0.192 ;
    END
  END t1[6]
  PIN t1[700]
    DIRECTION OUTPUT ;
    USE SIGNAL ;
    PORT
      LAYER M5 ;
        RECT  166.62 0 166.644 0.192 ;
    END
  END t1[700]
  PIN t1[701]
    DIRECTION OUTPUT ;
    USE SIGNAL ;
    PORT
      LAYER M5 ;
        RECT  166.86 0 166.884 0.192 ;
    END
  END t1[701]
  PIN t1[702]
    DIRECTION OUTPUT ;
    USE SIGNAL ;
    PORT
      LAYER M5 ;
        RECT  167.1 0 167.124 0.192 ;
    END
  END t1[702]
  PIN t1[703]
    DIRECTION OUTPUT ;
    USE SIGNAL ;
    PORT
      LAYER M5 ;
        RECT  167.34 0 167.364 0.192 ;
    END
  END t1[703]
  PIN t1[704]
    DIRECTION OUTPUT ;
    USE SIGNAL ;
    PORT
      LAYER M5 ;
        RECT  167.58 0 167.604 0.192 ;
    END
  END t1[704]
  PIN t1[705]
    DIRECTION OUTPUT ;
    USE SIGNAL ;
    PORT
      LAYER M5 ;
        RECT  167.82 0 167.844 0.192 ;
    END
  END t1[705]
  PIN t1[706]
    DIRECTION OUTPUT ;
    USE SIGNAL ;
    PORT
      LAYER M5 ;
        RECT  168.06 0 168.084 0.192 ;
    END
  END t1[706]
  PIN t1[707]
    DIRECTION OUTPUT ;
    USE SIGNAL ;
    PORT
      LAYER M5 ;
        RECT  168.252 0 168.276 0.192 ;
    END
  END t1[707]
  PIN t1[708]
    DIRECTION OUTPUT ;
    USE SIGNAL ;
    PORT
      LAYER M5 ;
        RECT  168.492 0 168.516 0.192 ;
    END
  END t1[708]
  PIN t1[709]
    DIRECTION OUTPUT ;
    USE SIGNAL ;
    PORT
      LAYER M5 ;
        RECT  168.732 0 168.756 0.192 ;
    END
  END t1[709]
  PIN t1[70]
    DIRECTION OUTPUT ;
    USE SIGNAL ;
    PORT
      LAYER M5 ;
        RECT  18.54 0 18.564 0.192 ;
    END
  END t1[70]
  PIN t1[710]
    DIRECTION OUTPUT ;
    USE SIGNAL ;
    PORT
      LAYER M5 ;
        RECT  168.972 0 168.996 0.192 ;
    END
  END t1[710]
  PIN t1[711]
    DIRECTION OUTPUT ;
    USE SIGNAL ;
    PORT
      LAYER M5 ;
        RECT  169.212 0 169.236 0.192 ;
    END
  END t1[711]
  PIN t1[712]
    DIRECTION OUTPUT ;
    USE SIGNAL ;
    PORT
      LAYER M5 ;
        RECT  169.452 0 169.476 0.192 ;
    END
  END t1[712]
  PIN t1[713]
    DIRECTION OUTPUT ;
    USE SIGNAL ;
    PORT
      LAYER M5 ;
        RECT  169.692 0 169.716 0.192 ;
    END
  END t1[713]
  PIN t1[714]
    DIRECTION OUTPUT ;
    USE SIGNAL ;
    PORT
      LAYER M5 ;
        RECT  169.932 0 169.956 0.192 ;
    END
  END t1[714]
  PIN t1[715]
    DIRECTION OUTPUT ;
    USE SIGNAL ;
    PORT
      LAYER M5 ;
        RECT  170.172 0 170.196 0.192 ;
    END
  END t1[715]
  PIN t1[716]
    DIRECTION OUTPUT ;
    USE SIGNAL ;
    PORT
      LAYER M5 ;
        RECT  170.412 0 170.436 0.192 ;
    END
  END t1[716]
  PIN t1[717]
    DIRECTION OUTPUT ;
    USE SIGNAL ;
    PORT
      LAYER M5 ;
        RECT  170.604 0 170.628 0.192 ;
    END
  END t1[717]
  PIN t1[718]
    DIRECTION OUTPUT ;
    USE SIGNAL ;
    PORT
      LAYER M5 ;
        RECT  170.844 0 170.868 0.192 ;
    END
  END t1[718]
  PIN t1[719]
    DIRECTION OUTPUT ;
    USE SIGNAL ;
    PORT
      LAYER M5 ;
        RECT  171.084 0 171.108 0.192 ;
    END
  END t1[719]
  PIN t1[71]
    DIRECTION OUTPUT ;
    USE SIGNAL ;
    PORT
      LAYER M5 ;
        RECT  18.78 0 18.804 0.192 ;
    END
  END t1[71]
  PIN t1[720]
    DIRECTION OUTPUT ;
    USE SIGNAL ;
    PORT
      LAYER M5 ;
        RECT  171.324 0 171.348 0.192 ;
    END
  END t1[720]
  PIN t1[721]
    DIRECTION OUTPUT ;
    USE SIGNAL ;
    PORT
      LAYER M5 ;
        RECT  171.564 0 171.588 0.192 ;
    END
  END t1[721]
  PIN t1[722]
    DIRECTION OUTPUT ;
    USE SIGNAL ;
    PORT
      LAYER M5 ;
        RECT  171.804 0 171.828 0.192 ;
    END
  END t1[722]
  PIN t1[723]
    DIRECTION OUTPUT ;
    USE SIGNAL ;
    PORT
      LAYER M5 ;
        RECT  172.044 0 172.068 0.192 ;
    END
  END t1[723]
  PIN t1[724]
    DIRECTION OUTPUT ;
    USE SIGNAL ;
    PORT
      LAYER M5 ;
        RECT  172.284 0 172.308 0.192 ;
    END
  END t1[724]
  PIN t1[725]
    DIRECTION OUTPUT ;
    USE SIGNAL ;
    PORT
      LAYER M5 ;
        RECT  172.524 0 172.548 0.192 ;
    END
  END t1[725]
  PIN t1[726]
    DIRECTION OUTPUT ;
    USE SIGNAL ;
    PORT
      LAYER M5 ;
        RECT  172.716 0 172.74 0.192 ;
    END
  END t1[726]
  PIN t1[727]
    DIRECTION OUTPUT ;
    USE SIGNAL ;
    PORT
      LAYER M5 ;
        RECT  172.956 0 172.98 0.192 ;
    END
  END t1[727]
  PIN t1[728]
    DIRECTION OUTPUT ;
    USE SIGNAL ;
    PORT
      LAYER M5 ;
        RECT  173.196 0 173.22 0.192 ;
    END
  END t1[728]
  PIN t1[729]
    DIRECTION OUTPUT ;
    USE SIGNAL ;
    PORT
      LAYER M5 ;
        RECT  173.436 0 173.46 0.192 ;
    END
  END t1[729]
  PIN t1[72]
    DIRECTION OUTPUT ;
    USE SIGNAL ;
    PORT
      LAYER M5 ;
        RECT  19.02 0 19.044 0.192 ;
    END
  END t1[72]
  PIN t1[730]
    DIRECTION OUTPUT ;
    USE SIGNAL ;
    PORT
      LAYER M5 ;
        RECT  173.676 0 173.7 0.192 ;
    END
  END t1[730]
  PIN t1[731]
    DIRECTION OUTPUT ;
    USE SIGNAL ;
    PORT
      LAYER M5 ;
        RECT  173.916 0 173.94 0.192 ;
    END
  END t1[731]
  PIN t1[732]
    DIRECTION OUTPUT ;
    USE SIGNAL ;
    PORT
      LAYER M5 ;
        RECT  174.156 0 174.18 0.192 ;
    END
  END t1[732]
  PIN t1[733]
    DIRECTION OUTPUT ;
    USE SIGNAL ;
    PORT
      LAYER M5 ;
        RECT  174.396 0 174.42 0.192 ;
    END
  END t1[733]
  PIN t1[734]
    DIRECTION OUTPUT ;
    USE SIGNAL ;
    PORT
      LAYER M5 ;
        RECT  174.636 0 174.66 0.192 ;
    END
  END t1[734]
  PIN t1[735]
    DIRECTION OUTPUT ;
    USE SIGNAL ;
    PORT
      LAYER M5 ;
        RECT  174.876 0 174.9 0.192 ;
    END
  END t1[735]
  PIN t1[736]
    DIRECTION OUTPUT ;
    USE SIGNAL ;
    PORT
      LAYER M5 ;
        RECT  175.068 0 175.092 0.192 ;
    END
  END t1[736]
  PIN t1[737]
    DIRECTION OUTPUT ;
    USE SIGNAL ;
    PORT
      LAYER M5 ;
        RECT  175.308 0 175.332 0.192 ;
    END
  END t1[737]
  PIN t1[738]
    DIRECTION OUTPUT ;
    USE SIGNAL ;
    PORT
      LAYER M5 ;
        RECT  175.548 0 175.572 0.192 ;
    END
  END t1[738]
  PIN t1[739]
    DIRECTION OUTPUT ;
    USE SIGNAL ;
    PORT
      LAYER M5 ;
        RECT  175.788 0 175.812 0.192 ;
    END
  END t1[739]
  PIN t1[73]
    DIRECTION OUTPUT ;
    USE SIGNAL ;
    PORT
      LAYER M5 ;
        RECT  19.26 0 19.284 0.192 ;
    END
  END t1[73]
  PIN t1[740]
    DIRECTION OUTPUT ;
    USE SIGNAL ;
    PORT
      LAYER M5 ;
        RECT  176.028 0 176.052 0.192 ;
    END
  END t1[740]
  PIN t1[741]
    DIRECTION OUTPUT ;
    USE SIGNAL ;
    PORT
      LAYER M5 ;
        RECT  176.268 0 176.292 0.192 ;
    END
  END t1[741]
  PIN t1[742]
    DIRECTION OUTPUT ;
    USE SIGNAL ;
    PORT
      LAYER M5 ;
        RECT  176.508 0 176.532 0.192 ;
    END
  END t1[742]
  PIN t1[743]
    DIRECTION OUTPUT ;
    USE SIGNAL ;
    PORT
      LAYER M5 ;
        RECT  176.748 0 176.772 0.192 ;
    END
  END t1[743]
  PIN t1[744]
    DIRECTION OUTPUT ;
    USE SIGNAL ;
    PORT
      LAYER M5 ;
        RECT  176.988 0 177.012 0.192 ;
    END
  END t1[744]
  PIN t1[745]
    DIRECTION OUTPUT ;
    USE SIGNAL ;
    PORT
      LAYER M5 ;
        RECT  177.228 0 177.252 0.192 ;
    END
  END t1[745]
  PIN t1[746]
    DIRECTION OUTPUT ;
    USE SIGNAL ;
    PORT
      LAYER M5 ;
        RECT  177.42 0 177.444 0.192 ;
    END
  END t1[746]
  PIN t1[747]
    DIRECTION OUTPUT ;
    USE SIGNAL ;
    PORT
      LAYER M5 ;
        RECT  177.66 0 177.684 0.192 ;
    END
  END t1[747]
  PIN t1[748]
    DIRECTION OUTPUT ;
    USE SIGNAL ;
    PORT
      LAYER M5 ;
        RECT  177.9 0 177.924 0.192 ;
    END
  END t1[748]
  PIN t1[749]
    DIRECTION OUTPUT ;
    USE SIGNAL ;
    PORT
      LAYER M5 ;
        RECT  178.14 0 178.164 0.192 ;
    END
  END t1[749]
  PIN t1[74]
    DIRECTION OUTPUT ;
    USE SIGNAL ;
    PORT
      LAYER M5 ;
        RECT  19.5 0 19.524 0.192 ;
    END
  END t1[74]
  PIN t1[750]
    DIRECTION OUTPUT ;
    USE SIGNAL ;
    PORT
      LAYER M5 ;
        RECT  178.38 0 178.404 0.192 ;
    END
  END t1[750]
  PIN t1[751]
    DIRECTION OUTPUT ;
    USE SIGNAL ;
    PORT
      LAYER M5 ;
        RECT  178.62 0 178.644 0.192 ;
    END
  END t1[751]
  PIN t1[752]
    DIRECTION OUTPUT ;
    USE SIGNAL ;
    PORT
      LAYER M5 ;
        RECT  178.86 0 178.884 0.192 ;
    END
  END t1[752]
  PIN t1[753]
    DIRECTION OUTPUT ;
    USE SIGNAL ;
    PORT
      LAYER M5 ;
        RECT  179.1 0 179.124 0.192 ;
    END
  END t1[753]
  PIN t1[754]
    DIRECTION OUTPUT ;
    USE SIGNAL ;
    PORT
      LAYER M5 ;
        RECT  179.34 0 179.364 0.192 ;
    END
  END t1[754]
  PIN t1[755]
    DIRECTION OUTPUT ;
    USE SIGNAL ;
    PORT
      LAYER M5 ;
        RECT  179.532 0 179.556 0.192 ;
    END
  END t1[755]
  PIN t1[756]
    DIRECTION OUTPUT ;
    USE SIGNAL ;
    PORT
      LAYER M5 ;
        RECT  179.772 0 179.796 0.192 ;
    END
  END t1[756]
  PIN t1[757]
    DIRECTION OUTPUT ;
    USE SIGNAL ;
    PORT
      LAYER M5 ;
        RECT  180.012 0 180.036 0.192 ;
    END
  END t1[757]
  PIN t1[758]
    DIRECTION OUTPUT ;
    USE SIGNAL ;
    PORT
      LAYER M5 ;
        RECT  180.252 0 180.276 0.192 ;
    END
  END t1[758]
  PIN t1[759]
    DIRECTION OUTPUT ;
    USE SIGNAL ;
    PORT
      LAYER M5 ;
        RECT  180.492 0 180.516 0.192 ;
    END
  END t1[759]
  PIN t1[75]
    DIRECTION OUTPUT ;
    USE SIGNAL ;
    PORT
      LAYER M5 ;
        RECT  19.74 0 19.764 0.192 ;
    END
  END t1[75]
  PIN t1[760]
    DIRECTION OUTPUT ;
    USE SIGNAL ;
    PORT
      LAYER M5 ;
        RECT  180.732 0 180.756 0.192 ;
    END
  END t1[760]
  PIN t1[761]
    DIRECTION OUTPUT ;
    USE SIGNAL ;
    PORT
      LAYER M5 ;
        RECT  180.972 0 180.996 0.192 ;
    END
  END t1[761]
  PIN t1[762]
    DIRECTION OUTPUT ;
    USE SIGNAL ;
    PORT
      LAYER M5 ;
        RECT  181.212 0 181.236 0.192 ;
    END
  END t1[762]
  PIN t1[763]
    DIRECTION OUTPUT ;
    USE SIGNAL ;
    PORT
      LAYER M5 ;
        RECT  181.452 0 181.476 0.192 ;
    END
  END t1[763]
  PIN t1[764]
    DIRECTION OUTPUT ;
    USE SIGNAL ;
    PORT
      LAYER M5 ;
        RECT  181.692 0 181.716 0.192 ;
    END
  END t1[764]
  PIN t1[765]
    DIRECTION OUTPUT ;
    USE SIGNAL ;
    PORT
      LAYER M5 ;
        RECT  181.884 0 181.908 0.192 ;
    END
  END t1[765]
  PIN t1[766]
    DIRECTION OUTPUT ;
    USE SIGNAL ;
    PORT
      LAYER M5 ;
        RECT  182.124 0 182.148 0.192 ;
    END
  END t1[766]
  PIN t1[767]
    DIRECTION OUTPUT ;
    USE SIGNAL ;
    PORT
      LAYER M5 ;
        RECT  182.364 0 182.388 0.192 ;
    END
  END t1[767]
  PIN t1[768]
    DIRECTION OUTPUT ;
    USE SIGNAL ;
    PORT
      LAYER M5 ;
        RECT  182.604 0 182.628 0.192 ;
    END
  END t1[768]
  PIN t1[769]
    DIRECTION OUTPUT ;
    USE SIGNAL ;
    PORT
      LAYER M5 ;
        RECT  182.844 0 182.868 0.192 ;
    END
  END t1[769]
  PIN t1[76]
    DIRECTION OUTPUT ;
    USE SIGNAL ;
    PORT
      LAYER M5 ;
        RECT  19.98 0 20.004 0.192 ;
    END
  END t1[76]
  PIN t1[770]
    DIRECTION OUTPUT ;
    USE SIGNAL ;
    PORT
      LAYER M5 ;
        RECT  183.084 0 183.108 0.192 ;
    END
  END t1[770]
  PIN t1[771]
    DIRECTION OUTPUT ;
    USE SIGNAL ;
    PORT
      LAYER M5 ;
        RECT  183.324 0 183.348 0.192 ;
    END
  END t1[771]
  PIN t1[772]
    DIRECTION OUTPUT ;
    USE SIGNAL ;
    PORT
      LAYER M5 ;
        RECT  183.564 0 183.588 0.192 ;
    END
  END t1[772]
  PIN t1[773]
    DIRECTION OUTPUT ;
    USE SIGNAL ;
    PORT
      LAYER M5 ;
        RECT  183.804 0 183.828 0.192 ;
    END
  END t1[773]
  PIN t1[774]
    DIRECTION OUTPUT ;
    USE SIGNAL ;
    PORT
      LAYER M5 ;
        RECT  184.044 0 184.068 0.192 ;
    END
  END t1[774]
  PIN t1[775]
    DIRECTION OUTPUT ;
    USE SIGNAL ;
    PORT
      LAYER M5 ;
        RECT  184.236 0 184.26 0.192 ;
    END
  END t1[775]
  PIN t1[776]
    DIRECTION OUTPUT ;
    USE SIGNAL ;
    PORT
      LAYER M5 ;
        RECT  184.476 0 184.5 0.192 ;
    END
  END t1[776]
  PIN t1[777]
    DIRECTION OUTPUT ;
    USE SIGNAL ;
    PORT
      LAYER M5 ;
        RECT  184.716 0 184.74 0.192 ;
    END
  END t1[777]
  PIN t1[778]
    DIRECTION OUTPUT ;
    USE SIGNAL ;
    PORT
      LAYER M5 ;
        RECT  184.956 0 184.98 0.192 ;
    END
  END t1[778]
  PIN t1[779]
    DIRECTION OUTPUT ;
    USE SIGNAL ;
    PORT
      LAYER M5 ;
        RECT  185.196 0 185.22 0.192 ;
    END
  END t1[779]
  PIN t1[77]
    DIRECTION OUTPUT ;
    USE SIGNAL ;
    PORT
      LAYER M5 ;
        RECT  20.22 0 20.244 0.192 ;
    END
  END t1[77]
  PIN t1[780]
    DIRECTION OUTPUT ;
    USE SIGNAL ;
    PORT
      LAYER M5 ;
        RECT  185.436 0 185.46 0.192 ;
    END
  END t1[780]
  PIN t1[781]
    DIRECTION OUTPUT ;
    USE SIGNAL ;
    PORT
      LAYER M5 ;
        RECT  185.676 0 185.7 0.192 ;
    END
  END t1[781]
  PIN t1[782]
    DIRECTION OUTPUT ;
    USE SIGNAL ;
    PORT
      LAYER M5 ;
        RECT  185.916 0 185.94 0.192 ;
    END
  END t1[782]
  PIN t1[783]
    DIRECTION OUTPUT ;
    USE SIGNAL ;
    PORT
      LAYER M5 ;
        RECT  186.156 0 186.18 0.192 ;
    END
  END t1[783]
  PIN t1[784]
    DIRECTION OUTPUT ;
    USE SIGNAL ;
    PORT
      LAYER M5 ;
        RECT  186.348 0 186.372 0.192 ;
    END
  END t1[784]
  PIN t1[785]
    DIRECTION OUTPUT ;
    USE SIGNAL ;
    PORT
      LAYER M5 ;
        RECT  186.588 0 186.612 0.192 ;
    END
  END t1[785]
  PIN t1[786]
    DIRECTION OUTPUT ;
    USE SIGNAL ;
    PORT
      LAYER M5 ;
        RECT  186.828 0 186.852 0.192 ;
    END
  END t1[786]
  PIN t1[787]
    DIRECTION OUTPUT ;
    USE SIGNAL ;
    PORT
      LAYER M5 ;
        RECT  187.068 0 187.092 0.192 ;
    END
  END t1[787]
  PIN t1[788]
    DIRECTION OUTPUT ;
    USE SIGNAL ;
    PORT
      LAYER M5 ;
        RECT  187.308 0 187.332 0.192 ;
    END
  END t1[788]
  PIN t1[789]
    DIRECTION OUTPUT ;
    USE SIGNAL ;
    PORT
      LAYER M5 ;
        RECT  187.548 0 187.572 0.192 ;
    END
  END t1[789]
  PIN t1[78]
    DIRECTION OUTPUT ;
    USE SIGNAL ;
    PORT
      LAYER M5 ;
        RECT  20.46 0 20.484 0.192 ;
    END
  END t1[78]
  PIN t1[790]
    DIRECTION OUTPUT ;
    USE SIGNAL ;
    PORT
      LAYER M5 ;
        RECT  187.788 0 187.812 0.192 ;
    END
  END t1[790]
  PIN t1[791]
    DIRECTION OUTPUT ;
    USE SIGNAL ;
    PORT
      LAYER M5 ;
        RECT  188.028 0 188.052 0.192 ;
    END
  END t1[791]
  PIN t1[792]
    DIRECTION OUTPUT ;
    USE SIGNAL ;
    PORT
      LAYER M5 ;
        RECT  188.268 0 188.292 0.192 ;
    END
  END t1[792]
  PIN t1[793]
    DIRECTION OUTPUT ;
    USE SIGNAL ;
    PORT
      LAYER M5 ;
        RECT  188.508 0 188.532 0.192 ;
    END
  END t1[793]
  PIN t1[794]
    DIRECTION OUTPUT ;
    USE SIGNAL ;
    PORT
      LAYER M5 ;
        RECT  188.7 0 188.724 0.192 ;
    END
  END t1[794]
  PIN t1[795]
    DIRECTION OUTPUT ;
    USE SIGNAL ;
    PORT
      LAYER M5 ;
        RECT  188.94 0 188.964 0.192 ;
    END
  END t1[795]
  PIN t1[796]
    DIRECTION OUTPUT ;
    USE SIGNAL ;
    PORT
      LAYER M5 ;
        RECT  189.18 0 189.204 0.192 ;
    END
  END t1[796]
  PIN t1[797]
    DIRECTION OUTPUT ;
    USE SIGNAL ;
    PORT
      LAYER M5 ;
        RECT  189.42 0 189.444 0.192 ;
    END
  END t1[797]
  PIN t1[798]
    DIRECTION OUTPUT ;
    USE SIGNAL ;
    PORT
      LAYER M5 ;
        RECT  189.66 0 189.684 0.192 ;
    END
  END t1[798]
  PIN t1[799]
    DIRECTION OUTPUT ;
    USE SIGNAL ;
    PORT
      LAYER M5 ;
        RECT  189.9 0 189.924 0.192 ;
    END
  END t1[799]
  PIN t1[79]
    DIRECTION OUTPUT ;
    USE SIGNAL ;
    PORT
      LAYER M5 ;
        RECT  20.652 0 20.676 0.192 ;
    END
  END t1[79]
  PIN t1[7]
    DIRECTION OUTPUT ;
    USE SIGNAL ;
    PORT
      LAYER M5 ;
        RECT  3.756 0 3.78 0.192 ;
    END
  END t1[7]
  PIN t1[800]
    DIRECTION OUTPUT ;
    USE SIGNAL ;
    PORT
      LAYER M5 ;
        RECT  190.14 0 190.164 0.192 ;
    END
  END t1[800]
  PIN t1[801]
    DIRECTION OUTPUT ;
    USE SIGNAL ;
    PORT
      LAYER M5 ;
        RECT  190.38 0 190.404 0.192 ;
    END
  END t1[801]
  PIN t1[802]
    DIRECTION OUTPUT ;
    USE SIGNAL ;
    PORT
      LAYER M5 ;
        RECT  190.62 0 190.644 0.192 ;
    END
  END t1[802]
  PIN t1[803]
    DIRECTION OUTPUT ;
    USE SIGNAL ;
    PORT
      LAYER M5 ;
        RECT  190.86 0 190.884 0.192 ;
    END
  END t1[803]
  PIN t1[804]
    DIRECTION OUTPUT ;
    USE SIGNAL ;
    PORT
      LAYER M5 ;
        RECT  191.052 0 191.076 0.192 ;
    END
  END t1[804]
  PIN t1[805]
    DIRECTION OUTPUT ;
    USE SIGNAL ;
    PORT
      LAYER M5 ;
        RECT  191.292 0 191.316 0.192 ;
    END
  END t1[805]
  PIN t1[806]
    DIRECTION OUTPUT ;
    USE SIGNAL ;
    PORT
      LAYER M5 ;
        RECT  191.532 0 191.556 0.192 ;
    END
  END t1[806]
  PIN t1[807]
    DIRECTION OUTPUT ;
    USE SIGNAL ;
    PORT
      LAYER M5 ;
        RECT  191.772 0 191.796 0.192 ;
    END
  END t1[807]
  PIN t1[808]
    DIRECTION OUTPUT ;
    USE SIGNAL ;
    PORT
      LAYER M5 ;
        RECT  192.012 0 192.036 0.192 ;
    END
  END t1[808]
  PIN t1[809]
    DIRECTION OUTPUT ;
    USE SIGNAL ;
    PORT
      LAYER M5 ;
        RECT  192.252 0 192.276 0.192 ;
    END
  END t1[809]
  PIN t1[80]
    DIRECTION OUTPUT ;
    USE SIGNAL ;
    PORT
      LAYER M5 ;
        RECT  20.892 0 20.916 0.192 ;
    END
  END t1[80]
  PIN t1[810]
    DIRECTION OUTPUT ;
    USE SIGNAL ;
    PORT
      LAYER M5 ;
        RECT  192.492 0 192.516 0.192 ;
    END
  END t1[810]
  PIN t1[811]
    DIRECTION OUTPUT ;
    USE SIGNAL ;
    PORT
      LAYER M5 ;
        RECT  192.732 0 192.756 0.192 ;
    END
  END t1[811]
  PIN t1[812]
    DIRECTION OUTPUT ;
    USE SIGNAL ;
    PORT
      LAYER M5 ;
        RECT  192.972 0 192.996 0.192 ;
    END
  END t1[812]
  PIN t1[813]
    DIRECTION OUTPUT ;
    USE SIGNAL ;
    PORT
      LAYER M5 ;
        RECT  193.164 0 193.188 0.192 ;
    END
  END t1[813]
  PIN t1[814]
    DIRECTION OUTPUT ;
    USE SIGNAL ;
    PORT
      LAYER M5 ;
        RECT  193.404 0 193.428 0.192 ;
    END
  END t1[814]
  PIN t1[815]
    DIRECTION OUTPUT ;
    USE SIGNAL ;
    PORT
      LAYER M5 ;
        RECT  193.644 0 193.668 0.192 ;
    END
  END t1[815]
  PIN t1[816]
    DIRECTION OUTPUT ;
    USE SIGNAL ;
    PORT
      LAYER M5 ;
        RECT  193.884 0 193.908 0.192 ;
    END
  END t1[816]
  PIN t1[817]
    DIRECTION OUTPUT ;
    USE SIGNAL ;
    PORT
      LAYER M5 ;
        RECT  194.124 0 194.148 0.192 ;
    END
  END t1[817]
  PIN t1[818]
    DIRECTION OUTPUT ;
    USE SIGNAL ;
    PORT
      LAYER M5 ;
        RECT  194.364 0 194.388 0.192 ;
    END
  END t1[818]
  PIN t1[819]
    DIRECTION OUTPUT ;
    USE SIGNAL ;
    PORT
      LAYER M5 ;
        RECT  194.604 0 194.628 0.192 ;
    END
  END t1[819]
  PIN t1[81]
    DIRECTION OUTPUT ;
    USE SIGNAL ;
    PORT
      LAYER M5 ;
        RECT  21.132 0 21.156 0.192 ;
    END
  END t1[81]
  PIN t1[820]
    DIRECTION OUTPUT ;
    USE SIGNAL ;
    PORT
      LAYER M5 ;
        RECT  194.844 0 194.868 0.192 ;
    END
  END t1[820]
  PIN t1[821]
    DIRECTION OUTPUT ;
    USE SIGNAL ;
    PORT
      LAYER M5 ;
        RECT  195.084 0 195.108 0.192 ;
    END
  END t1[821]
  PIN t1[822]
    DIRECTION OUTPUT ;
    USE SIGNAL ;
    PORT
      LAYER M5 ;
        RECT  195.324 0 195.348 0.192 ;
    END
  END t1[822]
  PIN t1[823]
    DIRECTION OUTPUT ;
    USE SIGNAL ;
    PORT
      LAYER M5 ;
        RECT  195.516 0 195.54 0.192 ;
    END
  END t1[823]
  PIN t1[824]
    DIRECTION OUTPUT ;
    USE SIGNAL ;
    PORT
      LAYER M5 ;
        RECT  195.756 0 195.78 0.192 ;
    END
  END t1[824]
  PIN t1[825]
    DIRECTION OUTPUT ;
    USE SIGNAL ;
    PORT
      LAYER M5 ;
        RECT  195.996 0 196.02 0.192 ;
    END
  END t1[825]
  PIN t1[826]
    DIRECTION OUTPUT ;
    USE SIGNAL ;
    PORT
      LAYER M5 ;
        RECT  196.236 0 196.26 0.192 ;
    END
  END t1[826]
  PIN t1[827]
    DIRECTION OUTPUT ;
    USE SIGNAL ;
    PORT
      LAYER M5 ;
        RECT  196.476 0 196.5 0.192 ;
    END
  END t1[827]
  PIN t1[828]
    DIRECTION OUTPUT ;
    USE SIGNAL ;
    PORT
      LAYER M5 ;
        RECT  196.716 0 196.74 0.192 ;
    END
  END t1[828]
  PIN t1[829]
    DIRECTION OUTPUT ;
    USE SIGNAL ;
    PORT
      LAYER M5 ;
        RECT  196.956 0 196.98 0.192 ;
    END
  END t1[829]
  PIN t1[82]
    DIRECTION OUTPUT ;
    USE SIGNAL ;
    PORT
      LAYER M5 ;
        RECT  21.372 0 21.396 0.192 ;
    END
  END t1[82]
  PIN t1[830]
    DIRECTION OUTPUT ;
    USE SIGNAL ;
    PORT
      LAYER M5 ;
        RECT  197.196 0 197.22 0.192 ;
    END
  END t1[830]
  PIN t1[831]
    DIRECTION OUTPUT ;
    USE SIGNAL ;
    PORT
      LAYER M5 ;
        RECT  197.436 0 197.46 0.192 ;
    END
  END t1[831]
  PIN t1[832]
    DIRECTION OUTPUT ;
    USE SIGNAL ;
    PORT
      LAYER M5 ;
        RECT  197.676 0 197.7 0.192 ;
    END
  END t1[832]
  PIN t1[833]
    DIRECTION OUTPUT ;
    USE SIGNAL ;
    PORT
      LAYER M5 ;
        RECT  197.868 0 197.892 0.192 ;
    END
  END t1[833]
  PIN t1[834]
    DIRECTION OUTPUT ;
    USE SIGNAL ;
    PORT
      LAYER M5 ;
        RECT  198.108 0 198.132 0.192 ;
    END
  END t1[834]
  PIN t1[835]
    DIRECTION OUTPUT ;
    USE SIGNAL ;
    PORT
      LAYER M5 ;
        RECT  198.348 0 198.372 0.192 ;
    END
  END t1[835]
  PIN t1[836]
    DIRECTION OUTPUT ;
    USE SIGNAL ;
    PORT
      LAYER M5 ;
        RECT  198.588 0 198.612 0.192 ;
    END
  END t1[836]
  PIN t1[837]
    DIRECTION OUTPUT ;
    USE SIGNAL ;
    PORT
      LAYER M5 ;
        RECT  198.828 0 198.852 0.192 ;
    END
  END t1[837]
  PIN t1[838]
    DIRECTION OUTPUT ;
    USE SIGNAL ;
    PORT
      LAYER M5 ;
        RECT  199.068 0 199.092 0.192 ;
    END
  END t1[838]
  PIN t1[839]
    DIRECTION OUTPUT ;
    USE SIGNAL ;
    PORT
      LAYER M5 ;
        RECT  199.308 0 199.332 0.192 ;
    END
  END t1[839]
  PIN t1[83]
    DIRECTION OUTPUT ;
    USE SIGNAL ;
    PORT
      LAYER M5 ;
        RECT  21.612 0 21.636 0.192 ;
    END
  END t1[83]
  PIN t1[840]
    DIRECTION OUTPUT ;
    USE SIGNAL ;
    PORT
      LAYER M5 ;
        RECT  199.548 0 199.572 0.192 ;
    END
  END t1[840]
  PIN t1[841]
    DIRECTION OUTPUT ;
    USE SIGNAL ;
    PORT
      LAYER M5 ;
        RECT  199.788 0 199.812 0.192 ;
    END
  END t1[841]
  PIN t1[842]
    DIRECTION OUTPUT ;
    USE SIGNAL ;
    PORT
      LAYER M5 ;
        RECT  199.98 0 200.004 0.192 ;
    END
  END t1[842]
  PIN t1[843]
    DIRECTION OUTPUT ;
    USE SIGNAL ;
    PORT
      LAYER M5 ;
        RECT  200.22 0 200.244 0.192 ;
    END
  END t1[843]
  PIN t1[844]
    DIRECTION OUTPUT ;
    USE SIGNAL ;
    PORT
      LAYER M5 ;
        RECT  200.46 0 200.484 0.192 ;
    END
  END t1[844]
  PIN t1[845]
    DIRECTION OUTPUT ;
    USE SIGNAL ;
    PORT
      LAYER M5 ;
        RECT  200.7 0 200.724 0.192 ;
    END
  END t1[845]
  PIN t1[846]
    DIRECTION OUTPUT ;
    USE SIGNAL ;
    PORT
      LAYER M5 ;
        RECT  200.94 0 200.964 0.192 ;
    END
  END t1[846]
  PIN t1[847]
    DIRECTION OUTPUT ;
    USE SIGNAL ;
    PORT
      LAYER M5 ;
        RECT  201.18 0 201.204 0.192 ;
    END
  END t1[847]
  PIN t1[848]
    DIRECTION OUTPUT ;
    USE SIGNAL ;
    PORT
      LAYER M5 ;
        RECT  201.42 0 201.444 0.192 ;
    END
  END t1[848]
  PIN t1[849]
    DIRECTION OUTPUT ;
    USE SIGNAL ;
    PORT
      LAYER M5 ;
        RECT  201.66 0 201.684 0.192 ;
    END
  END t1[849]
  PIN t1[84]
    DIRECTION OUTPUT ;
    USE SIGNAL ;
    PORT
      LAYER M5 ;
        RECT  21.852 0 21.876 0.192 ;
    END
  END t1[84]
  PIN t1[850]
    DIRECTION OUTPUT ;
    USE SIGNAL ;
    PORT
      LAYER M5 ;
        RECT  201.9 0 201.924 0.192 ;
    END
  END t1[850]
  PIN t1[851]
    DIRECTION OUTPUT ;
    USE SIGNAL ;
    PORT
      LAYER M5 ;
        RECT  202.14 0 202.164 0.192 ;
    END
  END t1[851]
  PIN t1[852]
    DIRECTION OUTPUT ;
    USE SIGNAL ;
    PORT
      LAYER M5 ;
        RECT  202.332 0 202.356 0.192 ;
    END
  END t1[852]
  PIN t1[853]
    DIRECTION OUTPUT ;
    USE SIGNAL ;
    PORT
      LAYER M5 ;
        RECT  202.572 0 202.596 0.192 ;
    END
  END t1[853]
  PIN t1[854]
    DIRECTION OUTPUT ;
    USE SIGNAL ;
    PORT
      LAYER M5 ;
        RECT  202.812 0 202.836 0.192 ;
    END
  END t1[854]
  PIN t1[855]
    DIRECTION OUTPUT ;
    USE SIGNAL ;
    PORT
      LAYER M5 ;
        RECT  203.052 0 203.076 0.192 ;
    END
  END t1[855]
  PIN t1[856]
    DIRECTION OUTPUT ;
    USE SIGNAL ;
    PORT
      LAYER M5 ;
        RECT  203.292 0 203.316 0.192 ;
    END
  END t1[856]
  PIN t1[857]
    DIRECTION OUTPUT ;
    USE SIGNAL ;
    PORT
      LAYER M5 ;
        RECT  203.532 0 203.556 0.192 ;
    END
  END t1[857]
  PIN t1[858]
    DIRECTION OUTPUT ;
    USE SIGNAL ;
    PORT
      LAYER M5 ;
        RECT  203.772 0 203.796 0.192 ;
    END
  END t1[858]
  PIN t1[859]
    DIRECTION OUTPUT ;
    USE SIGNAL ;
    PORT
      LAYER M5 ;
        RECT  204.012 0 204.036 0.192 ;
    END
  END t1[859]
  PIN t1[85]
    DIRECTION OUTPUT ;
    USE SIGNAL ;
    PORT
      LAYER M5 ;
        RECT  22.092 0 22.116 0.192 ;
    END
  END t1[85]
  PIN t1[860]
    DIRECTION OUTPUT ;
    USE SIGNAL ;
    PORT
      LAYER M5 ;
        RECT  204.252 0 204.276 0.192 ;
    END
  END t1[860]
  PIN t1[861]
    DIRECTION OUTPUT ;
    USE SIGNAL ;
    PORT
      LAYER M5 ;
        RECT  204.492 0 204.516 0.192 ;
    END
  END t1[861]
  PIN t1[862]
    DIRECTION OUTPUT ;
    USE SIGNAL ;
    PORT
      LAYER M5 ;
        RECT  204.684 0 204.708 0.192 ;
    END
  END t1[862]
  PIN t1[863]
    DIRECTION OUTPUT ;
    USE SIGNAL ;
    PORT
      LAYER M5 ;
        RECT  204.924 0 204.948 0.192 ;
    END
  END t1[863]
  PIN t1[864]
    DIRECTION OUTPUT ;
    USE SIGNAL ;
    PORT
      LAYER M5 ;
        RECT  205.164 0 205.188 0.192 ;
    END
  END t1[864]
  PIN t1[865]
    DIRECTION OUTPUT ;
    USE SIGNAL ;
    PORT
      LAYER M5 ;
        RECT  205.404 0 205.428 0.192 ;
    END
  END t1[865]
  PIN t1[866]
    DIRECTION OUTPUT ;
    USE SIGNAL ;
    PORT
      LAYER M5 ;
        RECT  205.644 0 205.668 0.192 ;
    END
  END t1[866]
  PIN t1[867]
    DIRECTION OUTPUT ;
    USE SIGNAL ;
    PORT
      LAYER M5 ;
        RECT  205.884 0 205.908 0.192 ;
    END
  END t1[867]
  PIN t1[868]
    DIRECTION OUTPUT ;
    USE SIGNAL ;
    PORT
      LAYER M5 ;
        RECT  206.124 0 206.148 0.192 ;
    END
  END t1[868]
  PIN t1[869]
    DIRECTION OUTPUT ;
    USE SIGNAL ;
    PORT
      LAYER M5 ;
        RECT  206.364 0 206.388 0.192 ;
    END
  END t1[869]
  PIN t1[86]
    DIRECTION OUTPUT ;
    USE SIGNAL ;
    PORT
      LAYER M5 ;
        RECT  22.332 0 22.356 0.192 ;
    END
  END t1[86]
  PIN t1[870]
    DIRECTION OUTPUT ;
    USE SIGNAL ;
    PORT
      LAYER M5 ;
        RECT  206.604 0 206.628 0.192 ;
    END
  END t1[870]
  PIN t1[871]
    DIRECTION OUTPUT ;
    USE SIGNAL ;
    PORT
      LAYER M5 ;
        RECT  206.796 0 206.82 0.192 ;
    END
  END t1[871]
  PIN t1[872]
    DIRECTION OUTPUT ;
    USE SIGNAL ;
    PORT
      LAYER M5 ;
        RECT  207.036 0 207.06 0.192 ;
    END
  END t1[872]
  PIN t1[873]
    DIRECTION OUTPUT ;
    USE SIGNAL ;
    PORT
      LAYER M5 ;
        RECT  207.276 0 207.3 0.192 ;
    END
  END t1[873]
  PIN t1[874]
    DIRECTION OUTPUT ;
    USE SIGNAL ;
    PORT
      LAYER M5 ;
        RECT  207.516 0 207.54 0.192 ;
    END
  END t1[874]
  PIN t1[875]
    DIRECTION OUTPUT ;
    USE SIGNAL ;
    PORT
      LAYER M5 ;
        RECT  207.756 0 207.78 0.192 ;
    END
  END t1[875]
  PIN t1[876]
    DIRECTION OUTPUT ;
    USE SIGNAL ;
    PORT
      LAYER M5 ;
        RECT  207.996 0 208.02 0.192 ;
    END
  END t1[876]
  PIN t1[877]
    DIRECTION OUTPUT ;
    USE SIGNAL ;
    PORT
      LAYER M5 ;
        RECT  208.236 0 208.26 0.192 ;
    END
  END t1[877]
  PIN t1[878]
    DIRECTION OUTPUT ;
    USE SIGNAL ;
    PORT
      LAYER M5 ;
        RECT  208.476 0 208.5 0.192 ;
    END
  END t1[878]
  PIN t1[879]
    DIRECTION OUTPUT ;
    USE SIGNAL ;
    PORT
      LAYER M5 ;
        RECT  208.716 0 208.74 0.192 ;
    END
  END t1[879]
  PIN t1[87]
    DIRECTION OUTPUT ;
    USE SIGNAL ;
    PORT
      LAYER M5 ;
        RECT  22.572 0 22.596 0.192 ;
    END
  END t1[87]
  PIN t1[880]
    DIRECTION OUTPUT ;
    USE SIGNAL ;
    PORT
      LAYER M5 ;
        RECT  208.956 0 208.98 0.192 ;
    END
  END t1[880]
  PIN t1[881]
    DIRECTION OUTPUT ;
    USE SIGNAL ;
    PORT
      LAYER M5 ;
        RECT  209.148 0 209.172 0.192 ;
    END
  END t1[881]
  PIN t1[882]
    DIRECTION OUTPUT ;
    USE SIGNAL ;
    PORT
      LAYER M5 ;
        RECT  209.388 0 209.412 0.192 ;
    END
  END t1[882]
  PIN t1[883]
    DIRECTION OUTPUT ;
    USE SIGNAL ;
    PORT
      LAYER M5 ;
        RECT  209.628 0 209.652 0.192 ;
    END
  END t1[883]
  PIN t1[884]
    DIRECTION OUTPUT ;
    USE SIGNAL ;
    PORT
      LAYER M5 ;
        RECT  209.868 0 209.892 0.192 ;
    END
  END t1[884]
  PIN t1[885]
    DIRECTION OUTPUT ;
    USE SIGNAL ;
    PORT
      LAYER M5 ;
        RECT  210.108 0 210.132 0.192 ;
    END
  END t1[885]
  PIN t1[886]
    DIRECTION OUTPUT ;
    USE SIGNAL ;
    PORT
      LAYER M5 ;
        RECT  210.348 0 210.372 0.192 ;
    END
  END t1[886]
  PIN t1[887]
    DIRECTION OUTPUT ;
    USE SIGNAL ;
    PORT
      LAYER M5 ;
        RECT  210.588 0 210.612 0.192 ;
    END
  END t1[887]
  PIN t1[888]
    DIRECTION OUTPUT ;
    USE SIGNAL ;
    PORT
      LAYER M5 ;
        RECT  210.828 0 210.852 0.192 ;
    END
  END t1[888]
  PIN t1[889]
    DIRECTION OUTPUT ;
    USE SIGNAL ;
    PORT
      LAYER M5 ;
        RECT  211.068 0 211.092 0.192 ;
    END
  END t1[889]
  PIN t1[88]
    DIRECTION OUTPUT ;
    USE SIGNAL ;
    PORT
      LAYER M5 ;
        RECT  22.812 0 22.836 0.192 ;
    END
  END t1[88]
  PIN t1[890]
    DIRECTION OUTPUT ;
    USE SIGNAL ;
    PORT
      LAYER M5 ;
        RECT  211.308 0 211.332 0.192 ;
    END
  END t1[890]
  PIN t1[891]
    DIRECTION OUTPUT ;
    USE SIGNAL ;
    PORT
      LAYER M5 ;
        RECT  211.5 0 211.524 0.192 ;
    END
  END t1[891]
  PIN t1[892]
    DIRECTION OUTPUT ;
    USE SIGNAL ;
    PORT
      LAYER M5 ;
        RECT  211.74 0 211.764 0.192 ;
    END
  END t1[892]
  PIN t1[893]
    DIRECTION OUTPUT ;
    USE SIGNAL ;
    PORT
      LAYER M5 ;
        RECT  211.98 0 212.004 0.192 ;
    END
  END t1[893]
  PIN t1[894]
    DIRECTION OUTPUT ;
    USE SIGNAL ;
    PORT
      LAYER M5 ;
        RECT  212.22 0 212.244 0.192 ;
    END
  END t1[894]
  PIN t1[895]
    DIRECTION OUTPUT ;
    USE SIGNAL ;
    PORT
      LAYER M5 ;
        RECT  212.46 0 212.484 0.192 ;
    END
  END t1[895]
  PIN t1[896]
    DIRECTION OUTPUT ;
    USE SIGNAL ;
    PORT
      LAYER M5 ;
        RECT  212.7 0 212.724 0.192 ;
    END
  END t1[896]
  PIN t1[897]
    DIRECTION OUTPUT ;
    USE SIGNAL ;
    PORT
      LAYER M5 ;
        RECT  212.94 0 212.964 0.192 ;
    END
  END t1[897]
  PIN t1[898]
    DIRECTION OUTPUT ;
    USE SIGNAL ;
    PORT
      LAYER M5 ;
        RECT  213.18 0 213.204 0.192 ;
    END
  END t1[898]
  PIN t1[899]
    DIRECTION OUTPUT ;
    USE SIGNAL ;
    PORT
      LAYER M5 ;
        RECT  213.42 0 213.444 0.192 ;
    END
  END t1[899]
  PIN t1[89]
    DIRECTION OUTPUT ;
    USE SIGNAL ;
    PORT
      LAYER M5 ;
        RECT  23.004 0 23.028 0.192 ;
    END
  END t1[89]
  PIN t1[8]
    DIRECTION OUTPUT ;
    USE SIGNAL ;
    PORT
      LAYER M5 ;
        RECT  3.996 0 4.02 0.192 ;
    END
  END t1[8]
  PIN t1[900]
    DIRECTION OUTPUT ;
    USE SIGNAL ;
    PORT
      LAYER M5 ;
        RECT  213.612 0 213.636 0.192 ;
    END
  END t1[900]
  PIN t1[901]
    DIRECTION OUTPUT ;
    USE SIGNAL ;
    PORT
      LAYER M5 ;
        RECT  213.852 0 213.876 0.192 ;
    END
  END t1[901]
  PIN t1[90]
    DIRECTION OUTPUT ;
    USE SIGNAL ;
    PORT
      LAYER M5 ;
        RECT  23.244 0 23.268 0.192 ;
    END
  END t1[90]
  PIN t1[91]
    DIRECTION OUTPUT ;
    USE SIGNAL ;
    PORT
      LAYER M5 ;
        RECT  23.484 0 23.508 0.192 ;
    END
  END t1[91]
  PIN t1[92]
    DIRECTION OUTPUT ;
    USE SIGNAL ;
    PORT
      LAYER M5 ;
        RECT  23.724 0 23.748 0.192 ;
    END
  END t1[92]
  PIN t1[93]
    DIRECTION OUTPUT ;
    USE SIGNAL ;
    PORT
      LAYER M5 ;
        RECT  23.964 0 23.988 0.192 ;
    END
  END t1[93]
  PIN t1[94]
    DIRECTION OUTPUT ;
    USE SIGNAL ;
    PORT
      LAYER M5 ;
        RECT  24.204 0 24.228 0.192 ;
    END
  END t1[94]
  PIN t1[95]
    DIRECTION OUTPUT ;
    USE SIGNAL ;
    PORT
      LAYER M5 ;
        RECT  24.444 0 24.468 0.192 ;
    END
  END t1[95]
  PIN t1[96]
    DIRECTION OUTPUT ;
    USE SIGNAL ;
    PORT
      LAYER M5 ;
        RECT  24.684 0 24.708 0.192 ;
    END
  END t1[96]
  PIN t1[97]
    DIRECTION OUTPUT ;
    USE SIGNAL ;
    PORT
      LAYER M5 ;
        RECT  24.924 0 24.948 0.192 ;
    END
  END t1[97]
  PIN t1[98]
    DIRECTION OUTPUT ;
    USE SIGNAL ;
    PORT
      LAYER M5 ;
        RECT  25.116 0 25.14 0.192 ;
    END
  END t1[98]
  PIN t1[99]
    DIRECTION OUTPUT ;
    USE SIGNAL ;
    PORT
      LAYER M5 ;
        RECT  25.356 0 25.38 0.192 ;
    END
  END t1[99]
  PIN t1[9]
    DIRECTION OUTPUT ;
    USE SIGNAL ;
    PORT
      LAYER M5 ;
        RECT  4.236 0 4.26 0.192 ;
    END
  END t1[9]
  PIN VDD
    DIRECTION INOUT ;
    USE POWER ;
    PORT
      LAYER M5 ;
        RECT  209.556 4.311 209.676 168.489 ;
        RECT  205.236 4.311 205.356 168.489 ;
        RECT  200.916 4.311 201.036 168.489 ;
        RECT  196.596 4.311 196.716 168.489 ;
        RECT  192.276 4.311 192.396 168.489 ;
        RECT  187.956 4.311 188.076 168.489 ;
        RECT  183.636 4.311 183.756 168.489 ;
        RECT  179.316 4.311 179.436 168.489 ;
        RECT  174.996 4.311 175.116 168.489 ;
        RECT  170.676 4.311 170.796 168.489 ;
        RECT  166.356 4.311 166.476 168.489 ;
        RECT  162.036 4.311 162.156 168.489 ;
        RECT  157.716 4.311 157.836 168.489 ;
        RECT  153.396 4.311 153.516 168.489 ;
        RECT  149.076 4.311 149.196 168.489 ;
        RECT  144.756 4.311 144.876 168.489 ;
        RECT  140.436 4.311 140.556 168.489 ;
        RECT  136.116 4.311 136.236 168.489 ;
        RECT  131.796 4.311 131.916 168.489 ;
        RECT  127.476 4.311 127.596 168.489 ;
        RECT  123.156 4.311 123.276 168.489 ;
        RECT  118.836 4.311 118.956 168.489 ;
        RECT  114.516 4.311 114.636 168.489 ;
        RECT  110.196 4.311 110.316 168.489 ;
        RECT  105.876 4.311 105.996 168.489 ;
        RECT  101.556 4.311 101.676 168.489 ;
        RECT  97.236 4.311 97.356 168.489 ;
        RECT  92.916 4.311 93.036 168.489 ;
        RECT  88.596 4.311 88.716 168.489 ;
        RECT  84.276 4.311 84.396 168.489 ;
        RECT  79.956 4.311 80.076 168.489 ;
        RECT  75.636 4.311 75.756 168.489 ;
        RECT  71.316 4.311 71.436 168.489 ;
        RECT  66.996 4.311 67.116 168.489 ;
        RECT  62.676 4.311 62.796 168.489 ;
        RECT  58.356 4.311 58.476 168.489 ;
        RECT  54.036 4.311 54.156 168.489 ;
        RECT  49.716 4.311 49.836 168.489 ;
        RECT  45.396 4.311 45.516 168.489 ;
        RECT  41.076 4.311 41.196 168.489 ;
        RECT  36.756 4.311 36.876 168.489 ;
        RECT  32.436 4.311 32.556 168.489 ;
        RECT  28.116 4.311 28.236 168.489 ;
        RECT  23.796 4.311 23.916 168.489 ;
        RECT  19.476 4.311 19.596 168.489 ;
        RECT  15.156 4.311 15.276 168.489 ;
        RECT  10.836 4.311 10.956 168.489 ;
        RECT  6.516 4.311 6.636 168.489 ;
    END
  END VDD
  PIN VSS
    DIRECTION INOUT ;
    USE GROUND ;
    PORT
      LAYER M5 ;
        RECT  209.364 4.297 209.484 168.503 ;
        RECT  205.044 4.297 205.164 168.503 ;
        RECT  200.724 4.297 200.844 168.503 ;
        RECT  196.404 4.297 196.524 168.503 ;
        RECT  192.084 4.297 192.204 168.503 ;
        RECT  187.764 4.297 187.884 168.503 ;
        RECT  183.444 4.297 183.564 168.503 ;
        RECT  179.124 4.297 179.244 168.503 ;
        RECT  174.804 4.297 174.924 168.503 ;
        RECT  170.484 4.297 170.604 168.503 ;
        RECT  166.164 4.297 166.284 168.503 ;
        RECT  161.844 4.297 161.964 168.503 ;
        RECT  157.524 4.297 157.644 168.503 ;
        RECT  153.204 4.297 153.324 168.503 ;
        RECT  148.884 4.297 149.004 168.503 ;
        RECT  144.564 4.297 144.684 168.503 ;
        RECT  140.244 4.297 140.364 168.503 ;
        RECT  135.924 4.297 136.044 168.503 ;
        RECT  131.604 4.297 131.724 168.503 ;
        RECT  127.284 4.297 127.404 168.503 ;
        RECT  122.964 4.297 123.084 168.503 ;
        RECT  118.644 4.297 118.764 168.503 ;
        RECT  114.324 4.297 114.444 168.489 ;
        RECT  110.004 4.297 110.124 168.489 ;
        RECT  105.684 4.297 105.804 168.489 ;
        RECT  101.364 4.297 101.484 168.489 ;
        RECT  97.044 4.297 97.164 168.489 ;
        RECT  92.724 4.297 92.844 168.489 ;
        RECT  88.404 4.297 88.524 168.489 ;
        RECT  84.084 4.297 84.204 168.489 ;
        RECT  79.764 4.297 79.884 168.489 ;
        RECT  75.444 4.297 75.564 168.489 ;
        RECT  71.124 4.297 71.244 168.489 ;
        RECT  66.804 4.297 66.924 168.489 ;
        RECT  62.484 4.297 62.604 168.489 ;
        RECT  58.164 4.297 58.284 168.489 ;
        RECT  53.844 4.297 53.964 168.489 ;
        RECT  49.524 4.297 49.644 168.489 ;
        RECT  45.204 4.297 45.324 168.489 ;
        RECT  40.884 4.297 41.004 168.489 ;
        RECT  36.564 4.297 36.684 168.489 ;
        RECT  32.244 4.297 32.364 168.489 ;
        RECT  27.924 4.297 28.044 168.489 ;
        RECT  23.604 4.297 23.724 168.489 ;
        RECT  19.284 4.297 19.404 168.489 ;
        RECT  14.964 4.297 15.084 168.503 ;
        RECT  10.644 4.297 10.764 168.503 ;
        RECT  6.324 4.297 6.444 168.503 ;
    END
  END VSS
  OBS
    LAYER RVTN ;
     RECT  0 0 216 172.157 ;
    LAYER RVTP ;
     RECT  0 0 216 172.157 ;
    LAYER M1 ;
     RECT  0 0 216 172.157 ;
    LAYER M2 ;
     RECT  0 0 216 172.157 ;
    LAYER M3 ;
     RECT  0 0 216 172.157 ;
    LAYER M4 ;
     RECT  0 0 216 172.157 ;
    LAYER M5 ;
     RECT  0 0 216 172.157 ;
  END
END qkd_ectlk_q3
END LIBRARY
